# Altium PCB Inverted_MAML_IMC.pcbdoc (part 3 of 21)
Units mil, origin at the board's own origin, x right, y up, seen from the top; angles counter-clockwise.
Board outline 7677.1 x 6771.6 mil, 6 copper layers (Top Layer, Inner1, Inner2, Inner3, Inner4, Bottom Layer), stack 60.7 mil thick; 2732 components, 1531 nets, 7765 pads, 3701 vias.

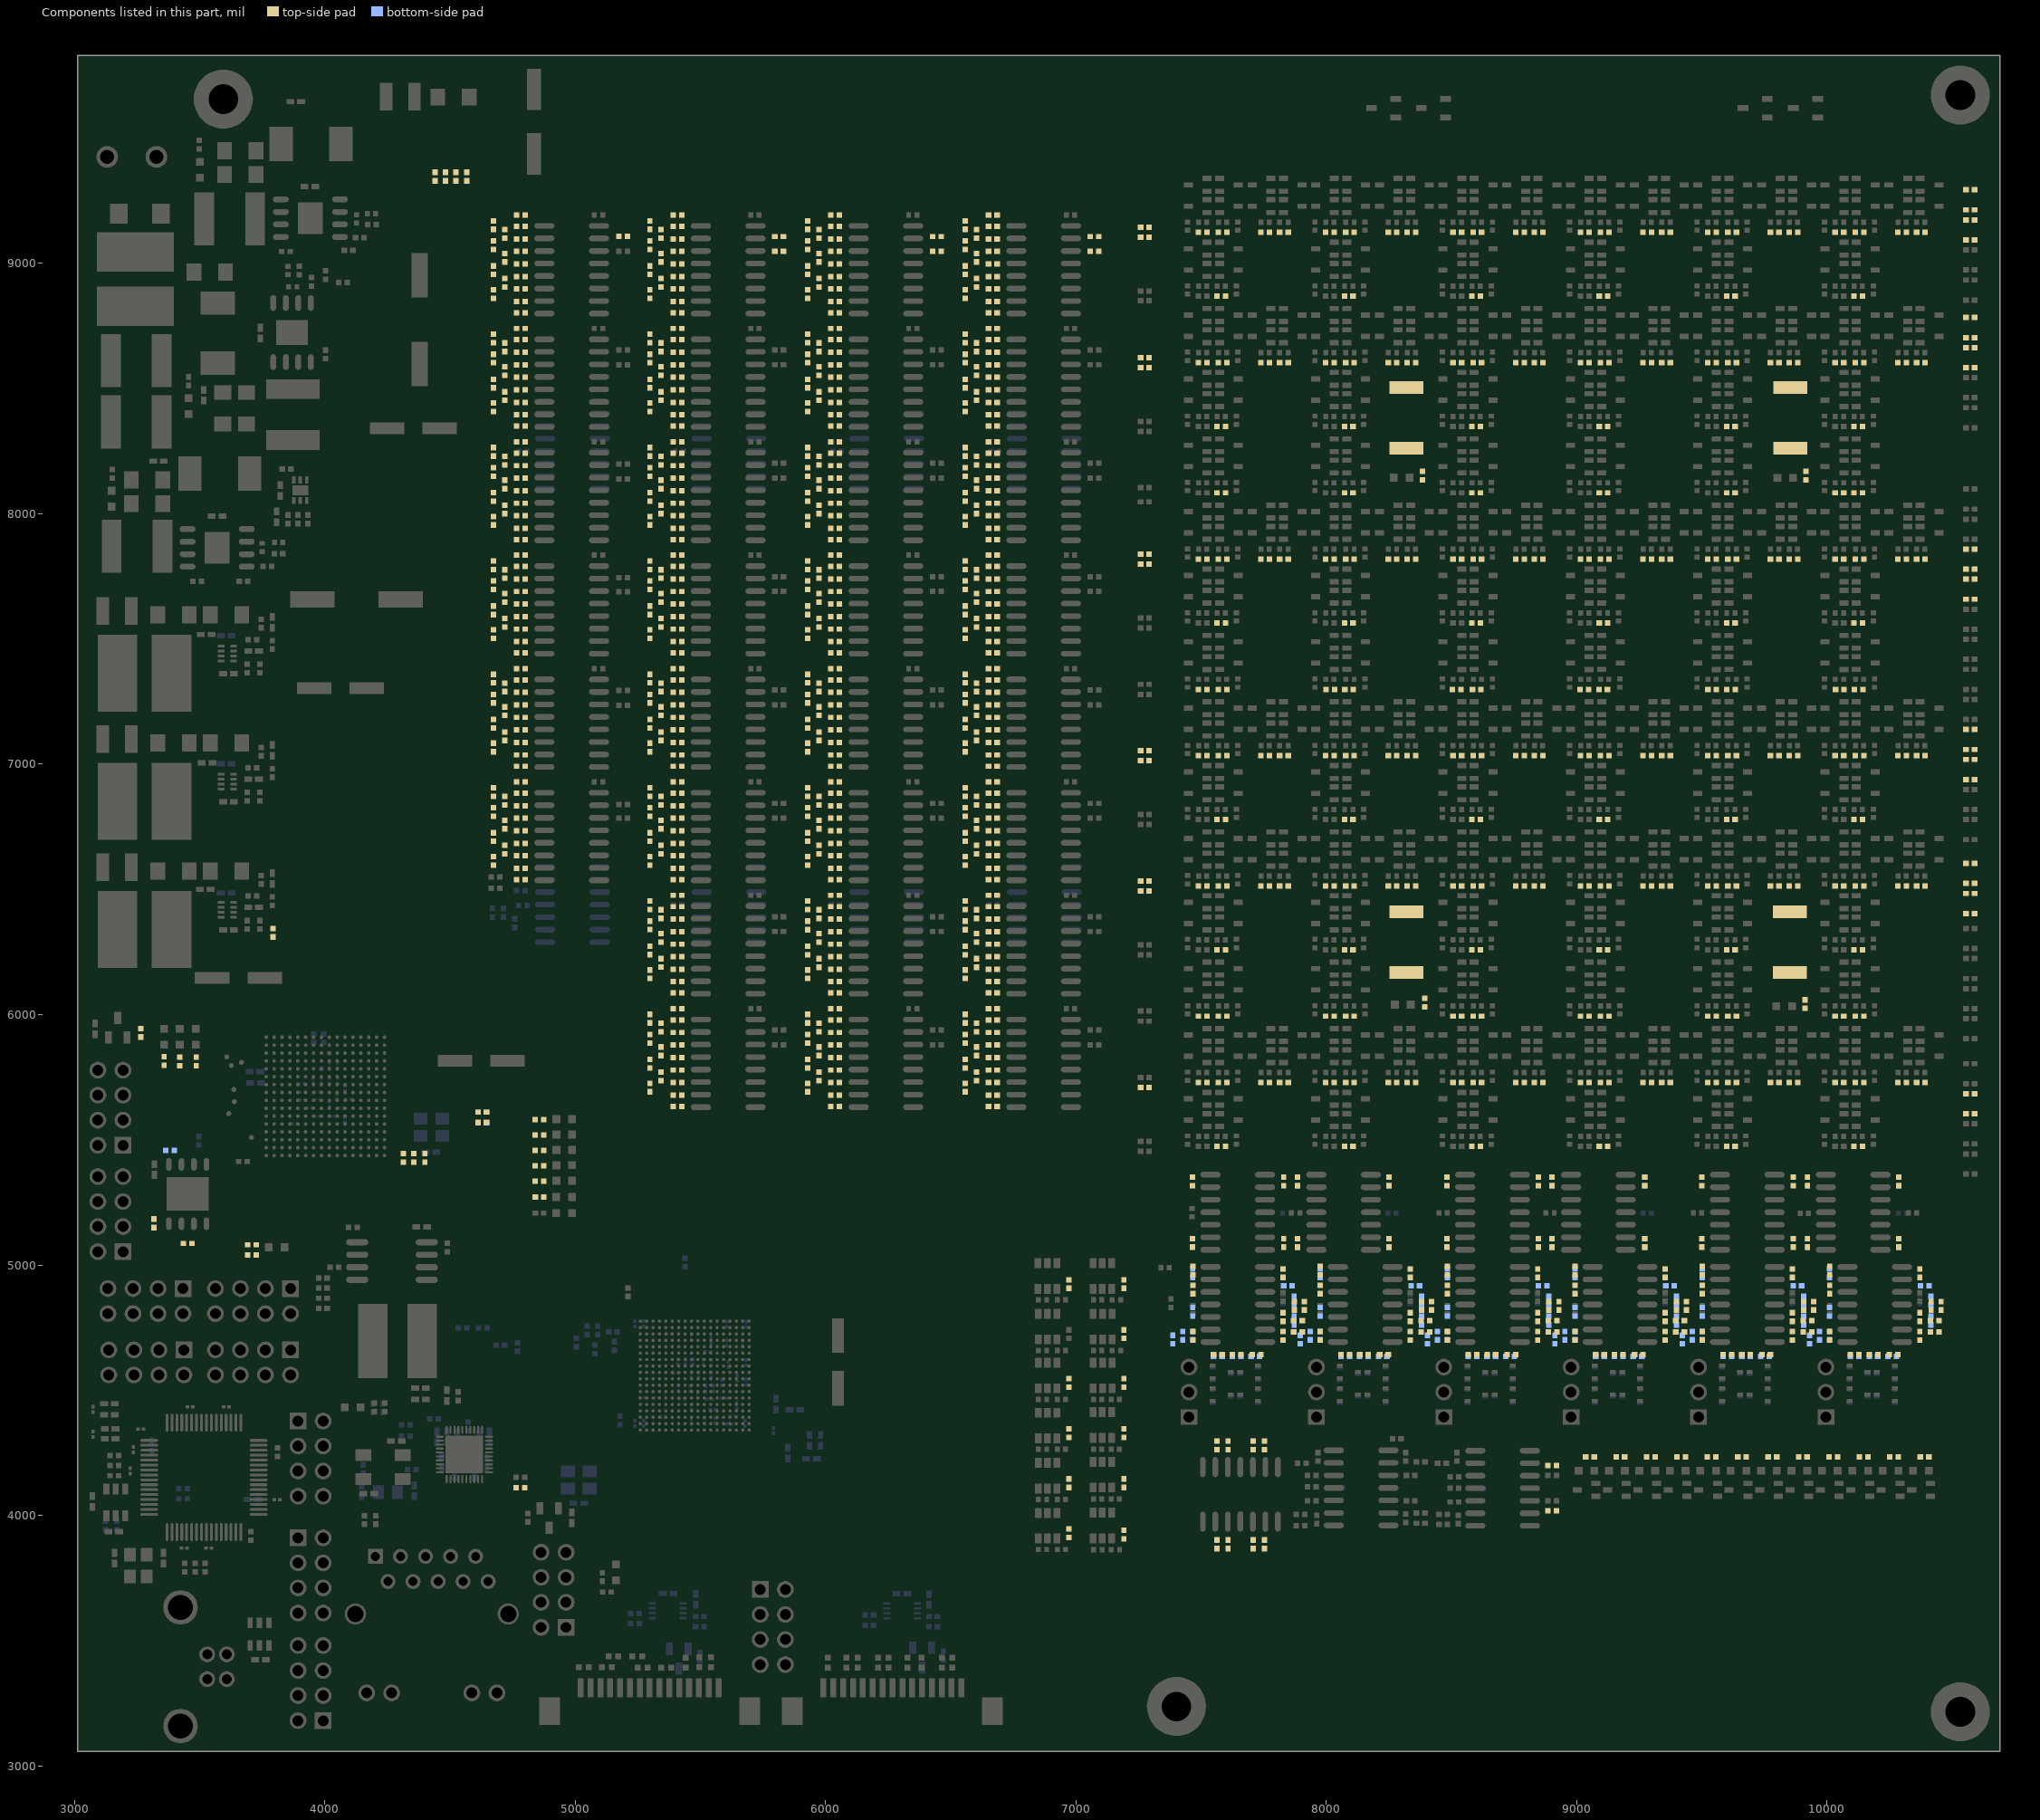
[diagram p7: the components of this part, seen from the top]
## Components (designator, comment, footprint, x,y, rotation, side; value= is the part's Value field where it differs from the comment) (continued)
R1$CBB9/CBB42 "1MΩ" R0402#2 10049.7,8083.7 r180 top
R1$CBB15 "1kΩ" R0402#1 7607.9,3884.5 r270 top
R1$CBB16/CBB1 "20kΩ" R0402#2 4783.8,8395.1 r180 top
R1$CBB16/CBB2 "20kΩ" R0402#2 4783.8,8847.8 r180 top
R1$CBB16/CBB3 "20kΩ" R0402#2 4783.8,7942.3 r180 top
R1$CBB16/CBB4 "20kΩ" R0402#2 4783.8,7489.5 r180 top
R1$CBB16/CBB5 "20kΩ" R0402#2 4783.8,7036.8 r180 top
R1$CBB16/CBB6 "20kΩ" R0402#2 4783.8,6584.1 r180 top
R1$CBB17/CBB1 "20kΩ" R0402#2 5408.8,8847.8 r180 top
R1$CBB17/CBB2 "20kΩ" R0402#2 5408.8,8395.1 r180 top
R1$CBB17/CBB3 "20kΩ" R0402#2 5408.8,7942.3 r180 top
R1$CBB17/CBB4 "20kΩ" R0402#2 5408.8,7489.6 r180 top
R1$CBB17/CBB5 "20kΩ" R0402#2 5408.8,7036.8 r180 top
R1$CBB17/CBB6 "20kΩ" R0402#2 5408.8,6584 r180 top
R1$CBB17/CBB7 "20kΩ" R0402#2 5408.8,6131.3 r180 top
R1$CBB17/CBB8 "20kΩ" R0402#2 5408.8,5678.5 r180 top
R1$CBB18/CBB1 "20kΩ" R0402#3 6038.7,8847.8 r180 top
R1$CBB18/CBB2 "20kΩ" R0402#3 6038.7,8395.1 r180 top
R1$CBB18/CBB3 "20kΩ" R0402#3 6038.7,7942.3 r180 top
R1$CBB18/CBB4 "20kΩ" R0402#3 6038.7,7489.6 r180 top
R1$CBB18/CBB5 "20kΩ" R0402#3 6038.7,7036.8 r180 top
R1$CBB18/CBB6 "20kΩ" R0402#3 6038.7,6584 r180 top
R1$CBB18/CBB7 "20kΩ" R0402#3 6038.7,6131.3 r180 top
R1$CBB18/CBB8 "20kΩ" R0402#3 6038.7,5678.5 r180 top
R1$CBB19/CBB1 "1MΩ" R0402#2 7756.2,9123.7 r180 top
R1$CBB19/CBB2 "1MΩ" R0402#2 7756.2,8603.7 r180 top
R1$CBB19/CBB3 "1MΩ" R0402#2 7756.2,7818.7 r180 top
R1$CBB19/CBB4 "1MΩ" R0402#2 7756.2,7033.7 r180 top
R1$CBB19/CBB5 "1MΩ" R0402#2 7756.2,6513.7 r180 top
R1$CBB19/CBB6 "1MΩ" R0402#2 7756.2,5728.7 r180 top
R1$CBB19/CBB7 "1MΩ" R0402#2 8264.9,9123.7 r180 top
R1$CBB19/CBB8 "1MΩ" R0402#2 8264.9,8603.7 r180 top
R1$CBB19/CBB9 "1MΩ" R0402#2 8264.9,7818.7 r180 top
R1$CBB19/CBB10 "1MΩ" R0402#2 8264.9,7033.7 r180 top
R1$CBB19/CBB11 "1MΩ" R0402#2 8264.9,6513.7 r180 top
R1$CBB19/CBB12 "1MΩ" R0402#2 8264.9,5728.7 r180 top
R1$CBB19/CBB13 "1MΩ" R0402#2 8773.6,9123.7 r180 top
R1$CBB19/CBB14 "1MΩ" R0402#2 8773.6,8603.7 r180 top
R1$CBB19/CBB15 "1MΩ" R0402#2 8773.6,7818.7 r180 top
R1$CBB19/CBB16 "1MΩ" R0402#2 8773.6,7033.7 r180 top
R1$CBB19/CBB17 "1MΩ" R0402#2 8773.6,6513.7 r180 top
R1$CBB19/CBB18 "1MΩ" R0402#2 8773.6,5728.7 r180 top
R1$CBB19/CBB19 "1MΩ" R0402#2 9282.3,9123.7 r180 top
R1$CBB19/CBB20 "1MΩ" R0402#2 9282.3,8603.7 r180 top
R1$CBB19/CBB21 "1MΩ" R0402#2 9282.3,7818.7 r180 top
R1$CBB19/CBB22 "1MΩ" R0402#2 9282.3,7033.7 r180 top
R1$CBB19/CBB23 "1MΩ" R0402#2 9282.3,6513.7 r180 top
R1$CBB19/CBB24 "1MΩ" R0402#2 9282.3,5728.7 r180 top
R1$CBB19/CBB25 "1MΩ" R0402#2 9791,9123.7 r180 top
R1$CBB19/CBB26 "1MΩ" R0402#2 9791,8603.7 r180 top
R1$CBB19/CBB27 "1MΩ" R0402#2 9791,7818.7 r180 top
R1$CBB19/CBB28 "1MΩ" R0402#2 9791,7033.7 r180 top
R1$CBB19/CBB29 "1MΩ" R0402#2 9791,6513.7 r180 top
R1$CBB19/CBB30 "1MΩ" R0402#2 9791,5728.7 r180 top
R1$CBB19/CBB31 "1MΩ" R0402#2 10299.7,9123.7 r180 top
R1$CBB19/CBB32 "1MΩ" R0402#2 10299.7,8603.7 r180 top
R1$CBB19/CBB33 "1MΩ" R0402#2 10299.7,7818.7 r180 top
R1$CBB19/CBB34 "1MΩ" R0402#2 10299.7,7033.7 r180 top
R1$CBB19/CBB35 "1MΩ" R0402#2 10299.7,6513.7 r180 top
R1$CBB19/CBB36 "1MΩ" R0402#2 10299.7,5728.7 r180 top
R1$CBB20/CBB1 "20kΩ" R0402#1 6668.6,8847.8 r180 top
R1$CBB20/CBB2 "20kΩ" R0402#1 6668.6,8395.1 r180 top
R1$CBB20/CBB3 "20kΩ" R0402#1 6668.6,7942.3 r180 top
R1$CBB20/CBB4 "20kΩ" R0402#1 6668.6,7489.6 r180 top
R1$CBB20/CBB5 "20kΩ" R0402#1 6668.6,7036.8 r180 top
R1$CBB20/CBB6 "20kΩ" R0402#1 6668.6,6584 r180 top
R1$CBB20/CBB7 "20kΩ" R0402#1 6668.6,6131.3 r180 top
R1$CBB20/CBB8 "20kΩ" R0402#1 6668.6,5678.5 r180 top
R1$CBB21 "100Ω" R0402#2 7192.1,4723.7 r90 top
R1$CBB22 "470Ω" R0402#1 4858.2,5271.4 r180 top
R1$CBB22/CBB2 "4.7kΩ" R0402#2 4781.8,4110.3 r0 top
R1$CBB23 "10kΩ" R0402#2 3265.9,5927.4 r90 top
R1$CBB49/CBB1 "1MΩ" R0402#2 7506.2,9123.7 r180 top
R1$CBB49/CBB2 "1MΩ" R0402#2 7506.2,8603.7 r180 top
R1$CBB49/CBB3 "1MΩ" R0402#2 7506.2,7818.7 r180 top
R1$CBB49/CBB4 "1MΩ" R0402#2 7506.2,7033.7 r180 top
R1$CBB49/CBB5 "1MΩ" R0402#2 7506.2,6513.7 r180 top
R1$CBB49/CBB6 "1MΩ" R0402#2 7506.2,5728.7 r180 top
R1$CBB49/CBB7 "1MΩ" R0402#2 8014.9,9123.7 r180 top
R1$CBB49/CBB8 "1MΩ" R0402#2 8014.9,8603.7 r180 top
R1$CBB49/CBB9 "1MΩ" R0402#2 8014.9,7818.7 r180 top
R1$CBB49/CBB10 "1MΩ" R0402#2 8014.9,7033.7 r180 top
R1$CBB49/CBB11 "1MΩ" R0402#2 8014.9,6513.7 r180 top
R1$CBB49/CBB12 "1MΩ" R0402#2 8014.9,5728.7 r180 top
R1$CBB49/CBB13 "1MΩ" R0402#2 8523.6,9123.7 r180 top
R1$CBB49/CBB14 "1MΩ" R0402#2 8523.6,8603.7 r180 top
R1$CBB49/CBB15 "1MΩ" R0402#2 8523.6,7818.7 r180 top
R1$CBB49/CBB16 "1MΩ" R0402#2 8523.6,7033.7 r180 top
R1$CBB49/CBB17 "1MΩ" R0402#2 8523.6,6513.7 r180 top
R1$CBB49/CBB18 "1MΩ" R0402#2 8523.6,5728.7 r180 top
R1$CBB49/CBB19 "1MΩ" R0402#2 9032.3,9123.7 r180 top
R1$CBB49/CBB20 "1MΩ" R0402#2 9032.3,8603.7 r180 top
R1$CBB49/CBB21 "1MΩ" R0402#2 9032.3,7818.7 r180 top
R1$CBB49/CBB22 "1MΩ" R0402#2 9032.3,7033.7 r180 top
R1$CBB49/CBB23 "1MΩ" R0402#2 9032.3,6513.7 r180 top
R1$CBB49/CBB24 "1MΩ" R0402#2 9032.3,5728.7 r180 top
R1$CBB49/CBB25 "1MΩ" R0402#2 9541,9123.7 r180 top
R1$CBB49/CBB26 "1MΩ" R0402#2 9541,8603.7 r180 top
R1$CBB49/CBB27 "1MΩ" R0402#2 9541,7818.7 r180 top
R1$CBB49/CBB28 "1MΩ" R0402#2 9541,7033.7 r180 top
R1$CBB49/CBB29 "1MΩ" R0402#2 9541,6513.7 r180 top
R1$CBB49/CBB30 "1MΩ" R0402#2 9541,5728.7 r180 top
R1$CBB49/CBB31 "1MΩ" R0402#2 10049.7,9123.7 r180 top
R1$CBB49/CBB32 "1MΩ" R0402#2 10049.7,8603.7 r180 top
R1$CBB49/CBB33 "1MΩ" R0402#2 10049.7,7818.7 r180 top
R1$CBB49/CBB34 "1MΩ" R0402#2 10049.7,7033.7 r180 top
R1$CBB49/CBB35 "1MΩ" R0402#2 10049.7,6513.7 r180 top
R1$CBB49/CBB36 "1MΩ" R0402#2 10049.7,5728.7 r180 top
R1$CBB49/CBB37 "1MΩ" R0402#2 7506.2,5993.7 r180 top
R1$CBB49/CBB38 "1MΩ" R0402#2 8014.9,5993.7 r180 top
R1$CBB49/CBB39 "1MΩ" R0402#2 8523.6,5993.7 r180 top
R1$CBB49/CBB40 "1MΩ" R0402#2 9032.3,5993.7 r180 top
R1$CBB49/CBB41 "1MΩ" R0402#2 9541,5993.7 r180 top
R1$CBB49/CBB42 "1MΩ" R0402#2 10049.7,5993.7 r180 top
R1$CBB49/CBB43 "330kΩ" R0402#1 7586.2,7298.7 r0 top
R1$CBB49/CBB44 "330kΩ" R0402#1 8091.2,7298.7 r0 top
R1$CBB49/CBB45 "330kΩ" R0402#1 8601.2,7298.7 r0 top
R1$CBB49/CBB46 "330kΩ" R0402#1 9106.2,7298.7 r0 top
R1$CBB49/CBB47 "330kΩ" R0402#1 9616.2,7298.7 r0 top
R1$CBB49/CBB48 "330kΩ" R0402#1 10126.2,7298.7 r0 top
R2 "120Ω" R0402#1 10572.1,9093.7 r180 top
R2$CBB1 "1.2kΩ" R0402#2 7467.1,4717.2 r270 top
R2$CBB2 "1.2kΩ" R0402#2 7975.8,4717.2 r270 top
R2$CBB3 "1.2kΩ" R0402#2 8484.5,4717.2 r270 top
R2$CBB4 "1.2kΩ" R0402#2 8993.2,4717.2 r270 top
R2$CBB5 "1.2kΩ" R0402#2 9501.9,4717.2 r270 top
R2$CBB6 "1.2kΩ" R0402#2 10010.6,4717.2 r270 top
R2$CBB7 "100Ω" R0402#2 6972.1,4328.7 r90 top
R2$CBB8 "1.2kΩ" R0402#2 7641.9,4635.4 r0 bottom
R2$CBB9/CBB1 "1MΩ" R0402#1 7581.2,8868.7 r0 top
R2$CBB9/CBB2 "1MΩ" R0402#1 7581.2,8348.7 r0 top
R2$CBB9/CBB3 "1MΩ" R0402#1 7581.2,7563.7 r0 top
R2$CBB9/CBB4 "1MΩ" R0402#1 7581.2,6778.7 r0 top
R2$CBB9/CBB5 "1MΩ" R0402#1 7581.2,6258.7 r0 top
R2$CBB9/CBB6 "1MΩ" R0402#1 7581.2,5473.7 r0 top
R2$CBB9/CBB7 "1MΩ" R0402#1 8089.9,8868.7 r0 top
R2$CBB9/CBB8 "1MΩ" R0402#1 8089.9,8348.7 r0 top
R2$CBB9/CBB9 "1MΩ" R0402#1 8089.9,7563.7 r0 top
R2$CBB9/CBB10 "1MΩ" R0402#1 8089.9,6778.7 r0 top
R2$CBB9/CBB11 "1MΩ" R0402#1 8089.9,6258.7 r0 top
R2$CBB9/CBB12 "1MΩ" R0402#1 8089.9,5473.7 r0 top
R2$CBB9/CBB13 "1MΩ" R0402#1 8598.6,8868.7 r0 top
R2$CBB9/CBB14 "1MΩ" R0402#1 8598.6,8348.7 r0 top
R2$CBB9/CBB15 "1MΩ" R0402#1 8598.6,7563.7 r0 top
R2$CBB9/CBB16 "1MΩ" R0402#1 8598.6,6778.7 r0 top
R2$CBB9/CBB17 "1MΩ" R0402#1 8598.6,6258.7 r0 top
R2$CBB9/CBB18 "1MΩ" R0402#1 8598.6,5473.7 r0 top
R2$CBB9/CBB19 "1MΩ" R0402#1 9107.3,8868.7 r0 top
R2$CBB9/CBB20 "1MΩ" R0402#1 9107.3,8348.7 r0 top
R2$CBB9/CBB21 "1MΩ" R0402#1 9107.3,7563.7 r0 top
R2$CBB9/CBB22 "1MΩ" R0402#1 9107.3,6778.7 r0 top
R2$CBB9/CBB23 "1MΩ" R0402#1 9107.3,6258.7 r0 top
R2$CBB9/CBB24 "1MΩ" R0402#1 9107.3,5473.7 r0 top
R2$CBB9/CBB25 "1MΩ" R0402#1 9616,8868.7 r0 top
R2$CBB9/CBB26 "1MΩ" R0402#1 9616,8348.7 r0 top
R2$CBB9/CBB27 "1MΩ" R0402#1 9616,7563.7 r0 top
R2$CBB9/CBB28 "1MΩ" R0402#1 9616,6778.7 r0 top
R2$CBB9/CBB29 "1MΩ" R0402#1 9616,6258.7 r0 top
R2$CBB9/CBB30 "1MΩ" R0402#1 9616,5473.7 r0 top
R2$CBB9/CBB31 "1MΩ" R0402#1 10124.7,8868.7 r0 top
R2$CBB9/CBB32 "1MΩ" R0402#1 10124.7,8348.7 r0 top
R2$CBB9/CBB33 "1MΩ" R0402#1 10124.7,7563.7 r0 top
R2$CBB9/CBB34 "1MΩ" R0402#1 10124.7,6778.7 r0 top
R2$CBB9/CBB35 "1MΩ" R0402#1 10124.7,6258.7 r0 top
R2$CBB9/CBB36 "1MΩ" R0402#1 10124.7,5473.7 r0 top
R2$CBB9/CBB37 "1MΩ" R0402#1 7581.2,8083.7 r0 top
R2$CBB9/CBB38 "1MΩ" R0402#1 8089.9,8083.7 r0 top
R2$CBB9/CBB39 "1MΩ" R0402#1 8598.6,8083.7 r0 top
R2$CBB9/CBB40 "1MΩ" R0402#1 9107.3,8083.7 r0 top
R2$CBB9/CBB41 "1MΩ" R0402#1 9616,8083.7 r0 top
R2$CBB9/CBB42 "1MΩ" R0402#1 10124.7,8083.7 r0 top
R2$CBB10 "1.2kΩ" R0402#2 8150.6,4635.4 r0 bottom
R2$CBB11 "1.2kΩ" R0402#2 8659.3,4635.4 r0 bottom
R2$CBB12 "1.2kΩ" R0402#2 9168,4635.4 r0 bottom
R2$CBB13 "1.2kΩ" R0402#2 9676.7,4635.4 r0 bottom
R2$CBB14 "1.2kΩ" R0402#2 10185.4,4635.4 r0 bottom
R2$CBB15 "3.9kΩ" R0402#1 7562.9,3884.5 r270 top
R2$CBB16/CBB1 "10kΩ" R0402#1 4673.8,8700.1 r90 top
R2$CBB16/CBB2 "10kΩ" R0402#2 4673.8,9152.8 r90 top
R2$CBB16/CBB3 "10kΩ" R0402#2 4673.8,8247.3 r90 top
R2$CBB16/CBB4 "10kΩ" R0402#2 4673.8,7794.5 r90 top
R2$CBB16/CBB5 "10kΩ" R0402#3 4673.8,7341.8 r90 top
R2$CBB16/CBB6 "10kΩ" R0402#1 4673.8,6889.1 r90 top
R2$CBB17/CBB1 "10kΩ" R0402#2 5298.8,9152.8 r90 top
R2$CBB17/CBB2 "10kΩ" R0402#1 5298.8,8700.1 r90 top
R2$CBB17/CBB3 "10kΩ" R0402#2 5298.8,8247.3 r90 top
R2$CBB17/CBB4 "10kΩ" R0402#1 5298.8,7794.6 r90 top
R2$CBB17/CBB5 "10kΩ" R0402#3 5298.8,7341.8 r90 top
R2$CBB17/CBB6 "10kΩ" R0402#2 5298.8,6889 r90 top
R2$CBB17/CBB7 "10kΩ" R0402#3 5298.8,6436.3 r90 top
R2$CBB17/CBB8 "10kΩ" R0402#2 5298.8,5983.5 r90 top
R2$CBB18/CBB1 "10kΩ" R0402#2 5928.7,9152.8 r90 top
R2$CBB18/CBB2 "10kΩ" R0402#1 5928.7,8700.1 r90 top
R2$CBB18/CBB3 "10kΩ" R0402#2 5928.7,8247.3 r90 top
R2$CBB18/CBB4 "10kΩ" R0402#1 5928.7,7794.6 r90 top
R2$CBB18/CBB5 "10kΩ" R0402#3 5928.7,7341.8 r90 top
R2$CBB18/CBB6 "10kΩ" R0402#2 5928.7,6889 r90 top
R2$CBB18/CBB7 "10kΩ" R0402#1 5928.7,6436.3 r90 top
R2$CBB18/CBB8 "10kΩ" R0402#2 5928.7,5983.5 r90 top
R2$CBB19/CBB1 "1MΩ" R0402#1 7831.2,9123.7 r0 top
R2$CBB19/CBB2 "1MΩ" R0402#1 7831.2,8603.7 r0 top
R2$CBB19/CBB3 "1MΩ" R0402#1 7831.2,7818.7 r0 top
R2$CBB19/CBB4 "1MΩ" R0402#1 7831.2,7033.7 r0 top
R2$CBB19/CBB5 "1MΩ" R0402#1 7831.2,6513.7 r0 top
R2$CBB19/CBB6 "1MΩ" R0402#1 7831.2,5728.7 r0 top
R2$CBB19/CBB7 "1MΩ" R0402#1 8339.9,9123.7 r0 top
R2$CBB19/CBB8 "1MΩ" R0402#1 8339.9,8603.7 r0 top
R2$CBB19/CBB9 "1MΩ" R0402#1 8339.9,7818.7 r0 top
R2$CBB19/CBB10 "1MΩ" R0402#1 8339.9,7033.7 r0 top
R2$CBB19/CBB11 "1MΩ" R0402#1 8339.9,6513.7 r0 top
R2$CBB19/CBB12 "1MΩ" R0402#1 8339.9,5728.7 r0 top
R2$CBB19/CBB13 "1MΩ" R0402#1 8848.6,9123.7 r0 top
R2$CBB19/CBB14 "1MΩ" R0402#1 8848.6,8603.7 r0 top
R2$CBB19/CBB15 "1MΩ" R0402#1 8848.6,7818.7 r0 top
R2$CBB19/CBB16 "1MΩ" R0402#1 8848.6,7033.7 r0 top
R2$CBB19/CBB17 "1MΩ" R0402#1 8848.6,6513.7 r0 top
R2$CBB19/CBB18 "1MΩ" R0402#1 8848.6,5728.7 r0 top
R2$CBB19/CBB19 "1MΩ" R0402#1 9357.3,9123.7 r0 top
R2$CBB19/CBB20 "1MΩ" R0402#1 9357.3,8603.7 r0 top
R2$CBB19/CBB21 "1MΩ" R0402#1 9357.3,7818.7 r0 top
R2$CBB19/CBB22 "1MΩ" R0402#1 9357.3,7033.7 r0 top
R2$CBB19/CBB23 "1MΩ" R0402#1 9357.3,6513.7 r0 top
R2$CBB19/CBB24 "1MΩ" R0402#1 9357.3,5728.7 r0 top
R2$CBB19/CBB25 "1MΩ" R0402#1 9866,9123.7 r0 top
R2$CBB19/CBB26 "1MΩ" R0402#1 9866,8603.7 r0 top
R2$CBB19/CBB27 "1MΩ" R0402#1 9866,7818.7 r0 top
R2$CBB19/CBB28 "1MΩ" R0402#1 9866,7033.7 r0 top
R2$CBB19/CBB29 "1MΩ" R0402#1 9866,6513.7 r0 top
R2$CBB19/CBB30 "1MΩ" R0402#1 9866,5728.7 r0 top
R2$CBB19/CBB31 "1MΩ" R0402#1 10374.7,9123.7 r0 top
R2$CBB19/CBB32 "1MΩ" R0402#1 10374.7,8603.7 r0 top
R2$CBB19/CBB33 "1MΩ" R0402#1 10374.7,7818.7 r0 top
R2$CBB19/CBB34 "1MΩ" R0402#1 10374.7,7033.7 r0 top
R2$CBB19/CBB35 "1MΩ" R0402#1 10374.7,6513.7 r0 top
R2$CBB19/CBB36 "1MΩ" R0402#1 10374.7,5728.7 r0 top
R2$CBB20/CBB1 "10kΩ" R0402#2 6558.6,9152.8 r90 top
R2$CBB20/CBB2 "10kΩ" R0402#1 6558.6,8700.1 r90 top
R2$CBB20/CBB3 "10kΩ" R0402#2 6558.6,8247.3 r90 top
R2$CBB20/CBB4 "10kΩ" R0402#1 6558.6,7794.6 r90 top
R2$CBB20/CBB5 "10kΩ" R0402#3 6558.6,7341.8 r90 top
R2$CBB20/CBB6 "10kΩ" R0402#2 6558.6,6889 r90 top
R2$CBB20/CBB7 "10kΩ" R0402#1 6558.6,6436.3 r90 top
R2$CBB20/CBB8 "10kΩ" R0402#2 6558.6,5983.5 r90 top
R2$CBB21 "100Ω" R0402#2 7192.1,4328.7 r90 top
R2$CBB23 "10kΩ" R0402#3 3793.9,6327 r90 top
R2$CBB49/CBB1 "1MΩ" R0402#1 7586.2,9123.7 r0 top
R2$CBB49/CBB2 "1MΩ" R0402#1 7586.2,8603.7 r0 top
R2$CBB49/CBB3 "1MΩ" R0402#1 7586.2,7818.7 r0 top
R2$CBB49/CBB4 "1MΩ" R0402#1 7586.2,7033.7 r0 top
R2$CBB49/CBB5 "1MΩ" R0402#1 7586.2,6513.7 r0 top
R2$CBB49/CBB6 "1MΩ" R0402#1 7586.2,5728.7 r0 top
R2$CBB49/CBB7 "1MΩ" R0402#1 8094.9,9123.7 r0 top
R2$CBB49/CBB8 "1MΩ" R0402#1 8094.9,8603.7 r0 top
R2$CBB49/CBB9 "1MΩ" R0402#1 8094.9,7818.7 r0 top
R2$CBB49/CBB10 "1MΩ" R0402#1 8094.9,7033.7 r0 top
R2$CBB49/CBB11 "1MΩ" R0402#1 8094.9,6513.7 r0 top
R2$CBB49/CBB12 "1MΩ" R0402#1 8094.9,5728.7 r0 top
R2$CBB49/CBB13 "1MΩ" R0402#1 8603.6,9123.7 r0 top
R2$CBB49/CBB14 "1MΩ" R0402#1 8603.6,8603.7 r0 top
R2$CBB49/CBB15 "1MΩ" R0402#1 8603.6,7818.7 r0 top
R2$CBB49/CBB16 "1MΩ" R0402#1 8603.6,7033.7 r0 top
R2$CBB49/CBB17 "1MΩ" R0402#1 8603.6,6513.7 r0 top
R2$CBB49/CBB18 "1MΩ" R0402#1 8603.6,5728.7 r0 top
R2$CBB49/CBB19 "1MΩ" R0402#1 9112.3,9123.7 r0 top
R2$CBB49/CBB20 "1MΩ" R0402#1 9112.3,8603.7 r0 top
R2$CBB49/CBB21 "1MΩ" R0402#1 9112.3,7818.7 r0 top
R2$CBB49/CBB22 "1MΩ" R0402#1 9112.3,7033.7 r0 top
R2$CBB49/CBB23 "1MΩ" R0402#1 9112.3,6513.7 r0 top
R2$CBB49/CBB24 "1MΩ" R0402#1 9112.3,5728.7 r0 top
R2$CBB49/CBB25 "1MΩ" R0402#1 9621,9123.7 r0 top
R2$CBB49/CBB26 "1MΩ" R0402#1 9621,8603.7 r0 top
R2$CBB49/CBB27 "1MΩ" R0402#1 9621,7818.7 r0 top
R2$CBB49/CBB28 "1MΩ" R0402#1 9621,7033.7 r0 top
R2$CBB49/CBB29 "1MΩ" R0402#1 9621,6513.7 r0 top
R2$CBB49/CBB30 "1MΩ" R0402#1 9621,5728.7 r0 top
R2$CBB49/CBB31 "1MΩ" R0402#1 10129.7,9123.7 r0 top
R2$CBB49/CBB32 "1MΩ" R0402#1 10129.7,8603.7 r0 top
R2$CBB49/CBB33 "1MΩ" R0402#1 10129.7,7818.7 r0 top
R2$CBB49/CBB34 "1MΩ" R0402#1 10129.7,7033.7 r0 top
R2$CBB49/CBB35 "1MΩ" R0402#1 10129.7,6513.7 r0 top
R2$CBB49/CBB36 "1MΩ" R0402#1 10129.7,5728.7 r0 top
R2$CBB49/CBB37 "1MΩ" R0402#1 7586.2,5993.7 r0 top
R2$CBB49/CBB38 "1MΩ" R0402#1 8094.9,5993.7 r0 top
R2$CBB49/CBB39 "1MΩ" R0402#1 8603.6,5993.7 r0 top
R2$CBB49/CBB40 "1MΩ" R0402#1 9112.3,5993.7 r0 top
R2$CBB49/CBB41 "1MΩ" R0402#1 9621,5993.7 r0 top
R2$CBB49/CBB42 "1MΩ" R0402#1 10129.7,5993.7 r0 top
R3 "68Ω" R0402#3 7275.6,9103.9 r0 top
R3$CBB1 "910Ω" R0402#2 7827.1,4717.2 r270 top
R3$CBB2 "910Ω" R0402#2 8335.8,4717.2 r270 top
R3$CBB3 "910Ω" R0402#2 8844.5,4717.2 r270 top
R3$CBB4 "910Ω" R0402#2 9353.2,4717.2 r270 top
R3$CBB5 "910Ω" R0402#2 9861.9,4717.2 r270 top
R3$CBB6 "910Ω" R0402#2 10370.6,4717.2 r270 top
R3$CBB7 "100Ω" R0402#2 6972.1,4528.7 r90 top
R3$CBB8 "910Ω" R0402#1 7466.9,4717.6 r270 bottom
R3$CBB9 "100Ω" R0402#2 7885.3,5333.4 r270 top
R3$CBB10 "910Ω" R0402#1 7975.6,4717.6 r270 bottom
R3$CBB11 "910Ω" R0402#1 8484.3,4717.6 r270 bottom
R3$CBB12 "910Ω" R0402#1 8993,4717.6 r270 bottom
R3$CBB13 "910Ω" R0402#1 9501.7,4717.6 r270 bottom
R3$CBB14 "910Ω" R0402#1 10010.4,4717.6 r270 bottom
R3$CBB15 "3.9kΩ" R0402#1 7707.9,3884.5 r270 top
R3$CBB16/CBB1 "20kΩ" R0402#2 4783.8,8445.1 r180 top
R3$CBB16/CBB2 "20kΩ" R0402#2 4783.8,8897.8 r180 top
R3$CBB16/CBB3 "20kΩ" R0402#2 4783.8,7992.3 r180 top
R3$CBB16/CBB4 "20kΩ" R0402#2 4783.8,7539.5 r180 top
R3$CBB16/CBB5 "20kΩ" R0402#2 4783.8,7086.8 r180 top
R3$CBB16/CBB6 "20kΩ" R0402#2 4783.8,6634.1 r180 top
R3$CBB17/CBB1 "20kΩ" R0402#2 5408.8,8897.8 r180 top
R3$CBB17/CBB2 "20kΩ" R0402#2 5408.8,8445.1 r180 top
R3$CBB17/CBB3 "20kΩ" R0402#2 5408.8,7992.3 r180 top
R3$CBB17/CBB4 "20kΩ" R0402#2 5408.8,7539.6 r180 top
R3$CBB17/CBB5 "20kΩ" R0402#2 5408.8,7086.8 r180 top
R3$CBB17/CBB6 "20kΩ" R0402#2 5408.8,6634 r180 top
R3$CBB17/CBB7 "20kΩ" R0402#2 5408.8,6181.3 r180 top
R3$CBB17/CBB8 "20kΩ" R0402#2 5408.8,5728.5 r180 top
R3$CBB18/CBB1 "20kΩ" R0402#3 6038.7,8897.8 r180 top
R3$CBB18/CBB2 "20kΩ" R0402#3 6038.7,8445.1 r180 top
R3$CBB18/CBB3 "20kΩ" R0402#3 6038.7,7992.3 r180 top
R3$CBB18/CBB4 "20kΩ" R0402#3 6038.7,7539.6 r180 top
R3$CBB18/CBB5 "20kΩ" R0402#3 6038.7,7086.8 r180 top
R3$CBB18/CBB6 "20kΩ" R0402#3 6038.7,6634 r180 top
R3$CBB18/CBB7 "20kΩ" R0402#3 6038.7,6181.3 r180 top
R3$CBB18/CBB8 "20kΩ" R0402#3 6038.7,5728.5 r180 top
R3$CBB19 "100Ω" R0402#1 7885.3,5088.4 r90 bottom
R3$CBB20/CBB1 "20kΩ" R0402#1 6668.6,8897.8 r180 top
R3$CBB20/CBB2 "20kΩ" R0402#1 6668.6,8445.1 r180 top
R3$CBB20/CBB3 "20kΩ" R0402#1 6668.6,7992.3 r180 top
R3$CBB20/CBB4 "20kΩ" R0402#1 6668.6,7539.6 r180 top
R3$CBB20/CBB5 "20kΩ" R0402#1 6668.6,7086.8 r180 top
R3$CBB20/CBB6 "20kΩ" R0402#1 6668.6,6634 r180 top
R3$CBB20/CBB7 "20kΩ" R0402#1 6668.6,6181.3 r180 top
R3$CBB20/CBB8 "20kΩ" R0402#1 6668.6,5728.5 r180 top
R3$CBB21 "100Ω" R0402#2 7192.1,4528.7 r90 top
R3$CBB23 "10kΩ" R0402#2 4356.1,5427.5 r270 top
R3$CBB49 "100Ω" R0402#2 7465.3,5333.4 r270 top
R3$CBB49/CBB43 "330kΩ" R0402#2 7506.2,7298.7 r180 top
R3$CBB49/CBB44 "330kΩ" R0402#2 8016.2,7298.7 r180 top
R3$CBB49/CBB45 "330kΩ" R0402#2 8521.2,7298.7 r180 top
R3$CBB49/CBB46 "330kΩ" R0402#2 9031.2,7298.7 r180 top
R3$CBB49/CBB47 "330kΩ" R0402#2 9541.2,7298.7 r180 top
R3$CBB49/CBB48 "330kΩ" R0402#2 10051.2,7298.7 r180 top
R4 "120Ω" R0402#1 10572.1,9173.7 r180 top
R4$CBB1 "1kΩ" R0402#2 7467.1,4902.2 r270 top
R4$CBB2 "1kΩ" R0402#2 7975.8,4902.2 r270 top
R4$CBB3 "1kΩ" R0402#2 8484.5,4902.2 r270 top
R4$CBB4 "1kΩ" R0402#2 8993.2,4902.2 r270 top
R4$CBB5 "1kΩ" R0402#2 9501.9,4902.2 r270 top
R4$CBB6 "1kΩ" R0402#2 10010.6,4902.2 r270 top
R4$CBB7 "100Ω" R0402#2 6972.1,3928.7 r90 top
R4$CBB8 "1kΩ" R0402#1 7871.9,4857.6 r270 bottom
R4$CBB9 "100Ω" R0402#1 7885.3,5088.4 r90 top
R4$CBB10 "1kΩ" R0402#1 8380.6,4857.6 r270 bottom
R4$CBB11 "1kΩ" R0402#1 8889.3,4857.6 r270 bottom
R4$CBB12 "1kΩ" R0402#1 9398,4857.6 r270 bottom
R4$CBB13 "1kΩ" R0402#1 9906.7,4857.6 r270 bottom
R4$CBB14 "1kΩ" R0402#1 10415.4,4857.6 r270 bottom
R4$CBB15 "3.9kΩ" R0402#2 7752.9,4279.5 r90 top
R4$CBB16/CBB1 "20kΩ" R0402#2 4783.8,8495.1 r180 top
R4$CBB16/CBB2 "20kΩ" R0402#2 4783.8,8947.8 r180 top
R4$CBB16/CBB3 "20kΩ" R0402#2 4783.8,8042.3 r180 top
R4$CBB16/CBB4 "20kΩ" R0402#2 4783.8,7589.5 r180 top
R4$CBB16/CBB5 "20kΩ" R0402#2 4783.8,7136.8 r180 top
R4$CBB16/CBB6 "20kΩ" R0402#2 4783.8,6684.1 r180 top
R4$CBB17/CBB1 "20kΩ" R0402#2 5408.8,8947.8 r180 top
R4$CBB17/CBB2 "20kΩ" R0402#2 5408.8,8495.1 r180 top
R4$CBB17/CBB3 "20kΩ" R0402#2 5408.8,8042.3 r180 top
R4$CBB17/CBB4 "20kΩ" R0402#2 5408.8,7589.6 r180 top
R4$CBB17/CBB5 "20kΩ" R0402#2 5408.8,7136.8 r180 top
R4$CBB17/CBB6 "20kΩ" R0402#2 5408.8,6684 r180 top
R4$CBB17/CBB7 "20kΩ" R0402#2 5408.8,6231.3 r180 top
R4$CBB17/CBB8 "20kΩ" R0402#2 5408.8,5778.5 r180 top
R4$CBB18/CBB1 "20kΩ" R0402#3 6038.7,8947.8 r180 top
R4$CBB18/CBB2 "20kΩ" R0402#3 6038.7,8495.1 r180 top
R4$CBB18/CBB3 "20kΩ" R0402#3 6038.7,8042.3 r180 top
R4$CBB18/CBB4 "20kΩ" R0402#3 6038.7,7589.6 r180 top
R4$CBB18/CBB5 "20kΩ" R0402#3 6038.7,7136.8 r180 top
R4$CBB18/CBB6 "20kΩ" R0402#3 6038.7,6684 r180 top
R4$CBB18/CBB7 "20kΩ" R0402#3 6038.7,6231.3 r180 top
R4$CBB18/CBB8 "20kΩ" R0402#3 6038.7,5778.5 r180 top
R4$CBB19 "100Ω" R0402#2 7885.3,5333.4 r270 bottom
R4$CBB20/CBB1 "20kΩ" R0402#1 6668.6,8947.8 r180 top
R4$CBB20/CBB2 "20kΩ" R0402#1 6668.6,8495.1 r180 top
R4$CBB20/CBB3 "20kΩ" R0402#1 6668.6,8042.3 r180 top
R4$CBB20/CBB4 "20kΩ" R0402#1 6668.6,7589.6 r180 top
R4$CBB20/CBB5 "20kΩ" R0402#1 6668.6,7136.8 r180 top
R4$CBB20/CBB6 "20kΩ" R0402#1 6668.6,6684 r180 top
R4$CBB20/CBB7 "20kΩ" R0402#1 6668.6,6231.3 r180 top
R4$CBB20/CBB8 "20kΩ" R0402#1 6668.6,5778.5 r180 top
R4$CBB21 "100Ω" R0402#2 7192.1,3923.7 r90 top
R4$CBB23 "10kΩ" R0402#2 4400.3,5427.5 r270 top
R4$CBB49 "100Ω" R0402#1 7465.3,5088.4 r90 top
R5 "120Ω" R0402#1 10572.1,9213.7 r180 top
R5$CBB1 "1kΩ" R0402#2 7467.1,4977.2 r270 top
R5$CBB2 "1kΩ" R0402#2 7975.8,4977.2 r270 top
R5$CBB3 "1kΩ" R0402#2 8484.5,4977.2 r270 top
R5$CBB4 "1kΩ" R0402#2 8993.2,4977.2 r270 top
R5$CBB5 "1kΩ" R0402#2 9501.9,4977.2 r270 top
R5$CBB6 "1kΩ" R0402#2 10010.6,4977.2 r270 top
R5$CBB7 "100Ω" R0402#2 6972.1,4128.7 r90 top
R5$CBB8 "1kΩ" R0402#2 7846.9,4917.6 r0 bottom
R5$CBB9 "100Ω" R0402#1 8250.3,5088.4 r90 top
R5$CBB10 "1kΩ" R0402#2 8355.6,4917.6 r0 bottom
R5$CBB11 "1kΩ" R0402#2 8864.3,4917.6 r0 bottom
R5$CBB12 "1kΩ" R0402#2 9373,4917.6 r0 bottom
R5$CBB13 "1kΩ" R0402#2 9881.7,4917.6 r0 bottom
R5$CBB14 "1kΩ" R0402#2 10390.4,4917.6 r0 bottom
R5$CBB15 "1kΩ" R0402#1 7752.9,3884.5 r270 top
R5$CBB16/CBB1 "20kΩ" R0402#2 4783.8,8545.1 r180 top
R5$CBB16/CBB2 "20kΩ" R0402#2 4783.8,8997.8 r180 top
R5$CBB16/CBB3 "20kΩ" R0402#2 4783.8,8092.3 r180 top
R5$CBB16/CBB4 "20kΩ" R0402#2 4783.8,7639.5 r180 top
R5$CBB16/CBB5 "20kΩ" R0402#2 4783.8,7186.8 r180 top
R5$CBB16/CBB6 "20kΩ" R0402#2 4783.8,6734.1 r180 top
R5$CBB17/CBB1 "20kΩ" R0402#2 5408.8,8997.8 r180 top
R5$CBB17/CBB2 "20kΩ" R0402#2 5408.8,8545.1 r180 top
R5$CBB17/CBB3 "20kΩ" R0402#2 5408.8,8092.3 r180 top
R5$CBB17/CBB4 "20kΩ" R0402#2 5408.8,7639.6 r180 top
R5$CBB17/CBB5 "20kΩ" R0402#2 5408.8,7186.8 r180 top
R5$CBB17/CBB6 "20kΩ" R0402#2 5408.8,6734 r180 top
R5$CBB17/CBB7 "20kΩ" R0402#2 5408.8,6281.3 r180 top
R5$CBB17/CBB8 "20kΩ" R0402#2 5408.8,5828.5 r180 top
R5$CBB18/CBB1 "20kΩ" R0402#3 6038.7,8997.8 r180 top
R5$CBB18/CBB2 "20kΩ" R0402#3 6038.7,8545.1 r180 top
R5$CBB18/CBB3 "20kΩ" R0402#3 6038.7,8092.3 r180 top
R5$CBB18/CBB4 "20kΩ" R0402#3 6038.7,7639.6 r180 top
R5$CBB18/CBB5 "20kΩ" R0402#3 6038.7,7186.8 r180 top
R5$CBB18/CBB6 "20kΩ" R0402#3 6038.7,6734 r180 top
R5$CBB18/CBB7 "20kΩ" R0402#3 6038.7,6281.3 r180 top
R5$CBB18/CBB8 "20kΩ" R0402#3 6038.7,5828.5 r180 top
R5$CBB19 "100Ω" R0402#2 8250.3,5333.4 r270 bottom
R5$CBB20/CBB1 "20kΩ" R0402#1 6668.6,8997.8 r180 top
R5$CBB20/CBB2 "20kΩ" R0402#1 6668.6,8545.1 r180 top
R5$CBB20/CBB3 "20kΩ" R0402#1 6668.6,8092.3 r180 top
R5$CBB20/CBB4 "20kΩ" R0402#1 6668.6,7639.6 r180 top
R5$CBB20/CBB5 "20kΩ" R0402#1 6668.6,7186.8 r180 top
R5$CBB20/CBB6 "20kΩ" R0402#1 6668.6,6734 r180 top
R5$CBB20/CBB7 "20kΩ" R0402#1 6668.6,6281.3 r180 top
R5$CBB20/CBB8 "20kΩ" R0402#1 6668.6,5828.5 r180 top
R5$CBB21 "100Ω" R0402#2 7192.1,4128.7 r90 top
R5$CBB23 "10kΩ" R0402#1 3318.1,5166.5 r90 top
R5$CBB49 "100Ω" R0402#1 7830.3,5088.4 r90 top
R6 "68Ω" R0402#3 7275.6,9144.1 r0 top
R6$CBB1 "1kΩ" R0402#2 7887.1,4732.2 r0 top
R6$CBB2 "1kΩ" R0402#2 8395.8,4732.2 r0 top
R6$CBB3 "1kΩ" R0402#2 8904.5,4732.2 r0 top
R6$CBB4 "1kΩ" R0402#2 9413.2,4732.2 r0 top
R6$CBB5 "1kΩ" R0402#2 9921.9,4732.2 r0 top
R6$CBB6 "1kΩ" R0402#2 10430.6,4732.2 r0 top
R6$CBB7 "100Ω" R0402#2 6972.1,4923.7 r90 top
R6$CBB8 "1kΩ" R0402#1 7426.9,4717.6 r270 bottom
R6$CBB9 "100Ω" R0402#2 8250.3,5333.4 r270 top
R6$CBB10 "1kΩ" R0402#1 7935.6,4717.6 r270 bottom
R6$CBB11 "1kΩ" R0402#1 8444.3,4717.6 r270 bottom
R6$CBB12 "1kΩ" R0402#1 8953,4717.6 r270 bottom
R6$CBB13 "1kΩ" R0402#1 9461.7,4717.6 r270 bottom
R6$CBB14 "1kΩ" R0402#1 9970.4,4717.6 r270 bottom
R6$CBB15 "3.9kΩ" R0402#2 7562.9,4279.5 r90 top
R6$CBB16/CBB1 "20kΩ" R0402#2 4783.8,8595.1 r180 top
R6$CBB16/CBB2 "20kΩ" R0402#2 4783.8,9047.8 r180 top
R6$CBB16/CBB3 "20kΩ" R0402#2 4783.8,8142.3 r180 top
R6$CBB16/CBB4 "20kΩ" R0402#2 4783.8,7689.5 r180 top
R6$CBB16/CBB5 "20kΩ" R0402#2 4783.8,7236.8 r180 top
R6$CBB16/CBB6 "20kΩ" R0402#2 4783.8,6784.1 r180 top
R6$CBB17/CBB1 "20kΩ" R0402#2 5408.8,9047.8 r180 top
R6$CBB17/CBB2 "20kΩ" R0402#2 5408.8,8595.1 r180 top
R6$CBB17/CBB3 "20kΩ" R0402#2 5408.8,8142.3 r180 top
R6$CBB17/CBB4 "20kΩ" R0402#2 5408.8,7689.6 r180 top
R6$CBB17/CBB5 "20kΩ" R0402#2 5408.8,7236.8 r180 top
R6$CBB17/CBB6 "20kΩ" R0402#2 5408.8,6784 r180 top
R6$CBB17/CBB7 "20kΩ" R0402#2 5408.8,6331.3 r180 top
R6$CBB17/CBB8 "20kΩ" R0402#2 5408.8,5878.5 r180 top
R6$CBB18/CBB1 "20kΩ" R0402#3 6038.7,9047.8 r180 top
R6$CBB18/CBB2 "20kΩ" R0402#3 6038.7,8595.1 r180 top
R6$CBB18/CBB3 "20kΩ" R0402#3 6038.7,8142.3 r180 top
R6$CBB18/CBB4 "20kΩ" R0402#3 6038.7,7689.6 r180 top
R6$CBB18/CBB5 "20kΩ" R0402#3 6038.7,7236.8 r180 top
R6$CBB18/CBB6 "20kΩ" R0402#3 6038.7,6784 r180 top
R6$CBB18/CBB7 "20kΩ" R0402#3 6038.7,6331.3 r180 top
R6$CBB18/CBB8 "20kΩ" R0402#3 6038.7,5878.5 r180 top
R6$CBB19 "100Ω" R0402#1 8250.3,5088.4 r90 bottom
R6$CBB20/CBB1 "20kΩ" R0402#1 6668.6,9047.8 r180 top
R6$CBB20/CBB2 "20kΩ" R0402#1 6668.6,8595.1 r180 top
R6$CBB20/CBB3 "20kΩ" R0402#1 6668.6,8142.3 r180 top
R6$CBB20/CBB4 "20kΩ" R0402#1 6668.6,7689.6 r180 top
R6$CBB20/CBB5 "20kΩ" R0402#1 6668.6,7236.8 r180 top
R6$CBB20/CBB6 "20kΩ" R0402#1 6668.6,6784 r180 top
R6$CBB20/CBB7 "20kΩ" R0402#1 6668.6,6331.3 r180 top
R6$CBB20/CBB8 "20kΩ" R0402#1 6668.6,5878.5 r180 top
R6$CBB21 "100Ω" R0402#2 7192.1,4923.7 r90 top
R6$CBB23 "10kΩ" R0402#2 4629.2,5610.2 r0 top
R6$CBB49 "100Ω" R0402#2 7830.3,5333.4 r270 top
R7 "120Ω" R0402#1 10572.1,9293.7 r180 top
R7$CBB1 "1kΩ" R0402#2 7887.1,4777.2 r0 top
R7$CBB2 "1kΩ" R0402#2 8395.8,4777.2 r0 top
R7$CBB3 "1kΩ" R0402#2 8904.5,4777.2 r0 top
R7$CBB4 "1kΩ" R0402#2 9413.2,4777.2 r0 top
R7$CBB5 "1kΩ" R0402#2 9921.9,4777.2 r0 top
R7$CBB6 "1kΩ" R0402#2 10430.6,4777.2 r0 top
R7$CBB8 "1kΩ" R0402#2 7387.1,4702.2 r270 bottom
R7$CBB9 "100Ω" R0402#2 8902.1,5333.4 r270 top
R7$CBB10 "1kΩ" R0402#2 7895.8,4702.2 r270 bottom
R7$CBB11 "1kΩ" R0402#2 8404.5,4702.2 r270 bottom
R7$CBB12 "1kΩ" R0402#2 8913.2,4702.2 r270 bottom
R7$CBB13 "1kΩ" R0402#2 9421.9,4702.2 r270 bottom
R7$CBB14 "1kΩ" R0402#2 9930.6,4702.2 r270 bottom
R7$CBB15 "3.9kΩ" R0402#2 8902.1,4018.7 r0 top
R7$CBB16/CBB1 "20kΩ" R0402#2 4783.8,8645.1 r180 top
R7$CBB16/CBB2 "20kΩ" R0402#2 4783.8,9097.8 r180 top
R7$CBB16/CBB3 "20kΩ" R0402#2 4783.8,8192.3 r180 top
R7$CBB16/CBB4 "20kΩ" R0402#2 4783.8,7739.5 r180 top
R7$CBB16/CBB5 "20kΩ" R0402#2 4783.8,7286.8 r180 top
R7$CBB16/CBB6 "20kΩ" R0402#2 4783.8,6834.1 r180 top
R7$CBB17/CBB1 "20kΩ" R0402#2 5408.8,9097.8 r180 top
R7$CBB17/CBB2 "20kΩ" R0402#2 5408.8,8645.1 r180 top
R7$CBB17/CBB3 "20kΩ" R0402#2 5408.8,8192.3 r180 top
R7$CBB17/CBB4 "20kΩ" R0402#2 5408.8,7739.6 r180 top
R7$CBB17/CBB5 "20kΩ" R0402#2 5408.8,7286.8 r180 top
R7$CBB17/CBB6 "20kΩ" R0402#2 5408.8,6834 r180 top
R7$CBB17/CBB7 "20kΩ" R0402#2 5408.8,6381.3 r180 top
R7$CBB17/CBB8 "20kΩ" R0402#2 5408.8,5928.5 r180 top
R7$CBB18/CBB1 "20kΩ" R0402#3 6038.7,9097.8 r180 top
R7$CBB18/CBB2 "20kΩ" R0402#3 6038.7,8645.1 r180 top
R7$CBB18/CBB3 "20kΩ" R0402#3 6038.7,8192.3 r180 top
R7$CBB18/CBB4 "20kΩ" R0402#3 6038.7,7739.6 r180 top
R7$CBB18/CBB5 "20kΩ" R0402#3 6038.7,7286.8 r180 top
R7$CBB18/CBB6 "20kΩ" R0402#3 6038.7,6834 r180 top
R7$CBB18/CBB7 "20kΩ" R0402#3 6038.7,6381.3 r180 top
R7$CBB18/CBB8 "20kΩ" R0402#3 6038.7,5928.5 r180 top
R7$CBB19 "100Ω" R0402#1 8902.1,5088.4 r90 bottom
R7$CBB20/CBB1 "20kΩ" R0402#1 6668.6,9097.8 r180 top
R7$CBB20/CBB2 "20kΩ" R0402#1 6668.6,8645.1 r180 top
R7$CBB20/CBB3 "20kΩ" R0402#1 6668.6,8192.3 r180 top
R7$CBB20/CBB4 "20kΩ" R0402#1 6668.6,7739.6 r180 top
R7$CBB20/CBB5 "20kΩ" R0402#1 6668.6,7286.8 r180 top
R7$CBB20/CBB6 "20kΩ" R0402#1 6668.6,6834 r180 top
R7$CBB20/CBB7 "20kΩ" R0402#1 6668.6,6381.3 r180 top
R7$CBB20/CBB8 "20kΩ" R0402#1 6668.6,5928.5 r180 top
R7$CBB23 "10kΩ" R0402#2 4629.2,5610.2 r0 bottom
R7$CBB49 "100Ω" R0402#2 8482.7,5333.4 r270 top
R8 "120Ω" R0402#1 10572.1,8583.7 r180 top
R8$CBB1 "910Ω" R0402#1 7827.1,4792.2 r90 top
R8$CBB2 "910Ω" R0402#1 8335.8,4792.2 r90 top
R8$CBB3 "910Ω" R0402#1 8844.5,4792.2 r90 top
R8$CBB4 "910Ω" R0402#1 9353.2,4792.2 r90 top
R8$CBB5 "910Ω" R0402#1 9861.9,4792.2 r90 top
R8$CBB6 "910Ω" R0402#1 10370.6,4792.2 r90 top
R8$CBB8 "910Ω" R0402#2 7466.9,4812.6 r90 bottom
R8$CBB9 "100Ω" R0402#1 8902.1,5088.4 r90 top
R8$CBB10 "910Ω" R0402#2 7975.6,4812.6 r90 bottom
R8$CBB11 "910Ω" R0402#2 8484.3,4812.6 r90 bottom
R8$CBB12 "910Ω" R0402#2 8993,4812.6 r90 bottom
R8$CBB13 "910Ω" R0402#2 9501.7,4812.6 r90 bottom
R8$CBB14 "910Ω" R0402#2 10010.4,4812.6 r90 bottom
R8$CBB15 "3.9kΩ" R0402#2 8902.1,4198.7 r0 top
R8$CBB16/CBB1 "20kΩ" R0402#2 4783.8,8695.1 r180 top
R8$CBB16/CBB2 "20kΩ" R0402#2 4783.8,9147.8 r180 top
R8$CBB16/CBB3 "20kΩ" R0402#2 4783.8,8242.3 r180 top
R8$CBB16/CBB4 "20kΩ" R0402#2 4783.8,7789.5 r180 top
R8$CBB16/CBB5 "20kΩ" R0402#2 4783.8,7336.8 r180 top
R8$CBB16/CBB6 "20kΩ" R0402#2 4783.8,6884.1 r180 top
R8$CBB17/CBB1 "20kΩ" R0402#2 5408.8,9147.8 r180 top
R8$CBB17/CBB2 "20kΩ" R0402#2 5408.8,8695.1 r180 top
R8$CBB17/CBB3 "20kΩ" R0402#2 5408.8,8242.3 r180 top
R8$CBB17/CBB4 "20kΩ" R0402#2 5408.8,7789.6 r180 top
R8$CBB17/CBB5 "20kΩ" R0402#2 5408.8,7336.8 r180 top
R8$CBB17/CBB6 "20kΩ" R0402#2 5408.8,6884 r180 top
R8$CBB17/CBB7 "20kΩ" R0402#2 5408.8,6431.3 r180 top
R8$CBB17/CBB8 "20kΩ" R0402#2 5408.8,5978.5 r180 top
R8$CBB18/CBB1 "20kΩ" R0402#3 6038.7,9147.8 r180 top
R8$CBB18/CBB2 "20kΩ" R0402#3 6038.7,8695.1 r180 top
R8$CBB18/CBB3 "20kΩ" R0402#3 6038.7,8242.3 r180 top
R8$CBB18/CBB4 "20kΩ" R0402#3 6038.7,7789.6 r180 top
R8$CBB18/CBB5 "20kΩ" R0402#3 6038.7,7336.8 r180 top
R8$CBB18/CBB6 "20kΩ" R0402#3 6038.7,6884 r180 top
R8$CBB18/CBB7 "20kΩ" R0402#3 6038.7,6431.3 r180 top
R8$CBB18/CBB8 "20kΩ" R0402#3 6038.7,5978.5 r180 top
R8$CBB19 "100Ω" R0402#2 8902.1,5333.4 r270 bottom
R8$CBB20/CBB1 "20kΩ" R0402#1 6668.6,9147.8 r180 top
R8$CBB20/CBB2 "20kΩ" R0402#1 6668.6,8695.1 r180 top
R8$CBB20/CBB3 "20kΩ" R0402#1 6668.6,8242.3 r180 top
R8$CBB20/CBB4 "20kΩ" R0402#1 6668.6,7789.6 r180 top
R8$CBB20/CBB5 "20kΩ" R0402#1 6668.6,7336.8 r180 top
R8$CBB20/CBB6 "20kΩ" R0402#1 6668.6,6884 r180 top
R8$CBB20/CBB7 "20kΩ" R0402#1 6668.6,6431.3 r180 top
R8$CBB20/CBB8 "20kΩ" R0402#1 6668.6,5978.5 r180 top
R8$CBB23 "10kΩ" R0402#1 4629.2,5570 r180 top
R8$CBB49 "100Ω" R0402#1 8482.7,5088.4 r90 top
R9 "68Ω" R0402#3 7275.6,8583.9 r0 top
R9$CBB1 "1kΩ" R0402#2 7722.1,4642.2 r0 top
R9$CBB2 "1kΩ" R0402#2 8230.8,4642.2 r0 top
R9$CBB3 "1kΩ" R0402#2 8739.5,4642.2 r0 top
R9$CBB4 "1kΩ" R0402#2 9248.2,4642.2 r0 top
R9$CBB5 "1kΩ" R0402#2 9756.9,4642.2 r0 top
R9$CBB6 "1kΩ" R0402#2 10265.6,4642.2 r0 top
R9$CBB8 "1kΩ" R0402#1 7566.9,4635.4 r180 bottom
R9$CBB9 "100Ω" R0402#1 9272.1,5088.4 r90 top
R9$CBB10 "1kΩ" R0402#1 8075.6,4635.4 r180 bottom
R9$CBB11 "1kΩ" R0402#1 8584.3,4635.4 r180 bottom
R9$CBB12 "1kΩ" R0402#1 9093,4635.4 r180 bottom
R9$CBB13 "1kΩ" R0402#1 9601.7,4635.4 r180 bottom
R9$CBB14 "1kΩ" R0402#1 10110.4,4635.4 r180 bottom
R9$CBB15 "1kΩ" R0402#2 7707.9,4279.5 r90 top
R9$CBB16/CBB1 "20kΩ" R0402#2 4783.8,8740.1 r180 top
R9$CBB16/CBB2 "20kΩ" R0402#2 4783.8,9192.8 r180 top
R9$CBB16/CBB3 "20kΩ" R0402#2 4783.8,8287.3 r180 top
R9$CBB16/CBB4 "20kΩ" R0402#2 4783.8,7834.5 r180 top
R9$CBB16/CBB5 "20kΩ" R0402#2 4783.8,7381.8 r180 top
R9$CBB16/CBB6 "20kΩ" R0402#2 4783.8,6929.1 r180 top
R9$CBB17/CBB1 "20kΩ" R0402#2 5408.8,9192.8 r180 top
R9$CBB17/CBB2 "20kΩ" R0402#2 5408.8,8740.1 r180 top
R9$CBB17/CBB3 "20kΩ" R0402#2 5408.8,8287.3 r180 top
R9$CBB17/CBB4 "20kΩ" R0402#2 5408.8,7834.6 r180 top
R9$CBB17/CBB5 "20kΩ" R0402#2 5408.8,7381.8 r180 top
R9$CBB17/CBB6 "20kΩ" R0402#2 5408.8,6929 r180 top
R9$CBB17/CBB7 "20kΩ" R0402#2 5408.8,6476.3 r180 top
R9$CBB17/CBB8 "20kΩ" R0402#2 5408.8,6023.5 r180 top
R9$CBB18/CBB1 "20kΩ" R0402#3 6038.7,9192.8 r180 top
R9$CBB18/CBB2 "20kΩ" R0402#3 6038.7,8740.1 r180 top
R9$CBB18/CBB3 "20kΩ" R0402#3 6038.7,8287.3 r180 top
R9$CBB18/CBB4 "20kΩ" R0402#3 6038.7,7834.6 r180 top
R9$CBB18/CBB5 "20kΩ" R0402#3 6038.7,7381.8 r180 top
R9$CBB18/CBB6 "20kΩ" R0402#3 6038.7,6929 r180 top
R9$CBB18/CBB7 "20kΩ" R0402#3 6038.7,6476.3 r180 top
R9$CBB18/CBB8 "20kΩ" R0402#3 6038.7,6023.5 r180 top
R9$CBB19 "100Ω" R0402#2 9272.1,5333.4 r270 bottom
R9$CBB20/CBB1 "20kΩ" R0402#1 6668.6,9192.8 r180 top
R9$CBB20/CBB2 "20kΩ" R0402#1 6668.6,8740.1 r180 top
R9$CBB20/CBB3 "20kΩ" R0402#1 6668.6,8287.3 r180 top
R9$CBB20/CBB4 "20kΩ" R0402#1 6668.6,7834.6 r180 top
R9$CBB20/CBB5 "20kΩ" R0402#1 6668.6,7381.8 r180 top
R9$CBB20/CBB6 "20kΩ" R0402#1 6668.6,6929 r180 top
R9$CBB20/CBB7 "20kΩ" R0402#1 6668.6,6476.3 r180 top
R9$CBB20/CBB8 "20kΩ" R0402#1 6668.6,6023.5 r180 top
R9$CBB23 "10kΩ" R0402#1 4629.2,5568 r180 bottom
R9$CBB49 "100Ω" R0402#1 8847.7,5088.4 r90 top
R10 "120Ω" R0402#1 10572.1,8663.7 r180 top
R10$CBB1 "100Ω" R0402#1 7567.1,4642.2 r180 top
R10$CBB2 "100Ω" R0402#1 8075.8,4642.2 r180 top
R10$CBB3 "100Ω" R0402#1 8584.5,4642.2 r180 top
R10$CBB4 "100Ω" R0402#1 9093.2,4642.2 r180 top
R10$CBB5 "100Ω" R0402#1 9601.9,4642.2 r180 top
R10$CBB6 "100Ω" R0402#1 10110.6,4642.2 r180 top
R10$CBB8 "100Ω" R0402#2 7716.9,4635.4 r0 bottom
R10$CBB9 "100Ω" R0402#2 9272.1,5333.4 r270 top
R10$CBB10 "100Ω" R0402#2 8225.6,4635.4 r0 bottom
R10$CBB11 "100Ω" R0402#2 8734.3,4635.4 r0 bottom
R10$CBB12 "100Ω" R0402#2 9243,4635.4 r0 bottom
R10$CBB13 "100Ω" R0402#2 9751.7,4635.4 r0 bottom
R10$CBB14 "100Ω" R0402#2 10260.4,4635.4 r0 bottom
R10$CBB15 "470Ω" R0402#3 9903.6,4233.3 r180 top
R10$CBB16/CBB1 "10kΩ" R0402#1 4718.8,8665.1 r90 top
R10$CBB16/CBB2 "10kΩ" R0402#2 4718.8,9117.8 r90 top
R10$CBB16/CBB3 "10kΩ" R0402#2 4718.8,8212.3 r90 top
R10$CBB16/CBB4 "10kΩ" R0402#2 4718.8,7759.5 r90 top
R10$CBB16/CBB5 "10kΩ" R0402#3 4718.8,7306.8 r90 top
R10$CBB16/CBB6 "10kΩ" R0402#1 4718.8,6854.1 r90 top
R10$CBB17/CBB1 "10kΩ" R0402#2 5343.8,9117.8 r90 top
R10$CBB17/CBB2 "10kΩ" R0402#1 5343.8,8665.1 r90 top
R10$CBB17/CBB3 "10kΩ" R0402#2 5343.8,8212.3 r90 top
R10$CBB17/CBB4 "10kΩ" R0402#1 5343.8,7759.6 r90 top
R10$CBB17/CBB5 "10kΩ" R0402#3 5343.8,7306.8 r90 top
R10$CBB17/CBB6 "10kΩ" R0402#2 5343.8,6854 r90 top
R10$CBB17/CBB7 "10kΩ" R0402#3 5343.8,6401.3 r90 top
R10$CBB17/CBB8 "10kΩ" R0402#2 5343.8,5948.5 r90 top
R10$CBB18/CBB1 "10kΩ" R0402#2 5973.7,9117.8 r90 top
R10$CBB18/CBB2 "10kΩ" R0402#1 5973.7,8665.1 r90 top
R10$CBB18/CBB3 "10kΩ" R0402#2 5973.7,8212.3 r90 top
R10$CBB18/CBB4 "10kΩ" R0402#1 5973.7,7759.6 r90 top
R10$CBB18/CBB5 "10kΩ" R0402#3 5973.7,7306.8 r90 top
R10$CBB18/CBB6 "10kΩ" R0402#2 5973.7,6854 r90 top
R10$CBB18/CBB7 "10kΩ" R0402#1 5973.7,6401.3 r90 top
R10$CBB18/CBB8 "10kΩ" R0402#2 5973.7,5948.5 r90 top
R10$CBB19 "100Ω" R0402#1 9272.1,5088.4 r90 bottom
R10$CBB20/CBB1 "10kΩ" R0402#2 6603.6,9117.8 r90 top
R10$CBB20/CBB2 "10kΩ" R0402#1 6603.6,8665.1 r90 top
R10$CBB20/CBB3 "10kΩ" R0402#2 6603.6,8212.3 r90 top
R10$CBB20/CBB4 "10kΩ" R0402#1 6603.6,7759.6 r90 top
R10$CBB20/CBB5 "10kΩ" R0402#3 6603.6,7306.8 r90 top
R10$CBB20/CBB6 "10kΩ" R0402#2 6603.6,6854 r90 top
R10$CBB20/CBB7 "10kΩ" R0402#1 6603.6,6401.3 r90 top
R10$CBB20/CBB8 "10kΩ" R0402#2 6603.6,5948.5 r90 top
R10$CBB23 "10kΩ" R0402#1 4314,5427.5 r90 top
R10$CBB49 "100Ω" R0402#2 8847.7,5333.4 r270 top
R11 "120Ω" R0402#1 10572.1,8703.7 r180 top
R11$CBB1 "3.3kΩ" R0402#1 7912.1,4837.2 r90 top
R11$CBB2 "3.3kΩ" R0402#1 8420.8,4837.2 r90 top
R11$CBB3 "3.3kΩ" R0402#1 8929.5,4837.2 r90 top
R11$CBB4 "3.3kΩ" R0402#1 9438.2,4837.2 r90 top
R11$CBB5 "3.3kΩ" R0402#1 9946.9,4837.2 r90 top
R11$CBB6 "3.3kΩ" R0402#1 10455.6,4837.2 r90 top
R11$CBB9 "100Ω" R0402#2 9922.1,5333.4 r270 top
R11$CBB15 "470Ω" R0402#1 10146.5,4233.3 r180 top
R11$CBB16/CBB1 "10kΩ" R0402#1 4673.8,8620.1 r90 top
R11$CBB16/CBB2 "10kΩ" R0402#2 4673.8,9072.8 r90 top
R11$CBB16/CBB3 "10kΩ" R0402#2 4673.8,8167.3 r90 top
R11$CBB16/CBB4 "10kΩ" R0402#2 4673.8,7714.5 r90 top
R11$CBB16/CBB5 "10kΩ" R0402#3 4673.8,7261.8 r90 top
R11$CBB16/CBB6 "10kΩ" R0402#1 4673.8,6809.1 r90 top
R11$CBB17/CBB1 "10kΩ" R0402#2 5298.8,9072.8 r90 top
R11$CBB17/CBB2 "10kΩ" R0402#1 5298.8,8620.1 r90 top
R11$CBB17/CBB3 "10kΩ" R0402#2 5298.8,8167.3 r90 top
R11$CBB17/CBB4 "10kΩ" R0402#1 5298.8,7714.6 r90 top
R11$CBB17/CBB5 "10kΩ" R0402#3 5298.8,7261.8 r90 top
R11$CBB17/CBB6 "10kΩ" R0402#2 5298.8,6809 r90 top
R11$CBB17/CBB7 "10kΩ" R0402#3 5298.8,6356.3 r90 top
R11$CBB17/CBB8 "10kΩ" R0402#2 5298.8,5903.5 r90 top
R11$CBB18/CBB1 "10kΩ" R0402#2 5928.7,9072.8 r90 top
R11$CBB18/CBB2 "10kΩ" R0402#1 5928.7,8620.1 r90 top
R11$CBB18/CBB3 "10kΩ" R0402#2 5928.7,8167.3 r90 top
R11$CBB18/CBB4 "10kΩ" R0402#1 5928.7,7714.6 r90 top
R11$CBB18/CBB5 "10kΩ" R0402#3 5928.7,7261.8 r90 top
R11$CBB18/CBB6 "10kΩ" R0402#2 5928.7,6809 r90 top
R11$CBB18/CBB7 "10kΩ" R0402#1 5928.7,6356.3 r90 top
R11$CBB18/CBB8 "10kΩ" R0402#2 5928.7,5903.5 r90 top
R11$CBB19 "100Ω" R0402#1 9922.1,5088.4 r90 bottom
R11$CBB20/CBB1 "10kΩ" R0402#2 6558.6,9072.8 r90 top
R11$CBB20/CBB2 "10kΩ" R0402#1 6558.6,8620.1 r90 top
R11$CBB20/CBB3 "10kΩ" R0402#2 6558.6,8167.3 r90 top
R11$CBB20/CBB4 "10kΩ" R0402#1 6558.6,7714.6 r90 top
R11$CBB20/CBB5 "10kΩ" R0402#3 6558.6,7261.8 r90 top
R11$CBB20/CBB6 "10kΩ" R0402#2 6558.6,6809 r90 top
R11$CBB20/CBB7 "10kΩ" R0402#1 6558.6,6356.3 r90 top
R11$CBB20/CBB8 "10kΩ" R0402#2 6558.6,5903.5 r90 top
R11$CBB23 "10kΩ" R0402#2 3709.8,5080.6 r180 top
R11$CBB49 "100Ω" R0402#2 9500.1,5333.4 r270 top
R12 "68Ω" R0402#3 7275.6,8624 r0 top
R12$CBB1 "3.3kΩ" R0402#1 7872.1,4837.2 r90 top
R12$CBB2 "3.3kΩ" R0402#1 8380.8,4837.2 r90 top
R12$CBB3 "3.3kΩ" R0402#1 8889.5,4837.2 r90 top
R12$CBB4 "3.3kΩ" R0402#1 9398.2,4837.2 r90 top
R12$CBB5 "3.3kΩ" R0402#1 9906.9,4837.2 r90 top
R12$CBB6 "3.3kΩ" R0402#1 10415.6,4837.2 r90 top
R12$CBB9 "100Ω" R0402#1 9922.1,5088.4 r90 top
R12$CBB15 "470Ω" R0402#2 10025.1,4233.3 r180 top
R12$CBB16/CBB1 "10kΩ" R0402#1 4718.8,8570.1 r90 top
R12$CBB16/CBB2 "10kΩ" R0402#2 4718.8,9022.8 r90 top
R12$CBB16/CBB3 "10kΩ" R0402#2 4718.8,8117.3 r90 top
R12$CBB16/CBB4 "10kΩ" R0402#2 4718.8,7664.5 r90 top
R12$CBB16/CBB5 "10kΩ" R0402#3 4718.8,7211.8 r90 top
R12$CBB16/CBB6 "10kΩ" R0402#1 4718.8,6759.1 r90 top
R12$CBB17/CBB1 "10kΩ" R0402#2 5343.8,9022.8 r90 top
R12$CBB17/CBB2 "10kΩ" R0402#1 5343.8,8570.1 r90 top
R12$CBB17/CBB3 "10kΩ" R0402#2 5343.8,8117.3 r90 top
R12$CBB17/CBB4 "10kΩ" R0402#1 5343.8,7664.6 r90 top
R12$CBB17/CBB5 "10kΩ" R0402#3 5343.8,7211.8 r90 top
R12$CBB17/CBB6 "10kΩ" R0402#2 5343.8,6759 r90 top
R12$CBB17/CBB7 "10kΩ" R0402#3 5343.8,6306.3 r90 top
R12$CBB17/CBB8 "10kΩ" R0402#2 5343.8,5853.5 r90 top
R12$CBB18/CBB1 "10kΩ" R0402#2 5973.7,9022.8 r90 top
R12$CBB18/CBB2 "10kΩ" R0402#1 5973.7,8570.1 r90 top
R12$CBB18/CBB3 "10kΩ" R0402#2 5973.7,8117.3 r90 top
R12$CBB18/CBB4 "10kΩ" R0402#1 5973.7,7664.6 r90 top
R12$CBB18/CBB5 "10kΩ" R0402#3 5973.7,7211.8 r90 top
R12$CBB18/CBB6 "10kΩ" R0402#2 5973.7,6759 r90 top
R12$CBB18/CBB7 "10kΩ" R0402#1 5973.7,6306.3 r90 top
R12$CBB18/CBB8 "10kΩ" R0402#2 5973.7,5853.5 r90 top
R12$CBB19 "100Ω" R0402#2 9922.1,5333.4 r270 bottom
R12$CBB20/CBB1 "10kΩ" R0402#2 6603.6,9022.8 r90 top
R12$CBB20/CBB2 "10kΩ" R0402#1 6603.6,8570.1 r90 top
R12$CBB20/CBB3 "10kΩ" R0402#2 6603.6,8117.3 r90 top
R12$CBB20/CBB4 "10kΩ" R0402#1 6603.6,7664.6 r90 top
R12$CBB20/CBB5 "10kΩ" R0402#3 6603.6,7211.8 r90 top
R12$CBB20/CBB6 "10kΩ" R0402#2 6603.6,6759 r90 top
R12$CBB20/CBB7 "10kΩ" R0402#1 6603.6,6306.3 r90 top
R12$CBB20/CBB8 "10kΩ" R0402#2 6603.6,5853.5 r90 top
R12$CBB23 "470Ω" R0402#1 3487.3,5812.6 r270 top
R12$CBB49 "100Ω" R0402#1 9500.1,5088.4 r90 top
R13 "120Ω" R0402#1 10572.1,8783.7 r180 top
R13$CBB1 "3.3kΩ" R0402#2 7642.1,4642.2 r0 top
R13$CBB2 "3.3kΩ" R0402#2 8150.8,4642.2 r0 top
R13$CBB3 "3.3kΩ" R0402#2 8659.5,4642.2 r0 top
R13$CBB4 "3.3kΩ" R0402#2 9168.2,4642.2 r0 top
R13$CBB5 "3.3kΩ" R0402#2 9676.9,4642.2 r0 top
R13$CBB6 "3.3kΩ" R0402#2 10185.6,4642.2 r0 top
R13$CBB8 "1kΩ" R0402#2 7466.9,4967.6 r90 bottom
R13$CBB9 "100Ω" R0402#1 10287.1,5088.4 r90 top
R13$CBB10 "1kΩ" R0402#2 7975.6,4967.6 r90 bottom
R13$CBB11 "1kΩ" R0402#2 8484.3,4967.6 r90 bottom
R13$CBB12 "1kΩ" R0402#2 8993,4967.6 r90 bottom
R13$CBB13 "1kΩ" R0402#2 9501.7,4967.6 r90 bottom
R13$CBB14 "1kΩ" R0402#2 10010.4,4967.6 r90 bottom
R13$CBB15 "1kΩ" R0402#2 7607.9,4279.5 r90 top
R13$CBB16/CBB1 "10kΩ" R0402#1 4673.8,8520.1 r90 top
R13$CBB16/CBB2 "10kΩ" R0402#2 4673.8,8972.8 r90 top
R13$CBB16/CBB3 "10kΩ" R0402#2 4673.8,8067.3 r90 top
R13$CBB16/CBB4 "10kΩ" R0402#2 4673.8,7614.5 r90 top
R13$CBB16/CBB5 "10kΩ" R0402#3 4673.8,7161.8 r90 top
R13$CBB16/CBB6 "10kΩ" R0402#1 4673.8,6709.1 r90 top
R13$CBB17/CBB1 "10kΩ" R0402#2 5298.8,8972.8 r90 top
R13$CBB17/CBB2 "10kΩ" R0402#1 5298.8,8520.1 r90 top
R13$CBB17/CBB3 "10kΩ" R0402#2 5298.8,8067.3 r90 top
R13$CBB17/CBB4 "10kΩ" R0402#1 5298.8,7614.6 r90 top
R13$CBB17/CBB5 "10kΩ" R0402#3 5298.8,7161.8 r90 top
R13$CBB17/CBB6 "10kΩ" R0402#2 5298.8,6709 r90 top
R13$CBB17/CBB7 "10kΩ" R0402#3 5298.8,6256.3 r90 top
R13$CBB17/CBB8 "10kΩ" R0402#2 5298.8,5803.5 r90 top
R13$CBB18/CBB1 "10kΩ" R0402#2 5928.7,8972.8 r90 top
R13$CBB18/CBB2 "10kΩ" R0402#1 5928.7,8520.1 r90 top
R13$CBB18/CBB3 "10kΩ" R0402#2 5928.7,8067.3 r90 top
R13$CBB18/CBB4 "10kΩ" R0402#1 5928.7,7614.6 r90 top
R13$CBB18/CBB5 "10kΩ" R0402#3 5928.7,7161.8 r90 top
R13$CBB18/CBB6 "10kΩ" R0402#2 5928.7,6709 r90 top
R13$CBB18/CBB7 "10kΩ" R0402#1 5928.7,6256.3 r90 top
R13$CBB18/CBB8 "10kΩ" R0402#2 5928.7,5803.5 r90 top
R13$CBB19 "100Ω" R0402#2 10287.1,5333.4 r270 bottom
R13$CBB20/CBB1 "10kΩ" R0402#2 6558.6,8972.8 r90 top
R13$CBB20/CBB2 "10kΩ" R0402#1 6558.6,8520.1 r90 top
R13$CBB20/CBB3 "10kΩ" R0402#2 6558.6,8067.3 r90 top
R13$CBB20/CBB4 "10kΩ" R0402#1 6558.6,7614.6 r90 top
R13$CBB20/CBB5 "10kΩ" R0402#3 6558.6,7161.8 r90 top
R13$CBB20/CBB6 "10kΩ" R0402#2 6558.6,6709 r90 top
R13$CBB20/CBB7 "10kΩ" R0402#1 6558.6,6256.3 r90 top
R13$CBB20/CBB8 "10kΩ" R0402#2 6558.6,5803.5 r90 top
R13$CBB23 "470Ω" R0402#1 3358.8,5814.6 r270 top
R13$CBB49 "100Ω" R0402#1 9865.1,5088.4 r90 top
R14 "120Ω" R0402#1 10572.1,7658.7 r180 top
R14$CBB1 "270Ω" R0402#1 7827.1,4967.2 r90 top
R14$CBB2 "270Ω" R0402#1 8335.8,4967.2 r90 top
R14$CBB3 "270Ω" R0402#1 8844.5,4967.2 r90 top
R14$CBB4 "270Ω" R0402#1 9353.2,4967.2 r90 top
R14$CBB5 "270Ω" R0402#1 9861.9,4967.2 r90 top
R14$CBB6 "270Ω" R0402#1 10370.6,4967.2 r90 top
R14$CBB9 "100Ω" R0402#2 10287.1,5333.4 r270 top
R14$CBB15 "470Ω" R0402#1 10389.4,4233.3 r180 top
R14$CBB16/CBB1 "10kΩ" R0402#1 4718.8,8470.1 r90 top
R14$CBB16/CBB2 "10kΩ" R0402#2 4718.8,8922.8 r90 top
R14$CBB16/CBB3 "10kΩ" R0402#2 4718.8,8017.3 r90 top
R14$CBB16/CBB4 "10kΩ" R0402#2 4718.8,7564.5 r90 top
R14$CBB16/CBB5 "10kΩ" R0402#3 4718.8,7111.8 r90 top
R14$CBB16/CBB6 "10kΩ" R0402#1 4718.8,6659.1 r90 top
R14$CBB17/CBB1 "10kΩ" R0402#2 5343.8,8922.8 r90 top
R14$CBB17/CBB2 "10kΩ" R0402#1 5343.8,8470.1 r90 top
R14$CBB17/CBB3 "10kΩ" R0402#2 5343.8,8017.3 r90 top
R14$CBB17/CBB4 "10kΩ" R0402#1 5343.8,7564.6 r90 top
R14$CBB17/CBB5 "10kΩ" R0402#3 5343.8,7111.8 r90 top
R14$CBB17/CBB6 "10kΩ" R0402#2 5343.8,6659 r90 top
R14$CBB17/CBB7 "10kΩ" R0402#3 5343.8,6206.3 r90 top
R14$CBB17/CBB8 "10kΩ" R0402#2 5343.8,5753.5 r90 top
R14$CBB18/CBB1 "10kΩ" R0402#2 5973.7,8922.8 r90 top
R14$CBB18/CBB2 "10kΩ" R0402#1 5973.7,8470.1 r90 top
R14$CBB18/CBB3 "10kΩ" R0402#2 5973.7,8017.3 r90 top
R14$CBB18/CBB4 "10kΩ" R0402#1 5973.7,7564.6 r90 top
R14$CBB18/CBB5 "10kΩ" R0402#3 5973.7,7111.8 r90 top
R14$CBB18/CBB6 "10kΩ" R0402#2 5973.7,6659 r90 top
R14$CBB18/CBB7 "10kΩ" R0402#1 5973.7,6206.3 r90 top
R14$CBB18/CBB8 "10kΩ" R0402#2 5973.7,5753.5 r90 top
R14$CBB19 "100Ω" R0402#1 10287.1,5088.4 r90 bottom
R14$CBB20/CBB1 "10kΩ" R0402#2 6603.6,8922.8 r90 top
R14$CBB20/CBB2 "10kΩ" R0402#1 6603.6,8470.1 r90 top
R14$CBB20/CBB3 "10kΩ" R0402#2 6603.6,8017.3 r90 top
R14$CBB20/CBB4 "10kΩ" R0402#1 6603.6,7564.6 r90 top
R14$CBB20/CBB5 "10kΩ" R0402#3 6603.6,7111.8 r90 top
R14$CBB20/CBB6 "10kΩ" R0402#2 6603.6,6659 r90 top
R14$CBB20/CBB7 "10kΩ" R0402#1 6603.6,6206.3 r90 top
R14$CBB20/CBB8 "10kΩ" R0402#2 6603.6,5753.5 r90 top
R14$CBB23 "470Ω" R0402#1 3421.1,5812.6 r270 top
R14$CBB49 "100Ω" R0402#2 9865.1,5333.4 r270 top
R15 "68Ω" R0402#3 7275.6,7798.8 r0 top
R15$CBB8 "1kΩ" R0402#2 7871.9,4777.6 r90 bottom
R15$CBB10 "1kΩ" R0402#2 8380.6,4777.6 r90 bottom
R15$CBB11 "1kΩ" R0402#2 8889.3,4777.6 r90 bottom
R15$CBB12 "1kΩ" R0402#2 9398,4777.6 r90 bottom
R15$CBB13 "1kΩ" R0402#2 9906.7,4777.6 r90 bottom
R15$CBB14 "1kΩ" R0402#2 10415.4,4777.6 r90 bottom
R15$CBB15 "470Ω" R0402#2 10268,4233.3 r180 top
R15$CBB16/CBB1 "10kΩ" R0402#1 4673.8,8425.1 r90 top
R15$CBB16/CBB2 "10kΩ" R0402#2 4673.8,8877.8 r90 top
R15$CBB16/CBB3 "10kΩ" R0402#2 4673.8,7972.3 r90 top
R15$CBB16/CBB4 "10kΩ" R0402#2 4673.8,7519.5 r90 top
R15$CBB16/CBB5 "10kΩ" R0402#3 4673.8,7066.8 r90 top
R15$CBB16/CBB6 "10kΩ" R0402#1 4673.8,6614.1 r90 top
R15$CBB17/CBB1 "10kΩ" R0402#2 5298.8,8877.8 r90 top
R15$CBB17/CBB2 "10kΩ" R0402#1 5298.8,8425.1 r90 top
R15$CBB17/CBB3 "10kΩ" R0402#2 5298.8,7972.3 r90 top
R15$CBB17/CBB4 "10kΩ" R0402#1 5298.8,7519.6 r90 top
R15$CBB17/CBB5 "10kΩ" R0402#3 5298.8,7066.8 r90 top
R15$CBB17/CBB6 "10kΩ" R0402#2 5298.8,6614 r90 top
R15$CBB17/CBB7 "10kΩ" R0402#3 5298.8,6161.3 r90 top
R15$CBB17/CBB8 "10kΩ" R0402#2 5298.8,5708.5 r90 top
R15$CBB18/CBB1 "10kΩ" R0402#2 5928.7,8877.8 r90 top
R15$CBB18/CBB2 "10kΩ" R0402#1 5928.7,8425.1 r90 top
R15$CBB18/CBB3 "10kΩ" R0402#2 5928.7,7972.3 r90 top
R15$CBB18/CBB4 "10kΩ" R0402#1 5928.7,7519.6 r90 top
R15$CBB18/CBB5 "10kΩ" R0402#3 5928.7,7066.8 r90 top
R15$CBB18/CBB6 "10kΩ" R0402#2 5928.7,6614 r90 top
R15$CBB18/CBB7 "10kΩ" R0402#1 5928.7,6161.3 r90 top
R15$CBB18/CBB8 "10kΩ" R0402#2 5928.7,5708.5 r90 top
R15$CBB20/CBB1 "10kΩ" R0402#2 6558.6,8877.8 r90 top
R15$CBB20/CBB2 "10kΩ" R0402#1 6558.6,8425.1 r90 top
R15$CBB20/CBB3 "10kΩ" R0402#2 6558.6,7972.3 r90 top
R15$CBB20/CBB4 "10kΩ" R0402#1 6558.6,7519.6 r90 top
R15$CBB20/CBB5 "10kΩ" R0402#3 6558.6,7066.8 r90 top
R15$CBB20/CBB6 "10kΩ" R0402#2 6558.6,6614 r90 top
R15$CBB20/CBB7 "10kΩ" R0402#1 6558.6,6161.3 r90 top
R15$CBB20/CBB8 "10kΩ" R0402#2 6558.6,5708.5 r90 top
R15$CBB23 "470Ω" R0402#2 4857.4,5396.2 r180 top
R16 "120Ω" R0402#1 10572.1,7738.7 r180 top
R16$CBB15 "470Ω" R0402#1 9174.8,4233.3 r180 top
R16$CBB16/CBB1 "20kΩ" R0402#2 4783.8,8350.1 r180 top
R16$CBB16/CBB2 "20kΩ" R0402#2 4783.8,8802.8 r180 top
R16$CBB16/CBB3 "20kΩ" R0402#2 4783.8,7897.3 r180 top
R16$CBB16/CBB4 "20kΩ" R0402#2 4783.8,7444.5 r180 top
R16$CBB16/CBB5 "20kΩ" R0402#2 4783.8,6991.8 r180 top
R16$CBB16/CBB6 "20kΩ" R0402#2 4783.8,6539.1 r180 top
R16$CBB17 "4.7kΩ" R0402#2 5815,9107.2 r180 top
R16$CBB17/CBB1 "20kΩ" R0402#2 5408.8,8802.8 r180 top
R16$CBB17/CBB2 "20kΩ" R0402#2 5408.8,8350.1 r180 top
R16$CBB17/CBB3 "20kΩ" R0402#2 5408.8,7897.3 r180 top
R16$CBB17/CBB4 "20kΩ" R0402#2 5408.8,7444.6 r180 top
R16$CBB17/CBB5 "20kΩ" R0402#2 5408.8,6991.8 r180 top
R16$CBB17/CBB6 "20kΩ" R0402#2 5408.8,6539 r180 top
R16$CBB17/CBB7 "20kΩ" R0402#2 5408.8,6086.3 r180 top
R16$CBB17/CBB8 "20kΩ" R0402#2 5408.8,5633.5 r180 top
R16$CBB18 "4.7kΩ" R0402#2 6444.9,9107.2 r180 top
R16$CBB18/CBB1 "20kΩ" R0402#3 6038.7,8802.8 r180 top
R16$CBB18/CBB2 "20kΩ" R0402#3 6038.7,8350.1 r180 top
R16$CBB18/CBB3 "20kΩ" R0402#3 6038.7,7897.3 r180 top
R16$CBB18/CBB4 "20kΩ" R0402#3 6038.7,7444.6 r180 top
R16$CBB18/CBB5 "20kΩ" R0402#3 6038.7,6991.8 r180 top
R16$CBB18/CBB6 "20kΩ" R0402#3 6038.7,6539 r180 top
R16$CBB18/CBB7 "20kΩ" R0402#3 6038.7,6086.3 r180 top
R16$CBB18/CBB8 "20kΩ" R0402#3 6038.7,5633.5 r180 top
R16$CBB20 "4.7kΩ" R0402#3 7074.8,9107.2 r180 top
R16$CBB20/CBB1 "20kΩ" R0402#1 6668.6,8802.8 r180 top
R16$CBB20/CBB2 "20kΩ" R0402#1 6668.6,8350.1 r180 top
R16$CBB20/CBB3 "20kΩ" R0402#1 6668.6,7897.3 r180 top
R16$CBB20/CBB4 "20kΩ" R0402#1 6668.6,7444.6 r180 top
R16$CBB20/CBB5 "20kΩ" R0402#1 6668.6,6991.8 r180 top
R16$CBB20/CBB6 "20kΩ" R0402#1 6668.6,6539 r180 top
R16$CBB20/CBB7 "20kΩ" R0402#1 6668.6,6086.3 r180 top
R16$CBB20/CBB8 "20kΩ" R0402#1 6668.6,5633.5 r180 top
R16$CBB23 "470Ω" R0402#2 4857.4,5334.6 r180 top
R17 "120Ω" R0402#1 10572.1,7778.7 r180 top
R17$CBB15 "470Ω" R0402#2 9417.8,4233.3 r180 top
R17$CBB23 "470Ω" R0402#2 4857.4,5457.7 r180 top
R18 "68Ω" R0402#3 7275.6,7838.9 r0 top
R18$CBB15 "470Ω" R0402#3 9296.3,4233.3 r180 top
R18$CBB23 "470Ω" R0402#2 4857.4,5518.7 r180 top
R19 "120Ω" R0402#1 10572.1,7858.7 r180 top
R19$CBB15 "470Ω" R0402#2 9660.7,4233.3 r180 top
R19$CBB23 "470Ω" R0402#2 3709.8,5040.5 r180 top
R20 "120Ω" R0402#1 10572.1,6938.7 r180 top
R20$CBB15 "470Ω" R0402#1 9782.1,4233.3 r180 top
R20$CBB23 "470Ω" R0402#2 4857.4,5580.3 r180 top
R21 "68Ω" R0402#3 7275.6,7013.7 r0 top
R21$CBB15 "470Ω" R0402#1 9539.2,4233.3 r180 top
R21$CBB23 "22Ω" R0402#1 3382.3,5457.6 r180 bottom
R22 "120Ω" R0402#1 10572.1,7018.7 r180 top
R22$CBB15 "470Ω" R0402#2 9053.4,4233.3 r180 top
R22$CBB23 "22Ω" R0402#3 3452.6,5086.1 r180 top
R23 "120Ω" R0402#1 10572.1,7058.7 r180 top
R23$CBB23 "10kΩ" R0402#2 4440.5,9346.9 r270 top
R24 "68Ω" R0402#3 7275.6,7053.9 r0 top
R24$CBB23 "10kΩ" R0402#2 4482.6,9346.9 r270 top
R25 "120Ω" R0402#1 10572.1,7138.7 r180 top
R25$CBB23 "10kΩ" R0402#2 4567,9346.9 r270 top
R26 "120Ω" R0402#1 10572.1,6403.7 r180 top
R26$CBB23 "10kΩ" R0402#2 4524.8,9346.9 r270 top
R27 "68Ω" R0402#3 7275.6,6493.7 r0 top
R27$CBB23 "33Ω" R2512#1 9853.7,8383.1 r270 top
R28 "120Ω" R0402#1 10572.1,6483.7 r180 top
R28$CBB23 "33Ω" R2512#1 8319.7,8383.1 r270 top
R29 "120Ω" R0402#1 10572.1,6523.7 r180 top
R29$CBB23 "33Ω" R2512#2 9851.7,6288.9 r270 top
R30 "68Ω" R0402#3 7275.6,6533.8 r0 top
R30$CBB23 "33Ω" R2512#2 8319.7,6288.9 r270 top
R31 "120Ω" R0402#1 10572.1,6603.7 r180 top
R31$CBB23 "470Ω" R0402#1 8394,6047.9 r270 top
R32 "120Ω" R0402#1 10572.1,5603.7 r180 top
R32$CBB16 "1.5kΩ" R0402#1 5192.1,9108.7 r180 top
R32$CBB17 "51kΩ" R0402#1 5815,9048.1 r0 top
R32$CBB18 "51kΩ" R0402#1 6444.9,9048.1 r0 top
R32$CBB20 "51kΩ" R0402#3 7074.8,9048.1 r0 top
R32$CBB23 "470Ω" R0402#2 9911.9,6041.9 r270 top
R33 "68Ω" R0402#3 7275.6,5708.6 r0 top
R33$CBB23 "470Ω" R0402#2 8383.9,8152.2 r270 top
R34 "120Ω" R0402#1 10572.1,5683.7 r180 top
R34$CBB23 "470Ω" R0402#2 9915.9,8152.2 r270 top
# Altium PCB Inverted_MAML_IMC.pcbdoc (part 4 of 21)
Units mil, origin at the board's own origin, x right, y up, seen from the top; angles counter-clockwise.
Board outline 7677.1 x 6771.6 mil, 6 copper layers (Top Layer, Inner1, Inner2, Inner3, Inner4, Bottom Layer), stack 60.7 mil thick; 2732 components, 1531 nets, 7765 pads, 3701 vias.

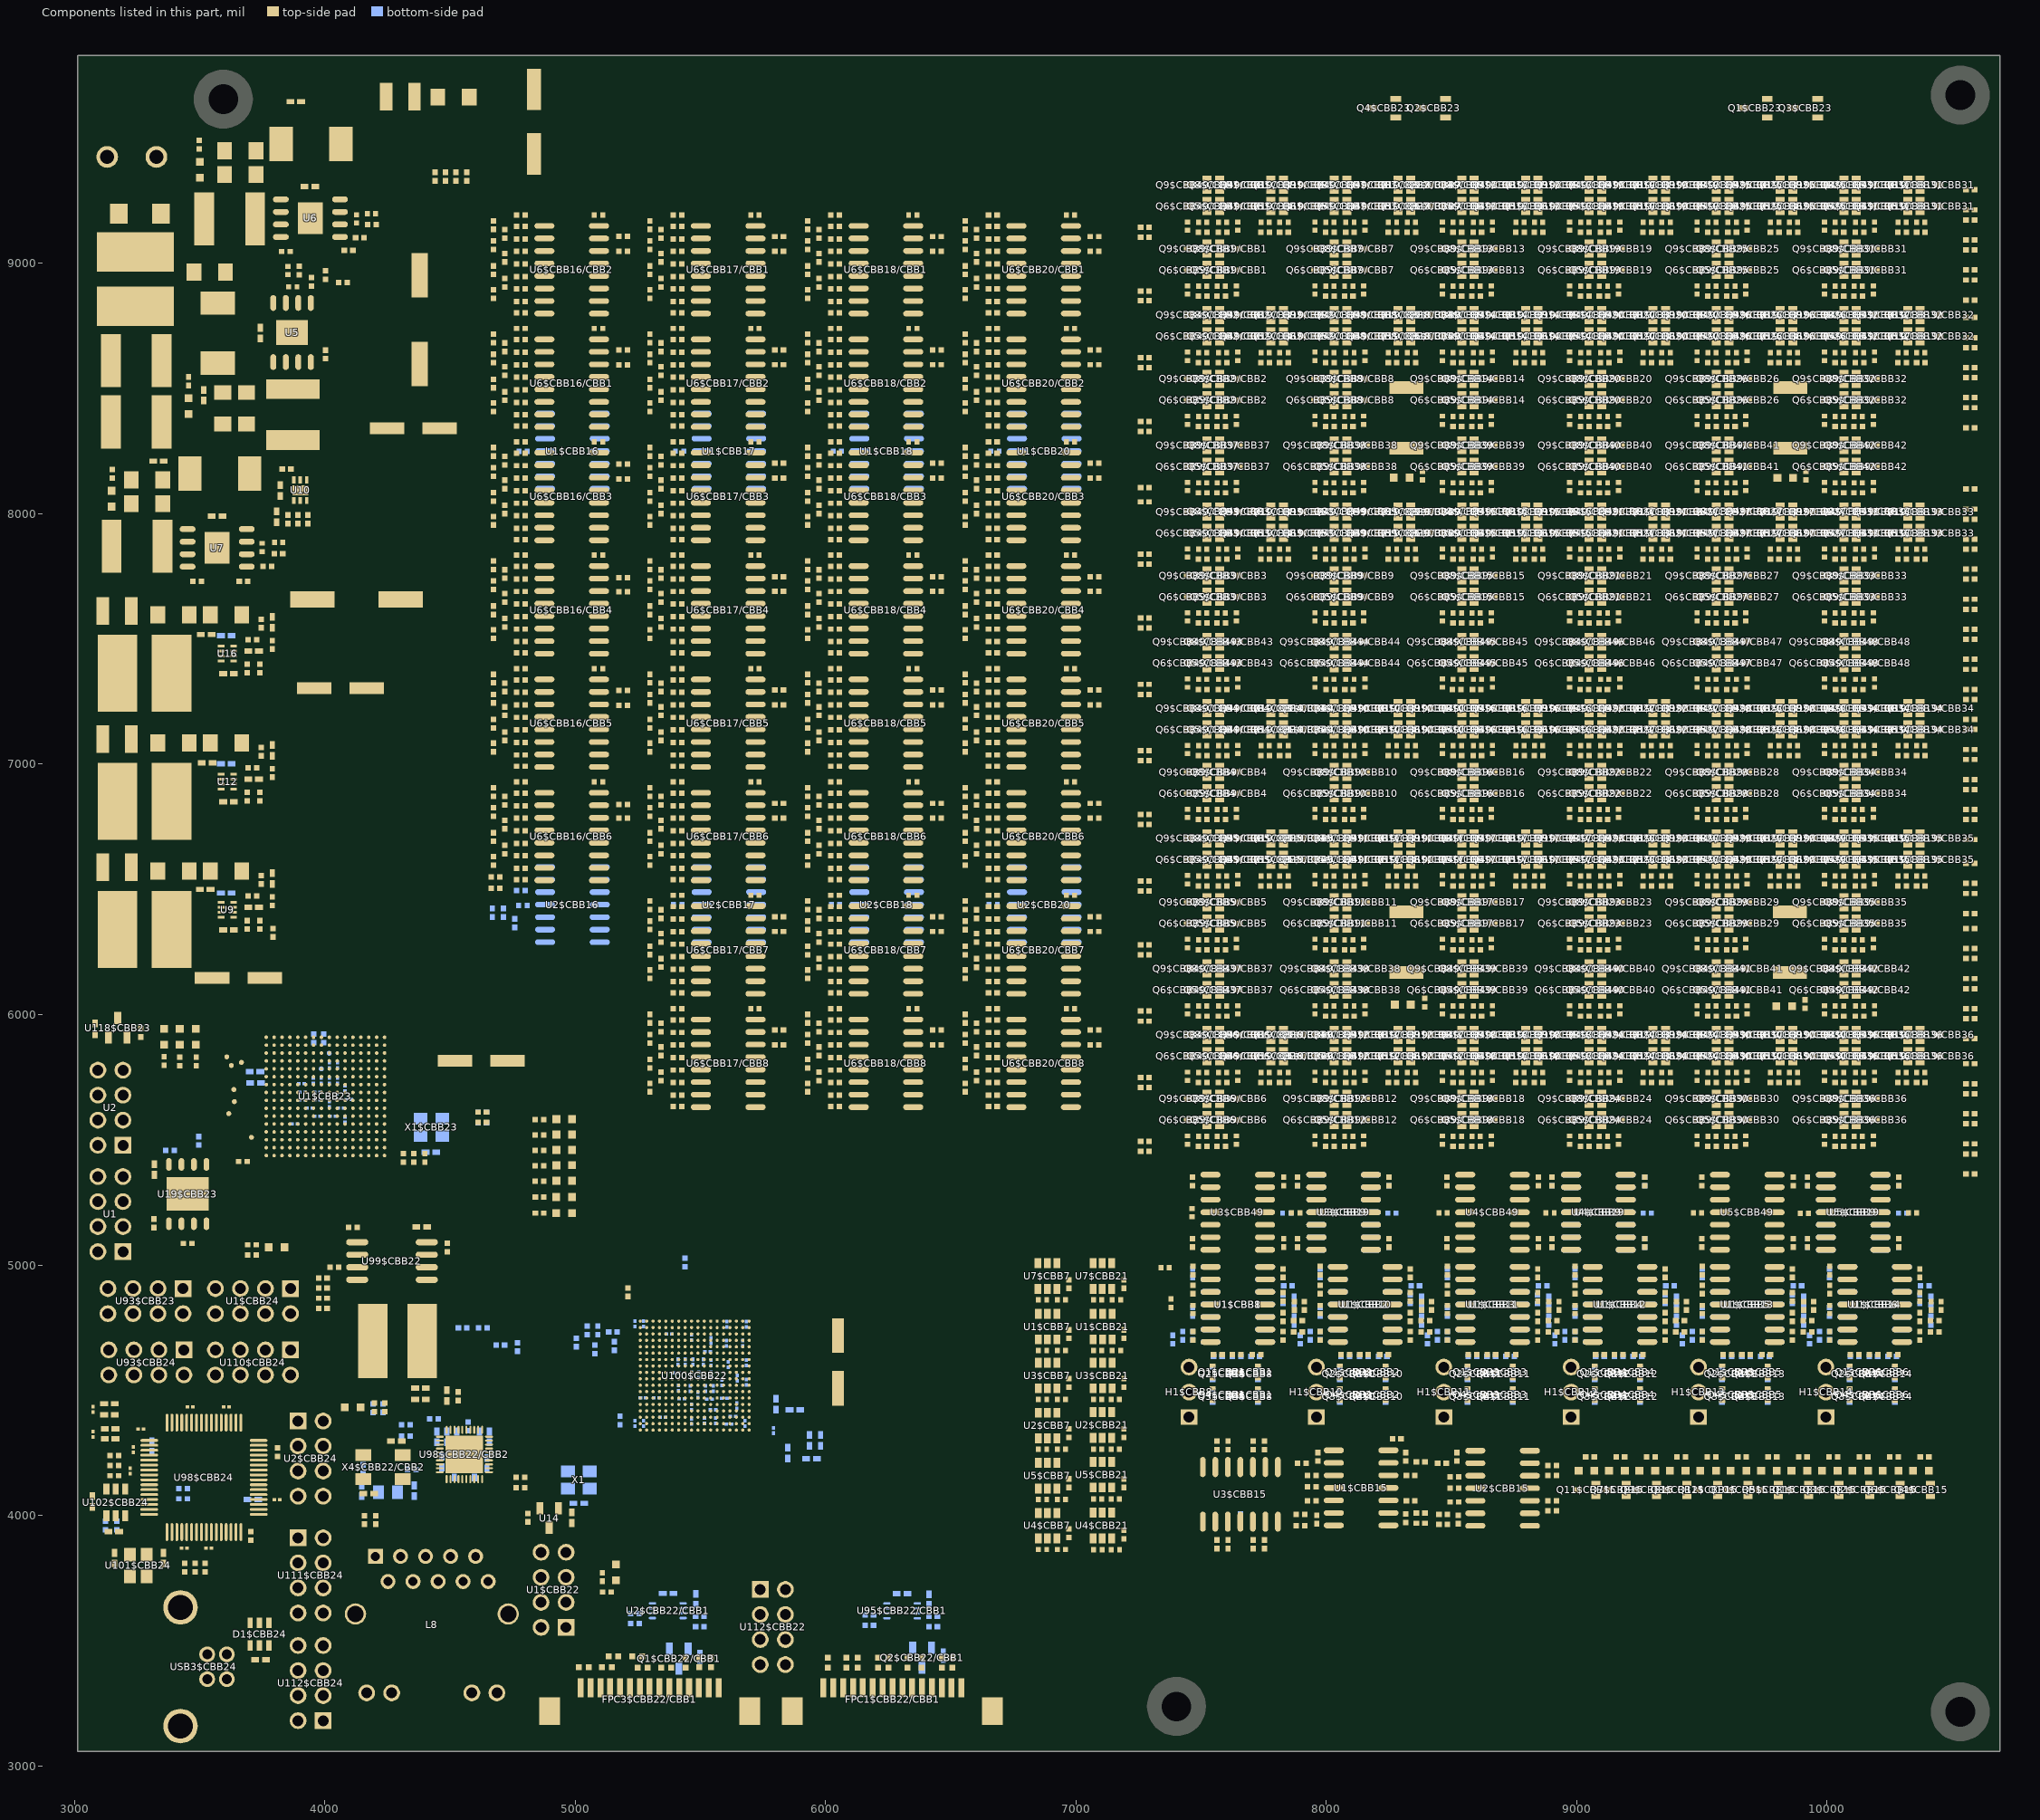
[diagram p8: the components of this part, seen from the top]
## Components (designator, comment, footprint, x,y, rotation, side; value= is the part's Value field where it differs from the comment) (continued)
R35 "120Ω" R0402#1 10572.1,5723.7 r180 top
R36 "68Ω" R0402#3 7275.6,5748.7 r0 top
R37 "120Ω" R0402#1 10572.1,5803.7 r180 top
R38 "120Ω" R0402#1 10572.1,5903.7 r180 top
R39 "68Ω" R0402#3 7275.6,5973.6 r0 top
R40 "120Ω" R0402#1 10572.1,5983.7 r180 top
R41 "120Ω" R0402#1 10572.1,6023.7 r180 top
R42 "68Ω" R0402#3 7275.6,6013.8 r0 top
R43 "120Ω" R0402#1 10572.1,6103.7 r180 top
R44 "120Ω" R0402#1 10572.1,7178.7 r180 top
R45 "0Ω" R0402#1 4203.5,3981.8 r270 top
R46 "6.49kΩ" R0402#2 4347.9,4183.2 r180 bottom
R47 "0Ω" R0402#3 4550.9,4748.8 r0 bottom
R48 "0Ω" R0402#3 4153.3,4184.6 r90 bottom
R48$CBB16 "1.8kΩ" R0402#2 5192.1,9048.7 r0 top
R48$CBB17 "4.7kΩ" R0402#2 5815,8654.4 r180 top
R48$CBB18 "4.7kΩ" R0402#2 6444.9,8654.4 r180 top
R48$CBB20 "4.7kΩ" R0402#3 7074.8,8654.4 r180 top
R49 "470Ω" R0402#2 4159.4,3981.8 r90 top
R50 "4.7kΩ" R0402#2 4192.6,4428.2 r270 bottom
R51 "470Ω" R0402#2 3498.6,9473.7 r90 top
R51$CBB23 "12kΩ" R0402#2 3673.5,5413.4 r180 top
R52 "15kΩ" R0402#2 4188.8,9155.7 r180 top
R53 "560kΩ" R0402#1 3741.1,6358.3 r270 top
R54 "470Ω" R0402#3 3151.4,8159.9 r90 top
R55 "8.2kΩ" R0402#1 4140.5,9102.4 r180 top
R56 "40.2kΩ" R0402#2 3746.1,6538.3 r90 top
R57 "24kΩ" R0402#2 3711.1,6473.3 r0 top
R58 "0Ω" R1210 3171.1,6588.3 r0 top
R58$CBB23 "0Ω" R1210 4301.9,9666.1 r0 top
R59 "19.1kΩ" R0402#2 3791.1,6453.3 r90 top
R60 "36kΩ" R0402#2 3892.9,7978.2 r270 top
R61 "470Ω" R0402#2 3456.6,8529.3 r90 top
R62 "68Ω" R0402#3 7275.6,7278.7 r0 top
R63 "120Ω" R0402#1 10572.1,7258.7 r180 top
R64 "20kΩ" R0402#1 4759.7,6365.2 r90 bottom
R64$CBB16 "20kΩ" R0402#1 4714.6,6406.7 r90 bottom
R64$CBB17 "51kΩ" R0402#1 5815,8595.4 r0 top
R64$CBB18 "51kΩ" R0402#1 6444.9,8595.4 r0 top
R64$CBB20 "51kΩ" R0402#3 7074.8,8595.4 r0 top
R65 "0Ω" R0402#2 3992.7,4947.6 r0 top
R66 "10kΩ" R0402#2 4490.1,5069.3 r90 top
R67 "10kΩ" R0402#2 4038.4,4991 r180 top
R68 "10kΩ" R0402#2 4113.2,5150.4 r180 top
R69 "10kΩ" R0402#2 5079,4662.5 r270 bottom
R70 "10kΩ" R0402#1 5151.3,4732.8 r0 bottom
R71 "10kΩ" R0402#2 4532.8,4475.7 r90 top
R72 "10kΩ" R0402#2 5091,4738.8 r270 bottom
R73 "10kΩ" R0402#2 5157.3,4676.5 r90 bottom
R74 "120Ω" R0402#1 10572.1,7298.7 r180 top
R74$CBB22/CBB1 "4.7kΩ" R0402#2 5498.6,3435.7 r270 bottom
R75 "10kΩ" R0402#2 3992.7,4907.4 r0 top
R76 "10kΩ" R0402#2 3992.7,4867.3 r0 top
R77 "22Ω" R0402#1 4631.2,4748.8 r180 bottom
R78 "12kΩ" R0402#2 5211.5,4891.4 r270 top
R79 "68Ω" R0402#3 7275.6,7318.9 r0 top
R80 "120Ω" R0402#1 10572.1,7378.7 r180 top
R80$CBB16 "27kΩ" R0402#2 4669.6,6406.7 r270 bottom
R80$CBB17 "4.7kΩ" R0402#2 5815,8201.7 r180 top
R80$CBB18 "4.7kΩ" R0402#2 6444.9,8201.7 r180 top
R80$CBB20 "4.7kΩ" R0402#3 7074.8,8201.7 r180 top
R81 "120Ω" R0402#1 10572.1,8853.7 r180 top
R82 "68Ω" R0402#3 7275.6,8850.9 r0 top
R83 "120Ω" R0402#1 10572.1,8933.7 r180 top
R84 "120Ω" R0402#1 10572.1,8973.7 r180 top
R84$CBB22/CBB1 "4.7kΩ" R0402#2 6470.4,3439.7 r270 bottom
R85 "68Ω" R0402#3 7275.6,8889.1 r0 top
R85$CBB15 "1kΩ" R0402#1 7942.1,4113.7 r180 top
R86 "120Ω" R0402#1 10572.1,9053.7 r180 top
R86$CBB15 "1kΩ" R0402#1 7902.1,4208.7 r180 top
R87 "120Ω" R0402#1 10572.1,8343.7 r180 top
R87$CBB15 "3.3kΩ" R0402#1 7967.1,4233.7 r270 top
R88 "68Ω" R0402#3 7275.6,8328.9 r0 top
R88$CBB15 "3.3kΩ" R0402#2 7942.1,4158.7 r0 top
R89 "120Ω" R0402#1 10572.1,8423.7 r180 top
R89$CBB15 "1kΩ" R0402#2 7897.1,3958.7 r0 top
R90 "120Ω" R0402#1 10572.1,8463.7 r180 top
R90$CBB15 "1kΩ" R0402#1 7897.1,4003.7 r180 top
R91 "68Ω" R0402#3 7275.6,8369 r0 top
R91$CBB15 "3.3kΩ" R0402#2 7962.1,3983.7 r90 top
R92 "120Ω" R0402#1 10572.1,8543.7 r180 top
R92$CBB15 "3.3kΩ" R0402#2 7942.1,4058.7 r0 top
R93 "120Ω" R0402#1 10572.1,7418.7 r180 top
R93$CBB15 "1kΩ" R0402#1 8377.1,3968.7 r180 top
R94 "68Ω" R0402#3 7275.6,7543.8 r0 top
R94$CBB15 "1kΩ" R0402#2 8377.1,4008.7 r0 top
R95 "120Ω" R0402#1 10572.1,7498.7 r180 top
R95$CBB15 "3.3kΩ" R0402#2 8317.1,3988.7 r90 top
R95$CBB22 "470Ω" R0402#1 4858.2,5207.2 r180 top
R96 "22Ω" R0402#2 3691.1,6358.3 r90 top
R96$CBB15 "3.3kΩ" R0402#1 8337.1,4058.7 r180 top
R96$CBB16 "20kΩ" R0402#1 4682.1,6549.2 r180 top
R96$CBB17 "51kΩ" R0402#1 5815,8142.6 r0 top
R96$CBB18 "51kΩ" R0402#1 6444.9,8142.6 r0 top
R96$CBB20 "51kΩ" R0402#3 7074.8,8142.6 r0 top
R97 "120Ω" R0402#1 10572.1,7538.7 r180 top
R97$CBB15 "1kΩ" R0402#2 8281.5,4305.1 r0 top
R97$CBB16 "27kΩ" R0402#2 4682.1,6504.2 r0 top
R97$CBB22/CBB1 "4.7kΩ" R0402#1 5498.5,3556 r0 bottom
R98 "68Ω" R0402#3 7275.6,7583.9 r0 top
R98$CBB15 "1kΩ" R0402#2 8377.1,4213.7 r0 top
R98$CBB16 "1.5kΩ" R0402#1 5192.1,8654.2 r180 top
R99 "120Ω" R0402#1 10572.1,7618.7 r180 top
R99$CBB15 "3.3kΩ" R0402#1 8317.1,4233.7 r270 top
R99$CBB16 "1.8kΩ" R0402#2 5192.1,8594.2 r0 top
R100 "120Ω" R0402#1 10572.1,6698.7 r180 top
R100$CBB15 "3.3kΩ" R0402#1 8337.1,4158.7 r180 top
R100$CBB16 "1.5kΩ" R0402#1 5192.1,8199.2 r180 top
R101 "68Ω" R0402#3 7275.6,6758.7 r0 top
R101$CBB15 "1kΩ" R0402#1 8512.1,4108.7 r180 top
R101$CBB16 "1.8kΩ" R0402#2 5192.1,8139.2 r0 top
R102 "120Ω" R0402#1 10572.1,6778.7 r180 top
R102$CBB15 "1kΩ" R0402#1 8462.1,4208.7 r180 top
R102$CBB16 "1.5kΩ" R0402#1 5192.1,7744.2 r180 top
R103 "120Ω" R0402#1 10572.1,6818.7 r180 top
R103$CBB15 "3.3kΩ" R0402#1 8522.1,4233.7 r270 top
R103$CBB16 "1.8kΩ" R0402#2 5192.1,7689.2 r0 top
R104 "68Ω" R0402#3 7275.6,6798.9 r0 top
R104$CBB15 "3.3kΩ" R0402#2 8512.1,4153.7 r0 top
R104$CBB16 "1.5kΩ" R0402#1 5192.1,7294.2 r180 top
R105 "120Ω" R0402#1 10572.1,6898.7 r180 top
R105$CBB15 "1kΩ" R0402#1 8467.1,3963.7 r180 top
R105$CBB16 "1.8kΩ" R0402#2 5192.1,7234.2 r0 top
R106 "120Ω" R0402#1 10572.1,6143.7 r180 top
R106$CBB15 "1kΩ" R0402#1 8467.1,4003.7 r180 top
R106$CBB16 "1.5kΩ" R0402#1 5192.1,6839.2 r180 top
R107 "68Ω" R0402#3 7275.6,6238.7 r0 top
R107$CBB15 "3.3kΩ" R0402#2 8527.1,3983.7 r90 top
R107$CBB16 "1.8kΩ" R0402#2 5192.1,6784.2 r0 top
R108 "120Ω" R0402#1 10572.1,6223.7 r180 top
R108$CBB15 "3.3kΩ" R0402#2 8512.1,4053.7 r0 top
R109 "120Ω" R0402#1 10572.1,6263.7 r180 top
R109$CBB15 "1kΩ" R0402#2 8902.1,4058.7 r0 top
R110 "68Ω" R0402#3 7275.6,6278.8 r0 top
R111 "120Ω" R0402#1 10572.1,6343.7 r180 top
R112 "120Ω" R0402#1 10572.1,5363.7 r180 top
R112$CBB17 "4.7kΩ" R0402#2 5815,7748.9 r180 top
R112$CBB18 "4.7kΩ" R0402#2 6444.9,7748.9 r180 top
R112$CBB20 "4.7kΩ" R0402#3 7074.8,7748.9 r180 top
R113 "68Ω" R0402#3 7275.6,5453.6 r0 top
R113$CBB15 "1kΩ" R0402#2 8902.1,4158.7 r0 top
R114 "120Ω" R0402#1 10572.1,5443.7 r180 top
R115 "120Ω" R0402#1 10572.1,5483.7 r180 top
R116 "68Ω" R0402#3 7275.6,5493.7 r0 top
R117 "120Ω" R0402#1 10572.1,5563.7 r180 top
R118 "120Ω" R0402#1 10572.1,7898.7 r180 top
R119 "68Ω" R0402#3 7275.6,8047.8 r0 top
R120 "120Ω" R0402#1 10572.1,7978.7 r180 top
R121 "120Ω" R0402#1 10572.1,8018.7 r180 top
R122 "68Ω" R0402#3 7275.6,8104 r0 top
R123 "120Ω" R0402#1 10572.1,8098.7 r180 top
R124 "10kΩ" R0402#2 3847.9,8178.2 r180 top
R125 "43kΩ" R0402#2 4095.5,9052.4 r0 top
R126 "82kΩ" R0402#2 3932.9,7978.2 r270 top
R127 "12kΩ" R0402#1 3852.9,7978.2 r90 top
R128 "560kΩ" R0402#2 3741.1,6870.2 r270 top
R128$CBB17 "51kΩ" R0402#1 5815,7689.9 r0 top
R128$CBB18 "51kΩ" R0402#1 6444.9,7689.9 r0 top
R128$CBB20 "51kΩ" R0402#3 7074.8,7689.9 r0 top
R128$CBB22/CBB1 "4.7kΩ" R0402#1 5498.5,3596.2 r0 bottom
R129 "40.2kΩ" R0402#1 3746.1,7050.2 r90 top
R129$CBB17 "4.7kΩ" R0402#2 5815,7296.2 r180 top
R129$CBB18 "4.7kΩ" R0402#2 6444.9,7296.2 r180 top
R129$CBB20 "4.7kΩ" R0402#3 7074.8,7296.2 r180 top
R129$CBB22/CBB1 "4.7kΩ" R0402#1 6430.3,3596.3 r0 bottom
R130 "4.7kΩ" R0402#1 3770.7,7790.6 r180 top
R130$CBB17 "51kΩ" R0402#1 5815,7237.1 r0 top
R130$CBB18 "51kΩ" R0402#1 6444.9,7237.1 r0 top
R130$CBB20 "51kΩ" R0402#3 7074.8,7237.1 r0 top
R130$CBB22/CBB1 "4.7kΩ" R0402#1 6430.3,3556.1 r0 bottom
R131 "36kΩ" R0402#2 3711.1,6985.2 r0 top
R131$CBB17 "4.7kΩ" R0402#2 5815,6843.4 r180 top
R131$CBB18 "4.7kΩ" R0402#2 6444.9,6843.4 r180 top
R131$CBB20 "4.7kΩ" R0402#3 7074.8,6843.4 r180 top
R131$CBB22/CBB1 "4.7kΩ" R0402#2 5239.5,3608.2 r180 bottom
R132 "0Ω" R1210 3171.1,7100.2 r0 top
R132$CBB17 "51kΩ" R0402#1 5815,6784.4 r0 top
R132$CBB18 "51kΩ" R0402#1 6444.9,6784.4 r0 top
R132$CBB20 "51kΩ" R0402#3 7074.8,6784.4 r0 top
R132$CBB22/CBB1 "4.7kΩ" R0402#2 5239.5,3568 r180 bottom
R133 "32.4kΩ" R0402#1 3791.1,6965.2 r90 top
R133$CBB17 "4.7kΩ" R0402#2 5815,6390.7 r180 top
R133$CBB18 "4.7kΩ" R0402#2 6444.9,6390.7 r180 top
R133$CBB20 "4.7kΩ" R0402#3 7074.8,6390.7 r180 top
R133$CBB22/CBB1 "4.7kΩ" R0402#2 6175.3,3602.3 r180 bottom
R134 "1.5kΩ" R0402#2 3675.7,7730.6 r0 top
R134$CBB17 "51kΩ" R0402#1 5815,6331.6 r0 top
R134$CBB18 "51kΩ" R0402#1 6444.9,6331.6 r0 top
R134$CBB20 "51kΩ" R0402#3 7074.8,6331.6 r0 top
R134$CBB22/CBB1 "4.7kΩ" R0402#2 6175.3,3560.2 r180 bottom
R135 "22Ω" R0402#1 3691.1,6870.2 r90 top
R135$CBB17 "4.7kΩ" R0402#2 5815,5937.9 r180 top
R135$CBB18 "4.7kΩ" R0402#2 6444.9,5937.9 r180 top
R135$CBB20 "4.7kΩ" R0402#3 7074.8,5937.9 r180 top
R136 "15kΩ" R0402#1 3815.7,7840.6 r180 top
R136$CBB17 "51kΩ" R0402#1 5815,5878.9 r0 top
R136$CBB18 "51kΩ" R0402#1 6444.9,5878.8 r0 top
R136$CBB20 "51kΩ" R0402#3 7074.8,5878.8 r0 top
R137 "4.7kΩ" R0402#3 4002.8,8953.3 r270 top
R138 "15kΩ" R0402#1 3897.9,8971.3 r270 top
R139 "10kΩ" R0402#2 4810.9,3990.9 r270 top
R140 "560kΩ" R0402#2 3741.1,7382 r270 top
R141 "68kΩ" R0402#1 4002.9,8636.3 r270 top
R142 "1.5kΩ" R0402#1 3947.9,8926.3 r270 top
R143 "40.2kΩ" R0402#1 3746.1,7562 r90 top
R144 "68kΩ" R0402#2 4073,8923.2 r0 top
R145 "75kΩ" R0402#2 3711.1,7497 r0 top
R146 "0Ω" R1210 3171.1,7612 r0 top
R147 "82kΩ" R0402#1 3791.1,7477 r90 top
R148 "0Ω" R0402#3 7380,4847.2 r90 top
R149 "22Ω" R0402#1 3691.1,7382 r90 top
R150 "68kΩ" R0402#1 3845.5,9047.4 r180 top
R151 "68kΩ" R0402#1 3490.7,7730.6 r180 top
R158$CBB22 "0Ω" R0402#2 3992.7,4827.1 r0 top
R158$CBB23 "0Ω" R0402#2 3956.6,5905.4 r270 bottom
R159$CBB23 "0Ω" R0402#2 3996.7,5905.4 r270 bottom
R164$CBB22/CBB2 "0Ω" R0402#1 4232.7,4428.6 r90 bottom
R165$CBB22/CBB2 "4.7kΩ" R0402#1 4324,4361.3 r180 bottom
R166$CBB22/CBB2 "470Ω" R0402#1 4324,4317.1 r180 bottom
R167$CBB22/CBB2 "4.7kΩ" R0402#2 4240.5,4431.6 r270 top
R168$CBB22/CBB2 "470Ω" R0402#2 4198.3,4431.6 r270 top
R169$CBB22/CBB2 "4.7kΩ" R0402#1 5048.9,4738.8 r90 bottom
R173$CBB22/CBB2 "4.7kΩ" R0402#3 5004.7,4690.6 r90 bottom
R174$CBB22/CBB2 "0Ω" R0402#1 4573,4355.3 r90 bottom
R176$CBB22/CBB2 "4.7kΩ" R0402#2 5179.4,4379.4 r270 bottom
R179$CBB22/CBB2 "4.7kΩ" R0402#1 4436.5,4385.4 r0 bottom
R179$CBB24 "4.7kΩ" R0402#2 3434.5,4106.2 r0 bottom
R180$CBB22/CBB2 "4.7kΩ" R0402#1 4781.8,4152.5 r180 top
R181$CBB24 "10kΩ" R0402#1 3434.5,4066.1 r180 bottom
R182$CBB23 "22Ω" R0402#2 3496.8,5495.7 r90 bottom
R183$CBB22 "12kΩ" R0402#1 5438.4,5009.8 r270 bottom
R211$CBB24 "10kΩ" R0402#1 3159.4,4198.7 r180 top
R212$CBB24 "1.8kΩ" R0402#2 3159.4,4158.5 r0 top
R213$CBB24 "10kΩ" R0402#1 3169.2,3959.2 r270 bottom
R214$CBB24 "10kΩ" R0402#1 3124.2,3959.2 r270 bottom
R215$CBB24 "10Ω" R0402#1 3482.7,3791.1 r90 top
R217$CBB24 "10Ω" R0402#1 3522.9,3791.1 r90 top
R218$CBB24 "1kΩ" R0402#2 3705.6,3917.6 r270 top
R219$CBB24 "12kΩ" R0402#1 3440.6,3791.1 r90 top
R220$CBB24 "10kΩ" R0402#2 3159.4,4238.8 r0 top
R222$CBB24 "10kΩ" R0402#2 3812,4252.9 r270 top
R251$CBB22 "10kΩ" R0402#1 4769.8,4672.5 r270 bottom
R252$CBB22 "10kΩ" R0402#3 4701.5,4680.6 r180 bottom
R253$CBB22 "10kΩ" R0402#3 5109,3754.1 r270 top
R260$CBB22 "470Ω" R0402#3 5127.1,3693.9 r180 top
TP1 "" Test-Point-0.5mm 3637.3,5700.6 r0 top
TP2 "" Test-Point-0.5mm 3627.3,5796.9 r0 top
TP2$CBB23 "" Test-Point-0.5mm 3986.7,5783.3 r180 bottom
TP3 "" Test-Point-0.5mm 3639.3,5652.4 r0 top
TP3$CBB23 "" Test-Point-0.5mm 4018,5845.6 r180 bottom
TP4 "" Test-Point-0.5mm 3617.2,5604.2 r0 top
TP5 "" Test-Point-0.5mm 3609.2,5831.1 r0 top
TP6 "" Test-Point-0.5mm 3667.4,5809 r0 top
TP7 "" Test-Point-0.5mm 3707.6,5509.8 r0 top
U1 "PZ2.54-2*4" HDR-TH_8P-P2.54-V-M-R2-C4-S2.54 3144.4,5203.2 r90 top
U1$CBB1 "MCP6024T-I/SL-MS" SOIC-14_L8.7-W3.9-P1.27-LS6.0-BL-1#1 7647.1,4842.2 r270 top
U1$CBB2 "MCP6024T-I/SL-MS" SOIC-14_L8.7-W3.9-P1.27-LS6.0-BL-1#1 8155.8,4842.2 r270 top
U1$CBB3 "MCP6024T-I/SL-MS" SOIC-14_L8.7-W3.9-P1.27-LS6.0-BL-1#1 8664.5,4842.2 r270 top
U1$CBB4 "MCP6024T-I/SL-MS" SOIC-14_L8.7-W3.9-P1.27-LS6.0-BL-1#2 9173.2,4842.2 r270 top
U1$CBB5 "MCP6024T-I/SL-MS" SOIC-14_L8.7-W3.9-P1.27-LS6.0-BL-1#2 9681.9,4842.2 r270 top
U1$CBB6 "MCP6024T-I/SL-MS" SOIC-14_L8.7-W3.9-P1.27-LS6.0-BL-1#2 10190.6,4842.2 r270 top
U1$CBB7 "XC2361A" TSOT-23-6_L2.9-W1.6-P0.95-LS2.6-BL 6887.1,4753.7 r0 top
U1$CBB8 "MCP6024T-I/SL-MS" SOIC-14_L8.7-W3.9-P1.27-LS6.0-BL-1#3 7646.9,4842.6 r270 bottom
U1$CBB10 "MCP6024T-I/SL-MS" SOIC-14_L8.7-W3.9-P1.27-LS6.0-BL-1#3 8155.6,4842.6 r270 bottom
U1$CBB11 "MCP6024T-I/SL-MS" SOIC-14_L8.7-W3.9-P1.27-LS6.0-BL-1#3 8664.3,4842.6 r270 bottom
U1$CBB12 "MCP6024T-I/SL-MS" SOIC-14_L8.7-W3.9-P1.27-LS6.0-BL-1#3 9173,4842.6 r270 bottom
U1$CBB13 "MCP6024T-I/SL-MS" SOIC-14_L8.7-W3.9-P1.27-LS6.0-BL-1#3 9681.7,4842.6 r270 bottom
U1$CBB14 "MCP6024T-I/SL-MS" SOIC-14_L8.7-W3.9-P1.27-LS6.0-BL-1#3 10190.4,4842.6 r270 bottom
U1$CBB15 "MCP6024T-I/SL-MS" SOIC-14_L8.7-W3.9-P1.27-LS6.0-BL-1#2 8139.3,4109.7 r270 top
U1$CBB16 "MCP6024T-I/SL-MS" SOIC-14_L8.7-W3.9-P1.27-LS6.0-BL-1#2 4989.4,8250.1 r270 bottom
U1$CBB17 "MCP6024T-I/SL-MS" SOIC-14_L8.7-W3.9-P1.27-LS6.0-BL-1#1 5614.4,8250.1 r270 bottom
U1$CBB18 "MCP6024T-I/SL-MS" SOIC-14_L8.7-W3.9-P1.27-LS6.0-BL-1#1 6244.3,8250.1 r270 bottom
U1$CBB20 "MCP6024T-I/SL-MS" SOIC-14_L8.7-W3.9-P1.27-LS6.0-BL-1#1 6874.2,8250.1 r270 bottom
U1$CBB21 "XC2361A" TSOT-23-6_L2.9-W1.6-P0.95-LS2.6-BL 7107.1,4753.7 r0 top
U1$CBB22 "PZ2.54-2*4" HDR-TH_8P-P2.54-V-M-R2-C4-S2.54 4914.3,3702.7 r90 top
U1$CBB23 "T20F256C3" FBGA-256_L13.0-W13.0-R16-C16-P0.80-TL 4002.9,5673.2 r0 top locked
U1$CBB24 "PZ2.54-2*4" HDR-TH_8P-P2.54-V-M-R2-C4-S2.54 3713.6,4855.7 r180 top
U2 "PZ2.54-2*4" HDR-TH_8P-P2.54-V-M-R2-C4-S2.54 3144.4,5628.2 r90 top
U2$CBB7 "XC2361A" TSOT-23-6_L2.9-W1.6-P0.95-LS2.6-BL 6887.1,4358.7 r0 top
U2$CBB15 "MCP6024T-I/SL-MS" SOIC-14_L8.7-W3.9-P1.27-LS6.0-BL-1#2 8704.3,4108.3 r270 top
U2$CBB16 "MCP6024T-I/SL-MS" SOIC-14_L8.7-W3.9-P1.27-LS6.0-BL-1#2 4989.4,6439.1 r270 bottom
U2$CBB17 "MCP6024T-I/SL-MS" SOIC-14_L8.7-W3.9-P1.27-LS6.0-BL-1#1 5614.4,6439.1 r270 bottom
U2$CBB18 "MCP6024T-I/SL-MS" SOIC-14_L8.7-W3.9-P1.27-LS6.0-BL-1#1 6244.3,6439.1 r270 bottom
U2$CBB20 "MCP6024T-I/SL-MS" SOIC-14_L8.7-W3.9-P1.27-LS6.0-BL-1#1 6874.2,6439.1 r270 bottom
U2$CBB21 "XC2361A" TSOT-23-6_L2.9-W1.6-P0.95-LS2.6-BL 7105.9,4361 r0 top
U2$CBB22/CBB1 "PCA9306DC1" VSSOP-8_L2.4-W2.1-P0.50-LS3.2-BR#1 5370.4,3619.5 r0 bottom
U2$CBB24 "PZ2.54-2*4" HDR-TH_8P-P2.54-V-M-R2-C4-S2.54 3943.8,4226.8 r270 top
U3 "KF301-5.0-2P" CONN-TH_P5.00_KF301-5.0-2P 3229.7,9425.2 r180 top
U3$CBB7 "XC2361A" TSOT-23-6_L2.9-W1.6-P0.95-LS2.6-BL 6887.1,4558.7 r0 top
U3$CBB9 "MCP6024T-I/SL-MS" SOIC-14_L8.7-W3.9-P1.27-LS6.0-BL-1#1 8069.6,5210.6 r270 top
U3$CBB15 "MCP6024T-I/SL-MS" SOIC-14_L8.7-W3.9-P1.27-LS6.0-BL-1#2 7657,4083.8 r0 top
U3$CBB19 "MCP6024T-I/SL-MS" SOIC-14_L8.7-W3.9-P1.27-LS6.0-BL-1#1 8069.6,5210.6 r90 bottom
U3$CBB21 "XC2361A" TSOT-23-6_L2.9-W1.6-P0.95-LS2.6-BL 7107.1,4558.7 r0 top
U3$CBB49 "MCP6024T-I/SL-MS" SOIC-14_L8.7-W3.9-P1.27-LS6.0-BL-1#1 7646.6,5210.6 r270 top
U4$CBB7 "XC2361A" TSOT-23-6_L2.9-W1.6-P0.95-LS2.6-BL 6887.1,3958.7 r0 top
U4$CBB9 "MCP6024T-I/SL-MS" SOIC-14_L8.7-W3.9-P1.27-LS6.0-BL-1#1 9087,5210.6 r270 top
U4$CBB19 "MCP6024T-I/SL-MS" SOIC-14_L8.7-W3.9-P1.27-LS6.0-BL-1#1 9087.1,5210.6 r90 bottom
U4$CBB21 "XC2361A" TSOT-23-6_L2.9-W1.6-P0.95-LS2.6-BL 7105.9,3959.5 r0 top
U4$CBB49 "MCP6024T-I/SL-MS" SOIC-14_L8.7-W3.9-P1.27-LS6.0-BL-1#1 8664,5210.6 r270 top
U5 "AP64350SP-13" SO-8_L4.9-W3.9-P1.27-LS6.0-BL-EP#1 3869.7,8723.9 r0 top
U5$CBB7 "XC2361A" TSOT-23-6_L2.9-W1.6-P0.95-LS2.6-BL 6887.1,4158.7 r0 top
U5$CBB9 "MCP6024T-I/SL-MS" SOIC-14_L8.7-W3.9-P1.27-LS6.0-BL-1#1 10104.4,5210.6 r270 top
U5$CBB19 "MCP6024T-I/SL-MS" SOIC-14_L8.7-W3.9-P1.27-LS6.0-BL-1#1 10104.4,5210.6 r90 bottom
U5$CBB21 "XC2361A" TSOT-23-6_L2.9-W1.6-P0.95-LS2.6-BL 7105.9,4162.7 r0 top
U5$CBB49 "MCP6024T-I/SL-MS" SOIC-14_L8.7-W3.9-P1.27-LS6.0-BL-1#1 9681.4,5210.6 r270 top
U6 "AP64350SP-13" SO-8_L4.9-W3.9-P1.27-LS6.0-BL-EP#2 3943.1,9180.6 r270 top
U6$CBB16/CBB1 "74HC595" SOP-16_L9.9-W3.9-P1.27-LS6.0-BL#1 4986.7,8521.8 r270 top
U6$CBB16/CBB2 "74HC595" SOP-16_L9.9-W3.9-P1.27-LS6.0-BL#1 4986.7,8974.6 r270 top
U6$CBB16/CBB3 "74HC595" SOP-16_L9.9-W3.9-P1.27-LS6.0-BL#1 4986.7,8069.1 r270 top
U6$CBB16/CBB4 "74HC595" SOP-16_L9.9-W3.9-P1.27-LS6.0-BL#1 4986.7,7616.3 r270 top
U6$CBB16/CBB5 "74HC595" SOP-16_L9.9-W3.9-P1.27-LS6.0-BL#1 4986.7,7163.6 r270 top
U6$CBB16/CBB6 "74HC595" SOP-16_L9.9-W3.9-P1.27-LS6.0-BL#1 4986.7,6710.8 r270 top
U6$CBB17/CBB1 "74HC595" SOP-16_L9.9-W3.9-P1.27-LS6.0-BL#1 5611.7,8974.6 r270 top
U6$CBB17/CBB2 "74HC595" SOP-16_L9.9-W3.9-P1.27-LS6.0-BL#1 5611.7,8521.8 r270 top
U6$CBB17/CBB3 "74HC595" SOP-16_L9.9-W3.9-P1.27-LS6.0-BL#1 5611.7,8069.1 r270 top
U6$CBB17/CBB4 "74HC595" SOP-16_L9.9-W3.9-P1.27-LS6.0-BL#1 5611.7,7616.3 r270 top
U6$CBB17/CBB5 "74HC595" SOP-16_L9.9-W3.9-P1.27-LS6.0-BL#1 5611.7,7163.6 r270 top
U6$CBB17/CBB6 "74HC595" SOP-16_L9.9-W3.9-P1.27-LS6.0-BL#1 5611.7,6710.8 r270 top
U6$CBB17/CBB7 "74HC595" SOP-16_L9.9-W3.9-P1.27-LS6.0-BL#1 5611.7,6258.1 r270 top
U6$CBB17/CBB8 "74HC595" SOP-16_L9.9-W3.9-P1.27-LS6.0-BL#1 5611.7,5805.3 r270 top
U6$CBB18/CBB1 "74HC595" SOP-16_L9.9-W3.9-P1.27-LS6.0-BL#2 6241.6,8974.6 r270 top
U6$CBB18/CBB2 "74HC595" SOP-16_L9.9-W3.9-P1.27-LS6.0-BL#2 6241.6,8521.8 r270 top
U6$CBB18/CBB3 "74HC595" SOP-16_L9.9-W3.9-P1.27-LS6.0-BL#2 6241.6,8069.1 r270 top
U6$CBB18/CBB4 "74HC595" SOP-16_L9.9-W3.9-P1.27-LS6.0-BL#2 6241.6,7616.3 r270 top
U6$CBB18/CBB5 "74HC595" SOP-16_L9.9-W3.9-P1.27-LS6.0-BL#2 6241.6,7163.6 r270 top
U6$CBB18/CBB6 "74HC595" SOP-16_L9.9-W3.9-P1.27-LS6.0-BL#2 6241.6,6710.8 r270 top
U6$CBB18/CBB7 "74HC595" SOP-16_L9.9-W3.9-P1.27-LS6.0-BL#2 6241.6,6258.1 r270 top
U6$CBB18/CBB8 "74HC595" SOP-16_L9.9-W3.9-P1.27-LS6.0-BL#2 6241.6,5805.3 r270 top
U6$CBB20/CBB1 "74HC595" SOP-16_L9.9-W3.9-P1.27-LS6.0-BL#2 6871.5,8974.6 r270 top
U6$CBB20/CBB2 "74HC595" SOP-16_L9.9-W3.9-P1.27-LS6.0-BL#2 6871.5,8521.8 r270 top
U6$CBB20/CBB3 "74HC595" SOP-16_L9.9-W3.9-P1.27-LS6.0-BL#2 6871.5,8069.1 r270 top
U6$CBB20/CBB4 "74HC595" SOP-16_L9.9-W3.9-P1.27-LS6.0-BL#2 6871.5,7616.3 r270 top
U6$CBB20/CBB5 "74HC595" SOP-16_L9.9-W3.9-P1.27-LS6.0-BL#2 6871.5,7163.6 r270 top
U6$CBB20/CBB6 "74HC595" SOP-16_L9.9-W3.9-P1.27-LS6.0-BL#2 6871.5,6710.8 r270 top
U6$CBB20/CBB7 "74HC595" SOP-16_L9.9-W3.9-P1.27-LS6.0-BL#2 6871.5,6258.1 r270 top
U6$CBB20/CBB8 "74HC595" SOP-16_L9.9-W3.9-P1.27-LS6.0-BL#2 6871.5,5805.3 r270 top
U7 "AP64350SP-13" SO-8_L4.9-W3.9-P1.27-LS6.0-BL-EP#2 3570.7,7863.7 r270 top
U7$CBB7 "XC2361A" TSOT-23-6_L2.9-W1.6-P0.95-LS2.6-BL 6886.6,4955.7 r0 top
U7$CBB21 "XC2361A" TSOT-23-6_L2.9-W1.6-P0.95-LS2.6-BL 7105.9,4955.7 r0 top
U9 "MP2393GTL-Z" SOT-583-8_L2.1-W1.2-P0.50-LS1.6-BL#1 3611.1,6418.3 r270 top
U10 "MPQ6400DG-01-LF-Z" QFN-6_L2.0-W2.0-P0.65-BL-EP 3902.7,8094.1 r0 top
U12 "MP2393GTL-Z" SOT-583-8_L2.1-W1.2-P0.50-LS1.6-BL#2 3611.1,6930.2 r270 top
U14 "APX803S-31SA-7" SOT-23-3_L2.9-W1.3-P1.90-LS2.4-BR#1 4896.7,3989.2 r90 top
U16 "MP2393GTL-Z" SOT-583-8_L2.1-W1.2-P0.50-LS1.6-BL#2 3611.1,7442 r270 top
U19$CBB23 "W25Q64JVZPIQ" WSON-8_L6.0-W5.0-P1.27-BL-EP 3452.9,5283.2 r0 top
U93$CBB23 "PZ2.54-2*4" HDR-TH_8P-P2.54-V-M-R2-C4-S2.54 3284.5,4855.7 r180 top
U93$CBB24 "PZ2.54-2*4" HDR-TH_8P-P2.54-V-M-R2-C4-S2.54 3287.9,4610.9 r180 top
U95$CBB22/CBB1 "PCA9306DC1" VSSOP-8_L2.4-W2.1-P0.50-LS3.2-BR#2 6306.1,3618.8 r0 bottom
U98$CBB22/CBB2 "RTL8211F-CG" WQFN-40_L5.0-W5.0-P0.4-BL-EP 4557.9,4243.2 r0 top locked
U98$CBB24 "FT2232HL-REEL" LQFP-64_L10.0-W10.0-P0.50-LS12.0-TL 3517.9,4151.8 r90 top
U99$CBB22 "W25Q128JVSIQ" SOIC-8_L5.3-W5.3-P1.27-LS8.0-BL 4269,5015.8 r270 top
U100$CBB22 "T120F324C3" BGA324C65P18X18_1200X1200X97N 5477.9,4558.2 r180 top locked
U101$CBB24 "12MHz" CRYSTAL-SMD_4P-L3.2-W2.5-BL 3255.5,3799.9 r90 top
U102$CBB24 "93LC56BT-I/OT" SOT-23-6_L2.9-W1.6-P0.95-LS2.8-BR 3165.7,4052.4 r90 top
U103$CBB24 "BLM15PX330SN1D" L0402#3 3140.8,4401.5 r0 top
U104$CBB24 "BLM15PX330SN1D" L0402#1 3142.8,4305.1 r0 top
U110$CBB24 "PZ2.54-2*4" HDR-TH_8P-P2.54-V-M-R2-C4-S2.54 3713.6,4610.9 r180 top
U111$CBB24 "PZ2.54-2*4" HDR-TH_8P-P2.54-V-M-R2-C4-S2.54 3943.8,3760.2 r270 top
U112$CBB22 "PZ2.54-2*4" HDR-TH_8P-P2.54-V-M-R2-C4-S2.54 5789.8,3554.1 r270 top locked
U112$CBB24 "PZ2.54-2*4" HDR-TH_8P-P2.54-V-M-R2-C4-S2.54 3943.8,3330.2 r90 top
U118$CBB23 "APX803S-31SA-7" SOT-23-3_L2.9-W1.3-P1.90-LS2.4-BR#2 3173.5,5947.5 r270 top
USB3$CBB24 "USB-B10-BRW" USB-B-TH_USB-B10-BRW 3516.8,3395.5 r270 top
X1 "50MHz" OSC-SMD_4P-L3.2-W2.5-BL#1 5015.2,4142 r180 bottom
X1$CBB23 "50MHz" OSC-SMD_4P-L3.2-W2.5-BL#2 4426.3,5550.3 r180 bottom
X4$CBB22/CBB2 "25MHz" CRYSTAL-SMD_4P-L5.0-W3.2-BL 4233.7,4192.6 r0 top

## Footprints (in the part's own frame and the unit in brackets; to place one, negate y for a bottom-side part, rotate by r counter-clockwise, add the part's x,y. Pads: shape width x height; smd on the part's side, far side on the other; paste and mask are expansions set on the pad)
BGA324C65P18X18_1200X1200X97N [mil]
  round 12.6 smd paste+0 mask+0: A1(-217.5,217.5) A2(-191.9,217.5) A3(-166.3,217.5) A4(-140.7,217.5) A5(-115.1,217.5) A6(-89.5,217.5) A7(-63.9,217.5) A8(-38.4,217.5) A9(-12.8,217.5) A10(12.8,217.5) A11(38.4,217.5) A12(64,217.5) A13(89.6,217.5) A14(115.2,217.5) A15(140.8,217.5) A16(166.4,217.5) A17(192,217.5) A18(217.5,217.5) B1(-217.5,191.9) B2(-191.9,191.9) B3(-166.3,191.9) B4(-140.7,191.9) B5(-115.1,191.9) B6(-89.5,191.9) B7(-63.9,191.9) B8(-38.4,191.9) B9(-12.8,191.9) B10(12.8,191.9) B11(38.4,191.9) B12(64,191.9) B13(89.6,191.9) B14(115.2,191.9) B15(140.8,191.9) B16(166.4,191.9) B17(192,191.9) B18(217.5,191.9) C1(-217.5,166.3) C2(-191.9,166.3) C3(-166.3,166.3) C4(-140.7,166.3) C5(-115.1,166.3) C6(-89.5,166.3) C7(-63.9,166.3) C8(-38.4,166.3) C9(-12.8,166.3) C10(12.8,166.3) C11(38.4,166.3) C12(64,166.3) C13(89.6,166.3) C14(115.2,166.3) C15(140.8,166.3) C16(166.4,166.3) C17(192,166.3) C18(217.5,166.3) D1(-217.5,140.8) D2(-191.9,140.8) D3(-166.3,140.8) D4(-140.7,140.8) D5(-115.1,140.8) D6(-89.5,140.8) D7(-63.9,140.8) D8(-38.4,140.8) D9(-12.8,140.8) D10(12.8,140.8) D11(38.4,140.8) D12(64,140.8) D13(89.6,140.8) D14(115.2,140.8) D15(140.8,140.8) D16(166.4,140.8) D17(192,140.8) D18(217.5,140.8) E1(-217.5,115.2) E2(-191.9,115.2) E3(-166.3,115.2) E4(-140.7,115.2) E5(-115.1,115.2) E6(-89.5,115.2) E7(-63.9,115.2) E8(-38.4,115.2) E9(-12.8,115.2) E10(12.8,115.2) E11(38.4,115.2) E12(64,115.2) E13(89.6,115.2) E14(115.2,115.2) E15(140.8,115.2) E16(166.4,115.2) E17(192,115.2) E18(217.5,115.2) F1(-217.5,89.6) F2(-191.9,89.6) F3(-166.3,89.6) F4(-140.7,89.6) F5(-115.1,89.6) F6(-89.5,89.6) F7(-63.9,89.6) F8(-38.4,89.6) F9(-12.8,89.6) F10(12.8,89.6) F11(38.4,89.6) F12(64,89.6) F13(89.6,89.6) F14(115.2,89.6) F15(140.8,89.6) F16(166.4,89.6) F17(192,89.6) F18(217.5,89.6) G1(-217.5,64) G2(-191.9,64) G3(-166.3,64) G4(-140.7,64) G5(-115.1,64) G6(-89.5,64) G7(-63.9,64) G8(-38.4,64) G9(-12.8,64) G10(12.8,64) G11(38.4,64) G12(64,64) G13(89.6,64) G14(115.2,64) G15(140.8,64) G16(166.4,64) G17(192,64) G18(217.5,64) H1(-217.5,38.4) H2(-191.9,38.4) H3(-166.3,38.4) H4(-140.7,38.4) H5(-115.1,38.4) H6(-89.5,38.4) H7(-63.9,38.4) H8(-38.4,38.4) H9(-12.8,38.4) H10(12.8,38.4) H11(38.4,38.4) H12(64,38.4) H13(89.6,38.4) H14(115.2,38.4) H15(140.8,38.4) H16(166.4,38.4) H17(192,38.4) H18(217.5,38.4) J1(-217.5,12.8) J2(-191.9,12.8) J3(-166.3,12.8) J4(-140.7,12.8) J5(-115.1,12.8) J6(-89.5,12.8) J7(-63.9,12.8) J8(-38.4,12.8) J9(-12.8,12.8) J10(12.8,12.8) J11(38.4,12.8) J12(64,12.8) J13(89.6,12.8) J14(115.2,12.8) J15(140.8,12.8) J16(166.4,12.8) J17(192,12.8) J18(217.5,12.8) K1(-217.5,-12.8) K2(-191.9,-12.8) K3(-166.3,-12.8) K4(-140.7,-12.8) K5(-115.1,-12.8) K6(-89.5,-12.8) K7(-63.9,-12.8) K8(-38.4,-12.8) K9(-12.8,-12.8) K10(12.8,-12.8) K11(38.4,-12.8) K12(64,-12.8) K13(89.6,-12.8) K14(115.2,-12.8) K15(140.8,-12.8) K16(166.4,-12.8) K17(192,-12.8) K18(217.5,-12.8) L1(-217.5,-38.4) L2(-191.9,-38.4) L3(-166.3,-38.4) L4(-140.7,-38.4) L5(-115.1,-38.4) L6(-89.5,-38.4) L7(-63.9,-38.4) L8(-38.4,-38.4) L9(-12.8,-38.4) L10(12.8,-38.4) L11(38.4,-38.4) L12(64,-38.4) L13(89.6,-38.4) L14(115.2,-38.4) L15(140.8,-38.4) L16(166.4,-38.4) L17(192,-38.4) L18(217.5,-38.4) M1(-217.5,-64) M2(-191.9,-64) M3(-166.3,-64) M4(-140.7,-64) M5(-115.1,-64) M6(-89.5,-64) M7(-63.9,-64) M8(-38.4,-64) M9(-12.8,-64) M10(12.8,-64) M11(38.4,-64) M12(64,-64) M13(89.6,-64) M14(115.2,-64) M15(140.8,-64) M16(166.4,-64) M17(192,-64) M18(217.5,-64) N1(-217.5,-89.6) N2(-191.9,-89.6) N3(-166.3,-89.6) N4(-140.7,-89.6) N5(-115.1,-89.6) N6(-89.5,-89.6) N7(-64,-89.6) N8(-38.4,-89.6) N9(-12.8,-89.6) N10(12.8,-89.6) N11(38.4,-89.6) N12(64,-89.6) N13(89.6,-89.6) N14(115.2,-89.6) N15(140.8,-89.6) N16(166.4,-89.6) N17(192,-89.6) N18(217.5,-89.6) P1(-217.5,-115.1) P2(-191.9,-115.1) P3(-166.3,-115.1) P4(-140.7,-115.1) P5(-115.1,-115.1) P6(-89.5,-115.1) P7(-64,-115.1) P8(-38.4,-115.1) P9(-12.8,-115.1) P10(12.8,-115.1) P11(38.4,-115.1) P12(64,-115.1) P13(89.6,-115.1) P14(115.2,-115.1) P15(140.8,-115.1) P16(166.4,-115.1) P17(192,-115.1) P18(217.5,-115.1) R1(-217.5,-140.7) R2(-191.9,-140.7) R3(-166.3,-140.7) R4(-140.7,-140.7) R5(-115.1,-140.7) R6(-89.5,-140.7) R7(-64,-140.7) R8(-38.4,-140.7) R9(-12.8,-140.7) R10(12.8,-140.7) R11(38.4,-140.7) R12(64,-140.7) R13(89.6,-140.7) R14(115.2,-140.7) R15(140.8,-140.7) R16(166.4,-140.7) R17(192,-140.7) R18(217.5,-140.7) T1(-217.5,-166.3) T2(-191.9,-166.3) T3(-166.3,-166.3) T4(-140.7,-166.3) T5(-115.1,-166.3) T6(-89.5,-166.3) T7(-64,-166.3) T8(-38.4,-166.3) T9(-12.8,-166.3) T10(12.8,-166.3) T11(38.4,-166.3) T12(64,-166.3) T13(89.6,-166.3) T14(115.2,-166.3) T15(140.8,-166.3) T16(166.4,-166.3) T17(192,-166.3) T18(217.5,-166.3) U1(-217.5,-191.9) U2(-191.9,-191.9) U3(-166.3,-191.9) U4(-140.7,-191.9) U5(-115.1,-191.9) U6(-89.5,-191.9) U7(-64,-191.9) U8(-38.4,-191.9) U9(-12.8,-191.9) U10(12.8,-191.9) U11(38.4,-191.9) U12(64,-191.9) U13(89.6,-191.9) U14(115.2,-191.9) U15(140.8,-191.9) U16(166.4,-191.9) U17(192,-191.9) U18(217.5,-191.9) V1(-217.5,-217.5) V2(-191.9,-217.5) V3(-166.3,-217.5) V4(-140.7,-217.5) V5(-115.1,-217.5) V6(-89.5,-217.5) V7(-64,-217.5) V8(-38.4,-217.5) V9(-12.8,-217.5) V10(12.8,-217.5) V11(38.4,-217.5) V12(64,-217.5) V13(89.6,-217.5) V14(115.2,-217.5) V15(140.8,-217.5) V16(166.4,-217.5) V17(192,-217.5) V18(217.5,-217.5)
  silkscreen extent -260,-236 236,236
C0201 [mil]
  rect 14.5x12.8 smd paste-3937 mask+2: 1(-10.8,0) 2(10.8,0)
  silkscreen extent -27,-15 27,15
C0402#1 [mil]
  rect 31.1x21.3 smd paste-3937 mask+2: 1(-21.5,0) 2(21.4,0)
  silkscreen extent -46,-20 46,20
C0402#2 [mil]
  rect 19.7x21.3 smd: 1(-16.6,0) 2(16.5,0)
  silkscreen extent -34,-20 34,20
C0402#3 [mil]
  rect 19.7x21.3 smd: 1(-16.5,0) 2(16.6,0)
  silkscreen extent -34,-20 34,20
C0402#4 [mil]
  rect 31.1x21.3 smd paste-3937 mask+2: 1(-21.5,0) 2(21.5,0)
  silkscreen extent -46,-20 46,20
C0402#5 [mil]
  rect 31.1x21.3 smd paste-3937 mask+2: 1(-21.4,0) 2(21.5,0)
  silkscreen extent -46,-20 46,20
C0402#6 [mil]
  rect 19.7x21.3 smd: 1(-16.5,0) 2(16.5,0)
  silkscreen extent -34,-20 34,20
C1206 [mil]
  rect 58.5x68 smd paste-3937 mask+2: 1(-62.7,0) 2(62.7,0)
  silkscreen extent -101,-43 101,43
C2220#1 [mil]
  rect 79.1x212.6 smd paste-3937 mask+2: 1(-101.6,0) 2(101.6,0)
  silkscreen extent -150,-115 150,115
C2220#2 [mil]
  rect 79.1x212.6 smd paste-3937 mask+2: 1(-101.5,0) 2(101.6,0)
  silkscreen extent -150,-115 150,115
CAP-SMD_BD6.3-L6.6-W6.6-FD#1 [mil]
  rect 137.8x47.2 smd: 1(-105.2,0) 2(105.1,0)
  silkscreen extent -133,-133 133,133
CAP-SMD_BD6.3-L6.6-W6.6-FD#2 [mil]
  rect 137.8x47.2 smd: 1(-105.1,0) 2(105.1,0)
  silkscreen extent -133,-133 133,133
CAP-SMD_BD8.0-L8.3-W8.3-FD [mil]
  rect 165.4x55.1 smd: 1(-128.6,0) 2(128.6,0)
  silkscreen extent -165,-166 165,166
CAP-SMD_BD10.0-L10.3-W10.3-LS11.0-FD#1 [mil]
  rect 177.2x65 smd: 1(-177.2,0) 2(177.2,0)
  silkscreen extent -206,-206 206,206
CAP-SMD_BD10.0-L10.3-W10.3-LS11.0-FD#2 [mil]
  rect 177.2x65 smd: 1(-177.1,0) 2(177.2,0)
  silkscreen extent -206,-206 206,206
CONN-TH_P5.00_KF301-5.0-2P [mil]
  round 86.6 hole 55.1: 1(-98.4,0) 2(98.4,0)
  silkscreen extent -197,-146 225,158
CRYSTAL-SMD_4P-L3.2-W2.5-BL [mil]
  rect 55.1x47.2 smd: 1(-43.3,-33.4) 2(43.3,-33.4) 3(43.3,33.5) 4(-43.3,33.5)
  silkscreen extent -89,-75 80,66
CRYSTAL-SMD_4P-L5.0-W3.2-BL [mil]
  rect 63x47.2 smd: 1(-78.8,-47.2) 2(78.7,-47.2) 3(78.7,47.3) 4(-78.8,47.3)
  silkscreen extent -98,-72 98,63
D0402-BI#1 [mil]
  rect 23.6x23.6 smd paste-3937 mask+2: 1(-19.7,0) 2(19.7,0)
  silkscreen extent -46,-20 46,20
D0402-BI#2 [mil]
  rect 23.6x23.6 smd paste-3937 mask+2: 1(-19.7,0) 2(19.6,0)
  silkscreen extent -46,-20 46,20
D0402-BI#3 [mil]
  rect 23.6x23.6 smd paste-3937 mask+2: 1(-19.6,0) 2(19.7,0)
  silkscreen extent -46,-20 46,20
FBGA-256_L13.0-W13.0-R16-C16-P0.80-TL [mil]
  round 14.2 smd: A1(-236.2,236.2) A2(-204.7,236.2) A3(-173.3,236.2) A4(-141.8,236.2) A5(-110.3,236.2) A6(-78.8,236.2) A7(-47.3,236.2) A8(-15.8,236.2) A9(15.7,236.2) A10(47.2,236.2) A11(78.7,236.2) A12(110.2,236.2) A13(141.7,236.2) A14(173.2,236.2) A15(204.7,236.2) A16(236.2,236.2) B1(-236.2,204.7) B2(-204.7,204.7) B3(-173.3,204.7) B4(-141.8,204.7) B5(-110.3,204.7) B6(-78.8,204.7) B7(-47.3,204.7) B8(-15.8,204.7) B9(15.7,204.7) B10(47.2,204.7) B11(78.7,204.7) B12(110.2,204.7) B13(141.7,204.7) B14(173.2,204.7) B15(204.7,204.7) B16(236.2,204.7) C1(-236.2,173.2) C2(-204.7,173.2) C3(-173.3,173.2) C4(-141.8,173.2) C5(-110.3,173.2) C6(-78.8,173.2) C7(-47.3,173.2) C8(-15.8,173.2) C9(15.7,173.2) C10(47.2,173.2) C11(78.7,173.2) C12(110.2,173.2) C13(141.7,173.2) C14(173.2,173.2) C15(204.7,173.2) C16(236.2,173.2) D1(-236.2,141.7) D2(-204.7,141.7) D3(-173.3,141.7) D4(-141.8,141.7) D5(-110.3,141.7) D6(-78.8,141.7) D7(-47.3,141.7) D8(-15.8,141.7) D9(15.7,141.7) D10(47.2,141.7) D11(78.7,141.7) D12(110.2,141.7) D13(141.7,141.7) D14(173.2,141.7) D15(204.7,141.7) D16(236.2,141.7) E1(-236.2,110.2) E2(-204.7,110.2) E3(-173.3,110.2) E4(-141.8,110.2) E5(-110.3,110.2) E6(-78.8,110.2) E7(-47.3,110.2) E8(-15.8,110.2) E9(15.7,110.2) E10(47.2,110.2) E11(78.7,110.2) E12(110.2,110.2) E13(141.7,110.2) E14(173.2,110.2) E15(204.7,110.2) E16(236.2,110.2) F1(-236.2,78.7) F2(-204.7,78.7) F3(-173.3,78.7) F4(-141.8,78.7) F5(-110.3,78.7) F6(-78.8,78.7) F7(-47.3,78.7) F8(-15.8,78.7) F9(15.7,78.7) F10(47.2,78.7) F11(78.7,78.7) F12(110.2,78.7) F13(141.7,78.7) F14(173.2,78.7) F15(204.7,78.7) F16(236.2,78.7) G1(-236.2,47.2) G2(-204.7,47.2) G3(-173.3,47.2) G4(-141.8,47.2) G5(-110.3,47.2) G6(-78.8,47.2) G7(-47.3,47.2) G8(-15.8,47.2) G9(15.7,47.2) G10(47.2,47.2) G11(78.7,47.2) G12(110.2,47.2) G13(141.7,47.2) G14(173.2,47.2) G15(204.7,47.2) G16(236.2,47.2) H1(-236.2,15.7) H2(-204.7,15.7) H3(-173.3,15.7) H4(-141.8,15.7) H5(-110.3,15.7) H6(-78.8,15.7) H7(-47.3,15.7) H8(-15.8,15.7) H9(15.7,15.7) H10(47.2,15.7) H11(78.7,15.7) H12(110.2,15.7) H13(141.7,15.7) H14(173.2,15.7) H15(204.7,15.7) H16(236.2,15.7) J1(-236.2,-15.8) J2(-204.7,-15.8) J3(-173.3,-15.8) J4(-141.8,-15.8) J5(-110.3,-15.8) J6(-78.8,-15.8) J7(-47.3,-15.8) J8(-15.8,-15.8) J9(15.7,-15.8) J10(47.2,-15.8) J11(78.7,-15.8) J12(110.2,-15.8) J13(141.7,-15.8) J14(173.2,-15.8) J15(204.7,-15.8) J16(236.2,-15.8) K1(-236.2,-47.3) K2(-204.7,-47.3) K3(-173.3,-47.3) K4(-141.8,-47.3) K5(-110.3,-47.3) K6(-78.8,-47.3) K7(-47.3,-47.3) K8(-15.8,-47.3) K9(15.7,-47.3) K10(47.2,-47.3) K11(78.7,-47.3) K12(110.2,-47.3) K13(141.7,-47.3) K14(173.2,-47.3) K15(204.7,-47.3) K16(236.2,-47.3) L1(-236.2,-78.7) L2(-204.7,-78.7) L3(-173.3,-78.7) L4(-141.8,-78.7) L5(-110.3,-78.7) L6(-78.8,-78.7) L7(-47.3,-78.7) L8(-15.8,-78.7) L9(15.7,-78.7) L10(47.2,-78.7) L11(78.7,-78.7) L12(110.2,-78.7) L13(141.7,-78.7) L14(173.2,-78.7) L15(204.7,-78.7) L16(236.2,-78.7) M1(-236.2,-110.2) M2(-204.7,-110.2) M3(-173.3,-110.2) M4(-141.8,-110.2) M5(-110.3,-110.2) M6(-78.8,-110.2) M7(-47.3,-110.2) M8(-15.8,-110.2) M9(15.7,-110.2) M10(47.2,-110.2) M11(78.7,-110.2) M12(110.2,-110.2) M13(141.7,-110.2) M14(173.2,-110.2) M15(204.7,-110.2) M16(236.2,-110.2) N1(-236.2,-141.7) N2(-204.7,-141.7) N3(-173.3,-141.7) N4(-141.8,-141.7) N5(-110.3,-141.7) N6(-78.8,-141.7) N7(-47.3,-141.7) N8(-15.8,-141.7) N9(15.7,-141.7) N10(47.2,-141.7) N11(78.7,-141.7) N12(110.2,-141.7) N13(141.7,-141.7) N14(173.2,-141.7) N15(204.7,-141.7) N16(236.2,-141.7) P1(-236.2,-173.2) P2(-204.7,-173.2) P3(-173.3,-173.2) P4(-141.8,-173.2) P5(-110.3,-173.2) P6(-78.8,-173.2) P7(-47.3,-173.2) P8(-15.8,-173.2) P9(15.7,-173.2) P10(47.2,-173.2) P11(78.7,-173.2) P12(110.2,-173.2) P13(141.7,-173.2) P14(173.2,-173.2) P15(204.7,-173.2) P16(236.2,-173.2) R1(-236.2,-204.7) R2(-204.7,-204.7) R3(-173.3,-204.7) R4(-141.8,-204.7) R5(-110.3,-204.7) R6(-78.8,-204.7) R7(-47.3,-204.7) R8(-15.8,-204.7) R9(15.7,-204.7) R10(47.2,-204.7) R11(78.7,-204.7) R12(110.2,-204.7) R13(141.7,-204.7) R14(173.2,-204.7) R15(204.7,-204.7) R16(236.2,-204.7) T1(-236.2,-236.2) T2(-204.7,-236.2) T3(-173.3,-236.2) T4(-141.8,-236.2) T5(-110.3,-236.2) T6(-78.8,-236.2) T7(-47.3,-236.2) T8(-15.8,-236.2) T9(15.7,-236.2) T10(47.2,-236.2) T11(78.7,-236.2) T12(110.2,-236.2) T13(141.7,-236.2) T14(173.2,-236.2) T15(204.7,-236.2) T16(236.2,-236.2)
  silkscreen extent -275,-255 255,275
FPC-SMD_522711579#1 [mil]
  rect 23.6x74.8 smd paste+0 mask+2: 1(-275.5,46.3) 2(-236.2,46.3) 3(-196.8,46.3) 4(-157.4,46.3) 5(-118.1,46.3) 6(-78.7,46.3) 7(-39.3,46.3) 8(0,46.3) 9(39.4,46.3) 10(78.8,46.3) 11(118.2,46.3) 12(157.5,46.3) 13(196.9,46.3) 14(236.3,46.3) 15(275.6,46.3)
  rect 82.7x110.2 smd paste+0 mask+2: 16(399.7,-46.2) 17(-399.6,-46.2)
  silkscreen extent -435,-265 435,48
FPC-SMD_522711579#2 [mil]
  rect 23.6x74.8 smd paste+0 mask+2: 1(-275.6,46.3) 2(-236.2,46.3) 3(-196.8,46.3) 4(-157.4,46.3) 5(-118.1,46.3) 6(-78.7,46.3) 7(-39.3,46.3) 8(0,46.3) 9(39.4,46.3) 10(78.8,46.3) 11(118.1,46.3) 12(157.5,46.3) 13(196.9,46.3) 14(236.3,46.3) 15(275.6,46.3)
  rect 82.7x110.2 smd paste+0 mask+2: 16(399.7,-46.2) 17(-399.6,-46.2)
  silkscreen extent -435,-265 435,48
HDR-TH_03P-P2.54-V-M [mil]
  rect 62x66.9 hole 43.3: 1(-100,0)
  round 66.9 hole 43.3: 2(0,0) 3(100,0)
  silkscreen extent -158,-50 158,50
HDR-TH_8P-P2.54-V-M-R2-C4-S2.54 [mil]
  rect 66.9x66.9 hole 43.3: 1(-150,-50)
  round 66.9 hole 43.3: 2(-150,50) 3(-50,-50) 4(-50,50) 5(50,-50) 6(50,50) 7(150,-50) 8(150,50)
  silkscreen extent -200,-100 200,100
IND-SMD_L6.6-W6.6#1 [mil]
  rect 92.5x137.8 smd: 1(-119.5,0) 2(119.4,0)
  silkscreen extent -130,-130 130,130
IND-SMD_L6.6-W6.6#2 [mil]
  rect 92.5x137.8 smd: 1(-119.5,0) 2(119.5,0)
  silkscreen extent -130,-130 130,130
IND-SMD_L7.8-W7.0_GCD75#1 [mil]
  rect 157.5x307.1 smd: 1(-108.3,0) 2(108.2,0)
  silkscreen extent -156,-165 152,165
IND-SMD_L7.8-W7.0_GCD75#2 [mil]
  rect 157.5x307.1 smd: 1(-108.3,0) 2(108.3,0)
  silkscreen extent -156,-165 152,165
IND-SMD_L7.8-W7.0_SUMIDA_CD73 [mil]
  rect 118.1x295.3 smd paste+0 mask+2: 1(-98.4,0) 2(98.5,0)
  silkscreen extent -30,-138 30,138
L0402#1 [mil]
  rect 31.1x21.3 smd paste-3937 mask+2: 1(-21.5,0) 2(21.5,0)
  silkscreen extent -46,-20 46,20
L0402#2 [mil]
  rect 31.1x21.3 smd paste-3937 mask+2: 1(-21.4,0) 2(21.5,0)
  silkscreen extent -46,-20 46,20
L0402#3 [mil]
  rect 31.1x21.3 smd paste-3937 mask+2: 1(-21.5,0) 2(21.4,0)
  silkscreen extent -46,-20 46,20
L0805 [mil]
  rect 44.6x54.2 smd paste-3937 mask+2: 1(-38.1,0) 2(38,0)
  silkscreen extent -77,-40 73,40
LED0603-RD#1 [mil]
  rect 31.5x31.5 smd: 1(-31.5,0) 2(31.5,0)
  silkscreen extent -59,-29 55,30
LED0603-RD#2 [mil]
  rect 31.5x31.5 smd: 1(-31.5,-0.1) 2(31.5,0)
  silkscreen extent -59,-29 55,30
LED0603-RD#3 [mil]
  rect 31.5x31.5 smd: 1(-31.5,0) 2(31.4,0)
  silkscreen extent -59,-29 55,30
LED0603-RD#4 [mil]
  rect 31.5x31.5 smd: 1(-31.4,-0.1) 2(31.5,0)
  silkscreen extent -59,-29 55,30
LED0603-RD#5 [mil]
  rect 31.5x31.5 smd: 1(-31.5,-0.1) 2(31.4,0)
  silkscreen extent -59,-29 55,30
LED0603-RD#6 [mil]
  rect 31.5x31.5 smd: 1(-31.5,0) 2(31.5,0.1)
  silkscreen extent -59,-29 55,30
LED0603-RD#7 [mil]
  rect 31.5x31.5 smd: 1(-31.4,0) 2(31.5,0)
  silkscreen extent -59,-29 55,30
LQFP-64_L10.0-W10.0-P0.50-LS12.0-TL [mil]
  oval 70.9x11 smd paste+0 mask+2: 1(-218.5,147.7) 2(-218.5,128) 3(-218.5,108.3) 4(-218.5,88.6) 5(-218.5,68.9) 6(-218.5,49.2) 7(-218.5,29.6) 8(-218.5,9.9) 9(-218.5,-9.8) 10(-218.5,-29.5) 11(-218.5,-49.2) 12(-218.5,-68.9) 13(-218.5,-88.6) 14(-218.5,-108.2) 15(-218.5,-127.9) 16(-218.5,-147.6) 33(218.5,-147.6) 34(218.5,-127.9) 35(218.5,-108.2) 36(218.5,-88.6) 37(218.5,-68.9) 38(218.5,-49.2) 39(218.5,-29.5) 40(218.5,-9.8) 41(218.5,9.9) 42(218.5,29.6) 43(218.5,49.2) 44(218.5,68.9) 45(218.5,88.6) 46(218.5,108.3) 47(218.5,128) 48(218.5,147.7)
  oval 11x70.9 smd paste+0 mask+2: 17(-147.7,-218.5) 18(-128,-218.5) 19(-108.3,-218.5) 20(-88.6,-218.5) 21(-68.9,-218.5) 22(-49.2,-218.5) 23(-29.6,-218.5) 24(-9.9,-218.5) 25(9.8,-218.5) 26(29.5,-218.5) 27(49.2,-218.5) 28(68.9,-218.5) 29(88.6,-218.5) 30(108.2,-218.5) 31(127.9,-218.5) 32(147.6,-218.5) 49(147.6,218.5) 50(127.9,218.5) 51(108.2,218.5) 52(88.6,218.5) 53(68.9,218.5) 54(49.2,218.5) 55(29.5,218.5) 56(9.8,218.5) 57(-9.9,218.5) 58(-29.6,218.5) 59(-49.2,218.5) 60(-68.9,218.5) 61(-88.6,218.5) 62(-108.3,218.5) 63(-128,218.5) 64(-147.7,218.5)
  silkscreen extent -238,-167 167,179
OSC-SMD_4P-L3.2-W2.5-BL#1 [mil]
  rect 55.1x47.2 smd: 1(-43.3,-34.5) 2(43.3,-34.5) 3(43.3,34.4) 4(-43.3,34.4)
  silkscreen extent -90,-75 82,68
OSC-SMD_4P-L3.2-W2.5-BL#2 [mil]
  rect 55.1x47.2 smd: 1(-43.3,-34.5) 2(43.4,-34.5) 3(43.4,34.4) 4(-43.3,34.4)
  silkscreen extent -90,-75 82,68
QFN-6_L2.0-W2.0-P0.65-BL-EP [mil]
  rect 13.8x27.6 smd paste+0 mask+2: 1(-25.6,-41.3) 2(0,-41.3) 3(25.6,-41.3) 4(25.6,41.4) 5(0,41.4) 6(-25.6,41.4)
  rect 63x39.4 smd: 7(0,0)
  silkscreen extent -47,-71 47,43
R0402#1 [mil]
  rect 22.3x21.3 smd paste-3937 mask+2: 1(-17.1,0) 2(17,0)
  silkscreen extent -37,-20 37,20
R0402#2 [mil]
  rect 22.3x21.3 smd paste-3937 mask+2: 1(-17,0) 2(17.1,0)
  silkscreen extent -37,-20 37,20
R0402#3 [mil]
  rect 22.3x21.3 smd paste-3937 mask+2: 1(-17,0) 2(17,0)
  silkscreen extent -37,-20 37,20
R1210 [mil]
  rect 50.5x110.6 smd paste-3937 mask+2: 1(-56.7,0) 2(56.8,0)
  silkscreen extent -91,-64 91,64
R2512#1 [mil]
  rect 50.5x136.1 smd paste-3937 mask+2: 1(-120.7,0) 2(120.7,0)
  silkscreen extent -155,-77 155,77
R2512#2 [mil]
  rect 50.5x136.1 smd paste-3937 mask+2: 1(-120.7,0) 2(120.8,0)
  silkscreen extent -155,-77 155,77
RJ45-TH_HR911130C [mil]
  round 66.9 hole 43.3: 11(260,272.6) 12(160,272.6) 13(-160,272.6) 14(-260,272.6)
  rect 60x60 hole 35.8: P1(225,-272.6)
  round 60 hole 35.8: P2(175,-172.4) P3(125,-272.4) P4(75,-172.4) P5(25,-272.4) P6(-25,-172.4) P7(-75,-272.4) P8(-125,-172.4) P9(-175,-272.4) P10(-225,-172.4)
  round 85 hole 65: SHIELD0(-305.1,-42.5) SHIELD1(305.1,-42.5)
  Board Outline Layer lines w0.1: 288.4,77.6 288,70.6 286.9,63.6 284.9,56.8 282.3,50.3 278.9,44.1 274.9,38.3 270.3,33 265.1,28.2 259.4,24 253.3,20.5 246.9,17.7 240.1,15.6 233.2,14.2 226.2,13.6 219.1,13.8 212.2,14.8 205.3,16.5 198.7,19 192.4,22.2 186.5,26 181.1,30.5 176.2,35.6 171.9,41.1 168.2,47.1 165.2,53.5 162.9,60.2 161.3,67.1 160.5,74.1 160.5,81.1 161.3,88.1 162.9,95 165.2,101.7 168.2,108 171.9,114 176.2,119.6 181.1,124.7 186.5,129.1 192.4,133 198.7,136.2 205.3,138.7 212.2,140.4 219.1,141.3 226.2,141.5 233.2,141 240.1,139.6 246.9,137.5 253.3,134.7 259.4,131.1 265.1,127 270.3,122.2 274.9,116.9 278.9,111.1 282.3,104.9 284.9,98.4 286.9,91.6 288,84.6 288.4,77.6 ; -160.4,77.6 -160.8,70.6 -161.9,63.6 -163.9,56.8 -166.5,50.3 -169.9,44.1 -173.9,38.3 -178.5,33 -183.7,28.2 -189.4,24 -195.5,20.5 -201.9,17.7 -208.7,15.6 -215.6,14.2 -222.6,13.6 -229.7,13.8 -236.6,14.8 -243.5,16.5 -250.1,19 -256.4,22.2 -262.3,26 -267.7,30.5 -272.6,35.6 -276.9,41.1 -280.6,47.1 -283.6,53.5 -285.9,60.2 -287.5,67.1 -288.3,74.1 -288.3,81.1 -287.5,88.1 -285.9,95 -283.6,101.7 -280.6,108 -276.9,114 -272.6,119.6 -267.7,124.7 -262.3,129.1 -256.4,133 -250.1,136.2 -243.5,138.7 -236.6,140.4 -229.7,141.3 -222.6,141.5 -215.6,141 -208.7,139.6 -201.9,137.5 -195.5,134.7 -189.4,131.1 -183.7,127 -178.5,122.2 -173.9,116.9 -169.9,111.1 -166.5,104.9 -163.9,98.4 -161.9,91.6 -160.8,84.6 -160.4,77.6
  Board Outline Layer region: -160.4,77.6 -160.8,70.6 -161.9,63.6 -163.9,56.8 -166.5,50.3 -169.9,44.1 -173.9,38.3 -178.5,33 -183.7,28.2 -189.4,24 -195.5,20.5 -201.9,17.7 -208.7,15.6 -215.6,14.2 -222.6,13.6 -229.7,13.8 -236.6,14.8 -243.5,16.5 -250.1,19 -256.4,22.2 -262.3,26 -267.7,30.5 -272.6,35.6 -276.9,41.1 -280.6,47.1 -283.6,53.5 -285.9,60.2 -287.5,67.1 -288.3,74.1 -288.3,81.1 -287.5,88.1 -285.9,95 -283.6,101.7 -280.6,108 -276.9,114 -272.6,119.6 -267.7,124.7 -262.3,129.1 -256.4,133 -250.1,136.2 -243.5,138.7 -236.6,140.4 -229.7,141.3 -222.6,141.5 -215.6,141 -208.7,139.6 -201.9,137.5 -195.5,134.7 -189.4,131.1 -183.7,127 -178.5,122.2 -173.9,116.9 -169.9,111.1 -166.5,104.9 -163.9,98.4 -161.9,91.6 -160.8,84.6
  Board Outline Layer region: -160.4,77.6 -160.8,70.6 -161.9,63.6 -163.9,56.8 -166.5,50.3 -169.9,44.1 -173.9,38.3 -178.5,33 -183.7,28.2 -189.4,24 -195.5,20.5 -201.9,17.7 -208.7,15.6 -215.6,14.2 -222.6,13.6 -229.7,13.8 -236.6,14.8 -243.5,16.5 -250.1,19 -256.4,22.2 -262.3,26 -267.7,30.5 -272.6,35.6 -276.9,41.1 -280.6,47.1 -283.6,53.5 -285.9,60.2 -287.5,67.1 -288.3,74.1 -288.3,81.1 -287.5,88.1 -285.9,95 -283.6,101.7 -280.6,108 -276.9,114 -272.6,119.6 -267.7,124.7 -262.3,129.1 -256.4,133 -250.1,136.2 -243.5,138.7 -236.6,140.4 -229.7,141.3 -222.6,141.5 -215.6,141 -208.7,139.6 -201.9,137.5 -195.5,134.7 -189.4,131.1 -183.7,127 -178.5,122.2 -173.9,116.9 -169.9,111.1 -166.5,104.9 -163.9,98.4 -161.9,91.6 -160.8,84.6
  Board Outline Layer region: 288.4,77.6 288,70.6 286.9,63.6 284.9,56.8 282.3,50.3 278.9,44.1 274.9,38.3 270.3,33 265.1,28.2 259.4,24 253.3,20.5 246.9,17.7 240.1,15.6 233.2,14.2 226.2,13.6 219.1,13.8 212.2,14.8 205.3,16.5 198.7,19 192.4,22.2 186.5,26 181.1,30.5 176.2,35.6 171.9,41.1 168.2,47.1 165.2,53.5 162.9,60.2 161.3,67.1 160.5,74.1 160.5,81.1 161.3,88.1 162.9,95 165.2,101.7 168.2,108 171.9,114 176.2,119.6 181.1,124.7 186.5,129.1 192.4,133 198.7,136.2 205.3,138.7 212.2,140.4 219.1,141.3 226.2,141.5 233.2,141 240.1,139.6 246.9,137.5 253.3,134.7 259.4,131.1 265.1,127 270.3,122.2 274.9,116.9 278.9,111.1 282.3,104.9 284.9,98.4 286.9,91.6 288,84.6
  Board Outline Layer region: 288.4,77.6 288,70.6 286.9,63.6 284.9,56.8 282.3,50.3 278.9,44.1 274.9,38.3 270.3,33 265.1,28.2 259.4,24 253.3,20.5 246.9,17.7 240.1,15.6 233.2,14.2 226.2,13.6 219.1,13.8 212.2,14.8 205.3,16.5 198.7,19 192.4,22.2 186.5,26 181.1,30.5 176.2,35.6 171.9,41.1 168.2,47.1 165.2,53.5 162.9,60.2 161.3,67.1 160.5,74.1 160.5,81.1 161.3,88.1 162.9,95 165.2,101.7 168.2,108 171.9,114 176.2,119.6 181.1,124.7 186.5,129.1 192.4,133 198.7,136.2 205.3,138.7 212.2,140.4 219.1,141.3 226.2,141.5 233.2,141 240.1,139.6 246.9,137.5 253.3,134.7 259.4,131.1 265.1,127 270.3,122.2 274.9,116.9 278.9,111.1 282.3,104.9 284.9,98.4 286.9,91.6 288,84.6
  Multi-Layer board cut-out: -160.4,77.6 -160.8,70.6 -161.9,63.6 -163.9,56.8 -166.5,50.3 -169.9,44.1 -173.9,38.3 -178.5,33 -183.7,28.2 -189.4,24 -195.5,20.5 -201.9,17.7 -208.7,15.6 -215.6,14.2 -222.6,13.6 -229.7,13.8 -236.6,14.8 -243.5,16.5 -250.1,19 -256.4,22.2 -262.3,26 -267.7,30.5 -272.6,35.6 -276.9,41.1 -280.6,47.1 -283.6,53.5 -285.9,60.2 -287.5,67.1 -288.3,74.1 -288.3,81.1 -287.5,88.1 -285.9,95 -283.6,101.7 -280.6,108 -276.9,114 -272.6,119.6 -267.7,124.7 -262.3,129.1 -256.4,133 -250.1,136.2 -243.5,138.7 -236.6,140.4 -229.7,141.3 -222.6,141.5 -215.6,141 -208.7,139.6 -201.9,137.5 -195.5,134.7 -189.4,131.1 -183.7,127 -178.5,122.2 -173.9,116.9 -169.9,111.1 -166.5,104.9 -163.9,98.4 -161.9,91.6 -160.8,84.6
  Multi-Layer board cut-out: 288.4,77.6 288,70.6 286.9,63.6 284.9,56.8 282.3,50.3 278.9,44.1 274.9,38.3 270.3,33 265.1,28.2 259.4,24 253.3,20.5 246.9,17.7 240.1,15.6 233.2,14.2 226.2,13.6 219.1,13.8 212.2,14.8 205.3,16.5 198.7,19 192.4,22.2 186.5,26 181.1,30.5 176.2,35.6 171.9,41.1 168.2,47.1 165.2,53.5 162.9,60.2 161.3,67.1 160.5,74.1 160.5,81.1 161.3,88.1 162.9,95 165.2,101.7 168.2,108 171.9,114 176.2,119.6 181.1,124.7 186.5,129.1 192.4,133 198.7,136.2 205.3,138.7 212.2,140.4 219.1,141.3 226.2,141.5 233.2,141 240.1,139.6 246.9,137.5 253.3,134.7 259.4,131.1 265.1,127 270.3,122.2 274.9,116.9 278.9,111.1 282.3,104.9 284.9,98.4 286.9,91.6 288,84.6
  silkscreen extent -315,-347 315,503
SC-70-3_L2.1-W1.3-P1.30-LS2.1-BR#1 [mil]
  rect 23.6x15.7 smd: 1(35.9,-25.6) 2(35.9,25.6) 3(-35.8,0)
  silkscreen extent -28,-42 28,42
SC-70-3_L2.1-W1.3-P1.30-LS2.1-BR#2 [mil]
  rect 23.6x15.7 smd: 1(35.8,-25.6) 2(35.8,25.6) 3(-35.8,0)
  silkscreen extent -28,-42 28,42
SC-70-3_L2.1-W1.3-P1.30-LS2.1-BR#3 [mil]
  rect 23.6x15.7 smd: 1(35.8,-25.6) 2(35.8,25.6) 3(-35.9,0)
  silkscreen extent -28,-42 28,42
SMA_L4.5-W2.6-LS5.0-RD [mil]
  rect 70.9x78.7 smd paste+0 mask+2: 1(-83.8,0) 2(83.9,0)
  silkscreen extent -92,-55 89,55
SO-8_L4.9-W3.9-P1.27-LS6.0-BL-EP#1 [mil]
  oval 23.6x63 smd: 1(-75,-118.2) 2(-25,-118.2) 3(25,-118.2) 4(75,-118.2) 5(75,118.1) 6(25,118.1) 7(-25,118.1) 8(-75,118.1)
  rect 126x98.4 smd: 9(0,0)
  silkscreen extent -98,-79 98,79
SO-8_L4.9-W3.9-P1.27-LS6.0-BL-EP#2 [mil]
  oval 23.6x63 smd: 1(-75,-118.1) 2(-25,-118.1) 3(25,-118.1) 4(75,-118.1) 5(75,118.1) 6(25,118.1) 7(-25,118.1) 8(-75,118.1)
  rect 126x98.4 smd: 9(0,0)
  silkscreen extent -98,-79 99,79
SOIC-8_L5.3-W5.3-P1.27-LS8.0-BL [mil]
  oval 24.8x88.6 smd: 1(-75,-139) 2(-25,-139) 3(25,-139) 4(75,-139) 5(75,138.9) 6(25,138.9) 7(-25,138.9) 8(-75,138.9)
  silkscreen extent -111,-145 104,86
SOIC-14_L8.7-W3.9-P1.27-LS6.0-BL-1#1 [mil]
  oval 22.6x80.2 smd: 1(-150,-109) 2(-100,-109) 3(-50,-109) 4(0,-109) 5(50,-109) 6(100,-109) 7(150,-109) 8(150,109) 9(100,109) 10(50,109) 11(0,109) 12(-50,109) 13(-100,109) 14(-150,109)
  silkscreen extent -185,-115 173,60
SOIC-14_L8.7-W3.9-P1.27-LS6.0-BL-1#2 [mil]
  oval 22.6x80.2 smd: 1(-150,-109) 2(-100,-109) 3(-50,-109) 4(0,-109) 5(50,-109) 6(100,-109) 7(150,-109) 8(150,109.1) 9(100,109.1) 10(50,109.1) 11(0,109.1) 12(-50,109.1) 13(-100,109.1) 14(-150,109.1)
  silkscreen extent -185,-115 173,60
SOIC-14_L8.7-W3.9-P1.27-LS6.0-BL-1#3 [mil]
  oval 22.6x80.2 smd: 1(-150,-109.1) 2(-100,-109.1) 3(-50,-109.1) 4(0,-109.1) 5(50,-109.1) 6(100,-109.1) 7(150,-109.1) 8(150,109) 9(100,109) 10(50,109) 11(0,109) 12(-50,109) 13(-100,109) 14(-150,109)
  silkscreen extent -185,-115 173,60
SOP-16_L9.9-W3.9-P1.27-LS6.0-BL#1 [mil]
  oval 22.6x80.2 smd: 1(-175,-109.1) 2(-125,-109.1) 3(-75,-109.1) 4(-25,-109.1) 5(25,-109.1) 6(75,-109.1) 7(125,-109.1) 8(175,-109.1) 9(175,109) 10(125,109) 11(75,109) 12(25,109) 13(-25,109) 14(-75,109) 15(-125,109) 16(-175,109)
  silkscreen extent -210,-115 198,60
SOP-16_L9.9-W3.9-P1.27-LS6.0-BL#2 [mil]
  oval 22.6x80.2 smd: 1(-175,-109) 2(-125,-109) 3(-75,-109) 4(-25,-109) 5(25,-109) 6(75,-109) 7(125,-109) 8(175,-109) 9(175,109) 10(125,109) 11(75,109) 12(25,109) 13(-25,109) 14(-75,109) 15(-125,109) 16(-175,109)
  silkscreen extent -210,-115 198,60
SOT-23-3_L2.9-W1.3-P1.90-LS2.4-BR#1 [mil]
  rect 49.2x27.6 smd: 1(39.3,-37.4) 2(39.3,37.4) 3(-39.4,0)
  silkscreen extent -29,-60 29,60
SOT-23-3_L2.9-W1.3-P1.90-LS2.4-BR#2 [mil]
  rect 49.2x27.6 smd: 1(39.4,-37.4) 2(39.4,37.4) 3(-39.4,0)
  silkscreen extent -29,-60 29,60
SOT-23-3_L2.9-W1.3-P1.90-LS2.4-BR-1#1 [mil]
  rect 49.2x27.6 smd: 1(39.4,-37.4) 2(39.4,37.4) 3(-39.3,0)
  silkscreen extent -29,-60 29,60
SOT-23-3_L2.9-W1.3-P1.90-LS2.4-BR-1#2 [mil]
  rect 49.2x27.6 smd: 1(39.3,-37.4) 2(39.3,37.4) 3(-39.4,0)
  silkscreen extent -29,-60 29,60
SOT-23-3_L2.9-W1.6-P1.90-LS2.8-BR#1 [mil]
  rect 42.1x23.6 smd paste+0 mask+2: 1(48.7,-37.4) 2(48.7,37.4) 3(-48.6,0)
  silkscreen extent -34,-60 34,60
SOT-23-3_L2.9-W1.6-P1.90-LS2.8-BR#2 [mil]
  rect 42.1x23.6 smd paste+0 mask+2: 1(48.6,-37.4) 2(48.6,37.4) 3(-48.6,0)
  silkscreen extent -34,-60 34,60
SOT-23-6_L2.9-W1.6-P0.95-LS2.8-BL [mil]
  rect 20.9x42.2 smd: 1(-37.4,-45.3) 2(0,-45.3) 3(37.4,-45.3) 4(37.4,45.2) 5(0,45.2) 6(-37.4,45.2)
  silkscreen extent -72,-57 61,35
SOT-23-6_L2.9-W1.6-P0.95-LS2.8-BR [mil]
  rect 43.3x23.6 smd paste+0 mask+2: 1(53.1,-37.4) 2(53.1,0) 3(53.1,37.4) 4(-53.2,37.4) 5(-53.2,0) 6(-53.2,-37.4)
  silkscreen extent -35,-70 60,61
SOT-323-3_L2.1-W1.3-P1.30-LS2.3-BR#1 [mil]
  rect 36.2x20.7 smd: 1(37.4,-25.6) 2(37.4,25.6) 3(-37.4,0)
  silkscreen extent -25,-50 39,42
SOT-323-3_L2.1-W1.3-P1.30-LS2.3-BR#2 [mil]
  rect 36.2x20.7 smd: 1(37.4,-25.6) 2(37.4,25.5) 3(-37.4,0)
  silkscreen extent -25,-50 39,42
SOT-583-8_L2.1-W1.2-P0.50-LS1.6-BL#1 [mil]
  rect 11x26.8 smd: 1(-29.6,-25.2) 2(-9.9,-25.2) 3(9.8,-25.2) 4(29.5,-25.2) 5(29.5,25.2) 6(9.8,25.2) 7(-9.9,25.2) 8(-29.6,25.2)
  silkscreen extent -50,-36 45,20
SOT-583-8_L2.1-W1.2-P0.50-LS1.6-BL#2 [mil]
  rect 11x26.8 smd: 1(-29.5,-25.2) 2(-9.8,-25.2) 3(9.9,-25.2) 4(29.6,-25.2) 5(29.6,25.2) 6(9.9,25.2) 7(-9.8,25.2) 8(-29.5,25.2)
  silkscreen extent -50,-36 45,20
Test-Point-0.5mm [mil]
  round 19.7 smd: 1(0,0)
TSOT-23-6_L2.9-W1.6-P0.95-LS2.6-BL [mil]
  rect 27.2x39.4 smd: 1(-37.4,-51.2) 2(0,-51.2) 3(37.4,-51.2) 4(37.4,51.2) 5(0,51.2) 6(-37.4,51.2)
  silkscreen extent -64,-54 59,34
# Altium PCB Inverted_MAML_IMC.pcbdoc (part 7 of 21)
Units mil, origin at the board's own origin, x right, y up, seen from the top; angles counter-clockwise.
Board outline 7677.1 x 6771.6 mil, 6 copper layers (Top Layer, Inner1, Inner2, Inner3, Inner4, Bottom Layer), stack 60.7 mil thick; 2732 components, 1531 nets, 7765 pads, 3701 vias.

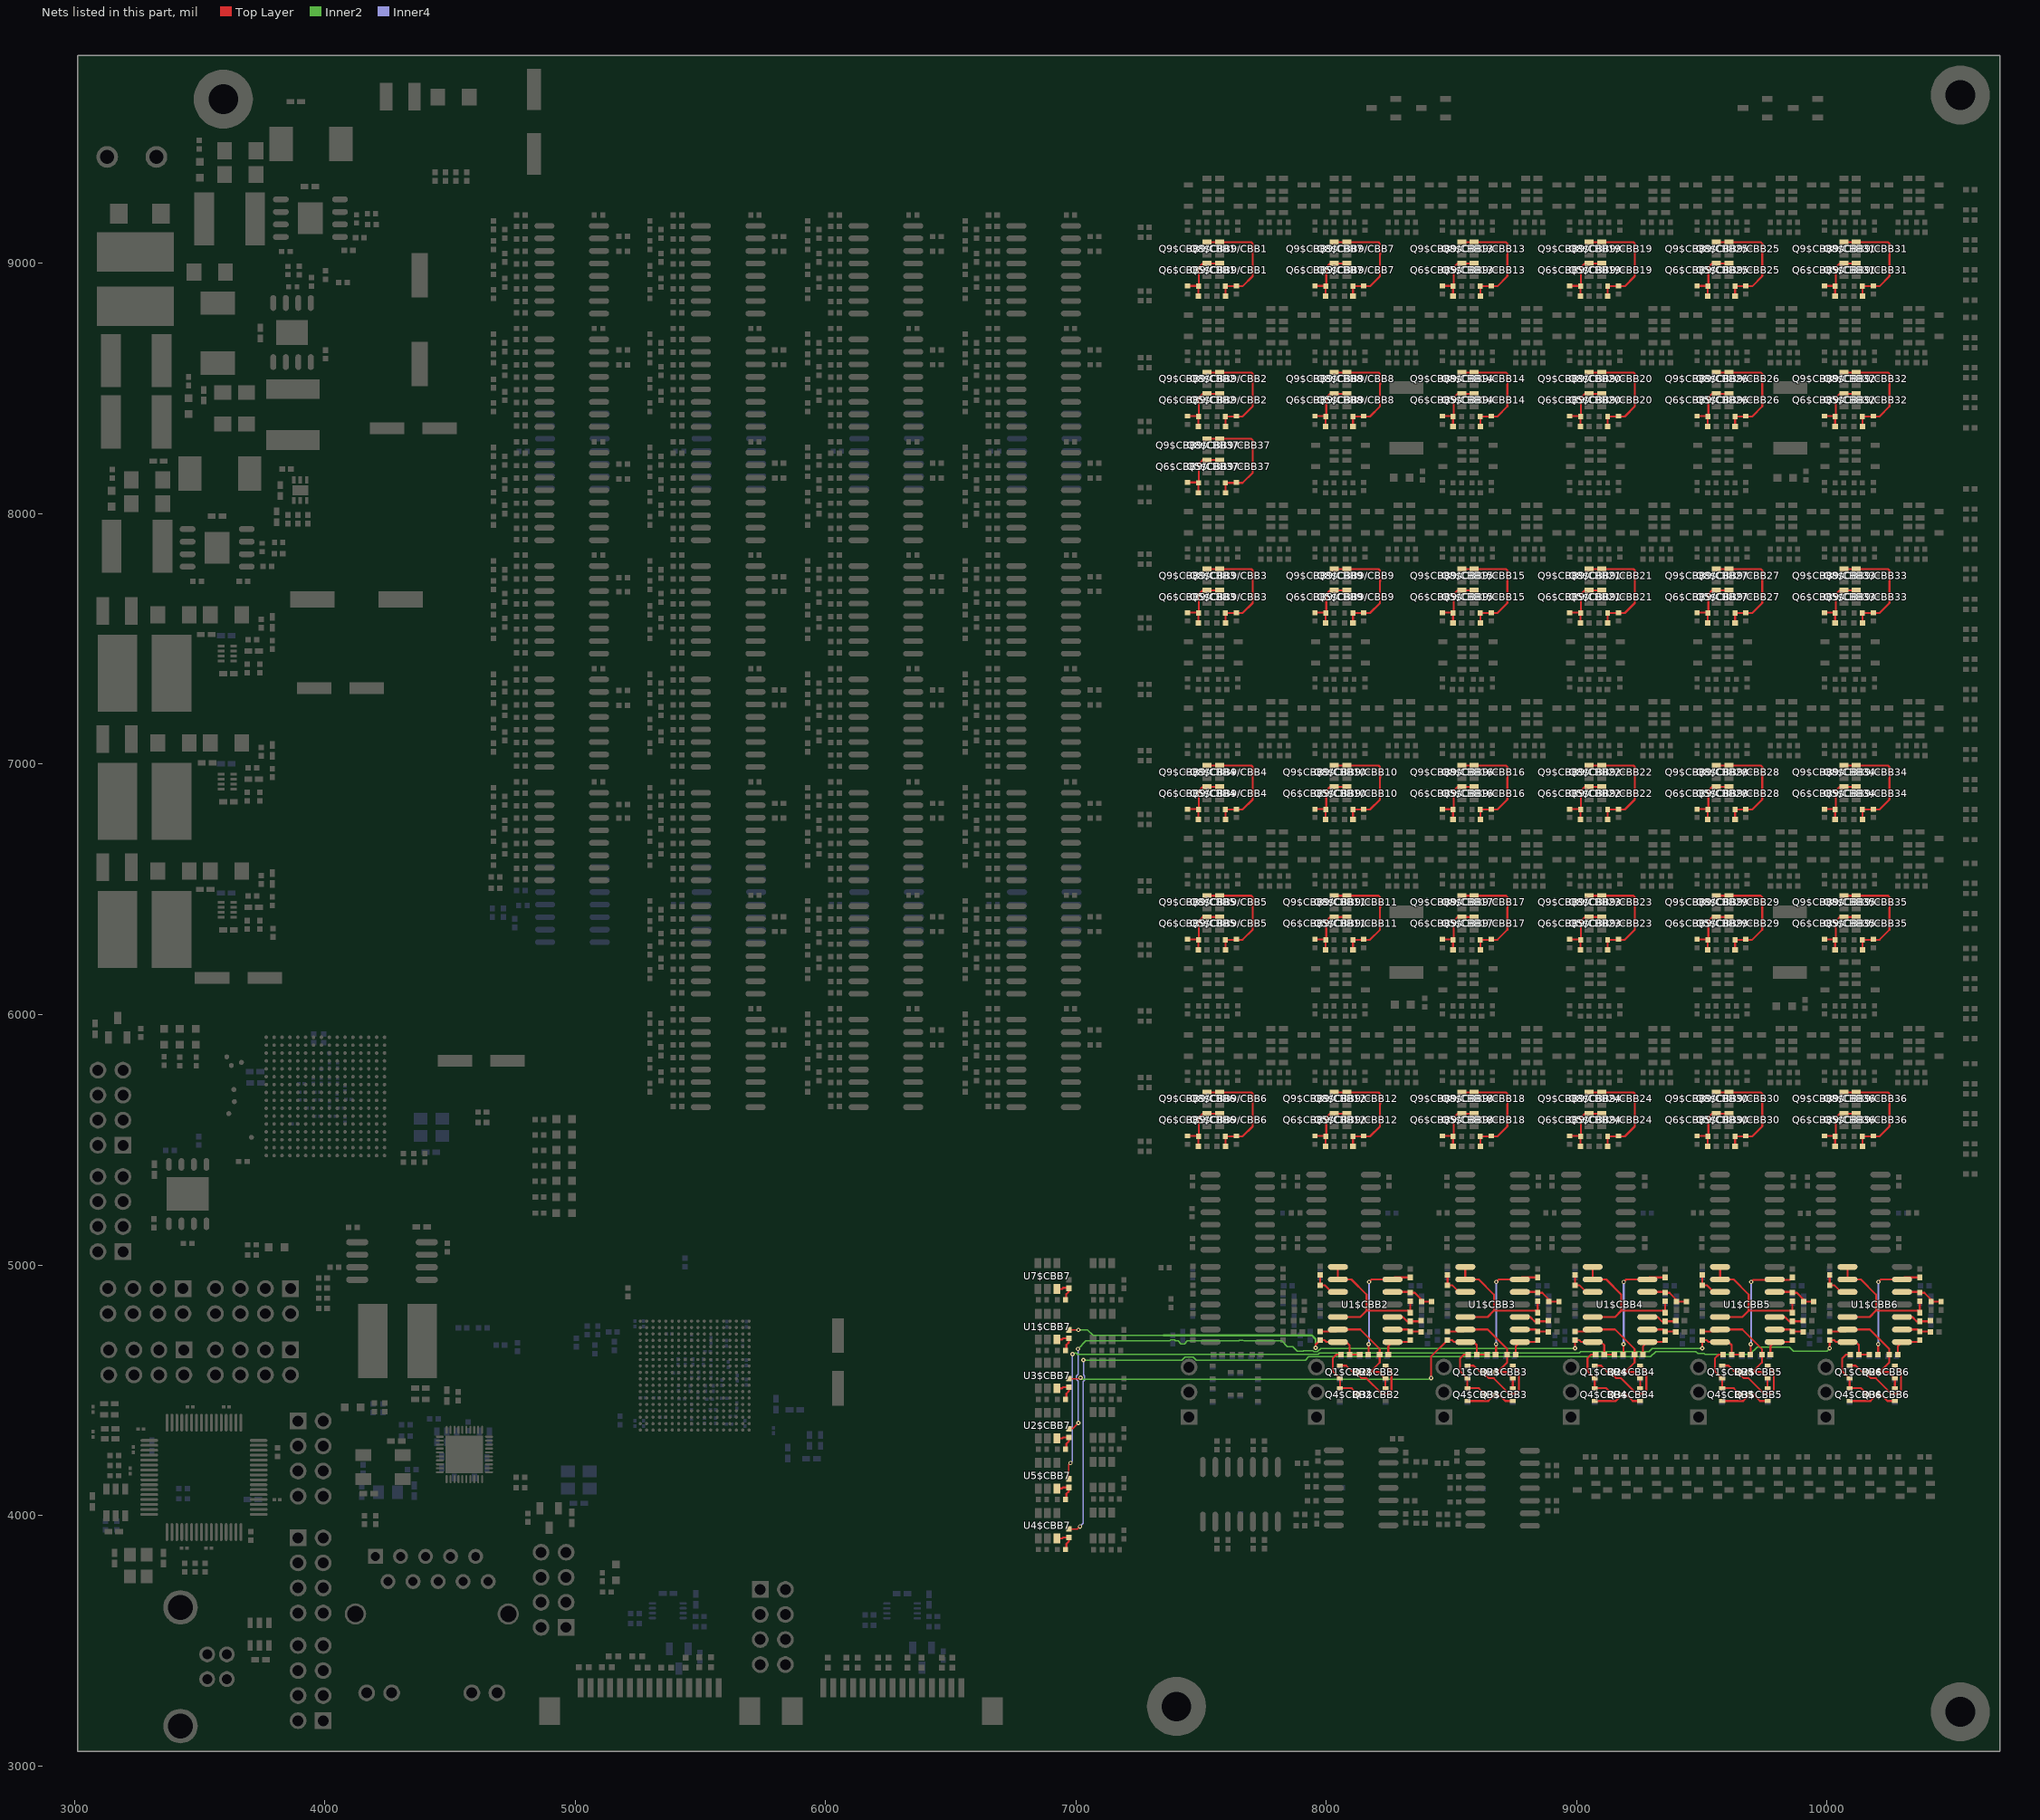
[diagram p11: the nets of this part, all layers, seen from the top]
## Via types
v1: diameter 17.7, hole 7.9, Top Layer to Bottom Layer, 3369 vias
v2: diameter 13.8, hole 7.9, Top Layer to Bottom Layer, 287 vias
v3: diameter 23.6, hole 11.8, Top Layer to Bottom Layer, 45 vias

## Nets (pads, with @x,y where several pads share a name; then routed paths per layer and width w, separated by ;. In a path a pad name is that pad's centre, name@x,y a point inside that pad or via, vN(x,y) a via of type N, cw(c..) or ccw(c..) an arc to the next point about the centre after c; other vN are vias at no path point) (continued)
$1I18\$1N2: Q1$CBB2.2 Q4$CBB2.1 Q4$CBB2.3 R10$CBB2.2 | length 253.1
  Top Layer w7.9: R10$CBB2.2@8058.8,4642.2 8040.8,4642.2 8025.8,4627.2 8025.8,4576 Q1$CBB2.2@8055.2,4546.6 Q4$CBB2.1@8055.2,4507.8 8101.3,4507.8 Q4$CBB2.3@8126.9,4482.2
$1I18\$1N3: Q2$CBB2.1 Q2$CBB2.3 Q3$CBB2.2 R2$CBB2.1 R9$CBB2.1 U1$CBB2.6 | length 502.4
  Top Layer w7.9: R2$CBB2.1@7975.8,4734.2 8038.8,4734.2 U1$CBB2.6@8046.8,4742.2 8135.8,4742.2 8213.8,4664.2 R9$CBB2.1@8213.8,4642.2 8213.8,4610.1 Q2$CBB2.3@8175.8,4572.2 ; Q2$CBB2.3@8164.8,4572.2 Q2$CBB2.3@8175.8,4572.2 ; Q3$CBB2.2@8236.4,4507.8 Q2$CBB2.1@8236.4,4546.6 8210.8,4572.2 Q2$CBB2.3@8175.8,4572.2
$1I18\$1N4: Q1$CBB2.1 Q1$CBB2.3 Q2$CBB2.2 | length 372.3
  Top Layer w7.9: Q1$CBB2.1@8055.2,4597.8 8080.2,4597.8 8105.8,4572.2 Q1$CBB2.3@8126.9,4572.2 8126.9,4561.4 8140.8,4547.5 8160.5,4547.5 8222.3,4485.7 8246.7,4485.7 8260.8,4499.8 8260.8,4573.3 Q2$CBB2.2@8236.4,4597.8
$1I18\$1N9: R1$CBB2.1 R8$CBB2.2 U1$CBB2.1 U1$CBB2.2 U1$CBB2.5 | length 602.5
  Top Layer w7.9: U1$CBB2.5@8046.8,4792.2 8135.8,4792.2 8160.8,4817.2 ; U1$CBB2.1@8046.8,4992.2 U1$CBB2.2@8046.8,4942.2 8100.8,4942.2 8160.8,4882.2 8160.8,4817.2 ; R1$CBB2.1@8335.8,4855.1 R8$CBB2.2@8335.8,4809.2 8327.9,4817.2 8160.8,4817.2
$1I18\$1N13: R4$CBB2.1 R5$CBB2.2 U1$CBB2.3 | length 123.1
  Top Layer w7.9: R5$CBB2.2@7975.8,4960.1 R4$CBB2.1@7975.8,4919.2 7993.8,4919.2 8020.8,4892.2 U1$CBB2.3@8046.8,4892.2
$1I18\$1N14: R3$CBB2.2 R9$CBB2.2 U1$CBB2.8 | length 131.2
  Top Layer w7.9: R9$CBB2.2@8247.9,4642.2 8247.9,4675.2 U1$CBB2.8@8264.8,4692.2 8327.9,4692.2 R3$CBB2.2@8335.8,4700.1
$1I18\$1N15: R3$CBB2.1 R6$CBB2.1 U1$CBB2.9 | length 118.1
  Top Layer w7.9: U1$CBB2.9@8264.8,4742.2 8327.9,4742.2 R3$CBB2.1@8335.8,4734.2 8376.7,4734.2 R6$CBB2.1@8378.8,4732.2
$1I18\$1N16: R7$CBB2.1 R8$CBB2.1 U1$CBB2.10 | length 122
  Top Layer w7.9: U1$CBB2.10@8264.8,4792.2 8305.8,4792.2 8322.9,4775.1 R8$CBB2.1@8335.8,4775.1 8376.7,4775.1 R7$CBB2.1@8378.8,4777.2
$1I18\$1N20: R1$CBB2.2 R11$CBB2.2 R12$CBB2.2 U1$CBB2.12 | length 176.5
  Top Layer w7.9: U1$CBB2.12@8264.8,4892.2 8332.9,4892.2 R1$CBB2.2@8335.8,4889.2 8353.8,4889.2 8380.8,4862.2 R12$CBB2.2@8380.8,4854.2 R11$CBB2.2@8420.8,4854.2
$1I18\$1N22: R13$CBB2.2 R14$CBB2.1 U1$CBB2.13 | length 463.6
  Top Layer w7.9: R13$CBB2.2@8167.9,4642.2 8169.3,4643.6 v1(8169.3,4683.6) ; v1(8170.8,4932.2) 8180.8,4942.2 U1$CBB2.13@8264.8,4942.2 8272.8,4950.1 R14$CBB2.1@8335.8,4950.1
  Inner4 w7.9: v1(8169.3,4683.6) 8170.8,4685.1 v1(8170.8,4932.2)
$1I18\SIG_OUT_FULL: R1$CBB7.2 R2$CBB2.2 R10$CBB2.1 R13$CBB2.1 U1$CBB2.7 | length 1278.1
  Top Layer w5.9: R1$CBB7.2@6972.1,4740.8 v1(7010.6,4740.8)
  Top Layer w7.9: v1(7957.8,4669.2) 7957.8,4682.1 R2$CBB2.2@7975.8,4700.1 ; R2$CBB2.2@7975.9,4700 7993,4700 8000.8,4692.2 8080.8,4692.2 8092.9,4680.1 R10$CBB2.1@8092.9,4642.2 R13$CBB2.1@8133.8,4642.2
  Inner2 w5.9: v1(7010.6,4740.8) 7046.7,4740.8 7068.8,4718.7 7349.7,4718.7
  Inner2 w7.9: 7349.7,4718.7 7837.4,4718.7 7943,4718.7 7957.8,4703.9 v1(7957.8,4669.2)
$1I19\$1N1: Q3$CBB3.1 Q3$CBB3.3 Q4$CBB3.2 | length 202.4
  Top Layer w7.9: Q4$CBB3.2@8563.9,4456.6 8647.9,4456.6 Q3$CBB3.3@8673.5,4482.2 8689.5,4482.2 8715.1,4456.6 Q3$CBB3.1@8745.1,4456.6
$1I19\$1N2: Q1$CBB3.2 Q4$CBB3.1 Q4$CBB3.3 R10$CBB3.2 | length 253.1
  Top Layer w7.9: R10$CBB3.2@8567.5,4642.2 8549.5,4642.2 8534.5,4627.2 8534.5,4576 Q1$CBB3.2@8563.9,4546.6 Q4$CBB3.1@8563.9,4507.8 8610,4507.8 Q4$CBB3.3@8635.6,4482.2
$1I19\$1N3: Q2$CBB3.1 Q2$CBB3.3 Q3$CBB3.2 R2$CBB3.1 R9$CBB3.1 U1$CBB3.6 | length 502.4
  Top Layer w7.9: R2$CBB3.1@8484.5,4734.2 8547.5,4734.2 U1$CBB3.6@8555.5,4742.2 8644.5,4742.2 8722.5,4664.2 R9$CBB3.1@8722.5,4642.2 8722.5,4610.1 Q2$CBB3.3@8684.5,4572.2 ; Q2$CBB3.3@8673.5,4572.2 Q2$CBB3.3@8684.5,4572.2 ; Q3$CBB3.2@8745.1,4507.8 Q2$CBB3.1@8745.1,4546.6 8719.5,4572.2 Q2$CBB3.3@8684.5,4572.2
$1I19\$1N4: Q1$CBB3.1 Q1$CBB3.3 Q2$CBB3.2 | length 372.3
  Top Layer w7.9: Q1$CBB3.1@8563.9,4597.8 8588.9,4597.8 8614.5,4572.2 Q1$CBB3.3@8635.6,4572.2 8635.6,4561.4 8649.5,4547.5 8669.2,4547.5 8731,4485.7 8755.4,4485.7 8769.5,4499.8 8769.5,4573.3 Q2$CBB3.2@8745.1,4597.8
$1I19\$1N9: R1$CBB3.1 R8$CBB3.2 U1$CBB3.1 U1$CBB3.2 U1$CBB3.5 | length 602.5
  Top Layer w7.9: U1$CBB3.5@8555.5,4792.2 8644.5,4792.2 8669.5,4817.2 ; U1$CBB3.1@8555.5,4992.2 U1$CBB3.2@8555.5,4942.2 8609.5,4942.2 8669.5,4882.2 8669.5,4817.2 ; R1$CBB3.1@8844.5,4855.1 R8$CBB3.2@8844.5,4809.2 8836.6,4817.2 8669.5,4817.2
$1I19\$1N13: R4$CBB3.1 R5$CBB3.2 U1$CBB3.3 | length 123.1
  Top Layer w7.9: R5$CBB3.2@8484.5,4960.1 R4$CBB3.1@8484.5,4919.2 8502.5,4919.2 8529.5,4892.2 U1$CBB3.3@8555.5,4892.2
$1I19\$1N14: R3$CBB3.2 R9$CBB3.2 U1$CBB3.8 | length 131.2
  Top Layer w7.9: R9$CBB3.2@8756.6,4642.2 8756.6,4675.2 U1$CBB3.8@8773.5,4692.2 8836.6,4692.2 R3$CBB3.2@8844.5,4700.1
$1I19\$1N15: R3$CBB3.1 R6$CBB3.1 U1$CBB3.9 | length 118.1
  Top Layer w7.9: U1$CBB3.9@8773.5,4742.2 8836.6,4742.2 R3$CBB3.1@8844.5,4734.2 8885.4,4734.2 R6$CBB3.1@8887.5,4732.2
$1I19\$1N16: R7$CBB3.1 R8$CBB3.1 U1$CBB3.10 | length 122
  Top Layer w7.9: U1$CBB3.10@8773.5,4792.2 8814.5,4792.2 8831.6,4775.1 R8$CBB3.1@8844.5,4775.1 8885.4,4775.1 R7$CBB3.1@8887.5,4777.2
$1I19\$1N20: R1$CBB3.2 R11$CBB3.2 R12$CBB3.2 U1$CBB3.12 | length 176.5
  Top Layer w7.9: U1$CBB3.12@8773.5,4892.2 8841.6,4892.2 R1$CBB3.2@8844.5,4889.2 8862.5,4889.2 8889.5,4862.2 R12$CBB3.2@8889.5,4854.2 R11$CBB3.2@8929.5,4854.2
$1I19\$1N22: R13$CBB3.2 R14$CBB3.1 U1$CBB3.13 | length 463.6
  Top Layer w7.9: R13$CBB3.2@8676.6,4642.2 8678,4643.6 v1(8678,4683.6) ; v1(8679.5,4932.2) 8689.5,4942.2 U1$CBB3.13@8773.5,4942.2 8781.5,4950.1 R14$CBB3.1@8844.5,4950.1
  Inner4 w7.9: v1(8678,4683.6) 8679.5,4685.1 v1(8679.5,4932.2)
$1I19\SIG_OUT_FULL: R2$CBB3.2 R3$CBB7.2 R10$CBB3.1 R13$CBB3.1 U1$CBB3.7 | length 1835.3
  Top Layer w4.7: R3$CBB7.2@6972.1,4545.8 7014.3,4545.8 v1(7018.6,4550)
  Top Layer w7.9: v1(8418.3,4548.7) 8418.3,4633.9 R2$CBB3.2@8484.5,4700.1 8484.6,4700 8501.7,4700 8509.5,4692.2 8589.5,4692.2 8601.6,4680.1 R10$CBB3.1@8601.6,4642.2 R13$CBB3.1@8642.5,4642.2
  Inner2 w4.7: v1(7018.6,4550) 7024.6,4544 8413.6,4544 v1(8418.3,4548.7)
$1I20\$1N1: Q3$CBB4.1 Q3$CBB4.3 Q4$CBB4.2 | length 202.4
  Top Layer w7.9: Q4$CBB4.2@9072.6,4456.6 9156.6,4456.6 Q3$CBB4.3@9182.2,4482.2 9198.2,4482.2 9223.8,4456.6 Q3$CBB4.1@9253.8,4456.6
$1I20\$1N2: Q1$CBB4.2 Q4$CBB4.1 Q4$CBB4.3 R10$CBB4.2 | length 253.1
  Top Layer w7.9: R10$CBB4.2@9076.2,4642.2 9058.2,4642.2 9043.2,4627.2 9043.2,4576 Q1$CBB4.2@9072.6,4546.6 Q4$CBB4.1@9072.6,4507.8 9118.7,4507.8 Q4$CBB4.3@9144.3,4482.2
$1I20\$1N3: Q2$CBB4.1 Q2$CBB4.3 Q3$CBB4.2 R2$CBB4.1 R9$CBB4.1 U1$CBB4.6 | length 502.4
  Top Layer w7.9: R2$CBB4.1@8993.2,4734.2 9056.3,4734.2 U1$CBB4.6@9064.2,4742.2 9153.2,4742.2 9231.2,4664.2 R9$CBB4.1@9231.2,4642.2 9231.2,4610.1 Q2$CBB4.3@9193.2,4572.2 ; Q2$CBB4.3@9182.2,4572.2 Q2$CBB4.3@9193.2,4572.2 ; Q3$CBB4.2@9253.8,4507.8 Q2$CBB4.1@9253.8,4546.6 9228.2,4572.2 Q2$CBB4.3@9193.2,4572.2
$1I20\$1N4: Q1$CBB4.1 Q1$CBB4.3 Q2$CBB4.2 | length 372.3
  Top Layer w7.9: Q1$CBB4.1@9072.6,4597.8 9097.6,4597.8 9123.2,4572.2 Q1$CBB4.3@9144.3,4572.2 9144.3,4561.4 9158.2,4547.5 9177.9,4547.5 9239.7,4485.7 9264.1,4485.7 9278.2,4499.8 9278.2,4573.3 Q2$CBB4.2@9253.8,4597.8
$1I20\$1N9: R1$CBB4.1 R8$CBB4.2 U1$CBB4.1 U1$CBB4.2 U1$CBB4.5 | length 602.5
  Top Layer w7.9: U1$CBB4.5@9064.2,4792.2 9153.2,4792.2 9178.2,4817.2 ; U1$CBB4.1@9064.2,4992.2 U1$CBB4.2@9064.2,4942.2 9118.2,4942.2 9178.2,4882.2 9178.2,4817.2 ; R1$CBB4.1@9353.2,4855.1 R8$CBB4.2@9353.2,4809.2 9345.3,4817.2 9178.2,4817.2
$1I20\$1N13: R4$CBB4.1 R5$CBB4.2 U1$CBB4.3 | length 123.1
  Top Layer w7.9: R5$CBB4.2@8993.2,4960.1 R4$CBB4.1@8993.2,4919.2 9011.2,4919.2 9038.2,4892.2 U1$CBB4.3@9064.2,4892.2
$1I20\$1N14: R3$CBB4.2 R9$CBB4.2 U1$CBB4.8 | length 131.2
  Top Layer w7.9: R9$CBB4.2@9265.3,4642.2 9265.3,4675.2 U1$CBB4.8@9282.3,4692.2 9345.3,4692.2 R3$CBB4.2@9353.2,4700.1
$1I20\$1N15: R3$CBB4.1 R6$CBB4.1 U1$CBB4.9 | length 118.1
  Top Layer w7.9: U1$CBB4.9@9282.3,4742.2 9345.3,4742.2 R3$CBB4.1@9353.2,4734.2 9394.2,4734.2 R6$CBB4.1@9396.2,4732.2
$1I20\$1N16: R7$CBB4.1 R8$CBB4.1 U1$CBB4.10 | length 121.9
  Top Layer w7.9: U1$CBB4.10@9282.3,4792.2 9323.2,4792.2 9340.3,4775.1 R8$CBB4.1@9353.2,4775.1 9394.2,4775.1 R7$CBB4.1@9396.2,4777.2
$1I20\$1N20: R1$CBB4.2 R11$CBB4.2 R12$CBB4.2 U1$CBB4.12 | length 176.4
  Top Layer w7.9: U1$CBB4.12@9282.3,4892.2 9350.3,4892.2 R1$CBB4.2@9353.2,4889.2 9371.2,4889.2 9398.2,4862.2 R12$CBB4.2@9398.2,4854.2 R11$CBB4.2@9438.2,4854.2
$1I20\$1N22: R13$CBB4.2 R14$CBB4.1 U1$CBB4.13 | length 463.6
  Top Layer w7.9: R13$CBB4.2@9185.3,4642.2 9186.7,4643.6 v1(9186.7,4683.6) ; v1(9188.2,4932.2) 9198.2,4942.2 U1$CBB4.13@9282.3,4942.2 9290.2,4950.1 R14$CBB4.1@9353.2,4950.1
  Inner4 w7.9: v1(9186.7,4683.6) 9188.2,4685.1 v1(9188.2,4932.2)
$1I20\SIG_OUT_FULL: R2$CBB4.2 R2$CBB7.2 R10$CBB4.1 R13$CBB4.1 U1$CBB4.7 | length 2626.5
  Top Layer w4.7: R2$CBB7.2@6972.1,4345.8 6987,4345.8 v1(7010.6,4369.3)
  Top Layer w7.9: v1(8993.2,4667.2) R2$CBB4.2@8993.2,4700.1 8993.3,4700 9010.4,4700 9018.2,4692.2 9098.2,4692.2 9110.3,4680.1 R10$CBB4.1@9110.3,4642.2 R13$CBB4.1@9151.2,4642.2
  Inner2 w4.7: v1(7008.5,4664.5) 7040.7,4696.6 7375.4,4696.6 7380.4,4701.6 7393.8,4701.6 7398.9,4696.6 7408.3,4696.6 7420.2,4684.7 7433.6,4684.7 7445.6,4696.6 7650.7,4696.6 7653.8,4699.8 7667.3,4699.8 7670.4,4696.6 7823,4696.6 7845.2,4674.4 7865.7,4674.4 7883.8,4656.3 7907.9,4656.3 7909.7,4658.1 7945.8,4658.1 7951,4653 7964.5,4653 7978,4666.5 8992.6,4666.5 v1(8993.2,4667.2)
  Inner4 w4.7: v1(7008.5,4664.5) 7008.5,4562.9 7002.4,4556.8 7002.4,4543.3 7008.5,4537.1 7008.5,4371.3 v1(7010.6,4369.3)
$1I21\$1N1: Q3$CBB5.1 Q3$CBB5.3 Q4$CBB5.2 | length 202.4
  Top Layer w7.9: Q4$CBB5.2@9581.3,4456.6 9665.3,4456.6 Q3$CBB5.3@9690.9,4482.2 9706.9,4482.2 9732.5,4456.6 Q3$CBB5.1@9762.5,4456.6
$1I21\$1N2: Q1$CBB5.2 Q4$CBB5.1 Q4$CBB5.3 R10$CBB5.2 | length 253.1
  Top Layer w7.9: R10$CBB5.2@9584.9,4642.2 9566.9,4642.2 9551.9,4627.2 9551.9,4576 Q1$CBB5.2@9581.3,4546.6 Q4$CBB5.1@9581.3,4507.8 9627.4,4507.8 Q4$CBB5.3@9653,4482.2
$1I21\$1N3: Q2$CBB5.1 Q2$CBB5.3 Q3$CBB5.2 R2$CBB5.1 R9$CBB5.1 U1$CBB5.6 | length 502.4
  Top Layer w7.9: R2$CBB5.1@9501.9,4734.2 9565,4734.2 U1$CBB5.6@9572.9,4742.2 9661.9,4742.2 9739.9,4664.2 R9$CBB5.1@9739.9,4642.2 9739.9,4610.1 Q2$CBB5.3@9701.9,4572.2 ; Q2$CBB5.3@9690.9,4572.2 Q2$CBB5.3@9701.9,4572.2 ; Q3$CBB5.2@9762.5,4507.8 Q2$CBB5.1@9762.5,4546.6 9736.9,4572.2 Q2$CBB5.3@9701.9,4572.2
$1I21\$1N4: Q1$CBB5.1 Q1$CBB5.3 Q2$CBB5.2 | length 372.3
  Top Layer w7.9: Q1$CBB5.1@9581.3,4597.8 9606.3,4597.8 9631.9,4572.2 Q1$CBB5.3@9653,4572.2 9653,4561.4 9666.9,4547.5 9686.6,4547.5 9748.4,4485.7 9772.8,4485.7 9786.9,4499.8 9786.9,4573.3 Q2$CBB5.2@9762.5,4597.8
$1I21\$1N9: R1$CBB5.1 R8$CBB5.2 U1$CBB5.1 U1$CBB5.2 U1$CBB5.5 | length 602.5
  Top Layer w7.9: U1$CBB5.5@9572.9,4792.2 9661.9,4792.2 9686.9,4817.2 ; U1$CBB5.1@9572.9,4992.2 U1$CBB5.2@9572.9,4942.2 9626.9,4942.2 9686.9,4882.2 9686.9,4817.2 ; R1$CBB5.1@9861.9,4855.1 R8$CBB5.2@9861.9,4809.2 9854,4817.2 9686.9,4817.2
$1I21\$1N13: R4$CBB5.1 R5$CBB5.2 U1$CBB5.3 | length 123.1
  Top Layer w7.9: R5$CBB5.2@9501.9,4960.1 R4$CBB5.1@9501.9,4919.2 9519.9,4919.2 9546.9,4892.2 U1$CBB5.3@9572.9,4892.2
$1I21\$1N14: R3$CBB5.2 R9$CBB5.2 U1$CBB5.8 | length 131.2
  Top Layer w7.9: R9$CBB5.2@9774,4642.2 9774,4675.2 U1$CBB5.8@9791,4692.2 9854,4692.2 R3$CBB5.2@9861.9,4700.1
$1I21\$1N15: R3$CBB5.1 R6$CBB5.1 U1$CBB5.9 | length 118.1
  Top Layer w7.9: U1$CBB5.9@9791,4742.2 9854,4742.2 R3$CBB5.1@9861.9,4734.2 9902.9,4734.2 R6$CBB5.1@9904.9,4732.2
$1I21\$1N16: R7$CBB5.1 R8$CBB5.1 U1$CBB5.10 | length 121.9
  Top Layer w7.9: U1$CBB5.10@9791,4792.2 9831.9,4792.2 9849,4775.1 R8$CBB5.1@9861.9,4775.1 9902.9,4775.1 R7$CBB5.1@9904.9,4777.2
$1I21\$1N20: R1$CBB5.2 R11$CBB5.2 R12$CBB5.2 U1$CBB5.12 | length 176.4
  Top Layer w7.9: U1$CBB5.12@9791,4892.2 9859,4892.2 R1$CBB5.2@9861.9,4889.2 9879.9,4889.2 9906.9,4862.2 R12$CBB5.2@9906.9,4854.2 R11$CBB5.2@9946.9,4854.2
$1I21\$1N22: R13$CBB5.2 R14$CBB5.1 U1$CBB5.13 | length 463.6
  Top Layer w7.9: R13$CBB5.2@9694,4642.2 9695.4,4643.6 v1(9695.4,4683.6) ; v1(9696.9,4932.2) 9704.8,4940 9851.8,4940 R14$CBB5.1@9861.9,4950.1
  Inner4 w7.9: v1(9695.4,4683.6) 9696.9,4685.1 v1(9696.9,4932.2)
$1I21\SIG_OUT_FULL: R2$CBB5.2 R5$CBB7.2 R10$CBB5.1 R13$CBB5.1 U1$CBB5.7 | length 3271.8
  Top Layer w4.7: R5$CBB7.2@6972.1,4145.8 6972.1,4202.6 v1(6978.4,4208.9)
  Top Layer w7.9: v1(9501.9,4667.2) R2$CBB5.2@9501.9,4700.1 9502,4700 9519.1,4700 9526.9,4692.2 9606.9,4692.2 9619,4680.1 R10$CBB5.1@9619,4642.2 R13$CBB5.1@9659.9,4642.2
  Inner2 w4.7: v1(6986.5,4644.4) 6990.5,4648.4 7001.7,4648.4 7006.4,4643.7 7062.7,4643.7 7063.9,4642.5 7110.4,4642.5 7111.6,4643.7 7946.5,4643.7 7947,4643.2 7968.5,4643.2 7973.7,4648.4 9010.4,4648.4 9016.4,4654.4 9289.5,4654.4 9302.2,4667.2 v1(9501.9,4667.2)
  Inner4 w4.7: v1(6978.4,4208.9) 6986.5,4217 v1(6986.5,4644.4)
$1I22\$1N1: Q3$CBB6.1 Q3$CBB6.3 Q4$CBB6.2 | length 202.4
  Top Layer w7.9: Q4$CBB6.2@10090,4456.6 10174,4456.6 Q3$CBB6.3@10199.6,4482.2 10215.6,4482.2 10241.2,4456.6 Q3$CBB6.1@10271.2,4456.6
$1I22\$1N2: Q1$CBB6.2 Q4$CBB6.1 Q4$CBB6.3 R10$CBB6.2 | length 253.1
  Top Layer w7.9: R10$CBB6.2@10093.6,4642.2 10075.6,4642.2 10060.6,4627.2 10060.6,4576 Q1$CBB6.2@10090,4546.6 Q4$CBB6.1@10090,4507.8 10136.1,4507.8 Q4$CBB6.3@10161.7,4482.2
$1I22\$1N3: Q2$CBB6.1 Q2$CBB6.3 Q3$CBB6.2 R2$CBB6.1 R9$CBB6.1 U1$CBB6.6 | length 502.4
  Top Layer w7.9: R2$CBB6.1@10010.6,4734.2 10073.7,4734.2 U1$CBB6.6@10081.6,4742.2 10170.6,4742.2 10248.6,4664.2 R9$CBB6.1@10248.6,4642.2 10248.6,4610.1 Q2$CBB6.3@10210.6,4572.2 ; Q2$CBB6.3@10199.6,4572.2 Q2$CBB6.3@10210.6,4572.2 ; Q3$CBB6.2@10271.2,4507.8 Q2$CBB6.1@10271.2,4546.6 10245.6,4572.2 Q2$CBB6.3@10210.6,4572.2
$1I22\$1N4: Q1$CBB6.1 Q1$CBB6.3 Q2$CBB6.2 | length 372.3
  Top Layer w7.9: Q1$CBB6.1@10090,4597.8 10115,4597.8 10140.6,4572.2 Q1$CBB6.3@10161.7,4572.2 10161.7,4561.4 10175.6,4547.5 10195.3,4547.5 10257.1,4485.7 10281.5,4485.7 10295.6,4499.8 10295.6,4573.3 Q2$CBB6.2@10271.2,4597.8
$1I22\$1N9: R1$CBB6.1 R8$CBB6.2 U1$CBB6.1 U1$CBB6.2 U1$CBB6.5 | length 602.5
  Top Layer w7.9: U1$CBB6.5@10081.6,4792.2 10170.6,4792.2 10195.6,4817.2 ; U1$CBB6.1@10081.6,4992.2 U1$CBB6.2@10081.6,4942.2 10135.6,4942.2 10195.6,4882.2 10195.6,4817.2 ; R1$CBB6.1@10370.6,4855.1 R8$CBB6.2@10370.6,4809.2 10362.7,4817.2 10195.6,4817.2
$1I22\$1N13: R4$CBB6.1 R5$CBB6.2 U1$CBB6.3 | length 123.1
  Top Layer w7.9: R5$CBB6.2@10010.6,4960.1 R4$CBB6.1@10010.6,4919.2 10028.6,4919.2 10055.6,4892.2 U1$CBB6.3@10081.6,4892.2
$1I22\$1N14: R3$CBB6.2 R9$CBB6.2 U1$CBB6.8 | length 131.2
  Top Layer w7.9: R9$CBB6.2@10282.7,4642.2 10282.7,4675.2 U1$CBB6.8@10299.7,4692.2 10362.7,4692.2 R3$CBB6.2@10370.6,4700.1
$1I22\$1N15: R3$CBB6.1 R6$CBB6.1 U1$CBB6.9 | length 118.1
  Top Layer w7.9: U1$CBB6.9@10299.7,4742.2 10362.7,4742.2 R3$CBB6.1@10370.6,4734.2 10411.6,4734.2 R6$CBB6.1@10413.6,4732.2
$1I22\$1N16: R7$CBB6.1 R8$CBB6.1 U1$CBB6.10 | length 121.9
  Top Layer w7.9: U1$CBB6.10@10299.7,4792.2 10340.6,4792.2 10357.7,4775.1 R8$CBB6.1@10370.6,4775.1 10411.6,4775.1 R7$CBB6.1@10413.6,4777.2
$1I22\$1N20: R1$CBB6.2 R11$CBB6.2 R12$CBB6.2 U1$CBB6.12 | length 176.4
  Top Layer w7.9: U1$CBB6.12@10299.7,4892.2 10367.7,4892.2 R1$CBB6.2@10370.6,4889.2 10388.6,4889.2 10415.6,4862.2 R12$CBB6.2@10415.6,4854.2 R11$CBB6.2@10455.6,4854.2
$1I22\$1N22: R13$CBB6.2 R14$CBB6.1 U1$CBB6.13 | length 463.6
  Top Layer w7.9: R13$CBB6.2@10202.7,4642.2 10204.1,4643.6 v1(10204.1,4683.6) ; v1(10205.6,4932.2) 10215.6,4942.2 U1$CBB6.13@10299.7,4942.2 10307.6,4950.1 R14$CBB6.1@10370.6,4950.1
  Inner4 w7.9: v1(10204.1,4683.6) 10205.6,4685.1 v1(10205.6,4932.2)
$1I22\SIG_OUT_FULL: R2$CBB6.2 R4$CBB7.2 R10$CBB6.1 R13$CBB6.1 U1$CBB6.7 | length 3992.6
  Top Layer w4.7: R4$CBB7.2@6972.1,3945.8 7006.6,3945.8 v1(7016.6,3955.7)
  Top Layer w7.9: v1(10010.6,4667.2) R2$CBB6.2@10010.6,4700.1 10010.7,4700 10027.8,4700 10035.6,4692.2 10115.6,4692.2 10127.7,4680.1 R10$CBB6.1@10127.7,4642.2 R13$CBB6.1@10168.6,4642.2
  Inner2 w4.7: v1(7030.6,4620.3) 7422.5,4620.3 7435.2,4633 7469,4633 7481.7,4620.3 7916.1,4620.3 7929.3,4633.5 9294.6,4633.5 9315.6,4654.4 9476.2,4654.4 9484.8,4645.9 9509.2,4645.9 9512.6,4642.4 9691.1,4642.4 9721.2,4672.5 9849.7,4672.5 9865.7,4656.5 9999.9,4656.5 v1(10010.6,4667.2)
  Inner4 w4.7: v1(7016.6,3955.7) 7028.6,3967.8 7028.6,4534 7034.8,4540.2 7034.8,4556.8 7030.6,4560.9 v1(7030.6,4620.3)
$1I23\$1N22: C5$CBB7.2 R6$CBB7.1 U7$CBB7.3 | length 102.8
  Top Layer w7.9: U7$CBB7.3@6924,4904.5 6945,4904.5 6949.1,4908.6 6971.6,4908.6 6971.6,4892.9 6961.8,4883.2 6961.8,4864.4 C5$CBB7.2@6958.1,4860.7
$1I23\$1N27: C6$CBB7.2 R1$CBB7.1 U1$CBB7.3 | length 102.9
  Top Layer w7.9: U1$CBB7.3@6924.5,4702.5 6945.5,4702.5 6949.7,4706.7 R1$CBB7.1@6972.1,4706.7 6972.1,4691 6962.4,4681.2 6962.4,4662.4 C6$CBB7.2@6958.7,4658.7
$1I23\$1N36: C8$CBB7.2 R3$CBB7.1 U3$CBB7.3 | length 102.9
  Top Layer w7.9: U3$CBB7.3@6924.5,4507.5 6945.5,4507.5 6949.7,4511.7 R3$CBB7.1@6972.1,4511.7 6972.1,4496 6962.4,4486.2 6962.4,4467.4 C8$CBB7.2@6958.7,4463.7
$1I23\$1N38: C9$CBB7.2 R2$CBB7.1 U2$CBB7.3 | length 102.9
  Top Layer w7.9: U2$CBB7.3@6924.5,4307.5 6945.5,4307.5 6949.7,4311.7 R2$CBB7.1@6972.1,4311.7 6972.1,4296 6962.4,4286.2 6962.4,4267.4 C9$CBB7.2@6958.7,4263.7
$1I23\$1N48: C10$CBB7.2 R5$CBB7.1 U5$CBB7.3 | length 102.9
  Top Layer w7.9: U5$CBB7.3@6924.5,4107.5 6945.5,4107.5 6949.7,4111.7 R5$CBB7.1@6972.1,4111.7 6972.1,4096 6962.4,4086.2 6962.4,4067.4 C10$CBB7.2@6958.7,4063.7
$1I23\$1N50: C11$CBB7.2 R4$CBB7.1 U4$CBB7.3 | length 102.9
  Top Layer w7.9: U4$CBB7.3@6924.5,3907.5 6945.5,3907.5 6949.7,3911.7 R4$CBB7.1@6972.1,3911.7 6972.1,3896 6962.4,3886.2 6962.4,3867.4 C11$CBB7.2@6958.7,3863.7
$1I25\$1I2\$2N1: C1$CBB9/CBB1.2 C2$CBB9/CBB1.2 Q5$CBB9/CBB1.1 Q6$CBB9/CBB1.2 R1$CBB9/CBB1.2 | length 249
  Top Layer w7.9: C2$CBB9/CBB1.2@7446.2,8910.3 7488.1,8910.3 C1$CBB9/CBB1.2@7489.6,8908.7 ; R1$CBB9/CBB1.2@7489.1,8868.7 7489.1,8908.2 C1$CBB9/CBB1.2@7489.6,8908.7 ; Q5$CBB9/CBB1.1@7573.8,8999.3 Q6$CBB9/CBB1.2@7523.6,8999.3 7506.8,8999.3 7491.2,8983.7 7491.2,8910.3 C1$CBB9/CBB1.2@7489.6,8908.7
$1I25\$1I2\$2N14: C3$CBB9/CBB1.2 C4$CBB9/CBB1.2 Q8$CBB9/CBB1.1 Q9$CBB9/CBB1.2 R2$CBB9/CBB1.2 | length 481.8
  Top Layer w7.9: Q9$CBB9/CBB1.2@7523.6,9084.3 Q8$CBB9/CBB1.1@7573.8,9084.3 7700.6,9084.3 7706.2,9078.7 7706.2,9051.4 7706.5,9051.1 7706.5,9036.4 7706.2,9036.1 7706.2,8948.7 7666.2,8908.7 7642.7,8908.7 C4$CBB9/CBB1.2@7641.2,8910.3 7639.6,8908.7 C3$CBB9/CBB1.2@7597.7,8908.7 7598.2,8908.2 R2$CBB9/CBB1.2@7598.2,8868.7
$1I25\$1I3\$2N1: C1$CBB9/CBB2.2 C2$CBB9/CBB2.2 Q5$CBB9/CBB2.1 Q6$CBB9/CBB2.2 R1$CBB9/CBB2.2 | length 249
  Top Layer w7.9: C2$CBB9/CBB2.2@7446.2,8390.3 7488.1,8390.3 C1$CBB9/CBB2.2@7489.6,8388.7 ; R1$CBB9/CBB2.2@7489.1,8348.7 7489.1,8388.2 C1$CBB9/CBB2.2@7489.6,8388.7 ; Q5$CBB9/CBB2.1@7573.8,8479.3 Q6$CBB9/CBB2.2@7523.6,8479.3 7506.8,8479.3 7491.2,8463.7 7491.2,8390.3 C1$CBB9/CBB2.2@7489.6,8388.7
$1I25\$1I3\$2N14: C3$CBB9/CBB2.2 C4$CBB9/CBB2.2 Q8$CBB9/CBB2.1 Q9$CBB9/CBB2.2 R2$CBB9/CBB2.2 | length 481.8
  Top Layer w7.9: Q9$CBB9/CBB2.2@7523.6,8564.3 Q8$CBB9/CBB2.1@7573.8,8564.3 7700.6,8564.3 7706.2,8558.7 7706.2,8531.4 7706.5,8531.1 7706.5,8516.4 7706.2,8516.1 7706.2,8428.7 7666.2,8388.7 7642.7,8388.7 C4$CBB9/CBB2.2@7641.2,8390.3 7639.6,8388.7 C3$CBB9/CBB2.2@7597.7,8388.7 7598.2,8388.2 R2$CBB9/CBB2.2@7598.2,8348.7
$1I25\$1I4\$2N1: C1$CBB9/CBB3.2 C2$CBB9/CBB3.2 Q5$CBB9/CBB3.1 Q6$CBB9/CBB3.2 R1$CBB9/CBB3.2 | length 249
  Top Layer w7.9: C2$CBB9/CBB3.2@7446.2,7605.3 7488.1,7605.3 C1$CBB9/CBB3.2@7489.6,7603.7 ; R1$CBB9/CBB3.2@7489.1,7563.7 7489.1,7603.2 C1$CBB9/CBB3.2@7489.6,7603.7 ; Q5$CBB9/CBB3.1@7573.8,7694.3 Q6$CBB9/CBB3.2@7523.6,7694.3 7506.8,7694.3 7491.2,7678.7 7491.2,7605.3 C1$CBB9/CBB3.2@7489.6,7603.7
$1I25\$1I4\$2N14: C3$CBB9/CBB3.2 C4$CBB9/CBB3.2 Q8$CBB9/CBB3.1 Q9$CBB9/CBB3.2 R2$CBB9/CBB3.2 | length 481.8
  Top Layer w7.9: Q9$CBB9/CBB3.2@7523.6,7779.3 Q8$CBB9/CBB3.1@7573.8,7779.3 7700.6,7779.3 7706.2,7773.7 7706.2,7746.4 7706.5,7746.1 7706.5,7731.4 7706.2,7731.1 7706.2,7643.7 7666.2,7603.7 7642.7,7603.7 C4$CBB9/CBB3.2@7641.2,7605.3 7639.6,7603.7 C3$CBB9/CBB3.2@7597.7,7603.7 7598.2,7603.2 R2$CBB9/CBB3.2@7598.2,7563.7
$1I25\$1I5\$2N1: C1$CBB9/CBB4.2 C2$CBB9/CBB4.2 Q5$CBB9/CBB4.1 Q6$CBB9/CBB4.2 R1$CBB9/CBB4.2 | length 249
  Top Layer w7.9: C2$CBB9/CBB4.2@7446.2,6820.3 7488.1,6820.3 C1$CBB9/CBB4.2@7489.6,6818.7 ; R1$CBB9/CBB4.2@7489.1,6778.7 7489.1,6818.2 C1$CBB9/CBB4.2@7489.6,6818.7 ; Q5$CBB9/CBB4.1@7573.8,6909.3 Q6$CBB9/CBB4.2@7523.6,6909.3 7506.8,6909.3 7491.2,6893.7 7491.2,6820.3 C1$CBB9/CBB4.2@7489.6,6818.7
$1I25\$1I5\$2N14: C3$CBB9/CBB4.2 C4$CBB9/CBB4.2 Q8$CBB9/CBB4.1 Q9$CBB9/CBB4.2 R2$CBB9/CBB4.2 | length 481.8
  Top Layer w7.9: Q9$CBB9/CBB4.2@7523.6,6994.3 Q8$CBB9/CBB4.1@7573.8,6994.3 7700.6,6994.3 7706.2,6988.7 7706.2,6961.4 7706.5,6961.1 7706.5,6946.4 7706.2,6946.1 7706.2,6858.7 7666.2,6818.7 7642.7,6818.7 C4$CBB9/CBB4.2@7641.2,6820.3 7639.6,6818.7 C3$CBB9/CBB4.2@7597.7,6818.7 7598.2,6818.2 R2$CBB9/CBB4.2@7598.2,6778.7
$1I25\$1I6\$2N1: C1$CBB9/CBB5.2 C2$CBB9/CBB5.2 Q5$CBB9/CBB5.1 Q6$CBB9/CBB5.2 R1$CBB9/CBB5.2 | length 249
  Top Layer w7.9: C2$CBB9/CBB5.2@7446.2,6300.3 7488.1,6300.3 C1$CBB9/CBB5.2@7489.6,6298.7 ; R1$CBB9/CBB5.2@7489.1,6258.7 7489.1,6298.2 C1$CBB9/CBB5.2@7489.6,6298.7 ; Q5$CBB9/CBB5.1@7573.8,6389.3 Q6$CBB9/CBB5.2@7523.6,6389.3 7506.8,6389.3 7491.2,6373.7 7491.2,6300.3 C1$CBB9/CBB5.2@7489.6,6298.7
$1I25\$1I6\$2N14: C3$CBB9/CBB5.2 C4$CBB9/CBB5.2 Q8$CBB9/CBB5.1 Q9$CBB9/CBB5.2 R2$CBB9/CBB5.2 | length 481.8
  Top Layer w7.9: Q9$CBB9/CBB5.2@7523.6,6474.3 Q8$CBB9/CBB5.1@7573.8,6474.3 7700.6,6474.3 7706.2,6468.7 7706.2,6441.4 7706.5,6441.1 7706.5,6426.4 7706.2,6426.1 7706.2,6338.7 7666.2,6298.7 7642.7,6298.7 C4$CBB9/CBB5.2@7641.2,6300.3 7639.6,6298.7 C3$CBB9/CBB5.2@7597.7,6298.7 7598.2,6298.2 R2$CBB9/CBB5.2@7598.2,6258.7
$1I25\$1I7\$2N1: C1$CBB9/CBB6.2 C2$CBB9/CBB6.2 Q5$CBB9/CBB6.1 Q6$CBB9/CBB6.2 R1$CBB9/CBB6.2 | length 249
  Top Layer w7.9: C2$CBB9/CBB6.2@7446.2,5515.3 7488.1,5515.3 C1$CBB9/CBB6.2@7489.6,5513.7 ; R1$CBB9/CBB6.2@7489.1,5473.7 7489.1,5513.2 C1$CBB9/CBB6.2@7489.6,5513.7 ; Q5$CBB9/CBB6.1@7573.8,5604.3 Q6$CBB9/CBB6.2@7523.6,5604.3 7506.8,5604.3 7491.2,5588.7 7491.2,5515.3 C1$CBB9/CBB6.2@7489.6,5513.7
$1I25\$1I7\$2N14: C3$CBB9/CBB6.2 C4$CBB9/CBB6.2 Q8$CBB9/CBB6.1 Q9$CBB9/CBB6.2 R2$CBB9/CBB6.2 | length 481.8
  Top Layer w7.9: Q9$CBB9/CBB6.2@7523.6,5689.3 Q8$CBB9/CBB6.1@7573.8,5689.3 7700.6,5689.3 7706.2,5683.7 7706.2,5656.4 7706.5,5656.1 7706.5,5641.4 7706.2,5641.1 7706.2,5553.7 7666.2,5513.7 7642.7,5513.7 C4$CBB9/CBB6.2@7641.2,5515.3 7639.6,5513.7 C3$CBB9/CBB6.2@7597.7,5513.7 7598.2,5513.2 R2$CBB9/CBB6.2@7598.2,5473.7
$1I25\$1I8\$2N1: C1$CBB9/CBB7.2 C2$CBB9/CBB7.2 Q5$CBB9/CBB7.1 Q6$CBB9/CBB7.2 R1$CBB9/CBB7.2 | length 249
  Top Layer w7.9: C2$CBB9/CBB7.2@7954.9,8910.3 7996.8,8910.3 C1$CBB9/CBB7.2@7998.3,8908.7 ; R1$CBB9/CBB7.2@7997.8,8868.7 7997.8,8908.2 C1$CBB9/CBB7.2@7998.3,8908.7 ; Q5$CBB9/CBB7.1@8082.5,8999.3 Q6$CBB9/CBB7.2@8032.3,8999.3 8015.5,8999.3 7999.9,8983.7 7999.9,8910.3 C1$CBB9/CBB7.2@7998.3,8908.7
$1I25\$1I8\$2N14: C3$CBB9/CBB7.2 C4$CBB9/CBB7.2 Q8$CBB9/CBB7.1 Q9$CBB9/CBB7.2 R2$CBB9/CBB7.2 | length 481.8
  Top Layer w7.9: Q9$CBB9/CBB7.2@8032.3,9084.3 Q8$CBB9/CBB7.1@8082.5,9084.3 8209.3,9084.3 8214.9,9078.7 8214.9,9051.4 8215.2,9051.1 8215.2,9036.4 8214.9,9036.1 8214.9,8948.7 8174.9,8908.7 8151.4,8908.7 C4$CBB9/CBB7.2@8149.9,8910.3 8148.3,8908.7 C3$CBB9/CBB7.2@8106.4,8908.7 8106.9,8908.2 R2$CBB9/CBB7.2@8106.9,8868.7
$1I25\$1I9\$2N1: C1$CBB9/CBB8.2 C2$CBB9/CBB8.2 Q5$CBB9/CBB8.1 Q6$CBB9/CBB8.2 R1$CBB9/CBB8.2 | length 249
  Top Layer w7.9: C2$CBB9/CBB8.2@7954.9,8390.3 7996.8,8390.3 C1$CBB9/CBB8.2@7998.3,8388.7 ; R1$CBB9/CBB8.2@7997.8,8348.7 7997.8,8388.2 C1$CBB9/CBB8.2@7998.3,8388.7 ; Q5$CBB9/CBB8.1@8082.5,8479.3 Q6$CBB9/CBB8.2@8032.3,8479.3 8015.5,8479.3 7999.9,8463.7 7999.9,8390.3 C1$CBB9/CBB8.2@7998.3,8388.7
$1I25\$1I9\$2N14: C3$CBB9/CBB8.2 C4$CBB9/CBB8.2 Q8$CBB9/CBB8.1 Q9$CBB9/CBB8.2 R2$CBB9/CBB8.2 | length 481.8
  Top Layer w7.9: Q9$CBB9/CBB8.2@8032.3,8564.3 Q8$CBB9/CBB8.1@8082.5,8564.3 8209.3,8564.3 8214.9,8558.7 8214.9,8531.4 8215.2,8531.1 8215.2,8516.4 8214.9,8516.1 8214.9,8428.7 8174.9,8388.7 8151.4,8388.7 C4$CBB9/CBB8.2@8149.9,8390.3 8148.3,8388.7 C3$CBB9/CBB8.2@8106.4,8388.7 8106.9,8388.2 R2$CBB9/CBB8.2@8106.9,8348.7
$1I25\$1I10\$2N1: C1$CBB9/CBB9.2 C2$CBB9/CBB9.2 Q5$CBB9/CBB9.1 Q6$CBB9/CBB9.2 R1$CBB9/CBB9.2 | length 249
  Top Layer w7.9: C2$CBB9/CBB9.2@7954.9,7605.3 7996.8,7605.3 C1$CBB9/CBB9.2@7998.3,7603.7 ; R1$CBB9/CBB9.2@7997.8,7563.7 7997.8,7603.2 C1$CBB9/CBB9.2@7998.3,7603.7 ; Q5$CBB9/CBB9.1@8082.5,7694.3 Q6$CBB9/CBB9.2@8032.3,7694.3 8015.5,7694.3 7999.9,7678.7 7999.9,7605.3 C1$CBB9/CBB9.2@7998.3,7603.7
$1I25\$1I10\$2N14: C3$CBB9/CBB9.2 C4$CBB9/CBB9.2 Q8$CBB9/CBB9.1 Q9$CBB9/CBB9.2 R2$CBB9/CBB9.2 | length 481.8
  Top Layer w7.9: Q9$CBB9/CBB9.2@8032.3,7779.3 Q8$CBB9/CBB9.1@8082.5,7779.3 8209.3,7779.3 8214.9,7773.7 8214.9,7746.4 8215.2,7746.1 8215.2,7731.4 8214.9,7731.1 8214.9,7643.7 8174.9,7603.7 8151.4,7603.7 C4$CBB9/CBB9.2@8149.9,7605.3 8148.3,7603.7 C3$CBB9/CBB9.2@8106.4,7603.7 8106.9,7603.2 R2$CBB9/CBB9.2@8106.9,7563.7
$1I25\$1I11\$2N1: C1$CBB9/CBB10.2 C2$CBB9/CBB10.2 Q5$CBB9/CBB10.1 Q6$CBB9/CBB10.2 R1$CBB9/CBB10.2 | length 249
  Top Layer w7.9: C2$CBB9/CBB10.2@7954.9,6820.3 7996.8,6820.3 C1$CBB9/CBB10.2@7998.3,6818.7 ; R1$CBB9/CBB10.2@7997.8,6778.7 7997.8,6818.2 C1$CBB9/CBB10.2@7998.3,6818.7 ; Q5$CBB9/CBB10.1@8082.5,6909.3 Q6$CBB9/CBB10.2@8032.3,6909.3 8015.5,6909.3 7999.9,6893.7 7999.9,6820.3 C1$CBB9/CBB10.2@7998.3,6818.7
$1I25\$1I11\$2N14: C3$CBB9/CBB10.2 C4$CBB9/CBB10.2 Q8$CBB9/CBB10.1 Q9$CBB9/CBB10.2 R2$CBB9/CBB10.2 | length 481.8
  Top Layer w7.9: Q9$CBB9/CBB10.2@8032.3,6994.3 Q8$CBB9/CBB10.1@8082.5,6994.3 8209.3,6994.3 8214.9,6988.7 8214.9,6961.4 8215.2,6961.1 8215.2,6946.4 8214.9,6946.1 8214.9,6858.7 8174.9,6818.7 8151.4,6818.7 C4$CBB9/CBB10.2@8149.9,6820.3 8148.3,6818.7 C3$CBB9/CBB10.2@8106.4,6818.7 8106.9,6818.2 R2$CBB9/CBB10.2@8106.9,6778.7
$1I25\$1I12\$2N1: C1$CBB9/CBB11.2 C2$CBB9/CBB11.2 Q5$CBB9/CBB11.1 Q6$CBB9/CBB11.2 R1$CBB9/CBB11.2 | length 249
  Top Layer w7.9: C2$CBB9/CBB11.2@7954.9,6300.3 7996.8,6300.3 C1$CBB9/CBB11.2@7998.3,6298.7 ; R1$CBB9/CBB11.2@7997.8,6258.7 7997.8,6298.2 C1$CBB9/CBB11.2@7998.3,6298.7 ; Q5$CBB9/CBB11.1@8082.5,6389.3 Q6$CBB9/CBB11.2@8032.3,6389.3 8015.5,6389.3 7999.9,6373.7 7999.9,6300.3 C1$CBB9/CBB11.2@7998.3,6298.7
$1I25\$1I12\$2N14: C3$CBB9/CBB11.2 C4$CBB9/CBB11.2 Q8$CBB9/CBB11.1 Q9$CBB9/CBB11.2 R2$CBB9/CBB11.2 | length 481.8
  Top Layer w7.9: Q9$CBB9/CBB11.2@8032.3,6474.3 Q8$CBB9/CBB11.1@8082.5,6474.3 8209.3,6474.3 8214.9,6468.7 8214.9,6441.4 8215.2,6441.1 8215.2,6426.4 8214.9,6426.1 8214.9,6338.7 8174.9,6298.7 8151.4,6298.7 C4$CBB9/CBB11.2@8149.9,6300.3 8148.3,6298.7 C3$CBB9/CBB11.2@8106.4,6298.7 8106.9,6298.2 R2$CBB9/CBB11.2@8106.9,6258.7
$1I25\$1I13\$2N1: C1$CBB9/CBB12.2 C2$CBB9/CBB12.2 Q5$CBB9/CBB12.1 Q6$CBB9/CBB12.2 R1$CBB9/CBB12.2 | length 249
  Top Layer w7.9: C2$CBB9/CBB12.2@7954.9,5515.3 7996.8,5515.3 C1$CBB9/CBB12.2@7998.3,5513.7 ; R1$CBB9/CBB12.2@7997.8,5473.7 7997.8,5513.2 C1$CBB9/CBB12.2@7998.3,5513.7 ; Q5$CBB9/CBB12.1@8082.5,5604.3 Q6$CBB9/CBB12.2@8032.3,5604.3 8015.5,5604.3 7999.9,5588.7 7999.9,5515.3 C1$CBB9/CBB12.2@7998.3,5513.7
$1I25\$1I13\$2N14: C3$CBB9/CBB12.2 C4$CBB9/CBB12.2 Q8$CBB9/CBB12.1 Q9$CBB9/CBB12.2 R2$CBB9/CBB12.2 | length 481.8
  Top Layer w7.9: Q9$CBB9/CBB12.2@8032.3,5689.3 Q8$CBB9/CBB12.1@8082.5,5689.3 8209.3,5689.3 8214.9,5683.7 8214.9,5656.4 8215.2,5656.1 8215.2,5641.4 8214.9,5641.1 8214.9,5553.7 8174.9,5513.7 8151.4,5513.7 C4$CBB9/CBB12.2@8149.9,5515.3 8148.3,5513.7 C3$CBB9/CBB12.2@8106.4,5513.7 8106.9,5513.2 R2$CBB9/CBB12.2@8106.9,5473.7
$1I25\$1I14\$2N1: C1$CBB9/CBB13.2 C2$CBB9/CBB13.2 Q5$CBB9/CBB13.1 Q6$CBB9/CBB13.2 R1$CBB9/CBB13.2 | length 249
  Top Layer w7.9: C2$CBB9/CBB13.2@8463.6,8910.2 8505.5,8910.2 C1$CBB9/CBB13.2@8507,8908.7 ; R1$CBB9/CBB13.2@8506.5,8868.7 8506.5,8908.2 C1$CBB9/CBB13.2@8507,8908.7 ; Q5$CBB9/CBB13.1@8591.2,8999.3 Q6$CBB9/CBB13.2@8541,8999.3 8524.2,8999.3 8508.6,8983.7 8508.6,8910.2 C1$CBB9/CBB13.2@8507,8908.7
$1I25\$1I14\$2N14: C3$CBB9/CBB13.2 C4$CBB9/CBB13.2 Q8$CBB9/CBB13.1 Q9$CBB9/CBB13.2 R2$CBB9/CBB13.2 | length 481.7
  Top Layer w7.9: Q9$CBB9/CBB13.2@8541,9084.3 Q8$CBB9/CBB13.1@8591.2,9084.3 8718,9084.3 8723.6,9078.7 8723.6,9051.3 8723.9,9051.1 8723.9,9036.3 8723.6,9036 8723.6,8948.7 8683.6,8908.7 8660.1,8908.7 8658.6,8910.2 8657,8908.7 C3$CBB9/CBB13.2@8615.1,8908.7 8615.6,8908.2 R2$CBB9/CBB13.2@8615.6,8868.7
$1I25\$1I15\$2N1: C1$CBB9/CBB14.2 C2$CBB9/CBB14.2 Q5$CBB9/CBB14.1 Q6$CBB9/CBB14.2 R1$CBB9/CBB14.2 | length 249
  Top Layer w7.9: C2$CBB9/CBB14.2@8463.6,8390.2 8505.5,8390.2 C1$CBB9/CBB14.2@8507,8388.7 ; R1$CBB9/CBB14.2@8506.5,8348.7 8506.5,8388.2 C1$CBB9/CBB14.2@8507,8388.7 ; Q5$CBB9/CBB14.1@8591.2,8479.3 Q6$CBB9/CBB14.2@8541,8479.3 8524.2,8479.3 8508.6,8463.7 8508.6,8390.2 C1$CBB9/CBB14.2@8507,8388.7
$1I25\$1I15\$2N14: C3$CBB9/CBB14.2 C4$CBB9/CBB14.2 Q8$CBB9/CBB14.1 Q9$CBB9/CBB14.2 R2$CBB9/CBB14.2 | length 481.7
  Top Layer w7.9: Q9$CBB9/CBB14.2@8541,8564.3 Q8$CBB9/CBB14.1@8591.2,8564.3 8718,8564.3 8723.6,8558.7 8723.6,8531.3 8723.9,8531.1 8723.9,8516.3 8723.6,8516 8723.6,8428.7 8683.6,8388.7 8660.1,8388.7 8658.6,8390.2 8657,8388.7 C3$CBB9/CBB14.2@8615.1,8388.7 8615.6,8388.2 R2$CBB9/CBB14.2@8615.6,8348.7
$1I25\$1I16\$2N1: C1$CBB9/CBB15.2 C2$CBB9/CBB15.2 Q5$CBB9/CBB15.1 Q6$CBB9/CBB15.2 R1$CBB9/CBB15.2 | length 249
  Top Layer w7.9: C2$CBB9/CBB15.2@8463.6,7605.2 8505.5,7605.2 C1$CBB9/CBB15.2@8507,7603.7 ; R1$CBB9/CBB15.2@8506.5,7563.7 8506.5,7603.2 C1$CBB9/CBB15.2@8507,7603.7 ; Q5$CBB9/CBB15.1@8591.2,7694.3 Q6$CBB9/CBB15.2@8541,7694.3 8524.2,7694.3 8508.6,7678.7 8508.6,7605.2 C1$CBB9/CBB15.2@8507,7603.7
$1I25\$1I16\$2N14: C3$CBB9/CBB15.2 C4$CBB9/CBB15.2 Q8$CBB9/CBB15.1 Q9$CBB9/CBB15.2 R2$CBB9/CBB15.2 | length 481.7
  Top Layer w7.9: Q9$CBB9/CBB15.2@8541,7779.3 Q8$CBB9/CBB15.1@8591.2,7779.3 8718,7779.3 8723.6,7773.7 8723.6,7746.3 8723.9,7746.1 8723.9,7731.3 8723.6,7731 8723.6,7643.7 8683.6,7603.7 8660.1,7603.7 8658.6,7605.2 8657,7603.7 C3$CBB9/CBB15.2@8615.1,7603.7 8615.6,7603.2 R2$CBB9/CBB15.2@8615.6,7563.7
$1I25\$1I17\$2N1: C1$CBB9/CBB16.2 C2$CBB9/CBB16.2 Q5$CBB9/CBB16.1 Q6$CBB9/CBB16.2 R1$CBB9/CBB16.2 | length 249
  Top Layer w7.9: C2$CBB9/CBB16.2@8463.6,6820.2 8505.5,6820.2 C1$CBB9/CBB16.2@8507,6818.7 ; R1$CBB9/CBB16.2@8506.5,6778.7 8506.5,6818.2 C1$CBB9/CBB16.2@8507,6818.7 ; Q5$CBB9/CBB16.1@8591.2,6909.3 Q6$CBB9/CBB16.2@8541,6909.3 8524.2,6909.3 8508.6,6893.7 8508.6,6820.2 C1$CBB9/CBB16.2@8507,6818.7
$1I25\$1I17\$2N14: C3$CBB9/CBB16.2 C4$CBB9/CBB16.2 Q8$CBB9/CBB16.1 Q9$CBB9/CBB16.2 R2$CBB9/CBB16.2 | length 481.7
  Top Layer w7.9: Q9$CBB9/CBB16.2@8541,6994.3 Q8$CBB9/CBB16.1@8591.2,6994.3 8718,6994.3 8723.6,6988.7 8723.6,6961.3 8723.9,6961.1 8723.9,6946.3 8723.6,6946 8723.6,6858.7 8683.6,6818.7 8660.1,6818.7 8658.6,6820.2 8657,6818.7 C3$CBB9/CBB16.2@8615.1,6818.7 8615.6,6818.2 R2$CBB9/CBB16.2@8615.6,6778.7
$1I25\$1I18\$2N1: C1$CBB9/CBB17.2 C2$CBB9/CBB17.2 Q5$CBB9/CBB17.1 Q6$CBB9/CBB17.2 R1$CBB9/CBB17.2 | length 249
  Top Layer w7.9: C2$CBB9/CBB17.2@8463.6,6300.2 8505.5,6300.2 C1$CBB9/CBB17.2@8507,6298.7 ; R1$CBB9/CBB17.2@8506.5,6258.7 8506.5,6298.2 C1$CBB9/CBB17.2@8507,6298.7 ; Q5$CBB9/CBB17.1@8591.2,6389.3 Q6$CBB9/CBB17.2@8541,6389.3 8524.2,6389.3 8508.6,6373.7 8508.6,6300.2 C1$CBB9/CBB17.2@8507,6298.7
$1I25\$1I18\$2N14: C3$CBB9/CBB17.2 C4$CBB9/CBB17.2 Q8$CBB9/CBB17.1 Q9$CBB9/CBB17.2 R2$CBB9/CBB17.2 | length 481.7
  Top Layer w7.9: Q9$CBB9/CBB17.2@8541,6474.3 Q8$CBB9/CBB17.1@8591.2,6474.3 8718,6474.3 8723.6,6468.7 8723.6,6441.3 8723.9,6441.1 8723.9,6426.3 8723.6,6426 8723.6,6338.7 8683.6,6298.7 8660.1,6298.7 8658.6,6300.2 8657,6298.7 C3$CBB9/CBB17.2@8615.1,6298.7 8615.6,6298.2 R2$CBB9/CBB17.2@8615.6,6258.7
$1I25\$1I19\$2N1: C1$CBB9/CBB18.2 C2$CBB9/CBB18.2 Q5$CBB9/CBB18.1 Q6$CBB9/CBB18.2 R1$CBB9/CBB18.2 | length 249
  Top Layer w7.9: C2$CBB9/CBB18.2@8463.6,5515.2 8505.5,5515.2 C1$CBB9/CBB18.2@8507,5513.7 ; R1$CBB9/CBB18.2@8506.5,5473.7 8506.5,5513.2 C1$CBB9/CBB18.2@8507,5513.7 ; Q5$CBB9/CBB18.1@8591.2,5604.3 Q6$CBB9/CBB18.2@8541,5604.3 8524.2,5604.3 8508.6,5588.7 8508.6,5515.2 C1$CBB9/CBB18.2@8507,5513.7
$1I25\$1I19\$2N14: C3$CBB9/CBB18.2 C4$CBB9/CBB18.2 Q8$CBB9/CBB18.1 Q9$CBB9/CBB18.2 R2$CBB9/CBB18.2 | length 481.7
  Top Layer w7.9: Q9$CBB9/CBB18.2@8541,5689.3 Q8$CBB9/CBB18.1@8591.2,5689.3 8718,5689.3 8723.6,5683.7 8723.6,5656.3 8723.9,5656.1 8723.9,5641.3 8723.6,5641 8723.6,5553.7 8683.6,5513.7 8660.1,5513.7 8658.6,5515.2 8657,5513.7 C3$CBB9/CBB18.2@8615.1,5513.7 8615.6,5513.2 R2$CBB9/CBB18.2@8615.6,5473.7
$1I25\$1I20\$2N1: C1$CBB9/CBB19.2 C2$CBB9/CBB19.2 Q5$CBB9/CBB19.1 Q6$CBB9/CBB19.2 R1$CBB9/CBB19.2 | length 249
  Top Layer w7.9: C2$CBB9/CBB19.2@8972.3,8910.3 9014.2,8910.3 C1$CBB9/CBB19.2@9015.7,8908.7 ; R1$CBB9/CBB19.2@9015.2,8868.7 9015.2,8908.2 C1$CBB9/CBB19.2@9015.7,8908.7 ; Q5$CBB9/CBB19.1@9099.9,8999.3 Q6$CBB9/CBB19.2@9049.7,8999.3 9032.9,8999.3 9017.3,8983.7 9017.3,8910.3 C1$CBB9/CBB19.2@9015.7,8908.7
$1I25\$1I20\$2N14: C3$CBB9/CBB19.2 C4$CBB9/CBB19.2 Q8$CBB9/CBB19.1 Q9$CBB9/CBB19.2 R2$CBB9/CBB19.2 | length 481.8
  Top Layer w7.9: Q9$CBB9/CBB19.2@9049.7,9084.3 Q8$CBB9/CBB19.1@9099.9,9084.3 9226.7,9084.3 9232.3,9078.7 9232.3,9051.4 9232.6,9051.1 9232.6,9036.4 9232.3,9036.1 9232.3,8948.7 9192.3,8908.7 9168.8,8908.7 C4$CBB9/CBB19.2@9167.3,8910.3 9165.7,8908.7 C3$CBB9/CBB19.2@9123.8,8908.7 9124.3,8908.2 R2$CBB9/CBB19.2@9124.3,8868.7
$1I25\$1I21\$2N1: C1$CBB9/CBB20.2 C2$CBB9/CBB20.2 Q5$CBB9/CBB20.1 Q6$CBB9/CBB20.2 R1$CBB9/CBB20.2 | length 249
  Top Layer w7.9: C2$CBB9/CBB20.2@8972.3,8390.3 9014.2,8390.3 C1$CBB9/CBB20.2@9015.7,8388.7 ; R1$CBB9/CBB20.2@9015.2,8348.7 9015.2,8388.2 C1$CBB9/CBB20.2@9015.7,8388.7 ; Q5$CBB9/CBB20.1@9099.9,8479.3 Q6$CBB9/CBB20.2@9049.7,8479.3 9032.9,8479.3 9017.3,8463.7 9017.3,8390.3 C1$CBB9/CBB20.2@9015.7,8388.7
$1I25\$1I21\$2N14: C3$CBB9/CBB20.2 C4$CBB9/CBB20.2 Q8$CBB9/CBB20.1 Q9$CBB9/CBB20.2 R2$CBB9/CBB20.2 | length 481.8
  Top Layer w7.9: Q9$CBB9/CBB20.2@9049.7,8564.3 Q8$CBB9/CBB20.1@9099.9,8564.3 9226.7,8564.3 9232.3,8558.7 9232.3,8531.4 9232.6,8531.1 9232.6,8516.4 9232.3,8516.1 9232.3,8428.7 9192.3,8388.7 9168.8,8388.7 C4$CBB9/CBB20.2@9167.3,8390.3 9165.7,8388.7 C3$CBB9/CBB20.2@9123.8,8388.7 9124.3,8388.2 R2$CBB9/CBB20.2@9124.3,8348.7
$1I25\$1I22\$2N1: C1$CBB9/CBB21.2 C2$CBB9/CBB21.2 Q5$CBB9/CBB21.1 Q6$CBB9/CBB21.2 R1$CBB9/CBB21.2 | length 249
  Top Layer w7.9: C2$CBB9/CBB21.2@8972.3,7605.3 9014.2,7605.3 C1$CBB9/CBB21.2@9015.7,7603.7 ; R1$CBB9/CBB21.2@9015.2,7563.7 9015.2,7603.2 C1$CBB9/CBB21.2@9015.7,7603.7 ; Q5$CBB9/CBB21.1@9099.9,7694.3 Q6$CBB9/CBB21.2@9049.7,7694.3 9032.9,7694.3 9017.3,7678.7 9017.3,7605.3 C1$CBB9/CBB21.2@9015.7,7603.7
$1I25\$1I22\$2N14: C3$CBB9/CBB21.2 C4$CBB9/CBB21.2 Q8$CBB9/CBB21.1 Q9$CBB9/CBB21.2 R2$CBB9/CBB21.2 | length 481.8
  Top Layer w7.9: Q9$CBB9/CBB21.2@9049.7,7779.3 Q8$CBB9/CBB21.1@9099.9,7779.3 9226.7,7779.3 9232.3,7773.7 9232.3,7746.4 9232.6,7746.1 9232.6,7731.4 9232.3,7731.1 9232.3,7643.7 9192.3,7603.7 9168.8,7603.7 C4$CBB9/CBB21.2@9167.3,7605.3 9165.7,7603.7 C3$CBB9/CBB21.2@9123.8,7603.7 9124.3,7603.2 R2$CBB9/CBB21.2@9124.3,7563.7
$1I25\$1I23\$2N1: C1$CBB9/CBB22.2 C2$CBB9/CBB22.2 Q5$CBB9/CBB22.1 Q6$CBB9/CBB22.2 R1$CBB9/CBB22.2 | length 249
  Top Layer w7.9: C2$CBB9/CBB22.2@8972.3,6820.3 9014.2,6820.3 C1$CBB9/CBB22.2@9015.7,6818.7 ; R1$CBB9/CBB22.2@9015.2,6778.7 9015.2,6818.2 C1$CBB9/CBB22.2@9015.7,6818.7 ; Q5$CBB9/CBB22.1@9099.9,6909.3 Q6$CBB9/CBB22.2@9049.7,6909.3 9032.9,6909.3 9017.3,6893.7 9017.3,6820.3 C1$CBB9/CBB22.2@9015.7,6818.7
$1I25\$1I23\$2N14: C3$CBB9/CBB22.2 C4$CBB9/CBB22.2 Q8$CBB9/CBB22.1 Q9$CBB9/CBB22.2 R2$CBB9/CBB22.2 | length 481.8
  Top Layer w7.9: Q9$CBB9/CBB22.2@9049.7,6994.3 Q8$CBB9/CBB22.1@9099.9,6994.3 9226.7,6994.3 9232.3,6988.7 9232.3,6961.4 9232.6,6961.1 9232.6,6946.4 9232.3,6946.1 9232.3,6858.7 9192.3,6818.7 9168.8,6818.7 C4$CBB9/CBB22.2@9167.3,6820.3 9165.7,6818.7 C3$CBB9/CBB22.2@9123.8,6818.7 9124.3,6818.2 R2$CBB9/CBB22.2@9124.3,6778.7
$1I25\$1I24\$2N1: C1$CBB9/CBB23.2 C2$CBB9/CBB23.2 Q5$CBB9/CBB23.1 Q6$CBB9/CBB23.2 R1$CBB9/CBB23.2 | length 249
  Top Layer w7.9: C2$CBB9/CBB23.2@8972.3,6300.3 9014.2,6300.3 C1$CBB9/CBB23.2@9015.7,6298.7 ; R1$CBB9/CBB23.2@9015.2,6258.7 9015.2,6298.2 C1$CBB9/CBB23.2@9015.7,6298.7 ; Q5$CBB9/CBB23.1@9099.9,6389.3 Q6$CBB9/CBB23.2@9049.7,6389.3 9032.9,6389.3 9017.3,6373.7 9017.3,6300.3 C1$CBB9/CBB23.2@9015.7,6298.7
$1I25\$1I24\$2N14: C3$CBB9/CBB23.2 C4$CBB9/CBB23.2 Q8$CBB9/CBB23.1 Q9$CBB9/CBB23.2 R2$CBB9/CBB23.2 | length 481.8
  Top Layer w7.9: Q9$CBB9/CBB23.2@9049.7,6474.3 Q8$CBB9/CBB23.1@9099.9,6474.3 9226.7,6474.3 9232.3,6468.7 9232.3,6441.4 9232.6,6441.1 9232.6,6426.4 9232.3,6426.1 9232.3,6338.7 9192.3,6298.7 9168.8,6298.7 C4$CBB9/CBB23.2@9167.3,6300.3 9165.7,6298.7 C3$CBB9/CBB23.2@9123.8,6298.7 9124.3,6298.2 R2$CBB9/CBB23.2@9124.3,6258.7
$1I25\$1I25\$2N1: C1$CBB9/CBB24.2 C2$CBB9/CBB24.2 Q5$CBB9/CBB24.1 Q6$CBB9/CBB24.2 R1$CBB9/CBB24.2 | length 249
  Top Layer w7.9: C2$CBB9/CBB24.2@8972.3,5515.3 9014.2,5515.3 C1$CBB9/CBB24.2@9015.7,5513.7 ; R1$CBB9/CBB24.2@9015.2,5473.7 9015.2,5513.2 C1$CBB9/CBB24.2@9015.7,5513.7 ; Q5$CBB9/CBB24.1@9099.9,5604.3 Q6$CBB9/CBB24.2@9049.7,5604.3 9032.9,5604.3 9017.3,5588.7 9017.3,5515.3 C1$CBB9/CBB24.2@9015.7,5513.7
$1I25\$1I25\$2N14: C3$CBB9/CBB24.2 C4$CBB9/CBB24.2 Q8$CBB9/CBB24.1 Q9$CBB9/CBB24.2 R2$CBB9/CBB24.2 | length 481.8
  Top Layer w7.9: Q9$CBB9/CBB24.2@9049.7,5689.3 Q8$CBB9/CBB24.1@9099.9,5689.3 9226.7,5689.3 9232.3,5683.7 9232.3,5656.4 9232.6,5656.1 9232.6,5641.4 9232.3,5641.1 9232.3,5553.7 9192.3,5513.7 9168.8,5513.7 C4$CBB9/CBB24.2@9167.3,5515.3 9165.7,5513.7 C3$CBB9/CBB24.2@9123.8,5513.7 9124.3,5513.2 R2$CBB9/CBB24.2@9124.3,5473.7
$1I25\$1I26\$2N1: C1$CBB9/CBB25.2 C2$CBB9/CBB25.2 Q5$CBB9/CBB25.1 Q6$CBB9/CBB25.2 R1$CBB9/CBB25.2 | length 249
  Top Layer w7.9: C2$CBB9/CBB25.2@9481,8910.3 9522.9,8910.3 C1$CBB9/CBB25.2@9524.4,8908.7 ; R1$CBB9/CBB25.2@9523.9,8868.7 9523.9,8908.2 C1$CBB9/CBB25.2@9524.4,8908.7 ; Q5$CBB9/CBB25.1@9608.6,8999.3 Q6$CBB9/CBB25.2@9558.4,8999.3 9541.6,8999.3 9526,8983.7 9526,8910.3 C1$CBB9/CBB25.2@9524.4,8908.7
$1I25\$1I26\$2N14: C3$CBB9/CBB25.2 C4$CBB9/CBB25.2 Q8$CBB9/CBB25.1 Q9$CBB9/CBB25.2 R2$CBB9/CBB25.2 | length 481.8
  Top Layer w7.9: Q9$CBB9/CBB25.2@9558.4,9084.3 Q8$CBB9/CBB25.1@9608.6,9084.3 9735.4,9084.3 9741,9078.7 9741,9051.4 9741.3,9051.1 9741.3,9036.4 9741,9036.1 9741,8948.7 9701,8908.7 9677.5,8908.7 C4$CBB9/CBB25.2@9676,8910.3 9674.4,8908.7 C3$CBB9/CBB25.2@9632.5,8908.7 9633,8908.2 R2$CBB9/CBB25.2@9633,8868.7
$1I25\$1I27\$2N1: C1$CBB9/CBB26.2 C2$CBB9/CBB26.2 Q5$CBB9/CBB26.1 Q6$CBB9/CBB26.2 R1$CBB9/CBB26.2 | length 249
  Top Layer w7.9: C2$CBB9/CBB26.2@9481,8390.3 9522.9,8390.3 C1$CBB9/CBB26.2@9524.4,8388.7 ; R1$CBB9/CBB26.2@9523.9,8348.7 9523.9,8388.2 C1$CBB9/CBB26.2@9524.4,8388.7 ; Q5$CBB9/CBB26.1@9608.6,8479.3 Q6$CBB9/CBB26.2@9558.4,8479.3 9541.6,8479.3 9526,8463.7 9526,8390.3 C1$CBB9/CBB26.2@9524.4,8388.7
$1I25\$1I27\$2N14: C3$CBB9/CBB26.2 C4$CBB9/CBB26.2 Q8$CBB9/CBB26.1 Q9$CBB9/CBB26.2 R2$CBB9/CBB26.2 | length 481.8
  Top Layer w7.9: Q9$CBB9/CBB26.2@9558.4,8564.3 Q8$CBB9/CBB26.1@9608.6,8564.3 9735.4,8564.3 9741,8558.7 9741,8531.4 9741.3,8531.1 9741.3,8516.4 9741,8516.1 9741,8428.7 9701,8388.7 9677.5,8388.7 C4$CBB9/CBB26.2@9676,8390.3 9674.4,8388.7 C3$CBB9/CBB26.2@9632.5,8388.7 9633,8388.2 R2$CBB9/CBB26.2@9633,8348.7
$1I25\$1I28\$2N1: C1$CBB9/CBB27.2 C2$CBB9/CBB27.2 Q5$CBB9/CBB27.1 Q6$CBB9/CBB27.2 R1$CBB9/CBB27.2 | length 249
  Top Layer w7.9: C2$CBB9/CBB27.2@9481,7605.3 9522.9,7605.3 C1$CBB9/CBB27.2@9524.4,7603.7 ; R1$CBB9/CBB27.2@9523.9,7563.7 9523.9,7603.2 C1$CBB9/CBB27.2@9524.4,7603.7 ; Q5$CBB9/CBB27.1@9608.6,7694.3 Q6$CBB9/CBB27.2@9558.4,7694.3 9541.6,7694.3 9526,7678.7 9526,7605.3 C1$CBB9/CBB27.2@9524.4,7603.7
$1I25\$1I28\$2N14: C3$CBB9/CBB27.2 C4$CBB9/CBB27.2 Q8$CBB9/CBB27.1 Q9$CBB9/CBB27.2 R2$CBB9/CBB27.2 | length 481.8
  Top Layer w7.9: Q9$CBB9/CBB27.2@9558.4,7779.3 Q8$CBB9/CBB27.1@9608.6,7779.3 9735.4,7779.3 9741,7773.7 9741,7746.4 9741.3,7746.1 9741.3,7731.4 9741,7731.1 9741,7643.7 9701,7603.7 9677.5,7603.7 C4$CBB9/CBB27.2@9676,7605.3 9674.4,7603.7 C3$CBB9/CBB27.2@9632.5,7603.7 9633,7603.2 R2$CBB9/CBB27.2@9633,7563.7
$1I25\$1I29\$2N1: C1$CBB9/CBB28.2 C2$CBB9/CBB28.2 Q5$CBB9/CBB28.1 Q6$CBB9/CBB28.2 R1$CBB9/CBB28.2 | length 249
  Top Layer w7.9: C2$CBB9/CBB28.2@9481,6820.3 9522.9,6820.3 C1$CBB9/CBB28.2@9524.4,6818.7 ; R1$CBB9/CBB28.2@9523.9,6778.7 9523.9,6818.2 C1$CBB9/CBB28.2@9524.4,6818.7 ; Q5$CBB9/CBB28.1@9608.6,6909.3 Q6$CBB9/CBB28.2@9558.4,6909.3 9541.6,6909.3 9526,6893.7 9526,6820.3 C1$CBB9/CBB28.2@9524.4,6818.7
$1I25\$1I29\$2N14: C3$CBB9/CBB28.2 C4$CBB9/CBB28.2 Q8$CBB9/CBB28.1 Q9$CBB9/CBB28.2 R2$CBB9/CBB28.2 | length 481.8
  Top Layer w7.9: Q9$CBB9/CBB28.2@9558.4,6994.3 Q8$CBB9/CBB28.1@9608.6,6994.3 9735.4,6994.3 9741,6988.7 9741,6961.4 9741.3,6961.1 9741.3,6946.4 9741,6946.1 9741,6858.7 9701,6818.7 9677.5,6818.7 C4$CBB9/CBB28.2@9676,6820.3 9674.4,6818.7 C3$CBB9/CBB28.2@9632.5,6818.7 9633,6818.2 R2$CBB9/CBB28.2@9633,6778.7
$1I25\$1I30\$2N1: C1$CBB9/CBB29.2 C2$CBB9/CBB29.2 Q5$CBB9/CBB29.1 Q6$CBB9/CBB29.2 R1$CBB9/CBB29.2 | length 249
  Top Layer w7.9: C2$CBB9/CBB29.2@9481,6300.3 9522.9,6300.3 C1$CBB9/CBB29.2@9524.4,6298.7 ; R1$CBB9/CBB29.2@9523.9,6258.7 9523.9,6298.2 C1$CBB9/CBB29.2@9524.4,6298.7 ; Q5$CBB9/CBB29.1@9608.6,6389.3 Q6$CBB9/CBB29.2@9558.4,6389.3 9541.6,6389.3 9526,6373.7 9526,6300.3 C1$CBB9/CBB29.2@9524.4,6298.7
$1I25\$1I30\$2N14: C3$CBB9/CBB29.2 C4$CBB9/CBB29.2 Q8$CBB9/CBB29.1 Q9$CBB9/CBB29.2 R2$CBB9/CBB29.2 | length 481.8
  Top Layer w7.9: Q9$CBB9/CBB29.2@9558.4,6474.3 Q8$CBB9/CBB29.1@9608.6,6474.3 9735.4,6474.3 9741,6468.7 9741,6441.4 9741.3,6441.1 9741.3,6426.4 9741,6426.1 9741,6338.7 9701,6298.7 9677.5,6298.7 C4$CBB9/CBB29.2@9676,6300.3 9674.4,6298.7 C3$CBB9/CBB29.2@9632.5,6298.7 9633,6298.2 R2$CBB9/CBB29.2@9633,6258.7
$1I25\$1I31\$2N1: C1$CBB9/CBB30.2 C2$CBB9/CBB30.2 Q5$CBB9/CBB30.1 Q6$CBB9/CBB30.2 R1$CBB9/CBB30.2 | length 249
  Top Layer w7.9: C2$CBB9/CBB30.2@9481,5515.3 9522.9,5515.3 C1$CBB9/CBB30.2@9524.4,5513.7 ; R1$CBB9/CBB30.2@9523.9,5473.7 9523.9,5513.2 C1$CBB9/CBB30.2@9524.4,5513.7 ; Q5$CBB9/CBB30.1@9608.6,5604.3 Q6$CBB9/CBB30.2@9558.4,5604.3 9541.6,5604.3 9526,5588.7 9526,5515.3 C1$CBB9/CBB30.2@9524.4,5513.7
$1I25\$1I31\$2N14: C3$CBB9/CBB30.2 C4$CBB9/CBB30.2 Q8$CBB9/CBB30.1 Q9$CBB9/CBB30.2 R2$CBB9/CBB30.2 | length 481.8
  Top Layer w7.9: Q9$CBB9/CBB30.2@9558.4,5689.3 Q8$CBB9/CBB30.1@9608.6,5689.3 9735.4,5689.3 9741,5683.7 9741,5656.4 9741.3,5656.1 9741.3,5641.4 9741,5641.1 9741,5553.7 9701,5513.7 9677.5,5513.7 C4$CBB9/CBB30.2@9676,5515.3 9674.4,5513.7 C3$CBB9/CBB30.2@9632.5,5513.7 9633,5513.2 R2$CBB9/CBB30.2@9633,5473.7
$1I25\$1I32\$2N1: C1$CBB9/CBB31.2 C2$CBB9/CBB31.2 Q5$CBB9/CBB31.1 Q6$CBB9/CBB31.2 R1$CBB9/CBB31.2 | length 249
  Top Layer w7.9: C2$CBB9/CBB31.2@9989.7,8910.3 10031.6,8910.3 C1$CBB9/CBB31.2@10033.1,8908.7 ; R1$CBB9/CBB31.2@10032.6,8868.7 10032.6,8908.2 C1$CBB9/CBB31.2@10033.1,8908.7 ; Q5$CBB9/CBB31.1@10117.3,8999.3 Q6$CBB9/CBB31.2@10067.1,8999.3 10050.3,8999.3 10034.7,8983.7 10034.7,8910.3 C1$CBB9/CBB31.2@10033.1,8908.7
$1I25\$1I32\$2N14: C3$CBB9/CBB31.2 C4$CBB9/CBB31.2 Q8$CBB9/CBB31.1 Q9$CBB9/CBB31.2 R2$CBB9/CBB31.2 | length 481.8
  Top Layer w7.9: Q9$CBB9/CBB31.2@10067.1,9084.3 Q8$CBB9/CBB31.1@10117.3,9084.3 10244.1,9084.3 10249.7,9078.7 10249.7,9051.4 10250,9051.1 10250,9036.4 10249.7,9036.1 10249.7,8948.7 10209.7,8908.7 10186.2,8908.7 C4$CBB9/CBB31.2@10184.7,8910.3 10183.1,8908.7 C3$CBB9/CBB31.2@10141.2,8908.7 10141.7,8908.2 R2$CBB9/CBB31.2@10141.7,8868.7
$1I25\$1I33\$2N1: C1$CBB9/CBB32.2 C2$CBB9/CBB32.2 Q5$CBB9/CBB32.1 Q6$CBB9/CBB32.2 R1$CBB9/CBB32.2 | length 249
  Top Layer w7.9: C2$CBB9/CBB32.2@9989.7,8390.3 10031.6,8390.3 C1$CBB9/CBB32.2@10033.1,8388.7 ; R1$CBB9/CBB32.2@10032.6,8348.7 10032.6,8388.2 C1$CBB9/CBB32.2@10033.1,8388.7 ; Q5$CBB9/CBB32.1@10117.3,8479.3 Q6$CBB9/CBB32.2@10067.1,8479.3 10050.3,8479.3 10034.7,8463.7 10034.7,8390.3 C1$CBB9/CBB32.2@10033.1,8388.7
$1I25\$1I33\$2N14: C3$CBB9/CBB32.2 C4$CBB9/CBB32.2 Q8$CBB9/CBB32.1 Q9$CBB9/CBB32.2 R2$CBB9/CBB32.2 | length 481.8
  Top Layer w7.9: Q9$CBB9/CBB32.2@10067.1,8564.3 Q8$CBB9/CBB32.1@10117.3,8564.3 10244.1,8564.3 10249.7,8558.7 10249.7,8531.4 10250,8531.1 10250,8516.4 10249.7,8516.1 10249.7,8428.7 10209.7,8388.7 10186.2,8388.7 C4$CBB9/CBB32.2@10184.7,8390.3 10183.1,8388.7 C3$CBB9/CBB32.2@10141.2,8388.7 10141.7,8388.2 R2$CBB9/CBB32.2@10141.7,8348.7
$1I25\$1I34\$2N1: C1$CBB9/CBB33.2 C2$CBB9/CBB33.2 Q5$CBB9/CBB33.1 Q6$CBB9/CBB33.2 R1$CBB9/CBB33.2 | length 249
  Top Layer w7.9: C2$CBB9/CBB33.2@9989.7,7605.3 10031.6,7605.3 C1$CBB9/CBB33.2@10033.1,7603.7 ; R1$CBB9/CBB33.2@10032.6,7563.7 10032.6,7603.2 C1$CBB9/CBB33.2@10033.1,7603.7 ; Q5$CBB9/CBB33.1@10117.3,7694.3 Q6$CBB9/CBB33.2@10067.1,7694.3 10050.3,7694.3 10034.7,7678.7 10034.7,7605.3 C1$CBB9/CBB33.2@10033.1,7603.7
$1I25\$1I34\$2N14: C3$CBB9/CBB33.2 C4$CBB9/CBB33.2 Q8$CBB9/CBB33.1 Q9$CBB9/CBB33.2 R2$CBB9/CBB33.2 | length 481.8
  Top Layer w7.9: Q9$CBB9/CBB33.2@10067.1,7779.3 Q8$CBB9/CBB33.1@10117.3,7779.3 10244.1,7779.3 10249.7,7773.7 10249.7,7746.4 10250,7746.1 10250,7731.4 10249.7,7731.1 10249.7,7643.7 10209.7,7603.7 10186.2,7603.7 C4$CBB9/CBB33.2@10184.7,7605.3 10183.1,7603.7 C3$CBB9/CBB33.2@10141.2,7603.7 10141.7,7603.2 R2$CBB9/CBB33.2@10141.7,7563.7
$1I25\$1I35\$2N1: C1$CBB9/CBB34.2 C2$CBB9/CBB34.2 Q5$CBB9/CBB34.1 Q6$CBB9/CBB34.2 R1$CBB9/CBB34.2 | length 249
  Top Layer w7.9: C2$CBB9/CBB34.2@9989.7,6820.3 10031.6,6820.3 C1$CBB9/CBB34.2@10033.1,6818.7 ; R1$CBB9/CBB34.2@10032.6,6778.7 10032.6,6818.2 C1$CBB9/CBB34.2@10033.1,6818.7 ; Q5$CBB9/CBB34.1@10117.3,6909.3 Q6$CBB9/CBB34.2@10067.1,6909.3 10050.3,6909.3 10034.7,6893.7 10034.7,6820.3 C1$CBB9/CBB34.2@10033.1,6818.7
$1I25\$1I35\$2N14: C3$CBB9/CBB34.2 C4$CBB9/CBB34.2 Q8$CBB9/CBB34.1 Q9$CBB9/CBB34.2 R2$CBB9/CBB34.2 | length 481.8
  Top Layer w7.9: Q9$CBB9/CBB34.2@10067.1,6994.3 Q8$CBB9/CBB34.1@10117.3,6994.3 10244.1,6994.3 10249.7,6988.7 10249.7,6961.4 10250,6961.1 10250,6946.4 10249.7,6946.1 10249.7,6858.7 10209.7,6818.7 10186.2,6818.7 C4$CBB9/CBB34.2@10184.7,6820.3 10183.1,6818.7 C3$CBB9/CBB34.2@10141.2,6818.7 10141.7,6818.2 R2$CBB9/CBB34.2@10141.7,6778.7
$1I25\$1I36\$2N1: C1$CBB9/CBB35.2 C2$CBB9/CBB35.2 Q5$CBB9/CBB35.1 Q6$CBB9/CBB35.2 R1$CBB9/CBB35.2 | length 249
  Top Layer w7.9: C2$CBB9/CBB35.2@9989.7,6300.3 10031.6,6300.3 C1$CBB9/CBB35.2@10033.1,6298.7 ; R1$CBB9/CBB35.2@10032.6,6258.7 10032.6,6298.2 C1$CBB9/CBB35.2@10033.1,6298.7 ; Q5$CBB9/CBB35.1@10117.3,6389.3 Q6$CBB9/CBB35.2@10067.1,6389.3 10050.3,6389.3 10034.7,6373.7 10034.7,6300.3 C1$CBB9/CBB35.2@10033.1,6298.7
$1I25\$1I36\$2N14: C3$CBB9/CBB35.2 C4$CBB9/CBB35.2 Q8$CBB9/CBB35.1 Q9$CBB9/CBB35.2 R2$CBB9/CBB35.2 | length 481.8
  Top Layer w7.9: Q9$CBB9/CBB35.2@10067.1,6474.3 Q8$CBB9/CBB35.1@10117.3,6474.3 10244.1,6474.3 10249.7,6468.7 10249.7,6441.4 10250,6441.1 10250,6426.4 10249.7,6426.1 10249.7,6338.7 10209.7,6298.7 10186.2,6298.7 C4$CBB9/CBB35.2@10184.7,6300.3 10183.1,6298.7 C3$CBB9/CBB35.2@10141.2,6298.7 10141.7,6298.2 R2$CBB9/CBB35.2@10141.7,6258.7
$1I25\$1I37\$2N1: C1$CBB9/CBB36.2 C2$CBB9/CBB36.2 Q5$CBB9/CBB36.1 Q6$CBB9/CBB36.2 R1$CBB9/CBB36.2 | length 249
  Top Layer w7.9: C2$CBB9/CBB36.2@9989.7,5515.3 10031.6,5515.3 C1$CBB9/CBB36.2@10033.1,5513.7 ; R1$CBB9/CBB36.2@10032.6,5473.7 10032.6,5513.2 C1$CBB9/CBB36.2@10033.1,5513.7 ; Q5$CBB9/CBB36.1@10117.3,5604.3 Q6$CBB9/CBB36.2@10067.1,5604.3 10050.3,5604.3 10034.7,5588.7 10034.7,5515.3 C1$CBB9/CBB36.2@10033.1,5513.7
$1I25\$1I37\$2N14: C3$CBB9/CBB36.2 C4$CBB9/CBB36.2 Q8$CBB9/CBB36.1 Q9$CBB9/CBB36.2 R2$CBB9/CBB36.2 | length 481.8
  Top Layer w7.9: Q9$CBB9/CBB36.2@10067.1,5689.3 Q8$CBB9/CBB36.1@10117.3,5689.3 10244.1,5689.3 10249.7,5683.7 10249.7,5656.4 10250,5656.1 10250,5641.4 10249.7,5641.1 10249.7,5553.7 10209.7,5513.7 10186.2,5513.7 C4$CBB9/CBB36.2@10184.7,5515.3 10183.1,5513.7 C3$CBB9/CBB36.2@10141.2,5513.7 10141.7,5513.2 R2$CBB9/CBB36.2@10141.7,5473.7
$1I25\$1I38\$2N1: C1$CBB9/CBB37.2 C2$CBB9/CBB37.2 Q5$CBB9/CBB37.1 Q6$CBB9/CBB37.2 R1$CBB9/CBB37.2 | length 249
  Top Layer w7.9: C2$CBB9/CBB37.2@7446.2,8125.3 7488.1,8125.3 C1$CBB9/CBB37.2@7489.6,8123.7 ; R1$CBB9/CBB37.2@7489.1,8083.7 7489.1,8123.2 C1$CBB9/CBB37.2@7489.6,8123.7 ; Q5$CBB9/CBB37.1@7573.8,8214.3 Q6$CBB9/CBB37.2@7523.6,8214.3 7506.8,8214.3 7491.2,8198.7 7491.2,8125.3 C1$CBB9/CBB37.2@7489.6,8123.7
$1I25\$1I38\$2N14: C3$CBB9/CBB37.2 C4$CBB9/CBB37.2 Q8$CBB9/CBB37.1 Q9$CBB9/CBB37.2 R2$CBB9/CBB37.2 | length 481.8
  Top Layer w7.9: Q9$CBB9/CBB37.2@7523.6,8299.3 Q8$CBB9/CBB37.1@7573.8,8299.3 7700.6,8299.3 7706.2,8293.7 7706.2,8266.4 7706.5,8266.1 7706.5,8251.4 7706.2,8251.1 7706.2,8163.7 7666.2,8123.7 7642.7,8123.7 C4$CBB9/CBB37.2@7641.2,8125.3 7639.6,8123.7 C3$CBB9/CBB37.2@7597.7,8123.7 7598.2,8123.2 R2$CBB9/CBB37.2@7598.2,8083.7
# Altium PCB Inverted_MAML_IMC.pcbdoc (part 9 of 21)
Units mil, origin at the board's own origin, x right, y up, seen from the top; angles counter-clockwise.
Board outline 7677.1 x 6771.6 mil, 6 copper layers (Top Layer, Inner1, Inner2, Inner3, Inner4, Bottom Layer), stack 60.7 mil thick; 2732 components, 1531 nets, 7765 pads, 3701 vias.

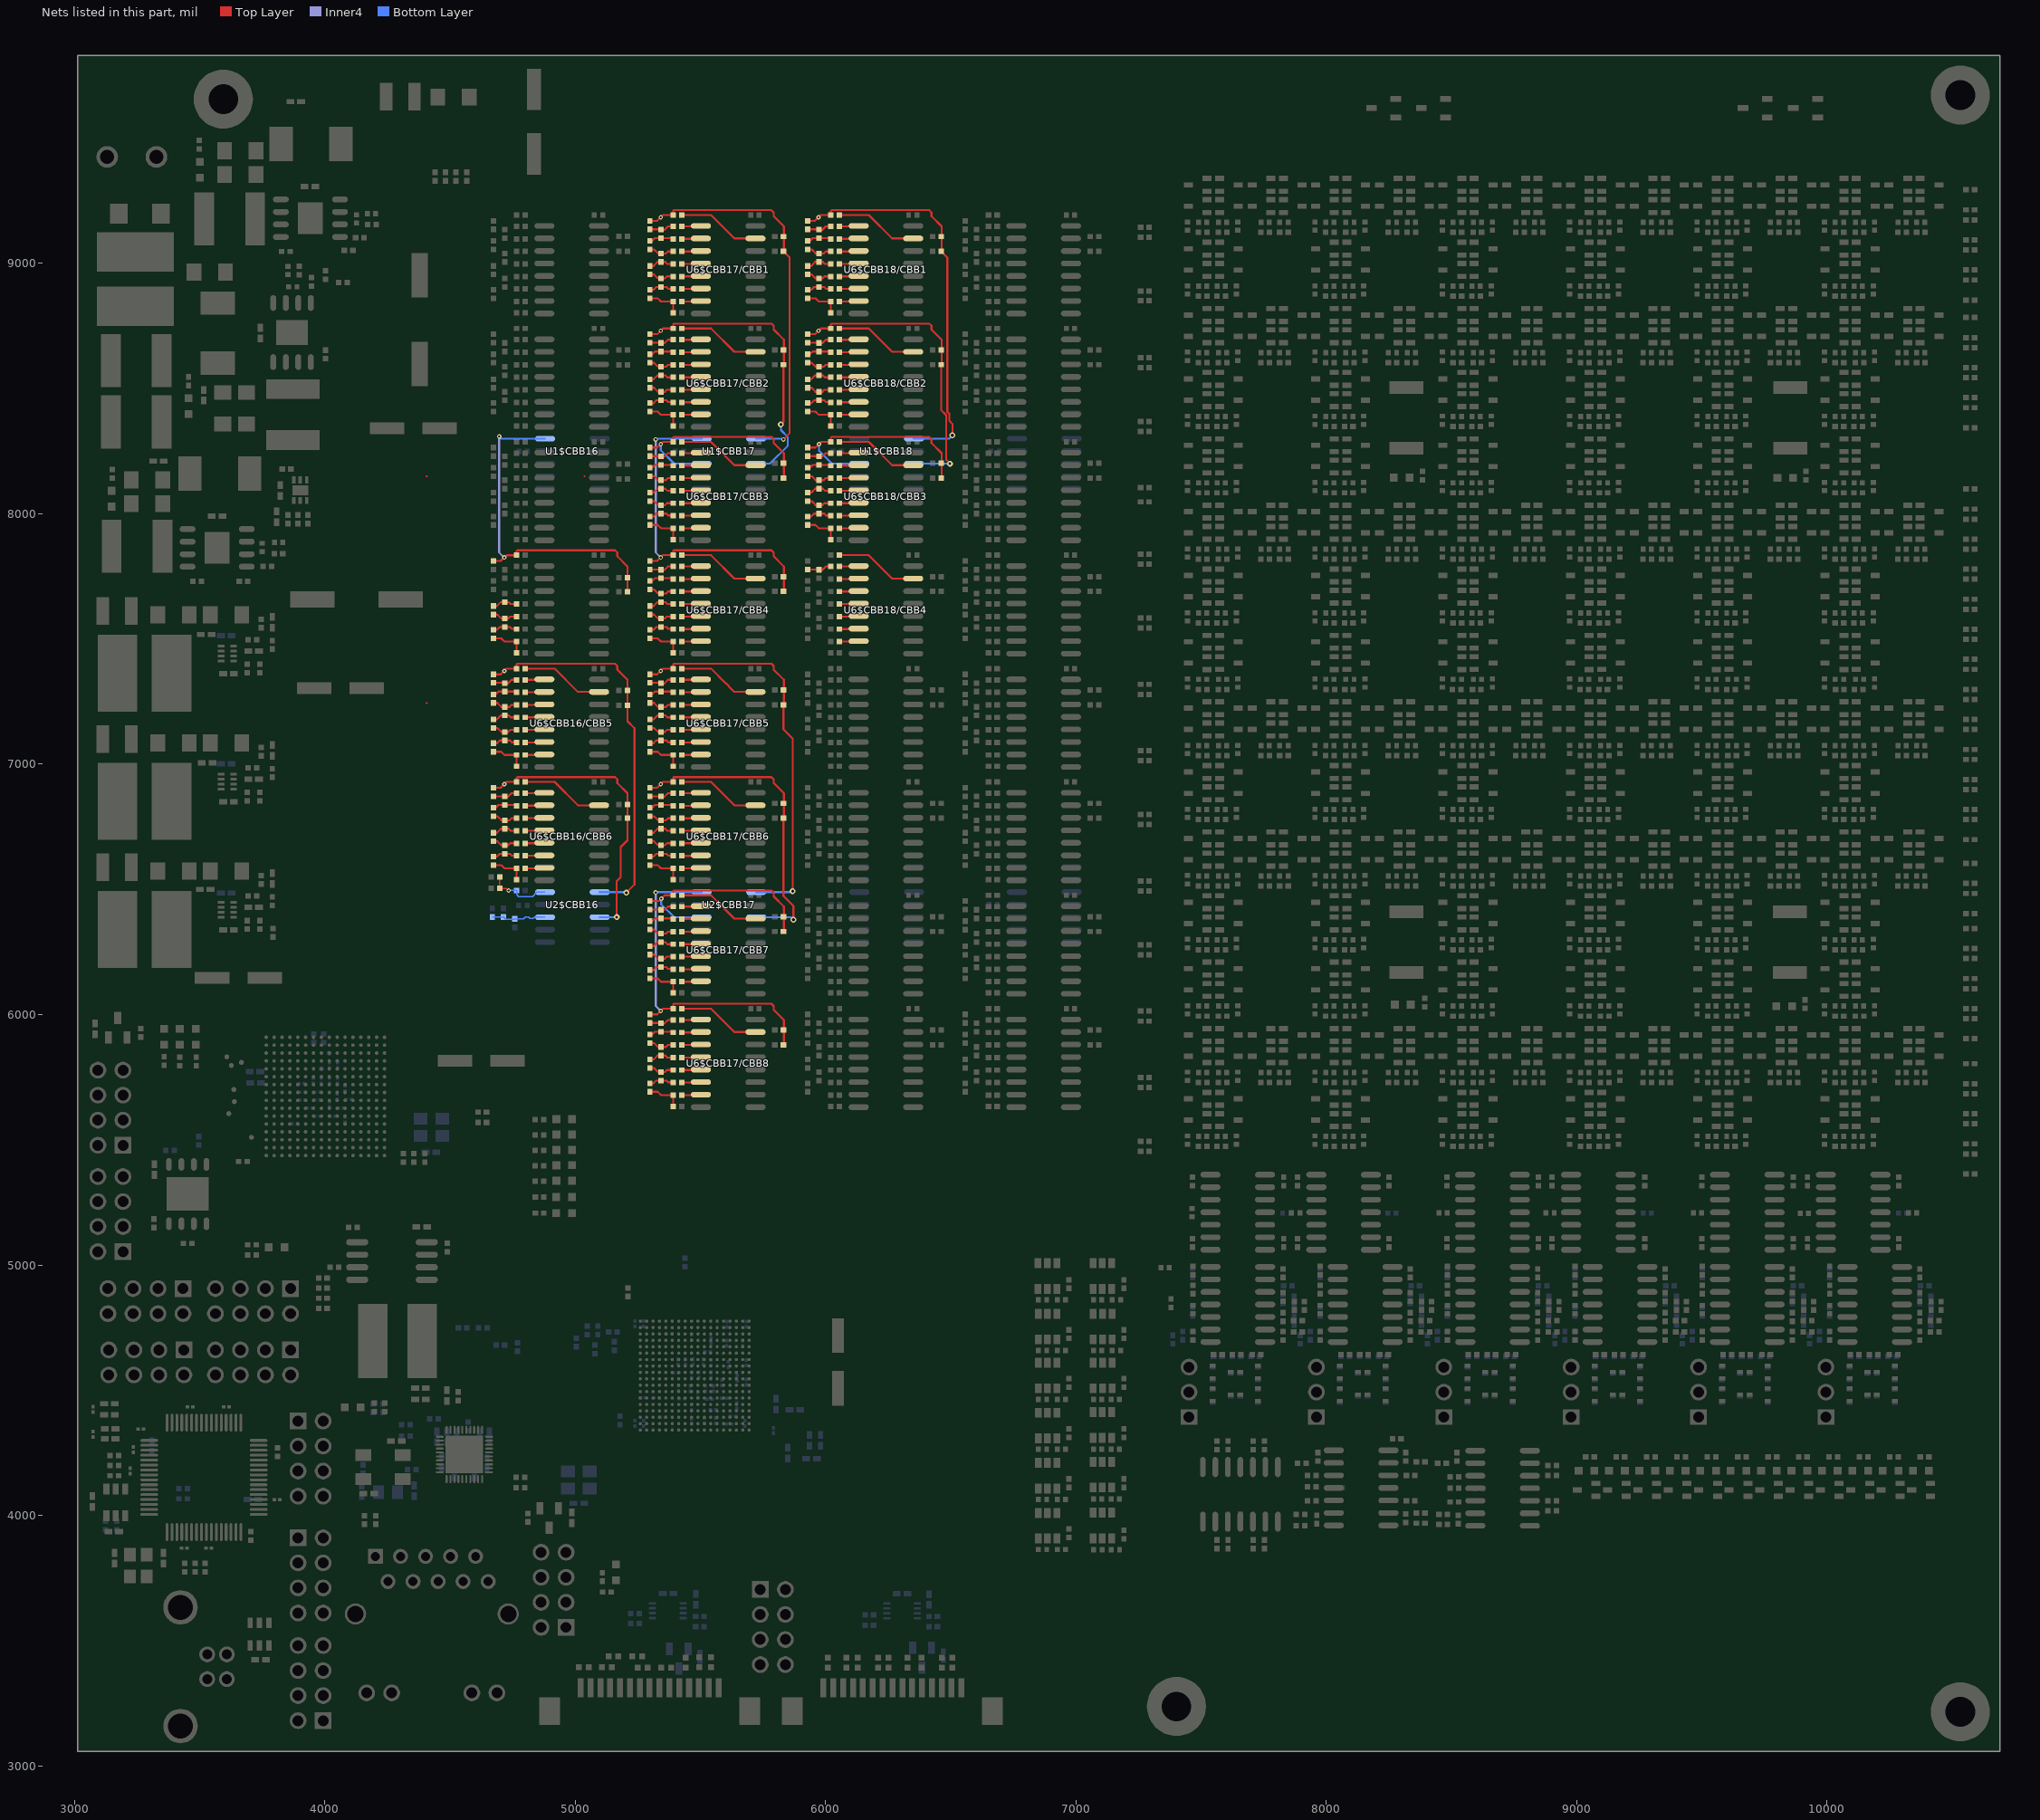
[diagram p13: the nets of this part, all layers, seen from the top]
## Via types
v1: diameter 17.7, hole 7.9, Top Layer to Bottom Layer, 3369 vias
v2: diameter 13.8, hole 7.9, Top Layer to Bottom Layer, 287 vias
v3: diameter 23.6, hole 11.8, Top Layer to Bottom Layer, 45 vias

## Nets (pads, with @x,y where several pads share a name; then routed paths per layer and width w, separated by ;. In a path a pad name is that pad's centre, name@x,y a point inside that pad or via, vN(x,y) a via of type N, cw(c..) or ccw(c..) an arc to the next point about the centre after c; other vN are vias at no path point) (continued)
$1I33\$1I23\$1N14: R4$CBB16/CBB4.2 R13$CBB16/CBB4.1 R14$CBB16/CBB4.2 | length 102.8
  Top Layer w7.9: R13$CBB16/CBB4.1@4673.8,7597.5 4690.1,7597.5 4706,7581.6 R14$CBB16/CBB4.2@4718.8,7581.6 4733.3,7581.6 4741.2,7589.5 R4$CBB16/CBB4.2@4766.7,7589.5
$1I33\$1I23\$1N15: R5$CBB16/CBB4.2 R12$CBB16/CBB4.1 R13$CBB16/CBB4.2 | length 102.8
  Top Layer w7.9: R13$CBB16/CBB4.2@4673.8,7631.6 4688.3,7631.6 4704.2,7647.5 R12$CBB16/CBB4.1@4718.8,7647.5 4735.1,7647.5 4743,7639.5 R5$CBB16/CBB4.2@4766.7,7639.5
$1I33\$1I23\$1N16: R1$CBB16/CBB4.2 R15$CBB16/CBB4.1 R16$CBB16/CBB4.2 | length 143.3
  Top Layer w7.9: R15$CBB16/CBB4.1@4673.8,7502.5 4705.1,7502.5 4718,7489.5 R1$CBB16/CBB4.2@4766.7,7489.5 R16$CBB16/CBB4.2@4766.7,7444.5
$1I33\$1I23\$1N17: R3$CBB16/CBB4.2 R14$CBB16/CBB4.1 R15$CBB16/CBB4.2 | length 100.8
  Top Layer w7.9: R15$CBB16/CBB4.2@4673.8,7536.6 4688.3,7536.6 4699.2,7547.5 R14$CBB16/CBB4.1@4718.8,7547.5 4740.1,7547.5 4747.1,7540.5 4765.8,7540.5 R3$CBB16/CBB4.2@4766.7,7539.5
$1I33\$1I23\DAC_LAD_OUT: R2$CBB16/CBB4.2 R9$CBB16/CBB4.2 R102$CBB16.1 R103$CBB16.2 U1$CBB16.12 | length 1375.4
  Top Layer w7.9: R2$CBB16/CBB4.2@4673.8,7811.6 4703.3,7811.6 v1(4717.1,7825.5) 4726.2,7834.5 R9$CBB16/CBB4.2@4766.7,7834.5 4766.7,7851.1 4769.8,7854.1 5159.5,7854.1 5168.5,7845.1 5168.5,7830.1 5209.2,7789.4 R103$CBB16.2@5209.2,7690.5
  Inner4 w7.9: v1(4697.1,8308.7) 4697.1,7845.5 v1(4717.1,7825.5)
  Bottom Layer w7.9: v1(4697.1,8308.7) 4705.7,8300.1 U1$CBB16.12@4880.3,8300.1
$1I33\$1I33\$1N1: R9$CBB16/CBB5.1 U6$CBB16/CBB5.15 | length 333.5
  Top Layer w7.9: R9$CBB16/CBB5.1@4800.8,7381.8 4918,7381.8 5011.3,7288.6 U6$CBB16/CBB5.15@5095.7,7288.6
$1I33\$1I33\$1N2: R8$CBB16/CBB5.1 U6$CBB16/CBB5.1 | length 77.6
  Top Layer w7.9: R8$CBB16/CBB5.1@4800.8,7336.8 4875.9,7336.8 U6$CBB16/CBB5.1@4877.6,7338.6
$1I33\$1I33\$1N3: R7$CBB16/CBB5.1 U6$CBB16/CBB5.2 | length 77.6
  Top Layer w7.9: R7$CBB16/CBB5.1@4800.8,7286.8 4875.9,7286.8 U6$CBB16/CBB5.2@4877.6,7288.6
$1I33\$1I33\$1N4: R6$CBB16/CBB5.1 U6$CBB16/CBB5.3 | length 77.6
  Top Layer w7.9: R6$CBB16/CBB5.1@4800.8,7236.8 4875.9,7236.8 U6$CBB16/CBB5.3@4877.6,7238.6
$1I33\$1I33\$1N5: R5$CBB16/CBB5.1 U6$CBB16/CBB5.4 | length 77.6
  Top Layer w7.9: R5$CBB16/CBB5.1@4800.8,7186.8 4875.9,7186.8 U6$CBB16/CBB5.4@4877.6,7188.6
$1I33\$1I33\$1N6: R4$CBB16/CBB5.1 U6$CBB16/CBB5.5 | length 77.6
  Top Layer w7.9: R4$CBB16/CBB5.1@4800.8,7136.8 4875.9,7136.8 U6$CBB16/CBB5.5@4877.6,7138.6
$1I33\$1I33\$1N7: R3$CBB16/CBB5.1 U6$CBB16/CBB5.6 | length 77.6
  Top Layer w7.9: R3$CBB16/CBB5.1@4800.8,7086.8 4875.9,7086.8 U6$CBB16/CBB5.6@4877.6,7088.6
$1I33\$1I33\$1N8: R1$CBB16/CBB5.1 U6$CBB16/CBB5.7 | length 77.6
  Top Layer w7.9: R1$CBB16/CBB5.1@4800.8,7036.8 4875.9,7036.8 U6$CBB16/CBB5.7@4877.6,7038.6
$1I33\$1I33\$1N11: R2$CBB16/CBB5.1 R8$CBB16/CBB5.2 R10$CBB16/CBB5.2 | length 99.6
  Top Layer w7.9: R2$CBB16/CBB5.1@4673.8,7324.8 4717.9,7324.8 R10$CBB16/CBB5.2@4718.8,7323.8 4719.9,7322.7 4732.1,7322.7 4746.2,7336.8 R8$CBB16/CBB5.2@4766.7,7336.8
$1I33\$1I33\$1N12: R6$CBB16/CBB5.2 R11$CBB16/CBB5.1 R12$CBB16/CBB5.2 | length 102.9
  Top Layer w7.9: R11$CBB16/CBB5.1@4673.8,7244.8 4690.1,7244.8 4706,7228.8 R12$CBB16/CBB5.2@4718.8,7228.8 4738.3,7228.8 4746.2,7236.8 R6$CBB16/CBB5.2@4766.7,7236.8
$1I33\$1I33\$1N13: R7$CBB16/CBB5.2 R10$CBB16/CBB5.1 R11$CBB16/CBB5.2 | length 98.8
  Top Layer w7.9: R11$CBB16/CBB5.2@4673.8,7278.8 4683.3,7278.8 4694.2,7289.8 R10$CBB16/CBB5.1@4718.8,7289.8 4763.8,7289.8 R7$CBB16/CBB5.2@4766.7,7286.8
$1I33\$1I33\$1N14: R4$CBB16/CBB5.2 R13$CBB16/CBB5.1 R14$CBB16/CBB5.2 | length 102.9
  Top Layer w7.9: R13$CBB16/CBB5.1@4673.8,7144.8 4690.1,7144.8 4706,7128.8 R14$CBB16/CBB5.2@4718.8,7128.8 4733.3,7128.8 4741.2,7136.8 R4$CBB16/CBB5.2@4766.7,7136.8
$1I33\$1I33\$1N15: R5$CBB16/CBB5.2 R12$CBB16/CBB5.1 R13$CBB16/CBB5.2 | length 102.9
  Top Layer w7.9: R13$CBB16/CBB5.2@4673.8,7178.8 4688.3,7178.8 4704.2,7194.8 R12$CBB16/CBB5.1@4718.8,7194.8 4735.1,7194.8 4743,7186.8 R5$CBB16/CBB5.2@4766.7,7186.8
$1I33\$1I33\$1N16: R1$CBB16/CBB5.2 R15$CBB16/CBB5.1 R16$CBB16/CBB5.2 | length 143.3
  Top Layer w7.9: R15$CBB16/CBB5.1@4673.8,7049.8 4705.1,7049.8 4718,7036.8 R1$CBB16/CBB5.2@4766.7,7036.8 R16$CBB16/CBB5.2@4766.7,6991.8
$1I33\$1I33\$1N17: R3$CBB16/CBB5.2 R14$CBB16/CBB5.1 R15$CBB16/CBB5.2 | length 100.8
  Top Layer w7.9: R15$CBB16/CBB5.2@4673.8,7083.8 4688.3,7083.8 4699.2,7094.8 R14$CBB16/CBB5.1@4718.8,7094.8 4740.1,7094.8 4747.1,7087.7 4765.8,7087.7 R3$CBB16/CBB5.2@4766.7,7086.8
$1I33\$1I33\DAC_LAD_OUT: R2$CBB16/CBB5.2 R9$CBB16/CBB5.2 R104$CBB16.1 R105$CBB16.2 U2$CBB16.3 | length 1577
  Top Layer w7.9: R2$CBB16/CBB5.2@4673.8,7358.8 4703.3,7358.8 v1(4717.1,7372.7) 4726.2,7381.8 R9$CBB16/CBB5.2@4766.7,7381.8 4766.7,7398.4 4769.8,7401.4 5159.5,7401.4 5168.5,7392.4 5168.5,7377.4 5209.2,7336.7 R104$CBB16.1@5209.2,7294.2 R105$CBB16.2@5209.2,7237.7 ; v3(5204.6,6486.7) 5237.1,6519.3 5237.1,7143.7 5209.2,7171.7 R105$CBB16.2@5209.2,7234.2
  Bottom Layer w7.9: U2$CBB16.3@5098.4,6489.1 5202.2,6489.1 v3(5204.6,6486.7)
$1I33\$1I34\$1N1: R9$CBB16/CBB6.1 U6$CBB16/CBB6.15 | length 333.5
  Top Layer w7.9: R9$CBB16/CBB6.1@4800.8,6929.1 4918,6929.1 5011.3,6835.8 U6$CBB16/CBB6.15@5095.7,6835.8
$1I33\$1I34\$1N2: R8$CBB16/CBB6.1 U6$CBB16/CBB6.1 | length 77.5
  Top Layer w7.9: R8$CBB16/CBB6.1@4800.8,6884.1 4875.9,6884.1 U6$CBB16/CBB6.1@4877.6,6885.8
$1I33\$1I34\$1N3: R7$CBB16/CBB6.1 U6$CBB16/CBB6.2 | length 77.5
  Top Layer w7.9: R7$CBB16/CBB6.1@4800.8,6834.1 4875.9,6834.1 U6$CBB16/CBB6.2@4877.6,6835.8
$1I33\$1I34\$1N4: R6$CBB16/CBB6.1 U6$CBB16/CBB6.3 | length 77.5
  Top Layer w7.9: R6$CBB16/CBB6.1@4800.8,6784.1 4875.9,6784.1 U6$CBB16/CBB6.3@4877.6,6785.8
$1I33\$1I34\$1N5: R5$CBB16/CBB6.1 U6$CBB16/CBB6.4 | length 77.5
  Top Layer w7.9: R5$CBB16/CBB6.1@4800.8,6734.1 4875.9,6734.1 U6$CBB16/CBB6.4@4877.6,6735.8
$1I33\$1I34\$1N6: R4$CBB16/CBB6.1 U6$CBB16/CBB6.5 | length 77.5
  Top Layer w7.9: R4$CBB16/CBB6.1@4800.8,6684.1 4875.9,6684.1 U6$CBB16/CBB6.5@4877.6,6685.8
$1I33\$1I34\$1N7: R3$CBB16/CBB6.1 U6$CBB16/CBB6.6 | length 77.5
  Top Layer w7.9: R3$CBB16/CBB6.1@4800.8,6634.1 4875.9,6634.1 U6$CBB16/CBB6.6@4877.6,6635.8
$1I33\$1I34\$1N8: R1$CBB16/CBB6.1 U6$CBB16/CBB6.7 | length 77.5
  Top Layer w7.9: R1$CBB16/CBB6.1@4800.8,6584.1 4875.9,6584.1 U6$CBB16/CBB6.7@4877.6,6585.8
$1I33\$1I34\$1N11: R2$CBB16/CBB6.1 R8$CBB16/CBB6.2 R10$CBB16/CBB6.2 | length 99.6
  Top Layer w7.9: R2$CBB16/CBB6.1@4673.8,6872 4717.9,6872 R10$CBB16/CBB6.2@4718.8,6871.1 4719.9,6870 4732.1,6870 4746.2,6884.1 R8$CBB16/CBB6.2@4766.7,6884.1
$1I33\$1I34\$1N12: R6$CBB16/CBB6.2 R11$CBB16/CBB6.1 R12$CBB16/CBB6.2 | length 102.8
  Top Layer w7.9: R11$CBB16/CBB6.1@4673.8,6792 4690.1,6792 4706,6776.1 R12$CBB16/CBB6.2@4718.8,6776.1 4738.3,6776.1 4746.2,6784.1 R6$CBB16/CBB6.2@4766.7,6784.1
$1I33\$1I34\$1N13: R7$CBB16/CBB6.2 R10$CBB16/CBB6.1 R11$CBB16/CBB6.2 | length 98.6
  Top Layer w7.9: R11$CBB16/CBB6.2@4673.8,6826.1 4683.3,6826.1 4694.2,6837 R10$CBB16/CBB6.1@4718.8,6837 4763.8,6837 R7$CBB16/CBB6.2@4766.7,6834.1
$1I33\$1I34\$1N14: R4$CBB16/CBB6.2 R13$CBB16/CBB6.1 R14$CBB16/CBB6.2 | length 102.8
  Top Layer w7.9: R13$CBB16/CBB6.1@4673.8,6692 4690.1,6692 4706,6676.1 R14$CBB16/CBB6.2@4718.8,6676.1 4733.3,6676.1 4741.2,6684.1 R4$CBB16/CBB6.2@4766.7,6684.1
$1I33\$1I34\$1N15: R5$CBB16/CBB6.2 R12$CBB16/CBB6.1 R13$CBB16/CBB6.2 | length 102.8
  Top Layer w7.9: R13$CBB16/CBB6.2@4673.8,6726.1 4688.3,6726.1 4704.2,6742 R12$CBB16/CBB6.1@4718.8,6742 4735.1,6742 4743,6734.1 R5$CBB16/CBB6.2@4766.7,6734.1
$1I33\$1I34\$1N16: R1$CBB16/CBB6.2 R15$CBB16/CBB6.1 R16$CBB16/CBB6.2 | length 143.2
  Top Layer w7.9: R15$CBB16/CBB6.1@4673.8,6597 4705.1,6597 4718,6584.1 R1$CBB16/CBB6.2@4766.7,6584.1 R16$CBB16/CBB6.2@4766.7,6539.1
$1I33\$1I34\$1N17: R3$CBB16/CBB6.2 R14$CBB16/CBB6.1 R15$CBB16/CBB6.2 | length 100.7
  Top Layer w7.9: R15$CBB16/CBB6.2@4673.8,6631.1 4688.3,6631.1 4699.2,6642 R14$CBB16/CBB6.1@4718.8,6642 4740.1,6642 4747.1,6635 4765.8,6635 R3$CBB16/CBB6.2@4766.7,6634.1
$1I33\$1I34\DAC_LAD_OUT: R2$CBB16/CBB6.2 R9$CBB16/CBB6.2 R106$CBB16.1 R107$CBB16.2 U2$CBB16.5 | length 1177.9
  Top Layer w7.9: R2$CBB16/CBB6.2@4673.8,6906.1 4703.3,6906.1 v1(4717.1,6920) 4726.2,6929.1 R9$CBB16/CBB6.2@4766.7,6929.1 4766.7,6945.6 4769.8,6948.6 5159.5,6948.6 5168.5,6939.7 5168.5,6924.7 5209.2,6883.9 R107$CBB16.2@5209.2,6785 ; v3(5166.2,6389.1) 5166.2,6532.8 5182.1,6548.7 5182.1,6668.7 5209.2,6695.8 R107$CBB16.2@5209.2,6784.2
  Bottom Layer w7.9: U2$CBB16.5@5098.4,6389.1 v3(5166.2,6389.1)
$1I33\TRIM_B1: R64$CBB16.1 R64.2 R80$CBB16.2 U2$CBB16.10 | length 222.7
  Bottom Layer w4.7: R80$CBB16.2@4669.6,6389.6 R64$CBB16.1@4714.6,6389.6 4723,6381.2 4758.7,6381.2 R64.2@4759.7,6382.2 4794.8,6382.2 4801.9,6389.3 4813.8,6389.3 4819.7,6383.3 4833.1,6383.3 4839.1,6389.3 4880.2,6389.3 U2$CBB16.10@4880.3,6389.1
$1I33\TRIM_REF: R1.2 R96$CBB16.1 R97$CBB16.2 U2$CBB16.12 | length 256.5
  Top Layer w4.7: R96$CBB16.1@4699.2,6549.2 R97$CBB16.2@4699.2,6504.2 4726.1,6504.2 v1(4734.7,6495.5)
  Bottom Layer w4.7: v1(4734.7,6495.5) 4734.9,6495.7 R1.2@4766.8,6495.7 4766.8,6479.6 4774.8,6471.6 4830,6471.6 4847.5,6489.1 U2$CBB16.12@4880.3,6489.1
$1I34\$1I15\$1N1: R9$CBB17/CBB1.1 U6$CBB17/CBB1.15 | length 333.5
  Top Layer w7.9: R9$CBB17/CBB1.1@5425.8,9192.8 5543,9192.8 5636.3,9099.6 U6$CBB17/CBB1.15@5720.7,9099.6
$1I34\$1I15\$1N2: R8$CBB17/CBB1.1 U6$CBB17/CBB1.1 | length 77.6
  Top Layer w7.9: R8$CBB17/CBB1.1@5425.8,9147.8 5500.9,9147.8 U6$CBB17/CBB1.1@5502.6,9149.6
$1I34\$1I15\$1N3: R7$CBB17/CBB1.1 U6$CBB17/CBB1.2 | length 77.6
  Top Layer w7.9: R7$CBB17/CBB1.1@5425.8,9097.8 5500.9,9097.8 U6$CBB17/CBB1.2@5502.6,9099.6
$1I34\$1I15\$1N4: R6$CBB17/CBB1.1 U6$CBB17/CBB1.3 | length 77.6
  Top Layer w7.9: R6$CBB17/CBB1.1@5425.8,9047.8 5500.9,9047.8 U6$CBB17/CBB1.3@5502.6,9049.6
$1I34\$1I15\$1N5: R5$CBB17/CBB1.1 U6$CBB17/CBB1.4 | length 77.6
  Top Layer w7.9: R5$CBB17/CBB1.1@5425.8,8997.8 5500.9,8997.8 U6$CBB17/CBB1.4@5502.6,8999.6
$1I34\$1I15\$1N6: R4$CBB17/CBB1.1 U6$CBB17/CBB1.5 | length 77.6
  Top Layer w7.9: R4$CBB17/CBB1.1@5425.8,8947.8 5500.9,8947.8 U6$CBB17/CBB1.5@5502.6,8949.6
$1I34\$1I15\$1N7: R3$CBB17/CBB1.1 U6$CBB17/CBB1.6 | length 77.6
  Top Layer w7.9: R3$CBB17/CBB1.1@5425.8,8897.8 5500.9,8897.8 U6$CBB17/CBB1.6@5502.6,8899.6
$1I34\$1I15\$1N8: R1$CBB17/CBB1.1 U6$CBB17/CBB1.7 | length 77.6
  Top Layer w7.9: R1$CBB17/CBB1.1@5425.8,8847.8 5500.9,8847.8 U6$CBB17/CBB1.7@5502.6,8849.6
$1I34\$1I15\$1N11: R2$CBB17/CBB1.1 R8$CBB17/CBB1.2 R10$CBB17/CBB1.2 | length 99.6
  Top Layer w7.9: R2$CBB17/CBB1.1@5298.8,9135.8 5342.9,9135.8 R10$CBB17/CBB1.2@5343.8,9134.9 5344.9,9133.7 5357.1,9133.7 5371.2,9147.8 R8$CBB17/CBB1.2@5391.7,9147.8
$1I34\$1I15\$1N12: R6$CBB17/CBB1.2 R11$CBB17/CBB1.1 R12$CBB17/CBB1.2 | length 102.8
  Top Layer w7.9: R11$CBB17/CBB1.1@5298.8,9055.8 5315.1,9055.8 5331,9039.9 R12$CBB17/CBB1.2@5343.8,9039.9 5363.3,9039.9 5371.2,9047.8 R6$CBB17/CBB1.2@5391.7,9047.8
$1I34\$1I15\$1N13: R7$CBB17/CBB1.2 R10$CBB17/CBB1.1 R11$CBB17/CBB1.2 | length 98.7
  Top Layer w7.9: R11$CBB17/CBB1.2@5298.8,9089.9 5308.3,9089.9 5319.2,9100.8 R10$CBB17/CBB1.1@5343.8,9100.8 5388.8,9100.8 R7$CBB17/CBB1.2@5391.7,9097.8
$1I34\$1I15\$1N14: R4$CBB17/CBB1.2 R13$CBB17/CBB1.1 R14$CBB17/CBB1.2 | length 102.8
  Top Layer w7.9: R13$CBB17/CBB1.1@5298.8,8955.8 5315.1,8955.8 5331,8939.9 R14$CBB17/CBB1.2@5343.8,8939.9 5358.3,8939.9 5366.2,8947.8 R4$CBB17/CBB1.2@5391.7,8947.8
$1I34\$1I15\$1N15: R5$CBB17/CBB1.2 R12$CBB17/CBB1.1 R13$CBB17/CBB1.2 | length 102.8
  Top Layer w7.9: R13$CBB17/CBB1.2@5298.8,8989.9 5313.3,8989.9 5329.2,9005.8 R12$CBB17/CBB1.1@5343.8,9005.8 5360.1,9005.8 5368,8997.8 R5$CBB17/CBB1.2@5391.7,8997.8
$1I34\$1I15\$1N16: R1$CBB17/CBB1.2 R15$CBB17/CBB1.1 R16$CBB17/CBB1.2 | length 143.3
  Top Layer w7.9: R15$CBB17/CBB1.1@5298.8,8860.8 5330.1,8860.8 5343,8847.8 R1$CBB17/CBB1.2@5391.7,8847.8 R16$CBB17/CBB1.2@5391.7,8802.8
$1I34\$1I15\$1N17: R3$CBB17/CBB1.2 R14$CBB17/CBB1.1 R15$CBB17/CBB1.2 | length 100.8
  Top Layer w7.9: R15$CBB17/CBB1.2@5298.8,8894.9 5313.3,8894.9 5324.2,8905.8 R14$CBB17/CBB1.1@5343.8,8905.8 5365.1,8905.8 5372.1,8898.7 5390.8,8898.7 R3$CBB17/CBB1.2@5391.7,8897.8
$1I34\$1I15\DAC_LAD_OUT: R2$CBB17/CBB1.2 R9$CBB17/CBB1.2 R16$CBB17.1 R32$CBB17.2 U1$CBB17.3 | length 1579.3
  Top Layer w7.9: R2$CBB17/CBB1.2@5298.8,9169.9 5328.3,9169.9 v1(5342.1,9183.7) 5351.2,9192.8 R9$CBB17/CBB1.2@5391.7,9192.8 5391.7,9209.4 5394.8,9212.4 5784.5,9212.4 5793.5,9203.4 5793.5,9188.4 5834.2,9147.7 R32$CBB17.2@5834.2,9048.7 ; R32$CBB17.2@5832,9048.1 5857.1,9023 5857.1,8321.9 v1(5832.1,8296.9)
  Bottom Layer w7.9: U1$CBB17.3@5723.4,8300.1 5828.9,8300.1 v1(5832.1,8296.9)
$1I34\$1I19\$1N1: R9$CBB17/CBB2.1 U6$CBB17/CBB2.15 | length 333.5
  Top Layer w7.9: R9$CBB17/CBB2.1@5425.8,8740.1 5543,8740.1 5636.3,8646.8 U6$CBB17/CBB2.15@5720.7,8646.8
$1I34\$1I19\$1N2: R8$CBB17/CBB2.1 U6$CBB17/CBB2.1 | length 77.5
  Top Layer w7.9: R8$CBB17/CBB2.1@5425.8,8695.1 5500.9,8695.1 U6$CBB17/CBB2.1@5502.6,8696.8
$1I34\$1I19\$1N3: R7$CBB17/CBB2.1 U6$CBB17/CBB2.2 | length 77.5
  Top Layer w7.9: R7$CBB17/CBB2.1@5425.8,8645.1 5500.9,8645.1 U6$CBB17/CBB2.2@5502.6,8646.8
$1I34\$1I19\$1N4: R6$CBB17/CBB2.1 U6$CBB17/CBB2.3 | length 77.5
  Top Layer w7.9: R6$CBB17/CBB2.1@5425.8,8595.1 5500.9,8595.1 U6$CBB17/CBB2.3@5502.6,8596.8
$1I34\$1I19\$1N5: R5$CBB17/CBB2.1 U6$CBB17/CBB2.4 | length 77.5
  Top Layer w7.9: R5$CBB17/CBB2.1@5425.8,8545.1 5500.9,8545.1 U6$CBB17/CBB2.4@5502.6,8546.8
$1I34\$1I19\$1N6: R4$CBB17/CBB2.1 U6$CBB17/CBB2.5 | length 77.5
  Top Layer w7.9: R4$CBB17/CBB2.1@5425.8,8495.1 5500.9,8495.1 U6$CBB17/CBB2.5@5502.6,8496.8
$1I34\$1I19\$1N7: R3$CBB17/CBB2.1 U6$CBB17/CBB2.6 | length 77.5
  Top Layer w7.9: R3$CBB17/CBB2.1@5425.8,8445.1 5500.9,8445.1 U6$CBB17/CBB2.6@5502.6,8446.8
$1I34\$1I19\$1N8: R1$CBB17/CBB2.1 U6$CBB17/CBB2.7 | length 77.5
  Top Layer w7.9: R1$CBB17/CBB2.1@5425.8,8395.1 5500.9,8395.1 U6$CBB17/CBB2.7@5502.6,8396.8
$1I34\$1I19\$1N11: R2$CBB17/CBB2.1 R8$CBB17/CBB2.2 R10$CBB17/CBB2.2 | length 99.6
  Top Layer w7.9: R2$CBB17/CBB2.1@5298.8,8683 5342.9,8683 R10$CBB17/CBB2.2@5343.8,8682.1 5344.9,8681 5357.1,8681 5371.2,8695.1 R8$CBB17/CBB2.2@5391.7,8695.1
$1I34\$1I19\$1N12: R6$CBB17/CBB2.2 R11$CBB17/CBB2.1 R12$CBB17/CBB2.2 | length 102.8
  Top Layer w7.9: R11$CBB17/CBB2.1@5298.8,8603 5315.1,8603 5331,8587.1 R12$CBB17/CBB2.2@5343.8,8587.1 5363.3,8587.1 5371.2,8595.1 R6$CBB17/CBB2.2@5391.7,8595.1
$1I34\$1I19\$1N13: R7$CBB17/CBB2.2 R10$CBB17/CBB2.1 R11$CBB17/CBB2.2 | length 98.6
  Top Layer w7.9: R11$CBB17/CBB2.2@5298.8,8637.1 5308.3,8637.1 5319.2,8648 R10$CBB17/CBB2.1@5343.8,8648 5388.8,8648 R7$CBB17/CBB2.2@5391.7,8645.1
$1I34\$1I19\$1N14: R4$CBB17/CBB2.2 R13$CBB17/CBB2.1 R14$CBB17/CBB2.2 | length 102.8
  Top Layer w7.9: R13$CBB17/CBB2.1@5298.8,8503 5315.1,8503 5331,8487.1 R14$CBB17/CBB2.2@5343.8,8487.1 5358.3,8487.1 5366.2,8495.1 R4$CBB17/CBB2.2@5391.7,8495.1
$1I34\$1I19\$1N15: R5$CBB17/CBB2.2 R12$CBB17/CBB2.1 R13$CBB17/CBB2.2 | length 102.8
  Top Layer w7.9: R13$CBB17/CBB2.2@5298.8,8537.1 5313.3,8537.1 5329.2,8553 R12$CBB17/CBB2.1@5343.8,8553 5360.1,8553 5368,8545.1 R5$CBB17/CBB2.2@5391.7,8545.1
$1I34\$1I19\$1N16: R1$CBB17/CBB2.2 R15$CBB17/CBB2.1 R16$CBB17/CBB2.2 | length 143.2
  Top Layer w7.9: R15$CBB17/CBB2.1@5298.8,8408 5330.1,8408 5343,8395.1 R1$CBB17/CBB2.2@5391.7,8395.1 R16$CBB17/CBB2.2@5391.7,8350.1
$1I34\$1I19\$1N17: R3$CBB17/CBB2.2 R14$CBB17/CBB2.1 R15$CBB17/CBB2.2 | length 100.7
  Top Layer w7.9: R15$CBB17/CBB2.2@5298.8,8442.1 5313.3,8442.1 5324.2,8453 R14$CBB17/CBB2.1@5343.8,8453 5365.1,8453 5372.1,8446 5390.8,8446 R3$CBB17/CBB2.2@5391.7,8445.1
$1I34\$1I19\DAC_LAD_OUT: R2$CBB17/CBB2.2 R9$CBB17/CBB2.2 R48$CBB17.1 R64$CBB17.2 U1$CBB17.5 | length 1192.8
  Top Layer w7.9: R2$CBB17/CBB2.2@5298.8,8717.1 5328.3,8717.1 v1(5342.1,8731) 5351.2,8740.1 R9$CBB17/CBB2.2@5391.7,8740.1 5391.7,8756.6 5394.8,8759.6 5784.5,8759.6 5793.5,8750.7 5793.5,8735.7 5834.2,8695 R64$CBB17.2@5834.2,8596 ; v3(5822.1,8357) 5832,8366.9 R64$CBB17.2@5832,8595.4
  Bottom Layer w7.9: U1$CBB17.5@5723.4,8200.1 5778.5,8200.1 5849.9,8271.5 5849.9,8306.1 5822.1,8333.9 v3(5822.1,8357)
$1I34\$1I21\$1N1: R9$CBB17/CBB3.1 U6$CBB17/CBB3.15 | length 333.5
  Top Layer w7.9: R9$CBB17/CBB3.1@5425.8,8287.3 5543,8287.3 5636.3,8194.1 U6$CBB17/CBB3.15@5720.7,8194.1
$1I34\$1I21\$1N2: R8$CBB17/CBB3.1 U6$CBB17/CBB3.1 | length 77.6
  Top Layer w7.9: R8$CBB17/CBB3.1@5425.8,8242.3 5500.9,8242.3 U6$CBB17/CBB3.1@5502.6,8244.1
$1I34\$1I21\$1N3: R7$CBB17/CBB3.1 U6$CBB17/CBB3.2 | length 77.6
  Top Layer w7.9: R7$CBB17/CBB3.1@5425.8,8192.3 5500.9,8192.3 U6$CBB17/CBB3.2@5502.6,8194.1
$1I34\$1I21\$1N4: R6$CBB17/CBB3.1 U6$CBB17/CBB3.3 | length 77.6
  Top Layer w7.9: R6$CBB17/CBB3.1@5425.8,8142.3 5500.9,8142.3 U6$CBB17/CBB3.3@5502.6,8144.1
$1I34\$1I21\$1N5: R5$CBB17/CBB3.1 U6$CBB17/CBB3.4 | length 77.6
  Top Layer w7.9: R5$CBB17/CBB3.1@5425.8,8092.3 5500.9,8092.3 U6$CBB17/CBB3.4@5502.6,8094.1
$1I34\$1I21\$1N6: R4$CBB17/CBB3.1 U6$CBB17/CBB3.5 | length 77.6
  Top Layer w7.9: R4$CBB17/CBB3.1@5425.8,8042.3 5500.9,8042.3 U6$CBB17/CBB3.5@5502.6,8044.1
$1I34\$1I21\$1N7: R3$CBB17/CBB3.1 U6$CBB17/CBB3.6 | length 77.6
  Top Layer w7.9: R3$CBB17/CBB3.1@5425.8,7992.3 5500.9,7992.3 U6$CBB17/CBB3.6@5502.6,7994.1
$1I34\$1I21\$1N8: R1$CBB17/CBB3.1 U6$CBB17/CBB3.7 | length 77.6
  Top Layer w7.9: R1$CBB17/CBB3.1@5425.8,7942.3 5500.9,7942.3 U6$CBB17/CBB3.7@5502.6,7944.1
$1I34\$1I21\$1N11: R2$CBB17/CBB3.1 R8$CBB17/CBB3.2 R10$CBB17/CBB3.2 | length 99.6
  Top Layer w7.9: R2$CBB17/CBB3.1@5298.8,8230.3 5342.9,8230.3 R10$CBB17/CBB3.2@5343.8,8229.4 5344.9,8228.2 5357.1,8228.2 5371.2,8242.3 R8$CBB17/CBB3.2@5391.7,8242.3
$1I34\$1I21\$1N12: R6$CBB17/CBB3.2 R11$CBB17/CBB3.1 R12$CBB17/CBB3.2 | length 102.8
  Top Layer w7.9: R11$CBB17/CBB3.1@5298.8,8150.3 5315.1,8150.3 5331,8134.4 R12$CBB17/CBB3.2@5343.8,8134.4 5363.3,8134.4 5371.2,8142.3 R6$CBB17/CBB3.2@5391.7,8142.3
$1I34\$1I21\$1N13: R7$CBB17/CBB3.2 R10$CBB17/CBB3.1 R11$CBB17/CBB3.2 | length 98.7
  Top Layer w7.9: R11$CBB17/CBB3.2@5298.8,8184.4 5308.3,8184.4 5319.2,8195.3 R10$CBB17/CBB3.1@5343.8,8195.3 5388.8,8195.3 R7$CBB17/CBB3.2@5391.7,8192.3
$1I34\$1I21\$1N14: R4$CBB17/CBB3.2 R13$CBB17/CBB3.1 R14$CBB17/CBB3.2 | length 102.8
  Top Layer w7.9: R13$CBB17/CBB3.1@5298.8,8050.3 5315.1,8050.3 5331,8034.4 R14$CBB17/CBB3.2@5343.8,8034.4 5358.3,8034.4 5366.2,8042.3 R4$CBB17/CBB3.2@5391.7,8042.3
$1I34\$1I21\$1N15: R5$CBB17/CBB3.2 R12$CBB17/CBB3.1 R13$CBB17/CBB3.2 | length 102.8
  Top Layer w7.9: R13$CBB17/CBB3.2@5298.8,8084.4 5313.3,8084.4 5329.2,8100.3 R12$CBB17/CBB3.1@5343.8,8100.3 5360.1,8100.3 5368,8092.3 R5$CBB17/CBB3.2@5391.7,8092.3
$1I34\$1I21\$1N16: R1$CBB17/CBB3.2 R15$CBB17/CBB3.1 R16$CBB17/CBB3.2 | length 143.3
  Top Layer w7.9: R15$CBB17/CBB3.1@5298.8,7955.3 5330.1,7955.3 5343,7942.3 R1$CBB17/CBB3.2@5391.7,7942.3 R16$CBB17/CBB3.2@5391.7,7897.3
$1I34\$1I21\$1N17: R3$CBB17/CBB3.2 R14$CBB17/CBB3.1 R15$CBB17/CBB3.2 | length 100.8
  Top Layer w7.9: R15$CBB17/CBB3.2@5298.8,7989.4 5313.3,7989.4 5324.2,8000.3 R14$CBB17/CBB3.1@5343.8,8000.3 5365.1,8000.3 5372.1,7993.2 5390.8,7993.2 R3$CBB17/CBB3.2@5391.7,7992.3
$1I34\$1I21\DAC_LAD_OUT: R2$CBB17/CBB3.2 R9$CBB17/CBB3.2 R80$CBB17.1 R96$CBB17.2 U1$CBB17.10 | length 907.3
  Top Layer w7.9: R2$CBB17/CBB3.2@5298.8,8264.4 5328.3,8264.4 v1(5342.1,8278.2) 5351.2,8287.3 R9$CBB17/CBB3.2@5391.7,8287.3 5391.7,8303.9 5394.8,8306.9 5784.5,8306.9 5793.5,8297.9 5793.5,8282.9 5834.2,8242.2 R96$CBB17.2@5834.2,8143.2
  Bottom Layer w7.9: v1(5342.1,8278.2) 5342.1,8253.7 5395.8,8200.1 U1$CBB17.10@5505.4,8200.1
$1I34\$1I23\$1N1: R9$CBB17/CBB4.1 U6$CBB17/CBB4.15 | length 333.5
  Top Layer w7.9: R9$CBB17/CBB4.1@5425.8,7834.6 5543,7834.6 5636.3,7741.3 U6$CBB17/CBB4.15@5720.7,7741.3
$1I34\$1I23\$1N2: R8$CBB17/CBB4.1 U6$CBB17/CBB4.1 | length 77.5
  Top Layer w7.9: R8$CBB17/CBB4.1@5425.8,7789.6 5500.9,7789.6 U6$CBB17/CBB4.1@5502.6,7791.3
$1I34\$1I23\$1N3: R7$CBB17/CBB4.1 U6$CBB17/CBB4.2 | length 77.5
  Top Layer w7.9: R7$CBB17/CBB4.1@5425.8,7739.6 5500.9,7739.6 U6$CBB17/CBB4.2@5502.6,7741.3
$1I34\$1I23\$1N4: R6$CBB17/CBB4.1 U6$CBB17/CBB4.3 | length 77.5
  Top Layer w7.9: R6$CBB17/CBB4.1@5425.8,7689.6 5500.9,7689.6 U6$CBB17/CBB4.3@5502.6,7691.3
$1I34\$1I23\$1N5: R5$CBB17/CBB4.1 U6$CBB17/CBB4.4 | length 77.5
  Top Layer w7.9: R5$CBB17/CBB4.1@5425.8,7639.6 5500.9,7639.6 U6$CBB17/CBB4.4@5502.6,7641.3
$1I34\$1I23\$1N6: R4$CBB17/CBB4.1 U6$CBB17/CBB4.5 | length 77.5
  Top Layer w7.9: R4$CBB17/CBB4.1@5425.8,7589.6 5500.9,7589.6 U6$CBB17/CBB4.5@5502.6,7591.3
$1I34\$1I23\$1N7: R3$CBB17/CBB4.1 U6$CBB17/CBB4.6 | length 77.5
  Top Layer w7.9: R3$CBB17/CBB4.1@5425.8,7539.6 5500.9,7539.6 U6$CBB17/CBB4.6@5502.6,7541.3
$1I34\$1I23\$1N8: R1$CBB17/CBB4.1 U6$CBB17/CBB4.7 | length 77.5
  Top Layer w7.9: R1$CBB17/CBB4.1@5425.8,7489.6 5500.9,7489.6 U6$CBB17/CBB4.7@5502.6,7491.3
$1I34\$1I23\$1N11: R2$CBB17/CBB4.1 R8$CBB17/CBB4.2 R10$CBB17/CBB4.2 | length 99.6
  Top Layer w7.9: R2$CBB17/CBB4.1@5298.8,7777.5 5342.9,7777.5 R10$CBB17/CBB4.2@5343.8,7776.6 5344.9,7775.5 5357.1,7775.5 5371.2,7789.6 R8$CBB17/CBB4.2@5391.7,7789.6
$1I34\$1I23\$1N12: R6$CBB17/CBB4.2 R11$CBB17/CBB4.1 R12$CBB17/CBB4.2 | length 102.8
  Top Layer w7.9: R11$CBB17/CBB4.1@5298.8,7697.5 5315.1,7697.5 5331,7681.6 R12$CBB17/CBB4.2@5343.8,7681.6 5363.3,7681.6 5371.2,7689.6 R6$CBB17/CBB4.2@5391.7,7689.6
$1I34\$1I23\$1N13: R7$CBB17/CBB4.2 R10$CBB17/CBB4.1 R11$CBB17/CBB4.2 | length 98.6
  Top Layer w7.9: R11$CBB17/CBB4.2@5298.8,7731.6 5308.3,7731.6 5319.2,7742.5 R10$CBB17/CBB4.1@5343.8,7742.5 5388.8,7742.5 R7$CBB17/CBB4.2@5391.7,7739.6
$1I34\$1I23\$1N14: R4$CBB17/CBB4.2 R13$CBB17/CBB4.1 R14$CBB17/CBB4.2 | length 102.8
  Top Layer w7.9: R13$CBB17/CBB4.1@5298.8,7597.5 5315.1,7597.5 5331,7581.6 R14$CBB17/CBB4.2@5343.8,7581.6 5358.3,7581.6 5366.2,7589.6 R4$CBB17/CBB4.2@5391.7,7589.6
$1I34\$1I23\$1N15: R5$CBB17/CBB4.2 R12$CBB17/CBB4.1 R13$CBB17/CBB4.2 | length 102.8
  Top Layer w7.9: R13$CBB17/CBB4.2@5298.8,7631.6 5313.3,7631.6 5329.2,7647.5 R12$CBB17/CBB4.1@5343.8,7647.5 5360.1,7647.5 5368,7639.6 R5$CBB17/CBB4.2@5391.7,7639.6
$1I34\$1I23\$1N16: R1$CBB17/CBB4.2 R15$CBB17/CBB4.1 R16$CBB17/CBB4.2 | length 143.2
  Top Layer w7.9: R15$CBB17/CBB4.1@5298.8,7502.5 5330.1,7502.5 5343,7489.6 R1$CBB17/CBB4.2@5391.7,7489.6 R16$CBB17/CBB4.2@5391.7,7444.6
$1I34\$1I23\$1N17: R3$CBB17/CBB4.2 R14$CBB17/CBB4.1 R15$CBB17/CBB4.2 | length 100.7
  Top Layer w7.9: R15$CBB17/CBB4.2@5298.8,7536.6 5313.3,7536.6 5324.2,7547.5 R14$CBB17/CBB4.1@5343.8,7547.5 5365.1,7547.5 5372.1,7540.5 5390.8,7540.5 R3$CBB17/CBB4.2@5391.7,7539.6
$1I34\$1I23\DAC_LAD_OUT: R2$CBB17/CBB4.2 R9$CBB17/CBB4.2 R112$CBB17.1 R128$CBB17.2 U1$CBB17.12 | length 1361.3
  Top Layer w7.9: R2$CBB17/CBB4.2@5298.8,7811.6 5328.3,7811.6 v1(5342.1,7825.5) 5351.2,7834.6 R9$CBB17/CBB4.2@5391.7,7834.6 5391.7,7851.1 5394.8,7854.1 5784.5,7854.1 5793.5,7845.1 5793.5,7830.1 5834.2,7789.4 R128$CBB17.2@5834.2,7690.5
  Inner4 w7.9: v1(5322.1,8296.9) 5322.1,7845.5 v1(5342.1,7825.5)
  Bottom Layer w7.9: v1(5322.1,8296.9) 5325.4,8300.1 U1$CBB17.12@5505.3,8300.1
$1I34\$1I33\$1N1: R9$CBB17/CBB5.1 U6$CBB17/CBB5.15 | length 334.2
  Top Layer w7.9: R9$CBB17/CBB5.1@5425.8,7381.8 5543,7381.8 5601.3,7323.6 5602.5,7323.6 5614.6,7311.4 5614.6,7310.2 5636.3,7288.6 U6$CBB17/CBB5.15@5720.7,7288.6
$1I34\$1I33\$1N2: R8$CBB17/CBB5.1 U6$CBB17/CBB5.1 | length 77.6
  Top Layer w7.9: R8$CBB17/CBB5.1@5425.8,7336.8 5500.9,7336.8 U6$CBB17/CBB5.1@5502.6,7338.6
$1I34\$1I33\$1N3: R7$CBB17/CBB5.1 U6$CBB17/CBB5.2 | length 77.6
  Top Layer w7.9: R7$CBB17/CBB5.1@5425.8,7286.8 5500.9,7286.8 U6$CBB17/CBB5.2@5502.6,7288.6
$1I34\$1I33\$1N4: R6$CBB17/CBB5.1 U6$CBB17/CBB5.3 | length 77.6
  Top Layer w7.9: R6$CBB17/CBB5.1@5425.8,7236.8 5500.9,7236.8 U6$CBB17/CBB5.3@5502.6,7238.6
$1I34\$1I33\$1N5: R5$CBB17/CBB5.1 U6$CBB17/CBB5.4 | length 77.6
  Top Layer w7.9: R5$CBB17/CBB5.1@5425.8,7186.8 5500.9,7186.8 U6$CBB17/CBB5.4@5502.6,7188.6
$1I34\$1I33\$1N6: R4$CBB17/CBB5.1 U6$CBB17/CBB5.5 | length 77.6
  Top Layer w7.9: R4$CBB17/CBB5.1@5425.8,7136.8 5500.9,7136.8 U6$CBB17/CBB5.5@5502.6,7138.6
$1I34\$1I33\$1N7: R3$CBB17/CBB5.1 U6$CBB17/CBB5.6 | length 77.6
  Top Layer w7.9: R3$CBB17/CBB5.1@5425.8,7086.8 5500.9,7086.8 U6$CBB17/CBB5.6@5502.6,7088.6
$1I34\$1I33\$1N8: R1$CBB17/CBB5.1 U6$CBB17/CBB5.7 | length 77.6
  Top Layer w7.9: R1$CBB17/CBB5.1@5425.8,7036.8 5500.9,7036.8 U6$CBB17/CBB5.7@5502.6,7038.6
$1I34\$1I33\$1N11: R2$CBB17/CBB5.1 R8$CBB17/CBB5.2 R10$CBB17/CBB5.2 | length 99.6
  Top Layer w7.9: R2$CBB17/CBB5.1@5298.8,7324.8 5342.9,7324.8 R10$CBB17/CBB5.2@5343.8,7323.8 5344.9,7322.7 5357.1,7322.7 5371.2,7336.8 R8$CBB17/CBB5.2@5391.7,7336.8
$1I34\$1I33\$1N12: R6$CBB17/CBB5.2 R11$CBB17/CBB5.1 R12$CBB17/CBB5.2 | length 102.9
  Top Layer w7.9: R11$CBB17/CBB5.1@5298.8,7244.8 5315.1,7244.8 5331,7228.8 R12$CBB17/CBB5.2@5343.8,7228.8 5363.3,7228.8 5371.2,7236.8 R6$CBB17/CBB5.2@5391.7,7236.8
$1I34\$1I33\$1N13: R7$CBB17/CBB5.2 R10$CBB17/CBB5.1 R11$CBB17/CBB5.2 | length 98.8
  Top Layer w7.9: R11$CBB17/CBB5.2@5298.8,7278.8 5308.3,7278.8 5319.2,7289.8 R10$CBB17/CBB5.1@5343.8,7289.8 5388.8,7289.8 R7$CBB17/CBB5.2@5391.7,7286.8
$1I34\$1I33\$1N14: R4$CBB17/CBB5.2 R13$CBB17/CBB5.1 R14$CBB17/CBB5.2 | length 102.9
  Top Layer w7.9: R13$CBB17/CBB5.1@5298.8,7144.8 5315.1,7144.8 5331,7128.8 R14$CBB17/CBB5.2@5343.8,7128.8 5358.3,7128.8 5366.2,7136.8 R4$CBB17/CBB5.2@5391.7,7136.8
$1I34\$1I33\$1N15: R5$CBB17/CBB5.2 R12$CBB17/CBB5.1 R13$CBB17/CBB5.2 | length 102.9
  Top Layer w7.9: R13$CBB17/CBB5.2@5298.8,7178.8 5313.3,7178.8 5329.2,7194.8 R12$CBB17/CBB5.1@5343.8,7194.8 5360.1,7194.8 5368,7186.8 R5$CBB17/CBB5.2@5391.7,7186.8
$1I34\$1I33\$1N16: R1$CBB17/CBB5.2 R15$CBB17/CBB5.1 R16$CBB17/CBB5.2 | length 143.3
  Top Layer w7.9: R15$CBB17/CBB5.1@5298.8,7049.8 5330.1,7049.8 5343,7036.8 R1$CBB17/CBB5.2@5391.7,7036.8 R16$CBB17/CBB5.2@5391.7,6991.8
$1I34\$1I33\$1N17: R3$CBB17/CBB5.2 R14$CBB17/CBB5.1 R15$CBB17/CBB5.2 | length 100.8
  Top Layer w7.9: R15$CBB17/CBB5.2@5298.8,7083.8 5313.3,7083.8 5324.2,7094.8 R14$CBB17/CBB5.1@5343.8,7094.8 5365.1,7094.8 5372.1,7087.7 5390.8,7087.7 R3$CBB17/CBB5.2@5391.7,7086.8
$1I34\$1I33\DAC_LAD_OUT: R2$CBB17/CBB5.2 R9$CBB17/CBB5.2 R129$CBB17.1 R130$CBB17.2 U2$CBB17.3 | length 1604.5
  Top Layer w7.9: R2$CBB17/CBB5.2@5298.8,7358.8 5328.3,7358.8 v1(5342.1,7372.7) 5351.2,7381.8 R9$CBB17/CBB5.2@5391.7,7381.8 5391.7,7398.4 5394.8,7401.4 5784.5,7401.4 5793.5,7392.4 5793.5,7381.7 5793.7,7381.5 5793.7,7377.2 5834.2,7336.7 R130$CBB17.2@5834.2,7237.7 ; R130$CBB17.2@5832,7237.1 5832.1,7237 5832.1,7138.7 5869.2,7101.7 v3(5869.2,6492.6)
  Bottom Layer w7.9: U2$CBB17.3@5723.4,6489.1 5865.7,6489.1 v3(5869.2,6492.6)
$1I34\$1I34\$1N1: R9$CBB17/CBB6.1 U6$CBB17/CBB6.15 | length 333.5
  Top Layer w7.9: R9$CBB17/CBB6.1@5425.8,6929 5543,6929 5636.3,6835.8 U6$CBB17/CBB6.15@5720.7,6835.8
$1I34\$1I34\$1N2: R8$CBB17/CBB6.1 U6$CBB17/CBB6.1 | length 77.6
  Top Layer w7.9: R8$CBB17/CBB6.1@5425.8,6884 5500.9,6884 U6$CBB17/CBB6.1@5502.6,6885.8
$1I34\$1I34\$1N3: R7$CBB17/CBB6.1 U6$CBB17/CBB6.2 | length 77.6
  Top Layer w7.9: R7$CBB17/CBB6.1@5425.8,6834 5500.9,6834 U6$CBB17/CBB6.2@5502.6,6835.8
$1I34\$1I34\$1N4: R6$CBB17/CBB6.1 U6$CBB17/CBB6.3 | length 77.6
  Top Layer w7.9: R6$CBB17/CBB6.1@5425.8,6784 5500.9,6784 U6$CBB17/CBB6.3@5502.6,6785.8
$1I34\$1I34\$1N5: R5$CBB17/CBB6.1 U6$CBB17/CBB6.4 | length 77.6
  Top Layer w7.9: R5$CBB17/CBB6.1@5425.8,6734 5500.9,6734 U6$CBB17/CBB6.4@5502.6,6735.8
$1I34\$1I34\$1N6: R4$CBB17/CBB6.1 U6$CBB17/CBB6.5 | length 77.6
  Top Layer w7.9: R4$CBB17/CBB6.1@5425.8,6684 5500.9,6684 U6$CBB17/CBB6.5@5502.6,6685.8
$1I34\$1I34\$1N7: R3$CBB17/CBB6.1 U6$CBB17/CBB6.6 | length 77.6
  Top Layer w7.9: R3$CBB17/CBB6.1@5425.8,6634 5500.9,6634 U6$CBB17/CBB6.6@5502.6,6635.8
$1I34\$1I34\$1N8: R1$CBB17/CBB6.1 U6$CBB17/CBB6.7 | length 77.6
  Top Layer w7.9: R1$CBB17/CBB6.1@5425.8,6584 5500.9,6584 U6$CBB17/CBB6.7@5502.6,6585.8
$1I34\$1I34\$1N11: R2$CBB17/CBB6.1 R8$CBB17/CBB6.2 R10$CBB17/CBB6.2 | length 99.5
  Top Layer w7.9: R2$CBB17/CBB6.1@5298.8,6872 5342.9,6872 R10$CBB17/CBB6.2@5343.8,6871.1 5344.9,6870 5357.1,6870 5371.2,6884 R8$CBB17/CBB6.2@5391.7,6884
$1I34\$1I34\$1N12: R6$CBB17/CBB6.2 R11$CBB17/CBB6.1 R12$CBB17/CBB6.2 | length 102.8
  Top Layer w7.9: R11$CBB17/CBB6.1@5298.8,6792 5315.1,6792 5331,6776.1 R12$CBB17/CBB6.2@5343.8,6776.1 5363.3,6776.1 5371.2,6784 R6$CBB17/CBB6.2@5391.7,6784
$1I34\$1I34\$1N13: R7$CBB17/CBB6.2 R10$CBB17/CBB6.1 R11$CBB17/CBB6.2 | length 98.7
  Top Layer w7.9: R11$CBB17/CBB6.2@5298.8,6826.1 5308.3,6826.1 5319.2,6837 R10$CBB17/CBB6.1@5343.8,6837 5388.8,6837 R7$CBB17/CBB6.2@5391.7,6834
$1I34\$1I34\$1N14: R4$CBB17/CBB6.2 R13$CBB17/CBB6.1 R14$CBB17/CBB6.2 | length 102.8
  Top Layer w7.9: R13$CBB17/CBB6.1@5298.8,6692 5315.1,6692 5331,6676.1 R14$CBB17/CBB6.2@5343.8,6676.1 5358.3,6676.1 5366.2,6684 R4$CBB17/CBB6.2@5391.7,6684
$1I34\$1I34\$1N15: R5$CBB17/CBB6.2 R12$CBB17/CBB6.1 R13$CBB17/CBB6.2 | length 102.8
  Top Layer w7.9: R13$CBB17/CBB6.2@5298.8,6726.1 5313.3,6726.1 5329.2,6742 R12$CBB17/CBB6.1@5343.8,6742 5360.1,6742 5368,6734 R5$CBB17/CBB6.2@5391.7,6734
$1I34\$1I34\$1N16: R1$CBB17/CBB6.2 R15$CBB17/CBB6.1 R16$CBB17/CBB6.2 | length 143.3
  Top Layer w7.9: R15$CBB17/CBB6.1@5298.8,6597 5330.1,6597 5343,6584 R1$CBB17/CBB6.2@5391.7,6584 R16$CBB17/CBB6.2@5391.7,6539
$1I34\$1I34\$1N17: R3$CBB17/CBB6.2 R14$CBB17/CBB6.1 R15$CBB17/CBB6.2 | length 100.8
  Top Layer w7.9: R15$CBB17/CBB6.2@5298.8,6631.1 5313.3,6631.1 5324.2,6642 R14$CBB17/CBB6.1@5343.8,6642 5365.1,6642 5372.1,6635 5390.8,6635 R3$CBB17/CBB6.2@5391.7,6634
$1I34\$1I34\DAC_LAD_OUT: R2$CBB17/CBB6.2 R9$CBB17/CBB6.2 R131$CBB17.1 R132$CBB17.2 U2$CBB17.5 | length 1272.5
  Top Layer w7.9: R2$CBB17/CBB6.2@5298.8,6906.1 5328.3,6906.1 v1(5342.1,6920) 5351.2,6929 R9$CBB17/CBB6.2@5391.7,6929 5391.7,6945.6 5394.8,6948.6 5784.5,6948.6 5793.5,6939.6 5793.5,6929 5793.7,6928.8 5793.7,6924.4 5834.2,6883.9 R132$CBB17.2@5834.2,6785 ; R132$CBB17.2@5832,6784.4 5832,6473.9 5872.1,6433.7 v3(5872.1,6378.7)
  Bottom Layer w7.9: U2$CBB17.5@5723.4,6389.1 5861.8,6389.1 v3(5872.1,6378.7)
$1I34\$1I35\$1N1: R9$CBB17/CBB7.1 U6$CBB17/CBB7.15 | length 333.5
  Top Layer w7.9: R9$CBB17/CBB7.1@5425.8,6476.3 5543,6476.3 5636.3,6383.1 U6$CBB17/CBB7.15@5720.7,6383.1
$1I34\$1I35\$1N2: R8$CBB17/CBB7.1 U6$CBB17/CBB7.1 | length 77.6
  Top Layer w7.9: R8$CBB17/CBB7.1@5425.8,6431.3 5500.9,6431.3 U6$CBB17/CBB7.1@5502.6,6433.1
$1I34\$1I35\$1N3: R7$CBB17/CBB7.1 U6$CBB17/CBB7.2 | length 77.6
  Top Layer w7.9: R7$CBB17/CBB7.1@5425.8,6381.3 5500.9,6381.3 U6$CBB17/CBB7.2@5502.6,6383.1
$1I34\$1I35\$1N4: R6$CBB17/CBB7.1 U6$CBB17/CBB7.3 | length 77.6
  Top Layer w7.9: R6$CBB17/CBB7.1@5425.8,6331.3 5500.9,6331.3 U6$CBB17/CBB7.3@5502.6,6333.1
$1I34\$1I35\$1N5: R5$CBB17/CBB7.1 U6$CBB17/CBB7.4 | length 77.6
  Top Layer w7.9: R5$CBB17/CBB7.1@5425.8,6281.3 5500.9,6281.3 U6$CBB17/CBB7.4@5502.6,6283.1
$1I34\$1I35\$1N6: R4$CBB17/CBB7.1 U6$CBB17/CBB7.5 | length 77.6
  Top Layer w7.9: R4$CBB17/CBB7.1@5425.8,6231.3 5500.9,6231.3 U6$CBB17/CBB7.5@5502.6,6233.1
$1I34\$1I35\$1N7: R3$CBB17/CBB7.1 U6$CBB17/CBB7.6 | length 77.6
  Top Layer w7.9: R3$CBB17/CBB7.1@5425.8,6181.3 5500.9,6181.3 U6$CBB17/CBB7.6@5502.6,6183.1
$1I34\$1I35\$1N8: R1$CBB17/CBB7.1 U6$CBB17/CBB7.7 | length 77.6
  Top Layer w7.9: R1$CBB17/CBB7.1@5425.8,6131.3 5500.9,6131.3 U6$CBB17/CBB7.7@5502.6,6133.1
$1I34\$1I35\$1N11: R2$CBB17/CBB7.1 R8$CBB17/CBB7.2 R10$CBB17/CBB7.2 | length 99.6
  Top Layer w7.9: R2$CBB17/CBB7.1@5298.8,6419.3 5342.9,6419.3 R10$CBB17/CBB7.2@5343.8,6418.3 5344.9,6417.2 5357.1,6417.2 5371.2,6431.3 R8$CBB17/CBB7.2@5391.7,6431.3
$1I34\$1I35\$1N12: R6$CBB17/CBB7.2 R11$CBB17/CBB7.1 R12$CBB17/CBB7.2 | length 102.9
  Top Layer w7.9: R11$CBB17/CBB7.1@5298.8,6339.3 5315.1,6339.3 5331,6323.3 R12$CBB17/CBB7.2@5343.8,6323.3 5363.3,6323.3 5371.2,6331.3 R6$CBB17/CBB7.2@5391.7,6331.3
$1I34\$1I35\$1N13: R7$CBB17/CBB7.2 R10$CBB17/CBB7.1 R11$CBB17/CBB7.2 | length 98.8
  Top Layer w7.9: R11$CBB17/CBB7.2@5298.8,6373.3 5308.3,6373.3 5319.2,6384.3 R10$CBB17/CBB7.1@5343.8,6384.3 5388.8,6384.3 R7$CBB17/CBB7.2@5391.7,6381.3
$1I34\$1I35\$1N14: R4$CBB17/CBB7.2 R13$CBB17/CBB7.1 R14$CBB17/CBB7.2 | length 102.9
  Top Layer w7.9: R13$CBB17/CBB7.1@5298.8,6239.3 5315.1,6239.3 5331,6223.3 R14$CBB17/CBB7.2@5343.8,6223.3 5358.3,6223.3 5366.2,6231.3 R4$CBB17/CBB7.2@5391.7,6231.3
$1I34\$1I35\$1N15: R5$CBB17/CBB7.2 R12$CBB17/CBB7.1 R13$CBB17/CBB7.2 | length 102.9
  Top Layer w7.9: R13$CBB17/CBB7.2@5298.8,6273.3 5313.3,6273.3 5329.2,6289.3 R12$CBB17/CBB7.1@5343.8,6289.3 5360.1,6289.3 5368,6281.3 R5$CBB17/CBB7.2@5391.7,6281.3
$1I34\$1I35\$1N16: R1$CBB17/CBB7.2 R15$CBB17/CBB7.1 R16$CBB17/CBB7.2 | length 143.3
  Top Layer w7.9: R15$CBB17/CBB7.1@5298.8,6144.3 5330.1,6144.3 5343,6131.3 R1$CBB17/CBB7.2@5391.7,6131.3 R16$CBB17/CBB7.2@5391.7,6086.3
$1I34\$1I35\$1N17: R3$CBB17/CBB7.2 R14$CBB17/CBB7.1 R15$CBB17/CBB7.2 | length 100.8
  Top Layer w7.9: R15$CBB17/CBB7.2@5298.8,6178.3 5313.3,6178.3 5324.2,6189.3 R14$CBB17/CBB7.1@5343.8,6189.3 5365.1,6189.3 5372.1,6182.2 5390.8,6182.2 R3$CBB17/CBB7.2@5391.7,6181.3
$1I34\$1I35\DAC_LAD_OUT: R2$CBB17/CBB7.2 R9$CBB17/CBB7.2 R133$CBB17.1 R134$CBB17.2 U2$CBB17.10 | length 902.2
  Top Layer w7.9: R2$CBB17/CBB7.2@5298.8,6453.3 5334.7,6453.3 v1(5344.4,6463.1) 5357.6,6476.3 R9$CBB17/CBB7.2@5391.7,6476.3 5391.7,6492.8 5394.8,6495.9 5784.5,6495.9 5793.5,6486.9 5793.5,6476.2 5793.7,6476 5793.7,6471.7 5834.2,6431.2 R134$CBB17.2@5834.2,6332.2
  Bottom Layer w7.9: v1(5344.4,6463.1) 5344.4,6440.4 5395.8,6389.1 U2$CBB17.10@5505.4,6389.1
$1I34\$1I36\$1N1: R9$CBB17/CBB8.1 U6$CBB17/CBB8.15 | length 333.5
  Top Layer w7.9: R9$CBB17/CBB8.1@5425.8,6023.5 5543,6023.5 5636.3,5930.3 U6$CBB17/CBB8.15@5720.7,5930.3
$1I34\$1I36\$1N2: R8$CBB17/CBB8.1 U6$CBB17/CBB8.1 | length 77.6
  Top Layer w7.9: R8$CBB17/CBB8.1@5425.8,5978.5 5500.9,5978.5 U6$CBB17/CBB8.1@5502.6,5980.3
$1I34\$1I36\$1N3: R7$CBB17/CBB8.1 U6$CBB17/CBB8.2 | length 77.6
  Top Layer w7.9: R7$CBB17/CBB8.1@5425.8,5928.5 5500.9,5928.5 U6$CBB17/CBB8.2@5502.6,5930.3
$1I34\$1I36\$1N4: R6$CBB17/CBB8.1 U6$CBB17/CBB8.3 | length 77.6
  Top Layer w7.9: R6$CBB17/CBB8.1@5425.8,5878.5 5500.9,5878.5 U6$CBB17/CBB8.3@5502.6,5880.3
$1I34\$1I36\$1N5: R5$CBB17/CBB8.1 U6$CBB17/CBB8.4 | length 77.6
  Top Layer w7.9: R5$CBB17/CBB8.1@5425.8,5828.5 5500.9,5828.5 U6$CBB17/CBB8.4@5502.6,5830.3
$1I34\$1I36\$1N6: R4$CBB17/CBB8.1 U6$CBB17/CBB8.5 | length 77.6
  Top Layer w7.9: R4$CBB17/CBB8.1@5425.8,5778.5 5500.9,5778.5 U6$CBB17/CBB8.5@5502.6,5780.3
$1I34\$1I36\$1N7: R3$CBB17/CBB8.1 U6$CBB17/CBB8.6 | length 77.6
  Top Layer w7.9: R3$CBB17/CBB8.1@5425.8,5728.5 5500.9,5728.5 U6$CBB17/CBB8.6@5502.6,5730.3
$1I34\$1I36\$1N8: R1$CBB17/CBB8.1 U6$CBB17/CBB8.7 | length 77.6
  Top Layer w7.9: R1$CBB17/CBB8.1@5425.8,5678.5 5500.9,5678.5 U6$CBB17/CBB8.7@5502.6,5680.3
$1I34\$1I36\$1N11: R2$CBB17/CBB8.1 R8$CBB17/CBB8.2 R10$CBB17/CBB8.2 | length 99.6
  Top Layer w7.9: R2$CBB17/CBB8.1@5298.8,5966.5 5342.9,5966.5 R10$CBB17/CBB8.2@5343.8,5965.6 5344.9,5964.4 5357.1,5964.4 5371.2,5978.5 R8$CBB17/CBB8.2@5391.7,5978.5
$1I34\$1I36\$1N12: R6$CBB17/CBB8.2 R11$CBB17/CBB8.1 R12$CBB17/CBB8.2 | length 102.8
  Top Layer w7.9: R11$CBB17/CBB8.1@5298.8,5886.5 5315.1,5886.5 5331,5870.6 R12$CBB17/CBB8.2@5343.8,5870.6 5363.3,5870.6 5371.2,5878.5 R6$CBB17/CBB8.2@5391.7,5878.5
$1I34\$1I36\$1N13: R7$CBB17/CBB8.2 R10$CBB17/CBB8.1 R11$CBB17/CBB8.2 | length 98.7
  Top Layer w7.9: R11$CBB17/CBB8.2@5298.8,5920.6 5308.3,5920.6 5319.2,5931.5 R10$CBB17/CBB8.1@5343.8,5931.5 5388.8,5931.5 R7$CBB17/CBB8.2@5391.7,5928.5
$1I34\$1I36\$1N14: R4$CBB17/CBB8.2 R13$CBB17/CBB8.1 R14$CBB17/CBB8.2 | length 102.8
  Top Layer w7.9: R13$CBB17/CBB8.1@5298.8,5786.5 5315.1,5786.5 5331,5770.6 R14$CBB17/CBB8.2@5343.8,5770.6 5358.3,5770.6 5366.2,5778.5 R4$CBB17/CBB8.2@5391.7,5778.5
$1I34\$1I36\$1N15: R5$CBB17/CBB8.2 R12$CBB17/CBB8.1 R13$CBB17/CBB8.2 | length 102.8
  Top Layer w7.9: R13$CBB17/CBB8.2@5298.8,5820.6 5313.3,5820.6 5329.2,5836.5 R12$CBB17/CBB8.1@5343.8,5836.5 5360.1,5836.5 5368,5828.5 R5$CBB17/CBB8.2@5391.7,5828.5
$1I34\$1I36\$1N16: R1$CBB17/CBB8.2 R15$CBB17/CBB8.1 R16$CBB17/CBB8.2 | length 143.3
  Top Layer w7.9: R15$CBB17/CBB8.1@5298.8,5691.5 5330.1,5691.5 5343,5678.5 R1$CBB17/CBB8.2@5391.7,5678.5 R16$CBB17/CBB8.2@5391.7,5633.5
$1I34\$1I36\$1N17: R3$CBB17/CBB8.2 R14$CBB17/CBB8.1 R15$CBB17/CBB8.2 | length 100.8
  Top Layer w7.9: R15$CBB17/CBB8.2@5298.8,5725.6 5313.3,5725.6 5324.2,5736.5 R14$CBB17/CBB8.1@5343.8,5736.5 5365.1,5736.5 5372.1,5729.4 5390.8,5729.4 R3$CBB17/CBB8.2@5391.7,5728.5
$1I34\$1I36\DAC_LAD_OUT: R2$CBB17/CBB8.2 R9$CBB17/CBB8.2 R135$CBB17.1 R136$CBB17.2 U2$CBB17.12 | length 1362.5
  Top Layer w7.9: R2$CBB17/CBB8.2@5298.8,6000.6 5328.3,6000.6 v1(5342.1,6014.4) 5351.2,6023.5 R9$CBB17/CBB8.2@5391.7,6023.5 5391.7,6040.1 5394.8,6043.1 5784.5,6043.1 5793.5,6034.1 5793.5,6023.5 5793.7,6023.2 5793.7,6018.9 5834.2,5978.4 R136$CBB17.2@5834.2,5879.4
  Inner4 w7.9: v1(5322.1,6487.5) 5322.1,6034.4 v1(5342.1,6014.4)
  Bottom Layer w7.9: v1(5322.1,6487.5) 5323.8,6489.1 U2$CBB17.12@5505.3,6489.1
$1I35\$1I15\$1N1: R9$CBB18/CBB1.1 U6$CBB18/CBB1.15 | length 333.5
  Top Layer w7.9: R9$CBB18/CBB1.1@6055.7,9192.8 6173,9192.8 6266.2,9099.6 U6$CBB18/CBB1.15@6350.6,9099.6
$1I35\$1I15\$1N2: R8$CBB18/CBB1.1 U6$CBB18/CBB1.1 | length 77.6
  Top Layer w7.9: R8$CBB18/CBB1.1@6055.7,9147.8 6130.8,9147.8 U6$CBB18/CBB1.1@6132.6,9149.6
$1I35\$1I15\$1N3: R7$CBB18/CBB1.1 U6$CBB18/CBB1.2 | length 77.6
  Top Layer w7.9: R7$CBB18/CBB1.1@6055.7,9097.8 6130.8,9097.8 U6$CBB18/CBB1.2@6132.6,9099.6
$1I35\$1I15\$1N4: R6$CBB18/CBB1.1 U6$CBB18/CBB1.3 | length 77.6
  Top Layer w7.9: R6$CBB18/CBB1.1@6055.7,9047.8 6130.8,9047.8 U6$CBB18/CBB1.3@6132.6,9049.6
$1I35\$1I15\$1N5: R5$CBB18/CBB1.1 U6$CBB18/CBB1.4 | length 77.6
  Top Layer w7.9: R5$CBB18/CBB1.1@6055.7,8997.8 6130.8,8997.8 U6$CBB18/CBB1.4@6132.6,8999.6
$1I35\$1I15\$1N6: R4$CBB18/CBB1.1 U6$CBB18/CBB1.5 | length 77.6
  Top Layer w7.9: R4$CBB18/CBB1.1@6055.7,8947.8 6130.8,8947.8 U6$CBB18/CBB1.5@6132.6,8949.6
$1I35\$1I15\$1N7: R3$CBB18/CBB1.1 U6$CBB18/CBB1.6 | length 77.6
  Top Layer w7.9: R3$CBB18/CBB1.1@6055.7,8897.8 6130.8,8897.8 U6$CBB18/CBB1.6@6132.6,8899.6
$1I35\$1I15\$1N8: R1$CBB18/CBB1.1 U6$CBB18/CBB1.7 | length 77.6
  Top Layer w7.9: R1$CBB18/CBB1.1@6055.7,8847.8 6130.8,8847.8 U6$CBB18/CBB1.7@6132.6,8849.6
$1I35\$1I15\$1N11: R2$CBB18/CBB1.1 R8$CBB18/CBB1.2 R10$CBB18/CBB1.2 | length 99.7
  Top Layer w7.9: R2$CBB18/CBB1.1@5928.7,9135.8 5972.8,9135.8 R10$CBB18/CBB1.2@5973.7,9134.9 5974.8,9133.7 5987,9133.7 6001.1,9147.8 R8$CBB18/CBB1.2@6021.7,9147.8
$1I35\$1I15\$1N12: R6$CBB18/CBB1.2 R11$CBB18/CBB1.1 R12$CBB18/CBB1.2 | length 102.9
  Top Layer w7.9: R11$CBB18/CBB1.1@5928.7,9055.8 5945,9055.8 5960.9,9039.9 R12$CBB18/CBB1.2@5973.7,9039.9 5993.2,9039.9 6001.1,9047.8 R6$CBB18/CBB1.2@6021.7,9047.8
$1I35\$1I15\$1N13: R7$CBB18/CBB1.2 R10$CBB18/CBB1.1 R11$CBB18/CBB1.2 | length 98.8
  Top Layer w7.9: R11$CBB18/CBB1.2@5928.7,9089.9 5938.2,9089.9 5949.1,9100.8 R10$CBB18/CBB1.1@5973.7,9100.8 6018.7,9100.8 R7$CBB18/CBB1.2@6021.7,9097.8
$1I35\$1I15\$1N14: R4$CBB18/CBB1.2 R13$CBB18/CBB1.1 R14$CBB18/CBB1.2 | length 102.9
  Top Layer w7.9: R13$CBB18/CBB1.1@5928.7,8955.8 5945,8955.8 5960.9,8939.9 R14$CBB18/CBB1.2@5973.7,8939.9 5988.2,8939.9 5996.1,8947.8 R4$CBB18/CBB1.2@6021.7,8947.8
$1I35\$1I15\$1N15: R5$CBB18/CBB1.2 R12$CBB18/CBB1.1 R13$CBB18/CBB1.2 | length 102.9
  Top Layer w7.9: R13$CBB18/CBB1.2@5928.7,8989.9 5943.2,8989.9 5959.1,9005.8 R12$CBB18/CBB1.1@5973.7,9005.8 5990,9005.8 5998,8997.8 R5$CBB18/CBB1.2@6021.7,8997.8
$1I35\$1I15\$1N16: R1$CBB18/CBB1.2 R15$CBB18/CBB1.1 R16$CBB18/CBB1.2 | length 143.4
  Top Layer w7.9: R15$CBB18/CBB1.1@5928.7,8860.8 5960,8860.8 5973,8847.8 R1$CBB18/CBB1.2@6021.7,8847.8 R16$CBB18/CBB1.2@6021.7,8802.8
$1I35\$1I15\$1N17: R3$CBB18/CBB1.2 R14$CBB18/CBB1.1 R15$CBB18/CBB1.2 | length 100.9
  Top Layer w7.9: R15$CBB18/CBB1.2@5928.7,8894.9 5943.2,8894.9 5954.1,8905.8 R14$CBB18/CBB1.1@5973.7,8905.8 5995,8905.8 6002,8898.7 6020.8,8898.7 R3$CBB18/CBB1.2@6021.7,8897.8
$1I35\$1I15\DAC_LAD_OUT: R2$CBB18/CBB1.2 R9$CBB18/CBB1.2 R16$CBB18.1 R32$CBB18.2 U1$CBB18.3 | length 1609.9
  Top Layer w7.9: R2$CBB18/CBB1.2@5928.7,9169.9 5958.2,9169.9 v1(5972,9183.7) 5981.1,9192.8 R9$CBB18/CBB1.2@6021.7,9192.8 6021.7,9209.4 6024.7,9212.4 6414.4,9212.4 6423.4,9203.4 6423.4,9188.4 6464.1,9147.7 R32$CBB18.2@6464.1,9048.7 ; R32$CBB18.2@6461.9,9048.1 6487.1,9022.9 6487.1,8407.1 6494.9,8399.4 6494.9,8371 6507.1,8358.7 v3(6507.1,8313.7)
  Bottom Layer w7.9: U1$CBB18.3@6353.3,8300.1 6493.5,8300.1 v3(6507.1,8313.7)
$1I35\$1I19\$1N1: R9$CBB18/CBB2.1 U6$CBB18/CBB2.15 | length 333.6
  Top Layer w7.9: R9$CBB18/CBB2.1@6055.7,8740.1 6173,8740.1 6266.2,8646.8 U6$CBB18/CBB2.15@6350.6,8646.8
$1I35\$1I19\$1N2: R8$CBB18/CBB2.1 U6$CBB18/CBB2.1 | length 77.6
  Top Layer w7.9: R8$CBB18/CBB2.1@6055.7,8695.1 6130.8,8695.1 U6$CBB18/CBB2.1@6132.6,8696.8
$1I35\$1I19\$1N3: R7$CBB18/CBB2.1 U6$CBB18/CBB2.2 | length 77.6
  Top Layer w7.9: R7$CBB18/CBB2.1@6055.7,8645.1 6130.8,8645.1 U6$CBB18/CBB2.2@6132.6,8646.8
$1I35\$1I19\$1N4: R6$CBB18/CBB2.1 U6$CBB18/CBB2.3 | length 77.6
  Top Layer w7.9: R6$CBB18/CBB2.1@6055.7,8595.1 6130.8,8595.1 U6$CBB18/CBB2.3@6132.6,8596.8
$1I35\$1I19\$1N5: R5$CBB18/CBB2.1 U6$CBB18/CBB2.4 | length 77.6
  Top Layer w7.9: R5$CBB18/CBB2.1@6055.7,8545.1 6130.8,8545.1 U6$CBB18/CBB2.4@6132.6,8546.8
$1I35\$1I19\$1N6: R4$CBB18/CBB2.1 U6$CBB18/CBB2.5 | length 77.6
  Top Layer w7.9: R4$CBB18/CBB2.1@6055.7,8495.1 6130.8,8495.1 U6$CBB18/CBB2.5@6132.6,8496.8
$1I35\$1I19\$1N7: R3$CBB18/CBB2.1 U6$CBB18/CBB2.6 | length 77.6
  Top Layer w7.9: R3$CBB18/CBB2.1@6055.7,8445.1 6130.8,8445.1 U6$CBB18/CBB2.6@6132.6,8446.8
$1I35\$1I19\$1N8: R1$CBB18/CBB2.1 U6$CBB18/CBB2.7 | length 77.6
  Top Layer w7.9: R1$CBB18/CBB2.1@6055.7,8395.1 6130.8,8395.1 U6$CBB18/CBB2.7@6132.6,8396.8
$1I35\$1I19\$1N11: R2$CBB18/CBB2.1 R8$CBB18/CBB2.2 R10$CBB18/CBB2.2 | length 99.7
  Top Layer w7.9: R2$CBB18/CBB2.1@5928.7,8683 5972.8,8683 R10$CBB18/CBB2.2@5973.7,8682.1 5974.8,8681 5987,8681 6001.1,8695.1 R8$CBB18/CBB2.2@6021.7,8695.1
$1I35\$1I19\$1N12: R6$CBB18/CBB2.2 R11$CBB18/CBB2.1 R12$CBB18/CBB2.2 | length 102.9
  Top Layer w7.9: R11$CBB18/CBB2.1@5928.7,8603 5945,8603 5960.9,8587.1 R12$CBB18/CBB2.2@5973.7,8587.1 5993.2,8587.1 6001.1,8595.1 R6$CBB18/CBB2.2@6021.7,8595.1
$1I35\$1I19\$1N13: R7$CBB18/CBB2.2 R10$CBB18/CBB2.1 R11$CBB18/CBB2.2 | length 98.7
  Top Layer w7.9: R11$CBB18/CBB2.2@5928.7,8637.1 5938.2,8637.1 5949.1,8648 R10$CBB18/CBB2.1@5973.7,8648 6018.7,8648 R7$CBB18/CBB2.2@6021.7,8645.1
$1I35\$1I19\$1N14: R4$CBB18/CBB2.2 R13$CBB18/CBB2.1 R14$CBB18/CBB2.2 | length 102.9
  Top Layer w7.9: R13$CBB18/CBB2.1@5928.7,8503 5945,8503 5960.9,8487.1 R14$CBB18/CBB2.2@5973.7,8487.1 5988.2,8487.1 5996.1,8495.1 R4$CBB18/CBB2.2@6021.7,8495.1
$1I35\$1I19\$1N15: R5$CBB18/CBB2.2 R12$CBB18/CBB2.1 R13$CBB18/CBB2.2 | length 102.8
  Top Layer w7.9: R13$CBB18/CBB2.2@5928.7,8537.1 5943.2,8537.1 5959.1,8553 R12$CBB18/CBB2.1@5973.7,8553 5990,8553 5998,8545.1 R5$CBB18/CBB2.2@6021.7,8545.1
$1I35\$1I19\$1N16: R1$CBB18/CBB2.2 R15$CBB18/CBB2.1 R16$CBB18/CBB2.2 | length 143.3
  Top Layer w7.9: R15$CBB18/CBB2.1@5928.7,8408 5960,8408 5973,8395.1 R1$CBB18/CBB2.2@6021.7,8395.1 R16$CBB18/CBB2.2@6021.7,8350.1
$1I35\$1I19\$1N17: R3$CBB18/CBB2.2 R14$CBB18/CBB2.1 R15$CBB18/CBB2.2 | length 100.8
  Top Layer w7.9: R15$CBB18/CBB2.2@5928.7,8442.1 5943.2,8442.1 5954.1,8453 R14$CBB18/CBB2.1@5973.7,8453 5995,8453 6002,8446 6020.8,8446 R3$CBB18/CBB2.2@6021.7,8445.1
$1I35\$1I19\DAC_LAD_OUT: R2$CBB18/CBB2.2 R9$CBB18/CBB2.2 R48$CBB18.1 R64$CBB18.2 U1$CBB18.5 | length 1250.9
  Top Layer w7.9: R2$CBB18/CBB2.2@5928.7,8717.1 5958.2,8717.1 v1(5972,8731) 5981.1,8740.1 R9$CBB18/CBB2.2@6021.7,8740.1 6021.7,8756.6 6024.7,8759.6 6414.4,8759.6 6423.4,8750.7 6423.4,8735.7 6464.1,8695 R64$CBB18.2@6464.1,8596 ; R64$CBB18.2@6461.9,8595.4 6461.9,8414.1 6482,8394 6482,8215.2 v3(6497.1,8200.1)
  Bottom Layer w7.9: U1$CBB18.5@6353.3,8200.1 v3(6497.1,8200.1)
$1I35\$1I21\$1N1: R9$CBB18/CBB3.1 U6$CBB18/CBB3.15 | length 333.5
  Top Layer w7.9: R9$CBB18/CBB3.1@6055.7,8287.3 6173,8287.3 6266.2,8194.1 U6$CBB18/CBB3.15@6350.6,8194.1
$1I35\$1I21\$1N2: R8$CBB18/CBB3.1 U6$CBB18/CBB3.1 | length 77.6
  Top Layer w7.9: R8$CBB18/CBB3.1@6055.7,8242.3 6130.8,8242.3 U6$CBB18/CBB3.1@6132.6,8244.1
$1I35\$1I21\$1N3: R7$CBB18/CBB3.1 U6$CBB18/CBB3.2 | length 77.6
  Top Layer w7.9: R7$CBB18/CBB3.1@6055.7,8192.3 6130.8,8192.3 U6$CBB18/CBB3.2@6132.6,8194.1
$1I35\$1I21\$1N4: R6$CBB18/CBB3.1 U6$CBB18/CBB3.3 | length 77.6
  Top Layer w7.9: R6$CBB18/CBB3.1@6055.7,8142.3 6130.8,8142.3 U6$CBB18/CBB3.3@6132.6,8144.1
$1I35\$1I21\$1N5: R5$CBB18/CBB3.1 U6$CBB18/CBB3.4 | length 77.6
  Top Layer w7.9: R5$CBB18/CBB3.1@6055.7,8092.3 6130.8,8092.3 U6$CBB18/CBB3.4@6132.6,8094.1
$1I35\$1I21\$1N6: R4$CBB18/CBB3.1 U6$CBB18/CBB3.5 | length 77.6
  Top Layer w7.9: R4$CBB18/CBB3.1@6055.7,8042.3 6130.8,8042.3 U6$CBB18/CBB3.5@6132.6,8044.1
$1I35\$1I21\$1N7: R3$CBB18/CBB3.1 U6$CBB18/CBB3.6 | length 77.6
  Top Layer w7.9: R3$CBB18/CBB3.1@6055.7,7992.3 6130.8,7992.3 U6$CBB18/CBB3.6@6132.6,7994.1
$1I35\$1I21\$1N8: R1$CBB18/CBB3.1 U6$CBB18/CBB3.7 | length 77.6
  Top Layer w7.9: R1$CBB18/CBB3.1@6055.7,7942.3 6130.8,7942.3 U6$CBB18/CBB3.7@6132.6,7944.1
$1I35\$1I21\$1N11: R2$CBB18/CBB3.1 R8$CBB18/CBB3.2 R10$CBB18/CBB3.2 | length 99.7
  Top Layer w7.9: R2$CBB18/CBB3.1@5928.7,8230.3 5972.8,8230.3 R10$CBB18/CBB3.2@5973.7,8229.4 5974.8,8228.2 5987,8228.2 6001.1,8242.3 R8$CBB18/CBB3.2@6021.7,8242.3
$1I35\$1I21\$1N12: R6$CBB18/CBB3.2 R11$CBB18/CBB3.1 R12$CBB18/CBB3.2 | length 102.9
  Top Layer w7.9: R11$CBB18/CBB3.1@5928.7,8150.3 5945,8150.3 5960.9,8134.4 R12$CBB18/CBB3.2@5973.7,8134.4 5993.2,8134.4 6001.1,8142.3 R6$CBB18/CBB3.2@6021.7,8142.3
$1I35\$1I21\$1N13: R7$CBB18/CBB3.2 R10$CBB18/CBB3.1 R11$CBB18/CBB3.2 | length 98.8
  Top Layer w7.9: R11$CBB18/CBB3.2@5928.7,8184.4 5938.2,8184.4 5949.1,8195.3 R10$CBB18/CBB3.1@5973.7,8195.3 6018.7,8195.3 R7$CBB18/CBB3.2@6021.7,8192.3
$1I35\$1I21\$1N14: R4$CBB18/CBB3.2 R13$CBB18/CBB3.1 R14$CBB18/CBB3.2 | length 102.9
  Top Layer w7.9: R13$CBB18/CBB3.1@5928.7,8050.3 5945,8050.3 5960.9,8034.4 R14$CBB18/CBB3.2@5973.7,8034.4 5988.2,8034.4 5996.1,8042.3 R4$CBB18/CBB3.2@6021.7,8042.3
$1I35\$1I21\$1N15: R5$CBB18/CBB3.2 R12$CBB18/CBB3.1 R13$CBB18/CBB3.2 | length 102.9
  Top Layer w7.9: R13$CBB18/CBB3.2@5928.7,8084.4 5943.2,8084.4 5959.1,8100.3 R12$CBB18/CBB3.1@5973.7,8100.3 5990,8100.3 5998,8092.3 R5$CBB18/CBB3.2@6021.7,8092.3
$1I35\$1I21\$1N16: R1$CBB18/CBB3.2 R15$CBB18/CBB3.1 R16$CBB18/CBB3.2 | length 143.4
  Top Layer w7.9: R15$CBB18/CBB3.1@5928.7,7955.3 5960,7955.3 5973,7942.3 R1$CBB18/CBB3.2@6021.7,7942.3 R16$CBB18/CBB3.2@6021.7,7897.3
$1I35\$1I21\$1N17: R3$CBB18/CBB3.2 R14$CBB18/CBB3.1 R15$CBB18/CBB3.2 | length 100.9
  Top Layer w7.9: R15$CBB18/CBB3.2@5928.7,7989.4 5943.2,7989.4 5954.1,8000.3 R14$CBB18/CBB3.1@5973.7,8000.3 5995,8000.3 6002,7993.2 6020.8,7993.2 R3$CBB18/CBB3.2@6021.7,7992.3
$1I35\$1I21\DAC_LAD_OUT: R2$CBB18/CBB3.2 R9$CBB18/CBB3.2 R80$CBB18.1 R96$CBB18.2 U1$CBB18.10 | length 906.3
  Top Layer w7.9: R2$CBB18/CBB3.2@5928.7,8264.4 5960.3,8264.4 v1(5974.2,8278.2) 5983.3,8287.3 R9$CBB18/CBB3.2@6021.7,8287.3 6021.7,8303.9 6024.7,8306.9 6414.4,8306.9 6423.4,8297.9 6423.4,8282.9 6464.1,8242.2 R96$CBB18.2@6464.1,8143.2
  Bottom Layer w7.9: v1(5974.2,8278.2) 5974.2,8251.6 6025.7,8200.1 U1$CBB18.10@6135.3,8200.1
$1I35\$1I23\$1N1: R9$CBB18/CBB4.1 U6$CBB18/CBB4.15 | length 333.6
  Top Layer w7.9: R9$CBB18/CBB4.1@6055.7,7834.6 6173,7834.6 6266.2,7741.3 U6$CBB18/CBB4.15@6350.6,7741.3
$1I35\$1I23\$1N2: R8$CBB18/CBB4.1 U6$CBB18/CBB4.1 | length 77.6
  Top Layer w7.9: R8$CBB18/CBB4.1@6055.7,7789.6 6130.8,7789.6 U6$CBB18/CBB4.1@6132.6,7791.3
$1I35\$1I23\$1N3: R7$CBB18/CBB4.1 U6$CBB18/CBB4.2 | length 77.6
  Top Layer w7.9: R7$CBB18/CBB4.1@6055.7,7739.6 6130.8,7739.6 U6$CBB18/CBB4.2@6132.6,7741.3
$1I35\$1I23\$1N4: R6$CBB18/CBB4.1 U6$CBB18/CBB4.3 | length 77.6
  Top Layer w7.9: R6$CBB18/CBB4.1@6055.7,7689.6 6130.8,7689.6 U6$CBB18/CBB4.3@6132.6,7691.3
$1I35\$1I23\$1N5: R5$CBB18/CBB4.1 U6$CBB18/CBB4.4 | length 77.6
  Top Layer w7.9: R5$CBB18/CBB4.1@6055.7,7639.6 6130.8,7639.6 U6$CBB18/CBB4.4@6132.6,7641.3
$1I35\$1I23\$1N6: R4$CBB18/CBB4.1 U6$CBB18/CBB4.5 | length 77.6
  Top Layer w7.9: R4$CBB18/CBB4.1@6055.7,7589.6 6130.8,7589.6 U6$CBB18/CBB4.5@6132.6,7591.3
$1I35\$1I23\$1N7: R3$CBB18/CBB4.1 U6$CBB18/CBB4.6 | length 77.6
  Top Layer w7.9: R3$CBB18/CBB4.1@6055.7,7539.6 6130.8,7539.6 U6$CBB18/CBB4.6@6132.6,7541.3
$1I35\$1I23\$1N8: R1$CBB18/CBB4.1 U6$CBB18/CBB4.7 | length 77.6
  Top Layer w7.9: R1$CBB18/CBB4.1@6055.7,7489.6 6130.8,7489.6 U6$CBB18/CBB4.7@6132.6,7491.3
$1I35\$1I23\$1N11: R2$CBB18/CBB4.1 R8$CBB18/CBB4.2 R10$CBB18/CBB4.2 | length 99.7
  Top Layer w7.9: R2$CBB18/CBB4.1@5928.7,7777.5 5972.8,7777.5 R10$CBB18/CBB4.2@5973.7,7776.6 5974.8,7775.5 5987,7775.5 6001.1,7789.6 R8$CBB18/CBB4.2@6021.7,7789.6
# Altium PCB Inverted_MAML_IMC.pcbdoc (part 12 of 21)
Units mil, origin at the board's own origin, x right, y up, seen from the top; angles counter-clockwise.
Board outline 7677.1 x 6771.6 mil, 6 copper layers (Top Layer, Inner1, Inner2, Inner3, Inner4, Bottom Layer), stack 60.7 mil thick; 2732 components, 1531 nets, 7765 pads, 3701 vias.

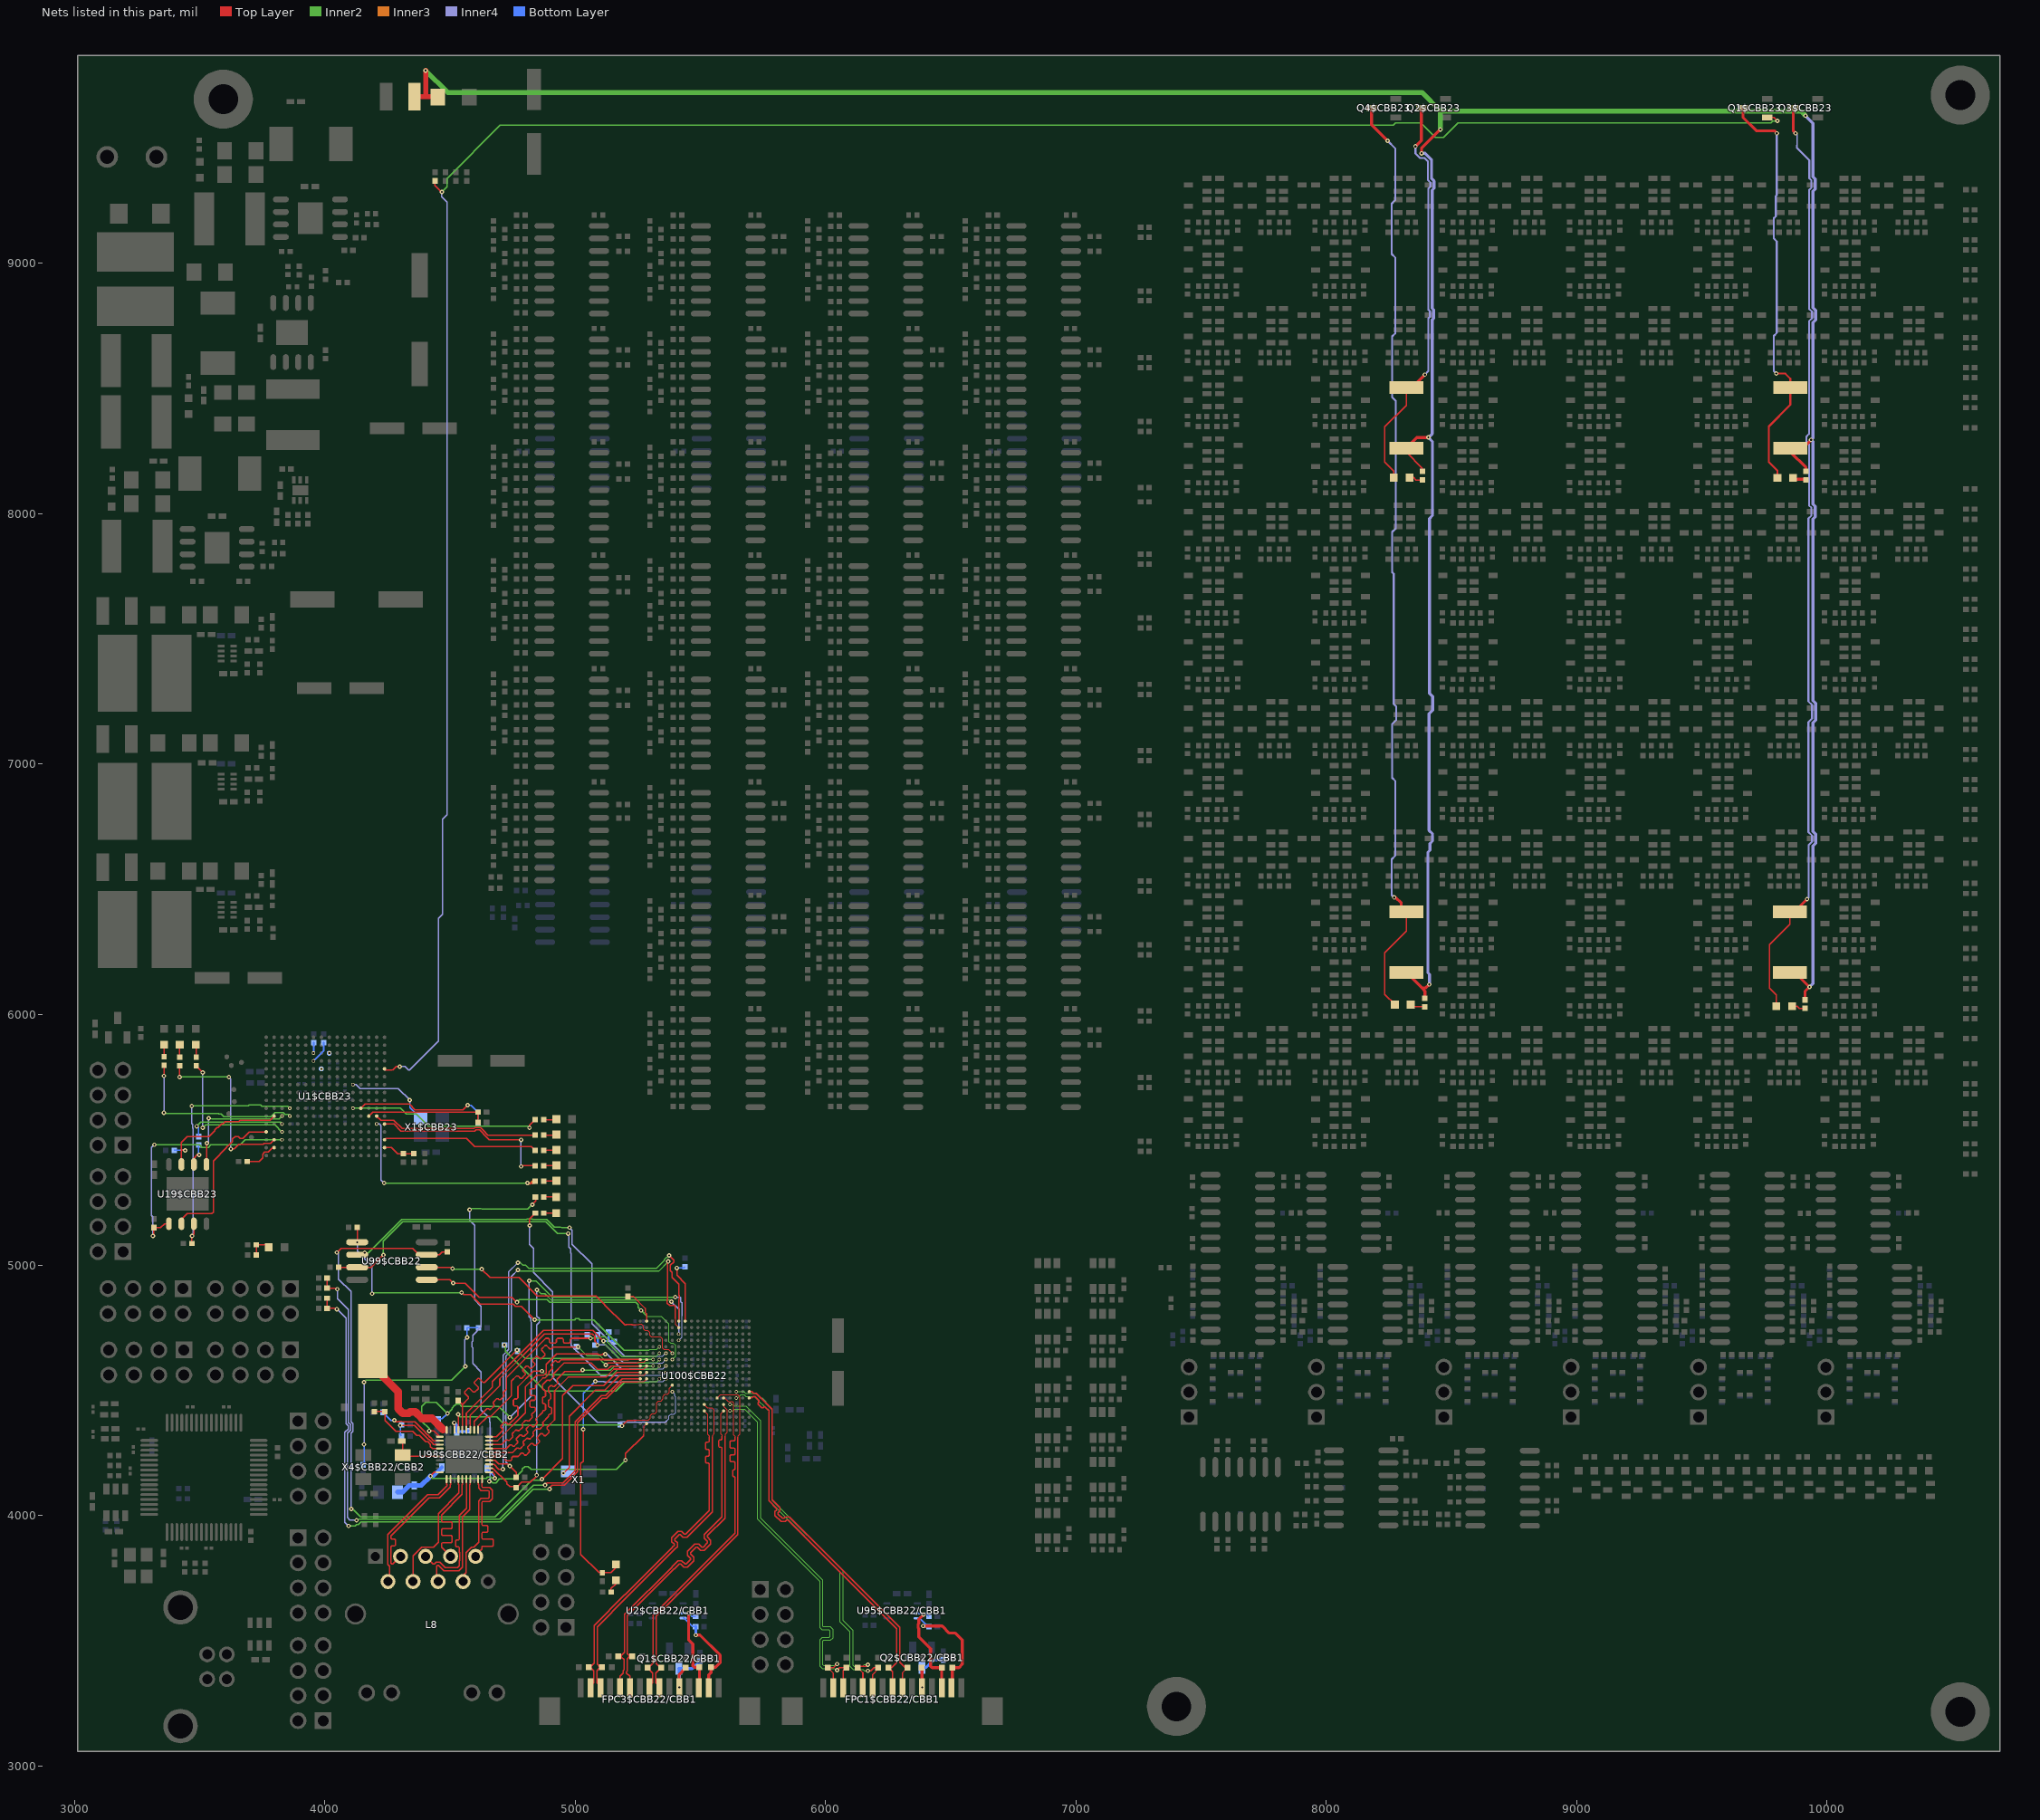
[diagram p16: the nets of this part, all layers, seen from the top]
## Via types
v1: diameter 17.7, hole 7.9, Top Layer to Bottom Layer, 3369 vias
v2: diameter 13.8, hole 7.9, Top Layer to Bottom Layer, 287 vias
v3: diameter 23.6, hole 11.8, Top Layer to Bottom Layer, 45 vias

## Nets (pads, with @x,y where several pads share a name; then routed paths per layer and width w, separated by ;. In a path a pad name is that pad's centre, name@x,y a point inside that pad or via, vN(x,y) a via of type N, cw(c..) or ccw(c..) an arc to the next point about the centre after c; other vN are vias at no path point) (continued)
$4I2\$1I143359\AVDD33: C126$CBB22/CBB2.1 C132$CBB22/CBB2.1 C134$CBB22/CBB2.1 L13.2 U98$CBB22/CBB2.11 U98$CBB22/CBB2.40 | length 618.5
  Top Layer w4.7: v1(4422.4,4156.5) 4438.2,4172.3 U98$CBB22/CBB2.40@4459.5,4172.3 ; U98$CBB22/CBB2.11@4656.3,4172.3 4669.6,4172.3 4679.1,4162.8 v1(4679.1,4148)
  Inner2 w4.7: v1(4422.4,4156.5) 4430.9,4148 4646.1,4148 4650.6,4152.5 4664,4152.5 4668.5,4148 v1(4679.1,4148)
  Bottom Layer w4.7: C126$CBB22/CBB2.1@4647.9,4186.7 4679.1,4155.5 v1(4679.1,4148)
  Bottom Layer w15.7: v1(4422.4,4156.5) 4432.6,4156.5 C132$CBB22/CBB2.1@4467.9,4191.7
  Bottom Layer w19.7: L13.2@4290.9,4093.2 4310.9,4093.2 4337.4,4119.6 C134$CBB22/CBB2.1@4357.9,4119.6 4385.6,4119.6 v1(4422.4,4156.5)
$4I2\$1I143359\DVDD_RG: C133$CBB22/CBB2.1 R174$CBB22/CBB2.1 U98$CBB22/CBB2.28 | length 114.5
  Top Layer w4.7: v1(4517.5,4369.7) 4517.5,4342.6 U98$CBB22/CBB2.28@4518.5,4341.6
  Bottom Layer w11.8: v1(4517.5,4369.7) 4527.9,4359.3 C133$CBB22/CBB2.1@4527.9,4334.6 4569.4,4334.6 R174$CBB22/CBB2.1@4573,4338.2
$4I2\$1I143359\LED0: R164$CBB22/CBB2.1 U98$CBB22/CBB2.32 | length 276.2
  Top Layer w4.7: v1(4277.8,4379.4) 4283.9,4373.3 4293,4373.3 4295.2,4375.5 4308.6,4375.5 4310.8,4373.3 4360.2,4373.3 4401.8,4331.7 4401.8,4330.5 4411.3,4321 4412.5,4321 4420.9,4312.6 4421.1,4312.6 4435.5,4298.3 U98$CBB22/CBB2.32@4459.5,4298.3
  Bottom Layer w4.7: R164$CBB22/CBB2.1@4232.7,4411.5 4264.8,4379.4 v1(4277.8,4379.4)
$4I2\$1I143359\LED1: R165$CBB22/CBB2.2 R166$CBB22/CBB2.2 U98$CBB22/CBB2.33 | length 235.1
  Top Layer w4.7: v1(4301.9,4359.3) 4358.1,4359.3 4414.5,4302.9 4417.1,4302.9 4432.3,4287.7 4432.3,4285.2 4434.9,4282.6 U98$CBB22/CBB2.33@4459.5,4282.6
  Bottom Layer w4.7: v1(4301.9,4359.3) 4301.9,4322.2 R166$CBB22/CBB2.2@4307,4317.1
$4I2\$1I143359\LED2: R167$CBB22/CBB2.2 R168$CBB22/CBB2.2 U98$CBB22/CBB2.34 | length 348.6
  Top Layer w4.7: R168$CBB22/CBB2.2@4198.3,4414.5 R167$CBB22/CBB2.2@4240.5,4414.5 4240.5,4378.6 4283.9,4335.2 4352.1,4335.2 4368.2,4319.1 4378.2,4319.1 4404.2,4293.2 4413.1,4293.2 4422.6,4283.7 4422.6,4274.8 4430.6,4266.8 U98$CBB22/CBB2.34@4459.5,4266.8
$4I2\$1I143359\MDI0_N: L8.P3 U98$CBB22/CBB2.2 | length 540.3
  Top Layer w4.7: L8.P3@4302.9,3836 4272.2,3805.3 4267.5,3805.3 4264.1,3808.7 4264.1,3873.9 4267.5,3877.3 4278.5,3877.3 4281.9,3880.6 4281.9,3901.5 4278.5,3904.8 4267.5,3904.8 4264.1,3908.2 4264.1,3917.9 4416.4,4070.2 4458.6,4070.2 4501.2,4112.8 4501.2,4122.7 4502.8,4124.3 U98$CBB22/CBB2.2@4502.8,4144.8
$4I2\$1I143359\MDI0_P: L8.P2 U98$CBB22/CBB2.1 | length 537.7
  Top Layer w4.7: L8.P2@4252.9,3736 4258.6,3741.7 4258.6,3796.4 4251.5,3803.4 4251.5,3923.1 4411.2,4082.8 4453.3,4082.8 4488.6,4118 4488.6,4122.7 4487,4124.3 U98$CBB22/CBB2.1@4487,4144.8
$4I2\$1I143359\MDI1_N: L8.P7 U98$CBB22/CBB2.5 | length 511.3
  Top Layer w4.7: L8.P7@4502.9,3836 4466.6,3872.3 4466.6,3888.2 4469.9,3891.6 4505.4,3891.6 4508.7,3894.9 4508.7,3915.8 4505.4,3919.1 4469.9,3919.1 4466.6,3922.5 4466.6,3943.4 4469.9,3946.7 4505.4,3946.7 4508.7,3950 4508.7,3970.9 4505.4,3974.3 4469.9,3974.3 4466.6,3977.6 4466.6,4001.9 4548.4,4083.7 4548.4,4122.8 4550,4124.3 U98$CBB22/CBB2.5@4550,4144.8
$4I2\$1I143359\MDI1_P: L8.P4 U98$CBB22/CBB2.4 | length 512.4
  Top Layer w4.7: L8.P4@4352.9,3736 4352.9,3838.8 4387.4,3873.4 4433.9,3873.4 4454,3893.5 4454,4007.4 4535.8,4089.2 4535.8,4122.8 4534.3,4124.3 U98$CBB22/CBB2.4@4534.3,4144.8
$4I2\$1I143359\MDI2_N: L8.P6 U98$CBB22/CBB2.7 | length 546.3
  Top Layer w4.7: L8.P6@4452.9,3736 4447.2,3741.7 4447.2,3796.4 4450.5,3799.8 4455.3,3799.8 4476,3779 4536,3779 4550.9,3793.9 4550.9,3993.9 4579.9,4022.9 4579.9,4122.8 4581.5,4124.3 U98$CBB22/CBB2.7@4581.5,4144.8
$4I2\$1I143359\MDI2_P: L8.P5 U98$CBB22/CBB2.6 | length 546
  Top Layer w4.7: L8.P5@4402.9,3836 4433.6,3805.3 4438.3,3805.3 4445.3,3812.4 4460.5,3812.4 4481.2,3791.6 4530.8,3791.6 4538.3,3799.1 4538.3,3818.6 4540.2,3820.5 4540.2,3851.5 4538.3,3853.4 4538.3,3871.3 4535,3874.7 4526.1,3874.7 4522.8,3878 4522.8,3898.9 4526.1,3902.2 4535,3902.2 4538.3,3905.6 4538.3,3999.1 4567.3,4028.1 4567.3,4122.8 4565.8,4124.3 U98$CBB22/CBB2.6@4565.8,4144.8
$4I2\$1I143359\MDI3_N: L8.P9 U98$CBB22/CBB2.10 | length 512.9
  Top Layer w4.7: L8.P9@4602.9,3836 4602.9,3840.7 4627.2,3865 4627.2,3873.8 4630.5,3877.2 4670,3877.2 4673.4,3880.5 4673.4,3901.4 4670,3904.7 4630.5,3904.7 4627.2,3908.1 4627.2,3928.9 4630.5,3932.3 4648,3932.3 4651.3,3935.6 4651.3,3956.5 4648,3959.8 4630.5,3959.8 4627.2,3963.2 4627.2,4052 4630.5,4055.4 4658.9,4055.4 4669.6,4066.1 4669.6,4101.4 4658.9,4112.1 4630.5,4112.1 4627.2,4115.4 4627.2,4122.7 4628.8,4124.3 U98$CBB22/CBB2.10@4628.8,4144.8
$4I2\$1I143359\MDI3_P: L8.P8 U98$CBB22/CBB2.9 | length 511.3
  Top Layer w4.7: L8.P8@4552.9,3736 4549.2,3739.7 4549.2,3754.9 4565.5,3771.2 4565.5,3851.5 4587.4,3873.4 4595.7,3873.4 4614.6,3892.3 4614.6,4057.3 4625.3,4068 4653.7,4068 4657,4071.3 4657,4096.1 4653.7,4099.5 4625.3,4099.5 4614.6,4110.2 4614.6,4122.7 4613,4124.3 U98$CBB22/CBB2.9@4613,4144.8
$4I2\$1I143359\REG-OUT: L12.1 U98$CBB22/CBB2.30 | length 542.9
  Top Layer w7.9: 4474.2,4341.6 U98$CBB22/CBB2.30@4487,4341.6
  Top Layer w31.5: L12.1@4192.2,4696.3 4192.2,4595.5 4293.9,4493.8 4293.9,4425.8 4311.8,4408 4336.3,4408 4341.8,4413.5 4362.2,4413.5 4388.3,4387.4 4428.4,4387.4 4472.6,4343.2
$4I2\$1I143359\XTAL-IN: C55$CBB22/CBB2.1 U98$CBB22/CBB2.36 X4$CBB22/CBB2.3 | length 207.4
  Top Layer w4.7: C55$CBB22/CBB2.1@4307.8,4296.4 4312.4,4291.8 X4$CBB22/CBB2.3@4312.4,4239.9 4317,4235.3 U98$CBB22/CBB2.36@4459.5,4235.3
$4I2\$1I160024\CAM_A_EN_OD: D15.2 FPC3$CBB22/CBB1.11 Q1$CBB22/CBB1.3 R74$CBB22/CBB1.2 | length 264.4
  Top Layer w11.8: FPC3$CBB22/CBB1.11@5415.9,3311.3 5415.9,3365.4 D15.2@5442.4,3391.9
  Bottom Layer w11.8: v1(5416.3,3313.2) 5416.3,3386.3 Q1$CBB22/CBB1.3@5414.3,3388.3 5468.3,3388.3 R74$CBB22/CBB1.2@5498.6,3418.6
$4I2\$1I160024\CAM_B_EN_OD: D18.2 FPC1$CBB22/CBB1.11 Q2$CBB22/CBB1.3 R84$CBB22/CBB1.2 | length 257.2
  Top Layer w11.8: D18.2@6384.1,3391.9 6385.8,3390.2 FPC1$CBB22/CBB1.11@6385.8,3311.3
  Bottom Layer w11.8: v1(6386.1,3313.2) Q2$CBB22/CBB1.3@6386.1,3392.3 6400.9,3392.3 6431.3,3422.6 R84$CBB22/CBB1.2@6470.4,3422.6
$4I2\$1I160024\I2C_CAMA_SCL: D14.2 FPC3$CBB22/CBB1.13 R128$CBB22/CBB1.1 U2$CBB22/CBB1.3 | length 394.3
  Top Layer w11.8: v1(5453.2,3609.6) 5453.2,3503.2 5470.7,3485.7 5470.5,3485.6 5470.5,3399.5 5476.1,3393.9 D14.2@5496.6,3393.9 5496.6,3313.2 FPC3$CBB22/CBB1.13@5494.7,3311.3
  Inner2 w11.8: v1(5453.2,3609.6) 5458.5,3604.3 5458.5,3602.3
  Bottom Layer w4.7: U2$CBB22/CBB1.3@5431.4,3609.6 v1(5453.2,3609.6) 5466.6,3596.2 R128$CBB22/CBB1.1@5481.4,3596.2
$4I2\$1I160024\I2C_CAMA_SDA: D13.2 FPC3$CBB22/CBB1.14 R97$CBB22/CBB1.1 U2$CBB22/CBB1.4 | length 387.9
  Top Layer w11.8: v1(5482.6,3522) 5498.6,3522 5578.9,3441.7 5578.9,3411.6 5561.3,3393.9 D13.2@5542.8,3393.9 5542.8,3371.4 5534.1,3362.7 FPC3$CBB22/CBB1.14@5534.1,3311.3
  Bottom Layer w4.7: U2$CBB22/CBB1.4@5431.4,3589.9 5434.7,3589.9 5468.6,3556 R97$CBB22/CBB1.1@5481.4,3556
  Bottom Layer w11.8: R97$CBB22/CBB1.1@5481.4,3556 5482.6,3554.9 v1(5482.6,3522)
$4I2\$1I160024\I2C_CAMB_SCL: D17.2 FPC1$CBB22/CBB1.13 R129$CBB22/CBB1.1 U95$CBB22/CBB1.3 | length 414.9
  Top Layer w11.8: v1(6392.1,3604.3) 6373.3,3585.5 6373.3,3569.3 6370.4,3566.3 6370.4,3550 6373.3,3547 6373.3,3514.7 6420.2,3467.8 6420.2,3397.5 6425.9,3391.9 D17.2@6464.4,3391.9 6464.5,3391.8 FPC1$CBB22/CBB1.13@6464.5,3311.3
  Bottom Layer w4.7: U95$CBB22/CBB1.3@6367.1,3609 6400.6,3609 R129$CBB22/CBB1.1@6413.2,3596.3
$4I2\$1I160024\I2C_CAMB_SDA: D16.2 FPC1$CBB22/CBB1.14 R130$CBB22/CBB1.1 U95$CBB22/CBB1.4 | length 481.6
  Top Layer w11.8: v1(6390.1,3558.1) 6466.4,3558.1 6494.5,3530 6518.6,3530 6546.7,3501.9 6546.7,3405.6 6533.1,3391.9 D16.2@6506.6,3391.9 6506.6,3314 FPC1$CBB22/CBB1.14@6503.9,3311.3
  Bottom Layer w4.7: U95$CBB22/CBB1.4@6367.1,3589.3 6377,3589.3 R130$CBB22/CBB1.1@6408.1,3558.1
  Bottom Layer w11.8: v1(6390.1,3558.1) 6408.1,3558.1 6411.2,3558.1 R130$CBB22/CBB1.1@6413.2,3556.1
$4I2\$1N148787: R183$CBB22.2 U100$CBB22.V11 | length 260.2
  Top Layer w4.7: v1(5406.5,4988.1) 5406.5,4958.8 5439.5,4925.8 U100$CBB22.V11@5439.5,4775.7
  Bottom Layer w5.5: v1(5406.5,4988.1) 5434.2,4988.1 5438.4,4992.3 R183$CBB22.2@5438.4,4992.8
$4I2\$1N159653: LED5.2 R260$CBB22.1 | length 54.7
  Top Layer w4.7: R260$CBB22.1@5144.1,3693.9 5144.1,3707.6 5163.2,3726.7 LED5.2@5163.2,3740.7
$4I2\$1N192738: LED9.2 R95$CBB22.1 | length 49.8
  Top Layer w4.7: R95$CBB22.1@4875.3,5207.2 LED9.2@4925.1,5207.2
$4I2\$1N240613: R78.2 U100$CBB22.V17 | length 141.7
  Top Layer w5.5: R78.2@5211.5,4874.3 5232.6,4874.3 5280.3,4826.6 5280.3,4810.5 5285.9,4804.8 U100$CBB22.V17@5285.9,4775.7
$4I2\$1N253907: LED1$CBB22.2 R1$CBB22.1 | length 49.8
  Top Layer w4.7: R1$CBB22.1@4875.3,5271.4 LED1$CBB22.2@4925.1,5271.4
$4I2\CAM2_CLK_N: D2.2 FPC3$CBB22/CBB1.8 U100$CBB22.F5 | length 1421.2
  Top Layer w3.9: U100$CBB22.F5@5593,4468.6 5598.1,4468.6 5611.1,4455.7 5613.2,4455.7 5613.3,4455.8 5623.9,4455.8 5624.1,4455.7 5627.1,4455.7 5631.8,4451 5631.8,4397.5 5631.4,4397.2 5631.4,4386.6 5631.8,4386.2 5631.8,4323.1 5638.5,4316.5 5638.5,4311.7
  Top Layer w4.7: FPC3$CBB22/CBB1.8@5297.9,3313.3 5297.9,3318.5 5310.6,3331.3 5310.6,3370.3 D2.2@5289.4,3391.5 5293.8,3391.5 5311.5,3409.2 5311.5,3419.2 5311.9,3419.6 5311.9,3602.3 5638.5,3928.9 5638.5,4151.9 5635.2,4155.2 5632.5,4155.2 5629.1,4158.5 5629.1,4179.4 5632.5,4182.8 5635.2,4182.8 5638.5,4186.1 5638.5,4211.2 5635.2,4214.5 5622.4,4214.5 5619.1,4217.9 5619.1,4238.7 5622.4,4242.1 5635.2,4242.1 5638.5,4245.4 5638.5,4266.3 5635.2,4269.6 5622.4,4269.6 5619.1,4273 5619.1,4293.9 5622.4,4297.2 5635.2,4297.2 5638.5,4300.5 5638.5,4311.7
$4I2\CAM2_CLK_P: D1.2 FPC3$CBB22/CBB1.9 U100$CBB22.F6 | length 1422.4
  Top Layer w3.9: U100$CBB22.F6@5567.4,4468.6 5580.2,4481.4 5649.5,4481.4 5657,4473.9 5657,4323.1 5650.3,4316.5 5650.3,4311.7
  Top Layer w4.7: FPC3$CBB22/CBB1.9@5337.2,3313.3 5337.2,3318.5 5323.2,3332.6 5323.2,3370.3 D1.2@5344.4,3391.5 5340,3391.5 5323.7,3407.8 5323.7,3597.4 5650.3,3924 5650.3,4311.7
$4I2\CAM2_D0_N: D5.2 FPC3$CBB22/CBB1.2 U100$CBB22.D8 | length 1413.5
  Top Layer w3.9: U100$CBB22.D8@5516.3,4417.4 5529.1,4404.6 5529.1,4386.6 5528.7,4386.2 5528.7,4325.2 5535.8,4318.1 5535.8,4313.4
  Top Layer w4.7: D5.2@5054.5,3393.5 D5.2@5062.9,3393.5 ; FPC3$CBB22/CBB1.2@5061.7,3313.3 5061.7,3318.5 5074.7,3331.6 5074.7,3379.7 5062.9,3391.5 D5.2@5062.9,3393.5 ; 5198.7,3682.5 5198.5,3682.2 ; 5535.8,4313.4 5535.8,4294.8 5532.4,4291.4 5524,4291.4 5520.7,4288.1 5520.7,4267.2 5524,4263.9 5532.4,4263.9 5535.8,4260.5 5535.8,4239.6 5532.4,4236.3 5524,4236.3 5520.7,4233 5520.7,4212.1 5524,4208.7 5532.4,4208.7 5535.8,4205.4 5535.8,4019 5441.7,3924.9 5436.4,3924.9 5426.1,3935.2 5410.9,3935.2 5386,3910.2 5386,3895.1 5396.3,3884.8 5396.3,3880.1 5390.1,3873.8 5390.1,3873.3 5199,3682.2 5198.5,3682.2 ; D5.2@5062.9,3393.5 5062.9,3395.5 5076.4,3409 5076.4,3560.2 5198.5,3682.2
$4I2\CAM2_D0_P: D6.2 FPC3$CBB22/CBB1.3 U100$CBB22.E8 | length 1412.8
  Top Layer w3.9: U100$CBB22.E8@5516.3,4443 5529.1,4430.2 5547.1,4430.2 5554.6,4422.7 5554.6,4325.2 5547.6,4318.1 5547.6,4313.4
  Top Layer w4.7: FPC3$CBB22/CBB1.3@5101,3313.3 5101,3318.5 5087.3,3332.3 5087.3,3379.7 5100.8,3393.2 D6.2@5100.8,3393.5 ; D6.2@5107.5,3393.5 D6.2@5100.8,3393.5 ; 5547.6,4313.4 5547.6,4014.1 5446.3,3912.8 5446.3,3912.3 5431.2,3912.3 5420.9,3922.6 5416.2,3922.6 5398.6,3905 5398.6,3900.3 5408.9,3890 5408.9,3874.8 5399,3864.9 5398.5,3864.9 5207.4,3673.8 5207.4,3673.3 5089,3554.9 5089,3405.6 5100.8,3393.8 D6.2@5100.8,3393.5
$4I2\CAM2_D1_N: D3.2 FPC3$CBB22/CBB1.5 U100$CBB22.D5 | length 1418.5
  Top Layer w3.9: 5586.9,4316.1 5586.9,4320.9 5580.6,4327.2 5580.6,4386.2 5580.2,4386.6 5580.2,4404.6 U100$CBB22.D5@5593,4417.4
  Top Layer w4.7: D3.2@5173,3437.7 5185,3437.7 ; FPC3$CBB22/CBB1.5@5179.8,3313.3 5179.8,3357.4 5193.1,3370.8 5193.1,3380.7 5195.2,3382.7 5195.2,3423.9 5185,3434.1 5185,3437.7 ; 5586.9,4316.1 5586.9,4304 5583.6,4300.7 5576.3,4300.7 5572.9,4297.3 5572.9,4276.5 5576.3,4273.1 5583.6,4273.1 5586.9,4269.8 5586.9,3993.8 5516.6,3923.5 5516.1,3923.5 5516.1,3908.4 5529.1,3895.4 5529.1,3890.7 5511.5,3873.1 5506.8,3873.1 5493.8,3886.1 5478.7,3886.1 5448.5,3856 5448.5,3840.8 5461.5,3827.8 5461.5,3823.1 5443.9,3805.5 5439.2,3805.5 5426.2,3818.5 5411.1,3818.5 5387.1,3794.5 5387.1,3794 5197.4,3604.3 5197.4,3453.7 5185,3441.3 5185,3437.7
$4I2\CAM2_D1_P: D4.2 FPC3$CBB22/CBB1.6 U100$CBB22.E5 | length 1418.1
  Top Layer w3.9: U100$CBB22.E5@5593,4443 5593,4435 5605.8,4422.2 5605.8,4330 5598.7,4322.9 5598.7,4316.1
  Top Layer w4.7: D4.2@5216.5,3436.7 5216.5,3434.7 5207.8,3425.9 5207.8,3377.5 5205.7,3375.5 5205.7,3370.8 5219.1,3357.4 FPC3$CBB22/CBB1.6@5219.1,3313.3 ; D4.2@5228,3437.7 5219.5,3437.7 5209.3,3448 5209.3,3599.4 5395.4,3785.6 5396,3785.6 5416.3,3805.9 5421,3805.9 5434,3792.9 5449.2,3792.9 5474.1,3817.9 5474.1,3833 5461.1,3846 5461.1,3850.7 5483.9,3873.5 5488.6,3873.5 5501.6,3860.5 5516.7,3860.5 5541.7,3885.4 5541.7,3900.6 5528.7,3913.6 5528.7,3918.9 5598.7,3988.9 5598.7,4316.1
$4I2\CAM3_CLK_N: D7.2 FPC1$CBB22/CBB1.8 U100$CBB22.F1 | length 1495.9
  Top Layer w4.7: U100$CBB22.F1@5695.4,4468.6 5706.4,4468.6 5712.9,4475.1 5717.6,4475.1 5734.7,4458.1 5734.7,4453.4 5730.6,4449.3 5730.6,4444.6 5745.3,4429.8 5750.1,4429.8 5754.1,4433.9 5758.9,4433.9 5773.7,4419.1 5773.7,4058.1 5805.2,4026.6 5805.2,4021.8 5798.7,4015.3 5798.7,4000.1 5823.6,3975.2 5838.8,3975.2 5845.3,3981.8 5850.1,3981.8 6283.7,3548.1 6283.7,3411.6 6264,3391.9 D7.2@6251.6,3391.9
  Top Layer w5.9: D7.2@6251.6,3391.9 6267.9,3375.6 FPC1$CBB22/CBB1.8@6267.9,3313.3
$4I2\CAM3_CLK_P: D12.2 FPC1$CBB22/CBB1.9 U100$CBB22.G1 | length 1499.5
  Top Layer w4.7: U100$CBB22.G1@5695.4,4494.2 5706.4,4494.2 5712.9,4487.7 5722.9,4487.7 5786.3,4424.3 5786.3,4063.3 5817.8,4031.8 5817.8,4016.6 5811.3,4010.1 5811.3,4005.3 5828.8,3987.8 5833.6,3987.8 5840.1,3994.4 5855.3,3994.4 6296.3,3553.3 6296.3,3414.2 6318.7,3391.9 D12.2@6327.9,3391.9
  Top Layer w5.9: FPC1$CBB22/CBB1.9@6307.2,3313.3 6307.2,3371.3 D12.2@6327.9,3391.9
$4I2\CAM3_D0_N: D11.2 FPC1$CBB22/CBB1.2 U100$CBB22.E4 | length 1483.1
  Top Layer w5.5: FPC1$CBB22/CBB1.2@6031.7,3313.3 6031.7,3368.9 D11.2@6008.6,3391.9 6031.6,3391.9 v1(6046.1,3406.3)
  Inner2 w4.3: v2(5618.6,4443) 5629.8,4443 5636.5,4436.3 5681.8,4436.3 5739.7,4378.4 5739.7,3990.9 5988.5,3742.1 5988.5,3558.7 5991.7,3555.6 6018.6,3555.6 6028.8,3545.4 6028.8,3509.9 6018.6,3499.7 5991.7,3499.7 5988.6,3496.6 5988.6,3481.9 ; 5988.5,3481.8 5988.5,3404.7 5993.2,3400.1 6036.7,3400.1 6042.9,3406.3 v1(6046.1,3406.3)
$4I2\CAM3_D0_P: D10.2 FPC1$CBB22/CBB1.3 U100$CBB22.D4 | length 1476
  Top Layer w5.5: v1(6046.1,3381.7) 6056.3,3391.9 D10.2@6082.9,3391.9 6071,3380 FPC1$CBB22/CBB1.3@6071,3313.3
  Inner2 w4.3: v2(5618.6,4417.4) 5629.8,4417.4 5636.5,4424.1 5676.7,4424.1 5727.5,4373.3 5727.5,3985.8 5976.5,3736.9 5976.5,3553.7 5976.4,3553.6 5986.6,3543.4 6013.5,3543.4 6016.6,3540.3 6016.6,3515 6013.5,3511.9 5986.6,3511.9 5976.4,3501.7 5976.4,3481.9 ; 5976.5,3481.8 5976.5,3399.5 5988.1,3387.9 6036.7,3387.9 6042.9,3381.7 v1(6046.1,3381.7)
$4I2\CAM3_D1_N: D8.2 FPC1$CBB22/CBB1.5 U100$CBB22.G3 | length 1527.3
  Top Layer w5.9: FPC1$CBB22/CBB1.5@6149.8,3313.3 6149.8,3371.2 D8.2@6129.1,3391.9 6134.7,3397.5 6163.1,3397.5 v1(6169.3,3403.7)
  Inner2 w4.3: v2(5644.2,4494.2) 5674.6,4494.2 5681.2,4487.5 ; 5681.4,4487.6 5720.5,4487.6 5738.3,4469.8 5742.6,4469.8 5742.9,4470.1 5747.2,4470.1 5762.4,4454.9 5762.4,4450.6 5762.1,4450.3 5762.1,4446 5785.9,4422.2 5785.9,4063.2 6069,3780.1 6069,3581.3 6109.2,3541.1 6109.2,3403.5 6115.2,3397.5 6149.9,3397.5 6156.1,3403.7 v1(6169.3,3403.7)
$4I2\CAM3_D1_P: D9.2 FPC1$CBB22/CBB1.6 U100$CBB22.F3 | length 1527
  Top Layer w5.9: v1(6169.3,3379.1) 6181,3379.1 6193.7,3391.9 D9.2@6209.4,3391.9 6209.4,3385.5 6189.1,3365.2 FPC1$CBB22/CBB1.6@6189.1,3313.3
  Inner2 w4.3: v2(5644.2,4468.6) 5649.8,4468.6 5662.8,4481.6 5675.2,4481.6 5681.4,4475.4 5715.5,4475.4 5773.7,4417.1 5773.7,4058.1 6056.8,3775 6056.8,3576.2 6097,3536.1 6097,3398.5 6110.1,3385.3 6149.9,3385.3 6156.1,3379.1 v1(6169.3,3379.1)
$4I2\F2-EXT_CLK: R47.2 R48.2 R77.2 | length 968.3
  Inner2 w4.7: v1(4157.4,4532) 4165.4,4540 4506.7,4540 v1(4561.6,4594.9)
  Inner4 w4.7: v1(4157.4,4283) v1(4157.4,4532) ; v1(4561.6,4594.9) 4558.9,4597.6 4558.9,4700.6 v1(4569,4710.7)
  Bottom Layer w4.7: R48.2@4153.3,4201.6 4157.4,4205.7 v1(4157.4,4283) ; v1(4569,4710.7) 4567.9,4711.7 R47.2@4567.9,4748.8 R77.2@4614.2,4748.8
$4I2\F2-INTB: R179$CBB22/CBB2.2 U98$CBB22/CBB2.31 U100$CBB22.R12 | length 2018.1
  Top Layer w4.7: v1(4418,4337.2) 4436.4,4337.2 U98$CBB22/CBB2.31@4459.5,4314.1
  Inner2 w4.7: v1(4418,4337.2) 4418,4345.6 4388.3,4375.4 4388.3,4435.6 4404.3,4451.7 4445.7,4451.7 v1(4490.7,4406.7) 4508.6,4424.6 4508.6,4428.3 4518.1,4437.8 4519.5,4437.8 4525.5,4443.8 4538.9,4443.8 4547.1,4435.6 4695.5,4435.6 v1(4739.6,4391.4)
  Inner2 w5.5: v1(4816.8,4936.4) 4843.1,4936.4 4908.2,4871.3 v1(5400.2,4871.3)
  Inner4 w3.9: v2(5413.9,4698.9) 5426.7,4711.7 5426.7,4796.2
  Inner4 w4.7: v1(4739.6,4391.4) 4824.9,4476.7 4824.9,4772.2 4822.7,4774.5 4822.7,4787.9 4816.8,4793.8 v1(4816.8,4936.4) ; v1(5400.2,4871.3) 5420.3,4871.3 5421.3,4870.3 5421.3,4853.6 5426.7,4848.3 5426.7,4796.2
  Bottom Layer w4.7: R179$CBB22/CBB2.2@4453.5,4385.4 4469.3,4385.4 v1(4490.7,4406.7)
$4I2\F2-MDC: U98$CBB22/CBB2.13 U100$CBB22.V12 | length 1843.2
  Top Layer w4.7: U98$CBB22/CBB2.13@4656.3,4203.8 4676.3,4203.8 4695.5,4184.6 v1(4711.5,4184.6) ; v1(5376.1,5037.6) 5394.2,5019.5 5394.2,5012.6 5380.5,4998.9 5380.5,4977.4 5387,4970.9 5387,4950.8 5413.9,4923.9 5413.9,4886.6 5414.4,4886 5414.4,4880 5416.5,4878 5416.5,4864.6 5413.9,4862 U100$CBB22.V12@5413.9,4775.7
  Inner2 w5.5: v1(4771.8,5009.4) 4781.3,5009.4 4791.5,4999.3 4802.4,4999.3 4815.9,4985.7 5324.3,4985.7 5356,5017.4 5356,5020.7 5365.7,5030.5 5369.1,5030.5 v1(5376.1,5037.6)
  Inner4 w5.5: v1(4711.5,4184.6) 4711.5,4206.7 4713,4208.2 4713,4379.7 4712.5,4380.2 4712.5,4402.7 4713,4403.2 4713,4640.7 4735.1,4662.8 4735.1,4676.8 ; 4734.3,4676 4735.1,4676.8 ; v1(4771.8,5009.4) 4735.1,4972.8 4735.1,4676.8
$4I2\F2-MDIO: R180$CBB22/CBB2.2 U98$CBB22/CBB2.14 U100$CBB22.U12 | length 1875.5
  Top Layer w4.3: 5400.9,4785.2 5401.3,4784.8 5401.3,4762.7 U100$CBB22.U12@5413.9,4750.1
  Top Layer w4.7: U98$CBB22/CBB2.14@4656.3,4219.6 4680.6,4219.6 4695.5,4204.7 4731.6,4204.7 v1(4739.6,4196.7) 4764.8,4171.5 R180$CBB22/CBB2.2@4764.8,4152.5 ; v1(5372.6,5013.9) 5369.5,5010.8 5369.5,4865.8 5369.6,4865.6 5369.3,4865.3 5369.3,4861.4 5368.2,4860.3 5368.2,4846.9 5377.7,4837.4 5391.1,4837.4 5394.5,4840.8 5400.9,4834.3 5400.9,4785.2
  Inner2 w5.5: v1(4771.8,4979.7) 4776.3,4975.2 5334,4975.2 v1(5372.6,5013.9)
  Inner4 w5.5: v1(4739.6,4196.7) 4723.6,4212.7 4723.6,4384 4723,4384.5 4723,4398.3 4723.6,4398.9 4723.6,4636.4 4745.7,4658.5 4745.7,4953.6 v1(4771.8,4979.7)
$4I2\F2-RSTB: R1$CBB22/CBB2.1 U98$CBB22/CBB2.12 U100$CBB22.T12 | length 1696.1
  Top Layer w4.7: U98$CBB22/CBB2.12@4656.3,4188.1 4671.9,4188.1 4727.6,4132.4 4727.6,4126.4 4739.6,4114.3 4760.8,4114.3 R1$CBB22/CBB2.1@4764.8,4110.3 4786.9,4132.4 4822,4132.4 4846.8,4157.3 v1(4846.8,4160.5)
  Inner2 w5.5: v1(4847.6,4900.9) 4863.6,4884.9 4879.8,4884.9 4903.9,4860.8 5377.2,4860.8 v1(5384.4,4853.6)
  Inner4 w4.7: v1(4846.8,4160.5) 4847,4160.7 4847,4762.7 4847.9,4762.7 4857.4,4772.2 4857.4,4785.7 4847.6,4795.4 v1(4847.6,4900.9) ; v1(5384.4,4853.6) 5413.9,4824.1 v2(5413.9,4724.5)
$4I2\F2-RXC: R176$CBB22/CBB2.2 U98$CBB22/CBB2.27 U100$CBB22.H13 | length 1052.2
  Top Layer w3.9: 5242,4379.1 5291.2,4379.1 5298.7,4386.6 5298.7,4397.2 5306.2,4404.6 5316.8,4404.6 5324.3,4412.1 5324.3,4448.3 5331.8,4455.8 5342.4,4455.8 5349.9,4463.3 5349.9,4473.9 5357.4,4481.4 5368,4481.4 5375.5,4488.9 5375.5,4499.5 5374.1,4500.9 5374.1,4505.6 U100$CBB22.H13@5388.3,4519.8
  Top Layer w4.7: 5209.6,4379.1 5242,4379.1
  Top Layer w5.9: v1(4532.8,4403.9) 4534.3,4402.4 U98$CBB22/CBB2.27@4534.3,4341.6 ; v1(5187.8,4357.3) 5209.6,4379.1
  Inner2 w5.5: v1(4532.8,4403.9) 4539,4397.7 4539,4394.6 4540.2,4393.4 4687.4,4393.4 4719.6,4361.3 5183.8,4361.3 v1(5187.8,4357.3)
$4I2\F2-RXCTL: R71.1 R251$CBB22.2 U98$CBB22/CBB2.26 U100$CBB22.M17 | length 1086.4
  Top Layer w4.3: 5250.9,4609.2 5251.2,4609.6 5273.3,4609.6 U100$CBB22.M17@5285.9,4622.2
  Top Layer w4.7: R71.1@4528.8,4452.7 4540,4452.7 4550,4442.7 ; 5214.7,4609.2 5250.9,4609.2
  Top Layer w5.9: U98$CBB22/CBB2.26@4550,4341.6 4550,4442.7 4574.2,4466.9 4574.2,4472.8 4559,4488 4559,4493.9 4572.6,4507.5 4578.5,4507.5 4593.7,4492.3 4599.6,4492.3 4613.2,4505.9 4613.2,4511.8 4598,4527 4598,4532.9 4611.6,4546.5 4617.5,4546.5 4632.7,4531.3 4638.6,4531.3 v1(4767.7,4660.4) ; v1(5123.1,4600.2) 5132.1,4609.2 5214.7,4609.2
  Inner2 w5.5: v1(4767.7,4660.4) 4801.7,4626.3 5096.4,4626.3 5113,4609.8 5113.6,4609.8 v1(5123.1,4600.2)
$4I2\F2-RXD0: R70.1 R73.2 U98$CBB22/CBB2.25 U100$CBB22.M16 | length 1098.1
  Top Layer w5.9: U98$CBB22/CBB2.25@4565.8,4341.6 4565.8,4408.3 4669.4,4511.9 4669.4,4534 4874.2,4738.8 5070.9,4738.8 v1(5113.1,4696.6)
  Inner2 w4.7: 5213.5,4622.2 v2(5311.5,4622.2)
  Inner2 w5.5: v1(5113.1,4696.6) 5113.1,4688.8 5179.8,4622.2 5213.5,4622.2
  Bottom Layer w7.9: v1(5113.1,4696.6) 5130.7,4696.6 ; R70.1@5134.2,4732.8 5134.2,4700.2 5130.7,4696.6 ; R73.2@5157.3,4693.6 5154.2,4696.6 5130.7,4696.6
$4I2\F2-RXD1: R69.1 R72.2 U98$CBB22/CBB2.24 U100$CBB22.M14 | length 1101.2
  Top Layer w5.9: U98$CBB22/CBB2.24@4581.5,4341.6 4581.5,4399.9 4699.5,4517.9 4699.5,4546 4877.6,4724.2 5069.2,4724.2 5079,4714.3 5079,4694.9 5091.2,4682.7 v1(5089,4680.6)
  Inner4 w3.9: 5242,4609.8 5242.4,4609.4 5349.9,4609.4 v2(5362.7,4622.2)
  Inner4 w4.7: 5213.5,4609.8 5242,4609.8
  Inner4 w5.1: v1(5089,4680.6) 5106,4680.6 5106.3,4680.2 5119.9,4680.2 5120.3,4680.6 5121.1,4680.6 5191.9,4609.8 5213.5,4609.8
  Bottom Layer w7.9: v1(5089,4680.6) 5091,4682.6 R72.2@5091,4721.7
$4I2\F2-RXD2: R169$CBB22/CBB2.1 U98$CBB22/CBB2.23 U100$CBB22.N15 | length 1072.7
  Top Layer w5.9: U98$CBB22/CBB2.23@4597.3,4341.6 4597.3,4375.5 4648.2,4426.5 4654.1,4426.5 4657.2,4423.3 4663.1,4423.3 4676.7,4436.9 4676.7,4442.8 4673.6,4445.9 4673.6,4451.8 4687.2,4465.4 4693.1,4465.4 4696.2,4462.3 4702.1,4462.3 4715.7,4475.9 4715.7,4481.8 4712.6,4484.9 4712.6,4490.8 4725.6,4503.9 4725.6,4550 4882.9,4707.3 4893.8,4707.3 4898,4703.2 4898,4692.8 4902.2,4688.6 4921.4,4688.6 4925.6,4692.8 4925.6,4703.2 4929.7,4707.3 4948.9,4707.3 4953.1,4703.2 4953.1,4692.8 4957.3,4688.6 4976.5,4688.6 4980.7,4692.8 4980.7,4703.2 4984.9,4707.3 v1(5062.2,4707.3)
  Inner2 w3.9: 5295.8,4633.9 5296.9,4635 5324.3,4635 v2(5337.1,4647.8)
  Inner2 w4.7: 5213.5,4633.9 5295.8,4633.9
  Inner2 w5.5: v1(5062.2,4707.3) 5100.3,4707.3 5106.2,4713.2 5120,4713.2 5129.7,4703.5 5129.7,4692 5187.9,4633.9 5213.5,4633.9
$4I2\F2-RXD3: R173$CBB22/CBB2.1 U98$CBB22/CBB2.22 U100$CBB22.M15 | length 1054
  Top Layer w5.9: U98$CBB22/CBB2.22@4613,4341.6 4613,4357.1 4651.3,4395.4 4663.3,4395.4 4745.7,4477.8 4745.7,4536 4766.5,4556.8 4772.4,4556.8 4781.5,4547.6 4787.4,4547.6 4801,4561.2 4801,4567.1 4791.9,4576.3 4791.9,4582.2 4805.5,4595.8 4811.4,4595.8 4820.5,4586.6 4826.4,4586.6 4840,4600.2 4840,4606.1 4830.8,4615.3 4830.8,4621.2 4844.4,4634.7 4850.3,4634.7 4859.5,4625.6 4865.4,4625.6 4879.6,4639.8 4879.6,4645.7 4866.4,4658.8 4866.4,4664.7 4880,4678.3 4885.9,4678.3 4899.1,4665.2 4905,4665.2 4912.3,4672.5 v1(5012.7,4672.5)
  Inner2 w3.9: 5295.8,4608.3 5296.9,4609.4 5324.3,4609.4 v2(5337.1,4622.2)
  Inner2 w4.7: 5213.5,4608.3 5295.8,4608.3
  Inner2 w5.5: v1(5012.7,4672.5) 5046.9,4638.4 5099.3,4638.4 5117.3,4620.3 5155.3,4620.3 5167.3,4608.3 5213.5,4608.3
$4I2\F2-TXC: U98$CBB22/CBB2.20 U100$CBB22.L15 | length 929.8
  Top Layer w5.9: U98$CBB22/CBB2.20@4656.3,4314.1 4686.4,4314.1 4711.2,4338.9 4711.2,4344.8 4704.1,4351.9 4704.1,4357.8 4717.6,4371.4 4723.6,4371.4 4730.7,4364.3 4736.6,4364.3 4771.8,4399.4 4771.8,4433 4767.6,4437.2 4757.9,4437.2 4753.7,4441.4 4753.7,4460.6 4757.9,4464.8 4767.6,4464.8 4771.8,4468.9 4771.8,4513.9 4834,4576.1 v1(4868.1,4576.1)
  Inner2 w3.9: 5295.8,4582.7 5296.9,4583.8 5324.3,4583.8 v2(5337.1,4596.6)
  Inner2 w4.7: 5213.5,4582.7 5295.8,4582.7
  Inner2 w5.5: v1(4868.1,4576.1) 4882.2,4562.1 5149.3,4562.1 5169.9,4582.7 5213.5,4582.7
$4I2\F2-TXCTL: U98$CBB22/CBB2.19 U100$CBB22.L14 | length 963.3
  Top Layer w5.9: U98$CBB22/CBB2.19@4656.3,4298.3 4690.7,4298.3 4801.9,4409.5 4801.9,4513.9 4847.3,4559.3 4875.1,4559.3 4885,4569.2 4885,4603 4926.4,4644.4 5091.3,4644.4 5094.1,4641.7 5108,4641.7 5110.8,4644.4 v1(5121.1,4644.4)
  Inner4 w3.9: 5242,4584.2 5242.4,4583.8 5349.9,4583.8 v2(5362.7,4596.6)
  Inner4 w4.7: 5213.5,4584.2 5242,4584.2
  Inner4 w5.1: v1(5121.1,4644.4) 5127.2,4644.4 5187.4,4584.2 5213.5,4584.2
$4I2\F2-TXD0: U98$CBB22/CBB2.18 U100$CBB22.M18 | length 933.6
  Top Layer w4.7: 5214.7,4622.2 U100$CBB22.M18@5260.4,4622.2
  Top Layer w5.9: U98$CBB22/CBB2.18@4656.3,4282.6 4705.5,4282.6 4724,4301.1 4730,4301.1 4731.9,4299.2 4737.8,4299.2 4751.4,4312.8 4751.4,4318.7 4749.4,4320.6 4749.4,4326.5 4763,4340.1 4768.9,4340.1 4770.9,4338.2 4776.8,4338.2 4790.3,4351.8 4790.3,4357.7 4788.4,4359.6 4788.4,4365.5 4802,4379.1 4807.9,4379.1 4809.8,4377.2 4815.7,4377.2 4829.3,4390.7 4829.3,4396.6 4827.4,4398.6 4827.4,4404.5 4842,4419.1 4842,4427.9 4837.9,4432 4824.1,4432 4820,4436.2 4820,4455.4 4824.1,4459.6 4837.9,4459.6 4842,4463.8 4842,4474.4 4837.9,4478.6 4824.1,4478.6 4820,4482.8 4820,4502 4824.1,4506.1 4837.9,4506.1 4842,4510.3 4842,4519.2 4871.3,4548.4 4879.6,4548.4 4895.9,4564.7 4895.9,4573 4910,4587.2 4910,4593.1 4905.5,4597.6 4905.5,4603.5 4919.1,4617.1 4925,4617.1 4929.5,4612.6 4935.4,4612.6 4945,4622.2 5214.7,4622.2
$4I2\F2-TXD1: U98$CBB22/CBB2.17 U100$CBB22.L18 | length 930.9
  Top Layer w4.7: 5214.7,4596.6 U100$CBB22.L18@5260.4,4596.6
  Top Layer w5.9: U98$CBB22/CBB2.17@4656.3,4266.8 4725.4,4266.8 4740.5,4281.8 4746.4,4281.8 4751.8,4276.5 4757.7,4276.5 4771.2,4290.1 4771.2,4296 4765.9,4301.3 4765.9,4307.2 4779.5,4320.8 4785.4,4320.8 4790.7,4315.5 4796.6,4315.5 4810.2,4329.1 4810.2,4335 4804.9,4340.3 4804.9,4346.2 4818.5,4359.8 4824.4,4359.8 4829.7,4354.4 4835.6,4354.4 4849.2,4368 4849.2,4373.9 4843.8,4379.3 4843.8,4385.2 4870.2,4411.5 4870.2,4414.1 4874.3,4418.3 4878,4418.3 4882.2,4422.5 4882.2,4441.7 4878,4445.8 4874.3,4445.8 4870.2,4450 4870.2,4469.2 4874.3,4473.4 4878,4473.4 4882.2,4477.6 4882.2,4496.8 4878,4501 4874.3,4501 4870.2,4505.1 4870.2,4521.9 4888.2,4540 4894.1,4540 4895.3,4538.9 4901.2,4538.9 4914.7,4552.5 4914.7,4558.4 4913.6,4559.5 4913.6,4565.4 4956.5,4608.3 5001.6,4608.3 5002,4608.7 5016,4608.7 5016.4,4608.3 5064.9,4608.3 5089.8,4583.4 5130.1,4583.4 5142.9,4596.2 5214.4,4596.2 5214.7,4596.6
$4I2\F2-TXD2: U98$CBB22/CBB2.16 U100$CBB22.L16 | length 939.4
  Top Layer w5.9: U98$CBB22/CBB2.16@4656.3,4251.1 4750.2,4251.1 4767.7,4268.6 4773.6,4268.6 4775.6,4266.6 4781.5,4266.6 4795.1,4280.2 4795.1,4286.1 4793.1,4288.1 4793.1,4294 4806.7,4307.6 4812.6,4307.6 4814.6,4305.6 4820.5,4305.6 4834,4319.2 4834,4325.1 4832.1,4327 4832.1,4332.9 4845.7,4346.5 4851.6,4346.5 4853.5,4344.6 4859.4,4344.6 4873,4358.1 4873,4364 4871.1,4366 4871.1,4371.9 4894.3,4395.1 4894.3,4400 4898.4,4404.2 4902.1,4404.2 4906.3,4408.3 4906.3,4427.5 4902.1,4431.7 4898.4,4431.7 4894.3,4435.9 4894.3,4458.6 4902.3,4466.6 4902.3,4486.2 4894.3,4494.2 4894.3,4509.9 4902.4,4518 4908.3,4518 4911.4,4514.9 4917.3,4514.9 4930.9,4528.5 4930.9,4534.4 4927.8,4537.5 4927.8,4543.4 4958.5,4574.1 5024.8,4574.1 v1(5030.8,4580.2)
  Inner2 w4.7: 5213.5,4596.6 v2(5311.5,4596.6)
  Inner2 w5.5: v1(5030.8,4580.2) 5141.2,4580.2 5157.6,4596.6 5213.5,4596.6
$4I2\F2-TXD3: U98$CBB22/CBB2.15 U100$CBB22.L17 | length 958.1
  Top Layer w4.3: 5250.9,4583.6 5251.2,4584 5273.3,4584 U100$CBB22.L17@5285.9,4596.6
  Top Layer w4.7: 5214.7,4583.6 5250.9,4583.6
  Top Layer w5.9: U98$CBB22/CBB2.15@4656.3,4235.3 4715.6,4235.3 4719.8,4231.1 4719.8,4222.9 4723.9,4218.7 4743.2,4218.7 4747.3,4222.9 4747.3,4231.1 4751.5,4235.3 4772.3,4235.3 4785.2,4248.3 4791.1,4248.3 4798.9,4240.5 4804.8,4240.5 4818.4,4254.1 4818.4,4260 4810.6,4267.7 4810.6,4273.6 4824.2,4287.2 4830.1,4287.2 4837.9,4279.5 4843.8,4279.5 4857.4,4293 4857.4,4298.9 4849.6,4306.7 4849.6,4312.6 4863.2,4326.2 4869.1,4326.2 4876.8,4318.4 4882.7,4318.4 4896.3,4332 4896.3,4337.9 4888.6,4345.7 4888.6,4351.6 4918.3,4381.4 4918.3,4497.8 4972.6,4552 5123.1,4552 5155.3,4584.2 5214.2,4584.2 5214.7,4583.6
$4I2\T120_CBSEL0: R76.2 R158$CBB22.2 U100$CBB22.J17 | length 2528.1
  Top Layer w4.3: 5250.9,4532.4 5251.2,4532.8 5273.3,4532.8 U100$CBB22.J17@5285.9,4545.4
  Top Layer w4.7: v1(4897.8,4104.8) 4897.8,4109.8 4908.3,4120.4 4956.5,4120.4 5010.4,4174.3 5010.4,4369.3 5109.4,4468.3 5125.2,4468.3 5189.3,4532.4 5250.9,4532.4
  Top Layer w5.9: R76.2@4009.8,4867.3 R158$CBB22.2@4009.8,4827.1 4045.5,4827.1 v1(4049.1,4823.5)
  Inner2 w4.7: v1(4095.1,3957.7) 4121.2,3957.7 4127.1,3963.6 4134,3963.6 4144.8,3974.4 4701.8,3974.4 4831.9,4104.5 4897.5,4104.5 v1(4897.8,4104.8)
  Inner4 w4.7: v1(4049.1,4823.5) 4085.4,4787.2 4085.4,4366.4 4093.8,4358 4093.8,4344.5 4080.8,4331.5 4080.8,3972 v1(4095.1,3957.7)
$4I2\T120_CBSEL1: R65.2 R75.2 U100$CBB22.J18 | length 2545.7
  Top Layer w4.7: v1(4880.2,4120.7) 4886.9,4127.5 4886.9,4128.2 4888.8,4130.1 4952.5,4130.1 5000.7,4178.3 5000.7,4373.3 5105.4,4478.1 5121.2,4478.1 5188.5,4545.4 U100$CBB22.J18@5260.4,4545.4
  Top Layer w5.9: R65.2@4009.8,4947.6 R75.2@4009.8,4907.4 4046.9,4907.4 v1(4050.9,4903.4)
  Inner2 w4.7: v1(4127.2,3979.8) 4131.6,3984.1 4697.8,3984.1 4834.4,4120.7 v1(4880.2,4120.7)
  Inner4 w4.7: v1(4050.9,4903.4) 4050.9,4865.3 4095.1,4821.1 4095.1,4370.4 4103.5,4362 4103.5,4340.5 4090.5,4327.5 4090.5,3991.6 4100.4,3981.7 4125.4,3981.7 v1(4127.2,3979.8)
$4I2\T120_CCK: U99$CBB22.6 U100$CBB22.N13 | length 1159.3
  Top Layer w3.9: 5242,4760.9 5253,4760.9 5255.1,4762.9 5265.7,4762.9 5273.2,4755.4 5273.2,4744.8 5280.6,4737.3 5291.2,4737.3 ; 5291.3,4737.3 5298.7,4729.8 5298.7,4719.2 5306.2,4711.7 5342.4,4711.7 5349.9,4704.2 5349.9,4668 5357.4,4660.6 5375.5,4660.6 v2(5388.3,4647.8)
  Top Layer w4.7: U99$CBB22.6@4407.9,4990.8 4505.7,4990.8 v1(4510.7,4985.7) ; v1(4627,4983.2) 4660.7,4949.6 4776,4949.6 4849.1,4876.5 5083.1,4876.5 5153.1,4806.5 5153.1,4806.2 5162.6,4796.7 5162.9,4796.7 5198.7,4760.9 5202.9,4760.9 5204.8,4762.7 5226.3,4762.7 5228.1,4760.9 5242,4760.9
  Inner2 w4.7: v1(4510.7,4985.7) 4513.3,4983.2 v1(4627,4983.2)
$4I2\T120_CDI0: U99$CBB22.5 U100$CBB22.M13 | length 1220.1
  Top Layer w4.7: U99$CBB22.5@4407.9,4940.8 4499.5,4940.8 v1(4512.8,4927.5) 4560.9,4927.5 4617.2,4871.3 4747.7,4871.3 v1(4767.8,4851.2)
  Inner2 w3.9: 5286.6,4796.2 5289.8,4793 5346,4793 5375.5,4763.5 5375.5,4693.6 5383,4686.1 5393.6,4686.1 5401.1,4678.6 5401.1,4642.5 5402.2,4641.3 5402.2,4636.1 v2(5388.3,4622.2)
  Inner2 w4.7: v1(4767.8,4851.2) 4777.8,4861.3 4889.1,4861.3 4899.7,4850.7 5242.2,4850.7 5251.7,4841.2 5251.7,4830.4 v1(5263.7,4818.4) 5285.8,4796.2 5286.6,4796.2
$4I2\T120_CDI1: U99$CBB22.2 U100$CBB22.N14 | length 1663.6
  Inner2 w4.7: v1(4159.8,5048.4) 4173.9,5048.4 4307.6,5182.2 4806.6,5182.2 4807.7,5183.3 4829.2,5183.3 4830.3,5182.2 4886.2,5182.2 4917.1,5151.4 4943.3,5151.4 4945.5,5149.2 v1(4977.8,5149.2)
  Inner4 w3.9: 5242,4635.4 5242.4,4635 5349.9,4635 v2(5362.7,4647.8)
  Inner4 w4.7: v1(4977.8,5149.2) 4988.5,5138.5 4988.5,5082.3 5066.9,5003.8 5066.9,4765.7 5197.3,4635.4 5242,4635.4
$4I2\T120_CDI2: R67.1 U99$CBB22.3 U100$CBB22.K14 | length 1930.8
  Top Layer w4.7: R67.1@4055.4,4991 4129.8,4991 U99$CBB22.3@4130,4990.8 4185.7,4990.8 v1(4234.8,5040)
  Inner2 w4.7: v1(4234.8,5040) 4234.8,5095.3 4312,5172.5 4810.7,5172.5 4811.8,5173.6 4825.2,5173.6 4826.3,5172.5 4882.2,5172.5 4929.2,5125.5 v1(4972.2,5125.5)
  Inner4 w3.9: 5242,4558.6 5242.4,4558.2 5349.9,4558.2 v2(5362.7,4571)
  Inner4 w4.7: v1(4972.2,5125.5) 4974.9,5122.8 4974.9,5070.8 4982,5063.8 4982,5047.6 4984,5045.6 4984,4679.2 4996.5,4666.7 4996.5,4665.8 5006,4656.3 5006.9,4656.3 5104.5,4558.6 5242,4558.6
$4I2\T120_CDI3: R66.1 U99$CBB22.7 U100$CBB22.K18 | length 3070.7
  Top Layer w4.7: v1(4049.1,5050) 4065.2,5066.1 4350.8,5066.1 4376,5040.8 U99$CBB22.7@4407.9,5040.8 4457.4,5040.8 4468.9,5052.3 R66.1@4490.1,5052.3 ; v1(4868.1,4144.4) 4950.5,4226.8 4950.5,4477.8 4991.7,4519 5115.1,4519 5167.1,4571 U100$CBB22.K18@5260.4,4571
  Inner2 w4.7: v1(4106.8,4026) 4111.2,4026 4143.3,3993.9 4680,3993.9 4826.6,4140.4 4864.1,4140.4 v1(4868.1,4144.4)
  Inner4 w4.7: v1(4049.1,5050) 4055.6,5043.5 4055.6,4943.6 4104.8,4894.3 4104.8,4374.4 4113.2,4366 4113.2,4336.5 4104.8,4328.1 4104.8,4027.9 v1(4106.8,4026)
$4I2\T120_GCLK: U100$CBB22.K17 X1.3 | length 618.6
  Top Layer w4.3: 5251.2,4558.4 5273.3,4558.4 U100$CBB22.K17@5285.9,4571
  Top Layer w5.9: v1(4953.7,4168.4) 4976.6,4191.3 4976.6,4395.4 5081,4499.8 5119.1,4499.8 5177.3,4558 5250.9,4558 5251.2,4558.4
$4I2\T120_LED1: R95$CBB22.2 U100$CBB22.G13 | length 1382.8
  Top Layer w4.7: v1(4818.5,5157.4) 4818.5,5184.4 R95$CBB22.2@4841.2,5207.2
  Inner4 w3.9: 5366.6,4377.6 5375.5,4386.6 5375.5,4397.2 5383,4404.6 5395.4,4404.6 5401.1,4410.4 5401.1,4473.9 5398.2,4476.8 5398.2,4484.3 v2(5388.3,4494.2)
  Inner4 w4.7: v1(4818.5,5157.4) 4818.5,5081.6 4834,5066.1 4834,4969.7 4910.3,4893.4 4910.3,4550 5089,4371.3 5178.9,4371.3 5181.1,4373.5 5202.8,4373.5 5204.8,4371.5 5218.2,4371.5 5218.4,4371.3 5360.3,4371.3 5366.6,4377.6
$4I2\T120_LED2: R1$CBB22.2 U100$CBB22.B17 | length 2229.7
  Top Layer w3.9: 5273.1,4322.1 5273.1,4353.5 U100$CBB22.B17@5285.9,4366.3
  Top Layer w4.7: v1(4829.6,5241.1) 4844.1,5255.6 4844.1,5268.5 R1$CBB22.2@4841.2,5271.4 ; v1(5201.3,4220.7) 5201.3,4246.4 5273.1,4318.2 5273.1,4322.1
  Inner2 w4.7: v1(4579,5220.7) 4583.8,5225.4 4624.7,5225.4 4627.5,5222.6 4811.1,5222.6 v1(4829.6,5241.1) ; v1(4657.3,4136.3) 4657.8,4136.7 4664.3,4136.7 4670.8,4130.2 4684.3,4130.2 4695.3,4141.3 4695.3,4146.5 4757.7,4146.5 4789.7,4178.4 4789.7,4185.3 4799.2,4194.8 4812.6,4194.8 4816.6,4190.8 4818.6,4190.8 4824.8,4184.6 5165.2,4184.6 v1(5201.3,4220.7)
  Inner4 w4.7: v1(4579,5220.7) 4579,5178.5 4599.1,5158.4 4599.1,5068.2 4598.7,5067.8 4598.7,5014.1 4599.1,5013.7 4599.1,4861.2 4625.2,4835.2 4625.2,4752.5 4591.4,4718.7 4591.4,4695.6 4589.1,4693.3 4589.1,4671.8 4591.4,4669.5 4591.4,4606.2 4625.2,4572.4 4625.2,4421.5 4659.3,4387.4 4659.3,4373.4 4661.2,4371.5 4661.2,4346.9 4660.3,4345.9 4660.3,4139.2 v1(4657.3,4136.3)
$4I2\T120_NSTATUS: LED5.1 R253$CBB22.1 U100$CBB22.J14 | length 1195
  Top Layer w4.7: v1(5032.8,4343.2) 5032.8,4259.8 5032.6,4259.6 5032.6,4246.2 5032.8,4246 5032.8,4216.7 5022.8,4206.7 5022.8,3844 5095.6,3771.1 R253$CBB22.1@5109,3771.1 5143.4,3771.1 5163.2,3791 LED5.1@5163.2,3803.6
  Inner4 w3.9: 5242,4533 5242.4,4532.6 5349.9,4532.6 v2(5362.7,4545.4)
  Inner4 w4.7: v1(5081,4535.2) 5113.9,4535.2 5116.1,4533 5242,4533
  Bottom Layer w4.7: v1(5032.8,4343.2) 5032.8,4487 v1(5081,4535.2)
$4I2\T120_SS: R68.1 U99$CBB22.1 U100$CBB22.P15 | length 1543.1
  Top Layer w4.7: v1(4130,5090.8) 4130,5150.1 R68.1@4130.2,5150.4 ; v1(4546.9,4889.4) 4554.9,4881.3 4583,4881.3 4621.2,4843.2 4752.8,4843.2 4761,4835 4785.1,4835 v1(4838.9,4781.2)
  Inner2 w3.9: 5295.8,4659.5 5296.9,4660.6 5324.3,4660.6 v2(5337.1,4673.3)
  Inner2 w4.7: v1(4189.5,4885.4) 4193.5,4889.4 v1(4546.9,4889.4) ; v1(4838.9,4781.2) 4998.1,4781.2 5002,4785.1 5015.4,4785.1 5019.3,4781.2 5074.7,4781.2 5196.4,4659.5 5295.8,4659.5
  Inner4 w4.7: v1(4130,5090.8) 4130,5055.3 4189.5,4995.8 v1(4189.5,4885.4)
$4I2\T120_TEST: R252$CBB22.1 U100$CBB22.J15 | length 728.6
  Inner2 w3.9: 5295.8,4531.5 5296.9,4532.6 5324.3,4532.6 v2(5337.1,4545.4)
  Inner2 w4.7: v1(4717.7,4680.7) 4722.2,4676.2 4722.2,4655.4 4881.7,4495.9 5162.8,4495.9 5198.4,4531.5 5295.8,4531.5
$4I198\$1N187: R182$CBB23.2 U1$CBB23.M3 | length 394.2
  Inner2 w4.7: v1(3489.1,5554) 3504.9,5569.7 3822.9,5569.7 v2(3829.6,5563)
  Bottom Layer w4.7: v1(3489.1,5554) 3496.6,5546.5 3496.6,5512.9 R182$CBB23.2@3496.8,5512.8
$4I198\$1N222: LED12$CBB23.2 R11$CBB23.1 R19$CBB23.1 | length 94.1
  Top Layer w4.7: R19$CBB23.1@3726.8,5040.5 R11$CBB23.1@3726.8,5080.6 3766.6,5080.6 LED12$CBB23.2@3776.7,5070.6
$4I198\$1N228: LED1$CBB23.2 R12$CBB23.1 | length 50.6
  Top Layer w4.7: LED1$CBB23.2@3485.3,5879.5 3487.3,5877.5 R12$CBB23.1@3487.3,5829.7
$4I198\$1N229: LED2$CBB23.2 R13$CBB23.1 | length 47.8
  Top Layer w4.7: R13$CBB23.1@3358.8,5831.7 LED2$CBB23.2@3358.8,5879.5
$4I198\$1N234: LED3$CBB23.2 R14$CBB23.1 | length 49.8
  Top Layer w4.7: R14$CBB23.1@3421.1,5829.7 LED3$CBB23.2@3421.1,5879.5
$4I198\$1N235: R14$CBB23.2 U1$CBB23.P2 | length 720.3
  Top Layer w4.7: v1(3420.5,5750.7) 3421.1,5751.4 R14$CBB23.2@3421.1,5795.6 ; v1(3625.3,5463.6) 3639.3,5463.6 3656.9,5481.2 3754.3,5481.2 3758.6,5485.5 3783.7,5485.5 U1$CBB23.P2@3798.2,5500
  Inner2 w4.7: v1(3420.5,5750.7) v1(3617.2,5750.7)
  Inner4 w4.7: v1(3617.2,5750.7) 3625.3,5742.7 v1(3625.3,5463.6)
$4I198\$1N245: U1$CBB23.G12 X1$CBB23.3 | length 344.1
  Inner4 w4.7: v2(4113.1,5720.4) 4125.4,5720.4 4141.3,5704.6 4294.1,5704.6 v1(4340.1,5658.5)
  Bottom Layer w4.7: v1(4340.1,5658.5) 4340.1,5627.6 X1$CBB23.3@4382.9,5584.7
$4I198\$1N257: LED4$CBB23.2 R15$CBB23.1 | length 51.7
  Top Layer w4.7: R15$CBB23.1@4874.4,5396.2 4923.3,5396.2 LED4$CBB23.2@4925.3,5398.2
$4I198\$1N258: LED6$CBB23.2 R17$CBB23.1 | length 51.7
  Top Layer w4.7: R17$CBB23.1@4874.4,5457.7 4923.3,5457.7 LED6$CBB23.2@4925.3,5459.7
$4I198\$1N259: LED5$CBB23.2 R16$CBB23.1 | length 51.7
  Top Layer w4.7: R16$CBB23.1@4874.4,5334.6 4923.3,5334.6 LED5$CBB23.2@4925.3,5336.6
$4I198\$1N262: LED7$CBB23.2 R18$CBB23.1 | length 51.7
  Top Layer w4.7: R18$CBB23.1@4874.4,5518.7 4923.3,5518.7 LED7$CBB23.2@4925.3,5520.7
$4I198\$1N263: LED8$CBB23.2 R20$CBB23.1 | length 51.8
  Top Layer w4.7: R20$CBB23.1@4874.4,5580.3 4923.3,5580.3 LED8$CBB23.2@4925.3,5582.4
$4I198\$1N264: R16$CBB23.2 U1$CBB23.M15 | length 946.3
  Top Layer w4.7: v1(4809.9,5327.1) 4832.9,5327.1 R16$CBB23.2@4840.3,5334.6
  Inner2 w4.7: v1(4237.7,5327.1) v1(4809.9,5327.1)
  Inner3 w4.7: v1@4809.9,5323.1 4817.9,5323.1 4821.9,5327.1 ; v1(4809.9,5327.1) 4821.9,5327.1 ; 4821.9,5327.1 4838,5327.1 4844.1,5333.1 4844.1,5337.8 4840.7,5341.2 4836,5341.2 4821.9,5327.1
  Inner4 w4.7: v2(4207.6,5563) 4219.6,5563 4225.6,5556.9 4225.6,5443.7 4224.8,5442.9 4224.8,5431.1 4225.6,5430.3 4225.6,5339.1 v1(4237.7,5327.1)
$4I198\$1N265: R15$CBB23.2 U1$CBB23.M16 | length 740
  Top Layer w4.7: U1$CBB23.M16@4239.1,5563 4277.2,5563 4305.2,5535 4600,5535 4605.1,5540 4618.5,5540 4633.6,5524.9 4633.6,5523.5 4657.3,5499.8 v1(4784,5499.8) ; v1(4784,5393.3) 4786.9,5396.2 R15$CBB23.2@4840.3,5396.2
  Inner4 w4.7: v1(4784,5393.3) v1(4784,5499.8)
$4I198\$1N266: R17$CBB23.2 U1$CBB23.P16 | length 623.5
  Top Layer w4.7: U1$CBB23.P16@4239.1,5500 4244.9,5505.8 4567.4,5505.8 4599.5,5473.7 4824.3,5473.7 R17$CBB23.2@4840.3,5457.7
$4I198\$1N267: R18$CBB23.2 U1$CBB23.L15 | length 669.1
  Top Layer w4.7: U1$CBB23.L15@4207.6,5594.5 4224,5578.1 4275.8,5578.1 4309.2,5544.7 4596,5544.7 4601,5549.7 4622.5,5549.7 4643.3,5529 4643.3,5527.5 4652.2,5518.7 R18$CBB23.2@4840.3,5518.7
$4I198\$1N268: R20$CBB23.2 U1$CBB23.K12 | length 778.6
  Top Layer w4.7: v1(4818,5548) 4818,5558 R20$CBB23.2@4840.3,5580.3
  Inner2 w4.7: v2(4113.1,5625.9) 4302.2,5625.9 4326,5602.2 4366.2,5602.2 4414.4,5554 4811.9,5554 v1(4818,5548)
$4I198\$1N327: TP2$CBB23.1 U1$CBB23.E8
  other v2: 3987.1,5783.4
$4I198\$1N328: TP3$CBB23.1 U1$CBB23.C9
  other v2: 4018.6,5846.4
$4I198\$1N329: R51$CBB23.1 U1$CBB23.R2 | length 138.8
  Top Layer w4.7: R51$CBB23.1@3690.5,5413.4 3737.7,5413.4 3752.9,5428.6 3752.9,5442.7 3760.9,5450.7 3775,5450.7 3792.8,5468.5 U1$CBB23.R2@3798.2,5468.5
$4I198\$1N505: LED9$CBB23.2 R31$CBB23.2 | length 60.6
  Top Layer w4.7: LED9$CBB23.2@8337.1,6039.9 8346.1,6030.9 R31$CBB23.2@8394,6030.9
$4I198\$1N507: LED9$CBB23.1 Q4$CBB23.3 R30$CBB23.1 | length 3751.8
  Top Layer w4.7: LED9$CBB23.1@8274.2,6039.9 8233.3,6080.7 8233.3,6246.7 8319.7,6333 R30$CBB23.1@8319.7,6409.6
  Top Layer w11.8: Q4$CBB23.3@8180.7,9619.9 8180.7,9554.1 v1(8245.4,9489.4) ; v1(8271.5,6467.6) 8277.5,6467.6 8299.6,6445.5 8299.6,6429.7 R30$CBB23.1@8319.7,6409.6
  Inner4 w7.9: v1(8245.4,9489.4) 8275.5,9459.3 8275.5,9252.5 8261.5,9238.4 8261.5,9037.6 8275.5,9023.6 8275.5,8720.4 8263.5,8708.3 8263.5,8465.4 8277.5,8451.3 8277.5,7941.3 8263.5,7927.3 8263.5,7766.7 8269.5,7760.6 8269.5,7240.6 8279.5,7230.6 8279.5,7176.3 8263.5,7160.3 8263.5,6945.4 8275.5,6933.4 8275.5,6634.2 8261.5,6620.2 8261.5,6477.6 v1(8271.5,6467.6)
$4I198\$1N508: LED10$CBB23.1 Q3$CBB23.3 R29$CBB23.1 | length 3758
  Top Layer w4.7: LED10$CBB23.1@9797.7,6033.3 9797.7,6077.8 9769.4,6106.1 9769.4,6278.8 9851.7,6361.1 R29$CBB23.1@9851.7,6409.6
  Top Layer w11.8: R29$CBB23.1@9851.7,6409.6 9869,6409.6 v1(9920.5,6461) ; Q3$CBB23.3@9865.3,9619.9 9865.3,9528 v1(9873.8,9519.5)
  Inner4 w4.7: v1(9873.8,9519.5) 9879.8,9513.5 9879.8,9471.3
  Inner4 w7.9: 9879.8,9471.3 9879.8,9461.3 9929.2,9411.9 9929.2,9339.6 9938,9330.8 9938,9302.7 9928,9292.6 9928,8818.8 9940,8806.7 9940,8780.6 9928,8768.6 9928,8318.8 9918,8308.8 9918,8288.7 9928,8278.7 9928,8033.7 9938,8023.7 9938,7993.5 9926,7981.5 9926,7250.6 9940,7236.6 9940,7182.4 9926,7168.3 9926,6728.6 9940,6714.5 9940,6690.4 9927,6677.4 9927,6467.6 v1(9920.5,6461)
$4I198\$1N509: LED10$CBB23.2 R32$CBB23.2 | length 54.8
  Top Layer w4.7: LED10$CBB23.2@9860.6,6033.3 9880.3,6033.3 9888.8,6024.8 R32$CBB23.2@9911.9,6024.8
$4I198\$1N511: LED11$CBB23.1 Q2$CBB23.3 R28$CBB23.1 | length 1629.2
  Top Layer w4.7: LED11$CBB23.1@8269.7,8144.7 8269.7,8170 8233.3,8206.4 8233.3,8346.9 8319.7,8433.3 R28$CBB23.1@8319.7,8503.8
  Top Layer w11.8: R28$CBB23.1@8319.7,8503.8 8342,8503.8 v1(8394,8555.7) ; v1(8356.2,9467.2) 8379.5,9490.5 Q2$CBB23.3@8379.5,9619.9
  Inner4 w7.9: v1(8356.2,9467.2) 8356.2,9438.9 8373.9,9421.1 8392,9421.1 8406,9407.1 8406,9332.8 8416.1,9322.8 8416.1,9306.7 8408,9298.7 8408,8814.8 8414.1,8808.7 8414.1,8786.7 8408,8780.6 8408,8569.8 v1(8394,8555.7)
$4I198\$1N512: LED11$CBB23.2 R33$CBB23.2 | length 55.3
  Top Layer w4.7: LED11$CBB23.2@8332.6,8144.7 8349.2,8144.7 8358.8,8135.1 R33$CBB23.2@8383.9,8135.1
$4I198\$1N514: LED13$CBB23.1 Q1$CBB23.3 R27$CBB23.1 | length 1688
  Top Layer w7.9: v1(9797.5,8559.8) 9833.6,8559.8 9853.7,8539.7 R27$CBB23.1@9853.7,8503.8 9853.7,8435.3 9767.4,8348.9 9767.4,8206.4 9801.7,8172.1 LED13$CBB23.1@9801.7,8143.8
  Top Layer w11.8: Q1$CBB23.3@9664.5,9619.9 9664.5,9582.2 9717.2,9529.6 9789.4,9529.6 v1(9799.5,9519.5)
  Inner4 w7.9: v1(9797.5,8559.8) 9787.4,8569.8 9787.4,8710.4 9799.5,8722.4 9799.5,9087.8 9787.4,9099.9 9787.4,9180.2 9795.5,9188.2 9795.5,9268.5 9799.5,9272.6 v1(9799.5,9519.5)
$4I198\$1N515: LED13$CBB23.2 R34$CBB23.2 | length 54.9
  Top Layer w11.8: LED13$CBB23.2@9864.6,8143.8 9870.3,8138.1 9913,8138.1 R34$CBB23.2@9915.9,8135.1
$4I198\$1N516: C32$CBB23.2 R27$CBB23.2 R28$CBB23.2 R29$CBB23.2 R30$CBB23.2 R31$CBB23.1 R32$CBB23.1 R33$CBB23.1 R34$CBB23.1 R58$CBB23.2 | length 13700.8
  Top Layer w4.7: R28$CBB23.2@8319.7,8262.4 8319.7,8246.5 8383.9,8182.3 R33$CBB23.1@8383.9,8169.2
  Top Layer w11.8: R30$CBB23.2@8319.7,6168.1 8381,6106.9 ; R28$CBB23.2@8319.7,8262.4 8362.1,8304.8 v1(8408,8304.8) ; v1(8380.6,9439.6) 8380.6,9460 v1(8455.6,9535) ; R31$CBB23.1@8394,6065 8394,6093.8 8381,6106.9 ; v1(8412,6120.2) 8398.7,6106.9 8381,6106.9 ; R29$CBB23.2@9851.7,6168.1 9872,6168.1 v1(9930,6110.2) 9911.9,6092.1 R32$CBB23.1@9911.9,6058.9 ; R34$CBB23.1@9915.9,8169.2 9915.9,8184.3 9853.7,8246.5 R27$CBB23.2@9853.7,8262.4 9903.4,8262.4 v1(9936.4,8295.4)
  Top Layer w19.7: R58$CBB23.2@4358.7,9666.1 4403.2,9666.1 ; v1(4403.2,9770.5) 4403.2,9666.1 ; C32$CBB23.2@4452.1,9664.1 4450.1,9666.1 4403.2,9666.1
  Inner2 w19.7: v1(4403.2,9770.5) 4491.6,9682.2 8381.9,9682.2 8455.6,9608.5 ; v1(8455.6,9535) 8455.6,9608.5 ; v1@9911.9,9591.8 9895.3,9608.5 8455.6,9608.5
  Inner4 w11.8: v1(8380.6,9439.6) 8394.5,9439.6 8420.9,9413.2 8420.9,9338.9 8430.9,9328.9 8430.9,9300.5 8422.9,9292.5 8422.9,8820.9 8428.9,8814.9 8428.9,8780.5 8422.9,8774.5 8422.9,8319.6 v1(8408,8304.8) 8424.1,8288.7 8424.1,7993.5 8412,7981.5 8412,7282.8 8425,7269.8 8425,7215.4 8411,7201.4 8411,6735.6 8424.1,6722.6 8424.1,6692.4 8414.1,6682.4 8414.1,6656.3 8406,6648.3 8406,6166.4 8412,6160.4 v1(8412,6120.2) ; v1(9913.9,9589.8) 9944.1,9559.7 9944.1,9345.8 9952.9,9336.9 9952.9,9296.5 9944.1,9287.7 9944.1,8823.7 9954.9,8812.9 9954.9,8774.5 9944.1,8763.7 9944.1,8303 v1(9936.4,8295.4) 9944.1,8287.8 9944.1,8038.6 9952.9,8029.8 9952.9,7987.4 9944.1,7978.6 9944.1,7253.5 9954.9,7242.7 9954.9,7176.2 9944.1,7165.4 9944.1,6731.5 9954.9,6720.7 9954.9,6684.3 9944.1,6673.5 9944.1,6124.2 v1(9930,6110.2)
$4I198\CBSEL0: R158$CBB23.2 U1$CBB23.C7 | length 42.3
  Bottom Layer w7.9: v2(3955.6,5846.4) 3956.6,5847.4 R158$CBB23.2@3956.6,5888.3
$4I198\CBSEL1: R159$CBB23.2 U1$CBB23.D7 | length 90.4
  Bottom Layer w7.9: v2(3955.6,5814.9) 3996.7,5856 R159$CBB23.2@3996.7,5888.3
$4I198\CBUS0: R7$CBB23.1 R9$CBB23.2 U1$CBB23.K13 | length 544.9
  Top Layer w4.7: U1$CBB23.K13@4144.6,5625.9 4161,5642.3 4338.1,5642.3 4360.2,5620.2 4552.9,5620.2 v1(4571,5638.3)
  Bottom Layer w4.7: v1(4571,5638.3) 4584.1,5638.3 R7$CBB23.1@4612.2,5610.2 R9$CBB23.2@4612.2,5568
$4I198\CBUS1: R6$CBB23.1 R8$CBB23.2 U1$CBB23.L14 | length 482.8
  Top Layer w4.7: U1$CBB23.L14@4176.1,5594.5 4191.8,5610.2 R6$CBB23.1@4612.2,5610.2 R8$CBB23.2@4612.2,5570
$4I198\CBUS2: R3$CBB23.1 R10$CBB23.2 U1$CBB23.R16 | length 127
  Top Layer w4.7: U1$CBB23.R16@4239.1,5468.5 4267,5468.5 4290.9,5444.5 R10$CBB23.2@4314,5444.5 R3$CBB23.1@4356.1,5444.5
$4I198\FL_CLK: R182$CBB23.1 U19$CBB23.6 | length 91.1
  Top Layer w4.7: U19$CBB23.6@3477.9,5401.8 3477.9,5426.7 3490.7,5439.5 v1(3498.8,5439.5)
  Bottom Layer w4.7: R182$CBB23.1@3496.8,5478.7 3496.8,5441.5 v1(3498.8,5439.5)
$4I198\FL_CS: R5$CBB23.1 U1$CBB23.P3 U19$CBB23.1 | length 999.5
  Top Layer w4.7: v1(3313.9,5116.3) 3318.1,5120.4 R5$CBB23.1@3318.1,5149.4 3345.2,5149.4 3360.4,5164.6 U19$CBB23.1@3377.9,5164.6
  Inner2 w4.7: v1(3319.7,5480.1) 3500.5,5480.1 3510.8,5469.8 3536.3,5469.8 3545.8,5479.3 3545.8,5480.1 3642.1,5480.1 3642.7,5479.5 3656.1,5479.5 3656.2,5479.7 3662.9,5479.7 3683.2,5500 v2(3829.6,5500)
  Inner4 w4.7: v1(3313.9,5116.3) 3313.9,5193 3308.3,5198.6 3308.3,5468.8 v1(3319.7,5480.1)
$4I198\FL_CSI: R12$CBB23.2 U1$CBB23.N3 | length 591.7
  Top Layer w4.7: R12$CBB23.2@3487.3,5795.6 3512.8,5770.1 v1(3512.8,5768.8)
  Inner2 w4.7: v1(3512.8,5548) 3524.9,5560 3801.1,5560 v2(3829.6,5531.5)
  Inner4 w4.7: v1(3512.8,5548) v1(3512.8,5768.8)
$4I198\FL_CSO: R13$CBB23.2 U1$CBB23.L4 | length 711
  Top Layer w4.7: v1(3358.2,5754.8) 3358.8,5755.4 R13$CBB23.2@3358.8,5797.6
  Inner2 w4.7: v1(3358.2,5608.2) 3362.2,5604.2 3576.2,5604.2 3577.7,5602.7 3586.9,5602.7 3597.2,5592.4 3785.9,5592.4 3801.3,5607.8 3835.2,5607.8 3841.9,5601.1 3854.5,5601.1 v2(3861.1,5594.5)
  Inner4 w4.7: v1(3358.2,5608.2) v1(3358.2,5754.8)
$4I198\FL_DI: U1$CBB23.L3 U19$CBB23.5 | length 486.7
  Top Layer w4.7: U19$CBB23.5@3527.9,5401.8 3527.9,5484.3 v1(3529.6,5486)
  Inner2 w4.7: v1(3536.9,5585.9) 3545.9,5585.9 3549.1,5582.7 3817.9,5582.7 v2(3829.6,5594.5)
  Inner4 w4.7: v1(3529.6,5486) 3536.9,5493.4 v1(3536.9,5585.9)
$4I198\FL_DO: U1$CBB23.N1 U19$CBB23.2 | length 633
  Top Layer w4.7: U19$CBB23.2@3427.9,5164.6 3427.9,5181.9 3450.6,5204.6 3549,5204.6 3555,5210.6 3555,5415.1 3609.1,5469.2 3609.1,5470.3 3618.6,5479.8 3619.7,5479.8 3632.7,5492.9 3632.7,5502.9 3642.2,5512.4 3655.7,5512.4 3662.6,5505.5 3673.1,5505.5 3699.1,5531.5 U1$CBB23.N1@3766.7,5531.5
$4I198\FL_IO2: R22$CBB23.1 U1$CBB23.K4 U19$CBB23.3 | length 1003.3
  Top Layer w4.7: R22$CBB23.1@3469.6,5086.1 3469.6,5115.2 3477.9,5123.5 U19$CBB23.3@3477.9,5164.6
  Inner2 w4.7: v1(3469.2,5634.9) 3577.5,5634.9 3577.7,5635.1 3591.2,5635.1 3591.4,5634.9 3695.8,5634.9 3699.6,5638.6 3744.1,5638.6 3748.8,5633.9 3853.2,5633.9 v2(3861.1,5625.9)
  Inner4 w4.7: v1(3469.2,5634.9) 3469.2,5566 3472.9,5562.3 3472.9,5547.3 3474.7,5545.5 3474.7,5120.3 v1(3470.7,5116.3)
$4I198\FL_IO3: R21$CBB23.1 U1$CBB23.L2 U19$CBB23.7 | length 561.5
  Top Layer w4.7: U19$CBB23.7@3427.9,5401.8 3427.9,5457.6 ; v1(3442.6,5457.6) 3427.9,5457.6 ; U1$CBB23.L2@3798.2,5594.5 3781.8,5578.1 3663.1,5578.1 3657.7,5572.7 3603.3,5572.7 3593.6,5563 3588.1,5563 3574,5548.9 3570.4,5548.9 3560.9,5539.4 3560.9,5535.7 3537.2,5512.1 3450.6,5512.1 3427.9,5489.4 3427.9,5457.6
  Bottom Layer w4.7: R21$CBB23.1@3399.4,5457.6 v1(3442.6,5457.6)
$4I198\HEAT_1_EN: Q1$CBB23.1 R23$CBB23.2 U1$CBB23.E16 | length 9309.7
  Top Layer w4.7: U1$CBB23.E16@4239.1,5783.4 4243.8,5778.7 4269.8,5778.7 ; 4272,5778.7 4285.6,5792.4 v1(4300.4,5792.4) ; R23$CBB23.2@4440.5,9329.8 4440.5,9312.2 v1(4467.6,9285.2) ; Q1$CBB23.1@9761.8,9582.5 9788,9582.5 v1(9801.5,9569)
  Inner2 w4.7: v1(4467.6,9285.2) 4489,9306.6 4489,9338.9 4701.3,9551.2 8267,9551.2 8277.5,9561.7 8377.7,9561.7 8436.5,9502.8 8467.6,9502.8 8526.5,9561.7 9775.4,9561.7 9782.7,9569 v1(9801.5,9569)
  Inner4 w4.7: v1(4300.4,5792.4) 4320.8,5792.4 4334.8,5778.4 4338.7,5778.4 4454.5,5894.2 4454.5,6383.4 4471.5,6400.4 4471.5,6779.9 4489.6,6798 4489.6,9244.3 ; v1(4467.6,9285.2) 4467.6,9266.3 4489.6,9244.3 ; 4489.6,9244.4 4489.6,9244.3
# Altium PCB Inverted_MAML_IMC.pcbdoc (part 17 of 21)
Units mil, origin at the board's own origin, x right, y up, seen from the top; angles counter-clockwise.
Board outline 7677.1 x 6771.6 mil, 6 copper layers (Top Layer, Inner1, Inner2, Inner3, Inner4, Bottom Layer), stack 60.7 mil thick; 2732 components, 1531 nets, 7765 pads, 3701 vias.

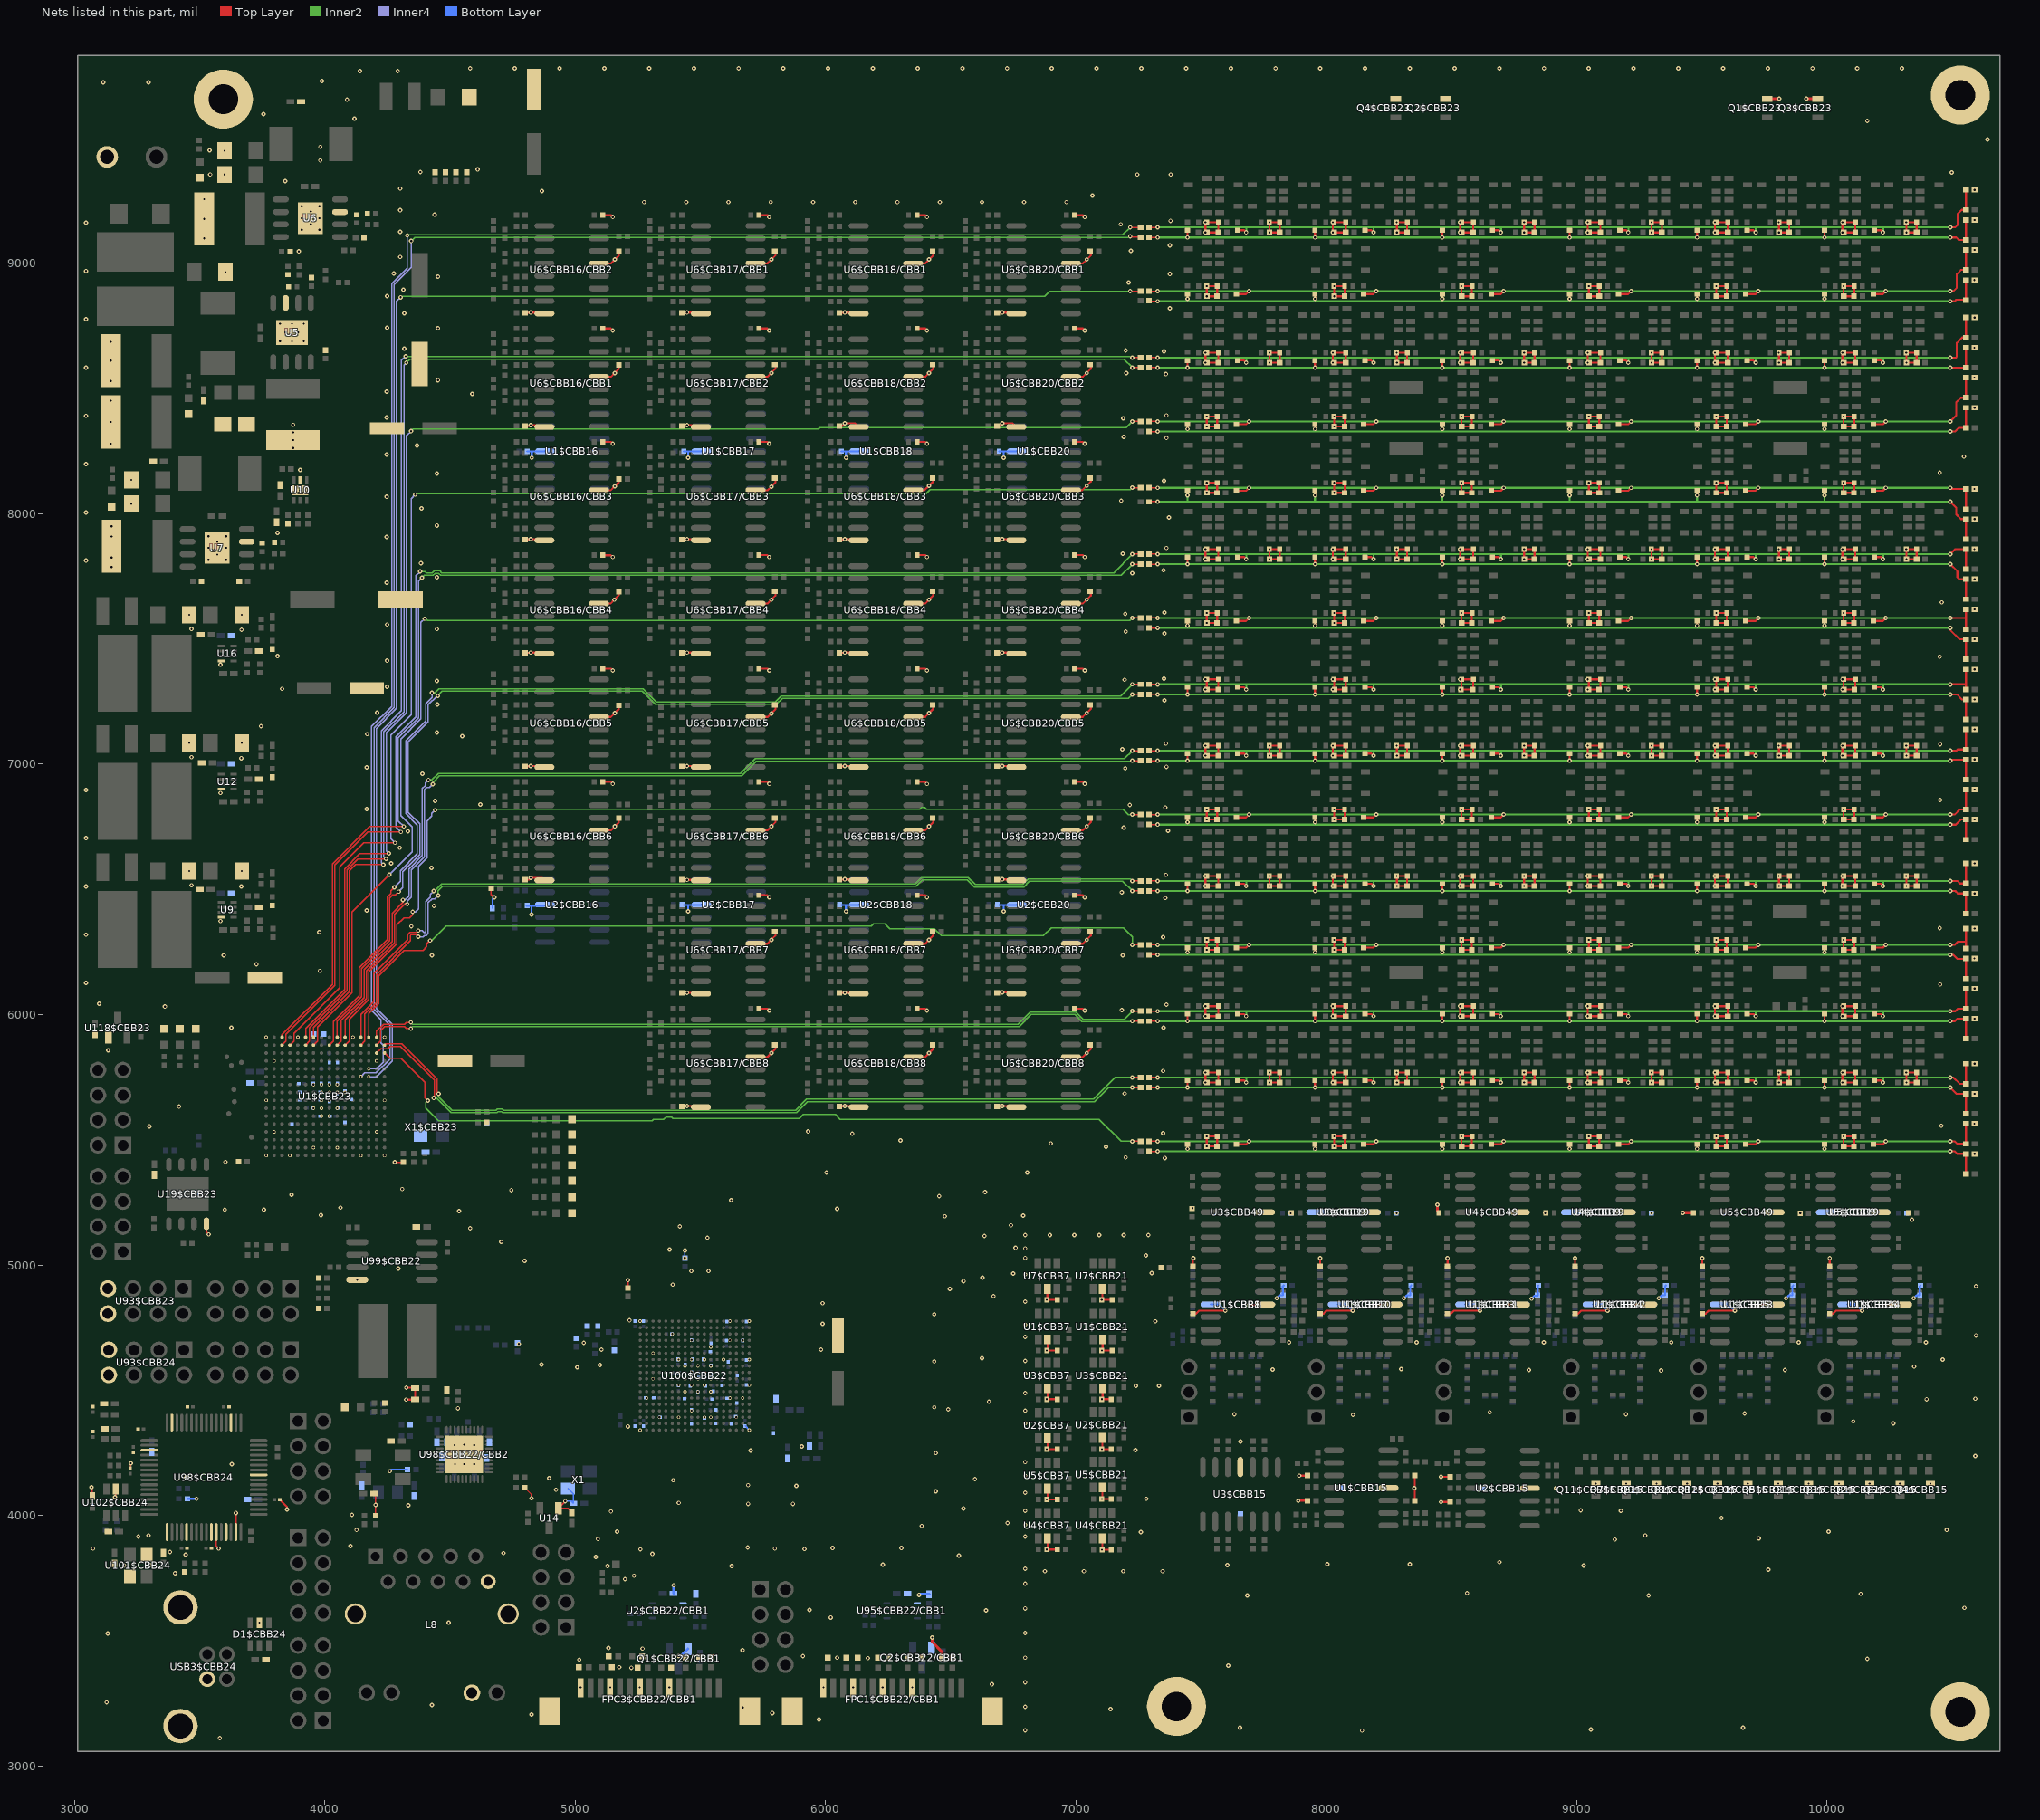
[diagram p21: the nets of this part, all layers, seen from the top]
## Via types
v1: diameter 17.7, hole 7.9, Top Layer to Bottom Layer, 3369 vias
v2: diameter 13.8, hole 7.9, Top Layer to Bottom Layer, 287 vias
v3: diameter 23.6, hole 11.8, Top Layer to Bottom Layer, 45 vias

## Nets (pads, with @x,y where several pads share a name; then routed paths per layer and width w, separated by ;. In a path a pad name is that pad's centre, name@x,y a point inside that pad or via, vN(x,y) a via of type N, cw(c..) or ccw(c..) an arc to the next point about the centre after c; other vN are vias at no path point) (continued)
GND: (continued)
  Bottom Layer w5.5: v1(4960.9,4056.9) 4984.4,4056.9 C57$CBB22.2@4993.3,4048.1 4993.3,4086.1 X1.2@4971.9,4107.5 ; R183$CBB22.1@5438.4,5026.9 v1(5438.4,5058)
  Bottom Layer w7.9: R181$CBB24.1@3451.6,4066.1 v1(3488.7,4066.1) ; C1$CBB16.1@4806,6434.4 4824.4,6434.4 ; C193$CBB16.1@4808.7,8248.7 4827.1,8248.7 ; v1(4826.4,6399.5) 4826.4,6432.4 4824.4,6434.4 ; v1(4827.1,8223.7) 4827.1,8248.7 ; U2$CBB16.11@4877.6,6435.8 4876.3,6434.4 4824.4,6434.4 ; U1$CBB16.11@4880.3,8250.1 4879,8248.7 4827.1,8248.7 ; C1$CBB17.1@5433.7,6437.7 5452.1,6437.7 ; C193$CBB17.1@5433.7,8248.7 5452.1,8248.7 ; v1(5452.1,6412.7) 5452.1,6437.7 ; v1(5452.1,8223.7) 5452.1,8248.7 ; U2$CBB17.11@5505.4,6439.1 5504,6437.7 5452.1,6437.7 ; U1$CBB17.11@5505.4,8250.1 5504,8248.7 5452.1,8248.7 ; C1$CBB18.1@6063.6,6437.7 6082.1,6437.7 ; C193$CBB18.1@6063.6,8248.7 6082.1,8248.7 ; v1(6082.1,6412.7) 6082.1,6437.7 ; v1(6082.1,8223.7) 6082.1,8248.7 ; U2$CBB18.11@6135.3,6439.1 6133.9,6437.7 6082.1,6437.7 ; U1$CBB18.11@6135.3,8250.1 6133.9,8248.7 6082.1,8248.7 ; C1$CBB20.1@6693.5,6437.7 6712,6437.7 ; C193$CBB20.1@6693.5,8248.7 6712,8248.7 ; v1(6712,6412.7) 6712,6437.7 ; v1(6712,8223.7) 6712,8248.7 ; U2$CBB20.11@6765.2,6439.1 6763.8,6437.7 6712,6437.7 ; U1$CBB20.11@6765.2,8250.1 6763.8,8248.7 6712,8248.7 ; U1$CBB8.11@7537.9,4842.6 7571.7,4842.6 v1(7597.1,4817.2) ; v1(7802.1,4867.2) 7814.1,4879.2 C193$CBB8.1@7826.9,4879.2 7826.9,4914.7 R5$CBB8.1@7829.9,4917.6 ; U1$CBB10.11@8046.6,4842.6 8080.4,4842.6 v1(8105.8,4817.2) ; v1(8310.8,4867.2) 8322.8,4879.2 C193$CBB10.1@8335.6,4879.2 8335.6,4914.7 R5$CBB10.1@8338.6,4917.6 ; U1$CBB11.11@8555.3,4842.6 8589.1,4842.6 v1(8614.5,4817.2) ; v1(8819.7,4865.5) 8831.7,4877.5 C193$CBB11.1@8844.5,4877.5 ; C193$CBB11.1@8844.3,4879.2 8844.3,4914.7 R5$CBB11.1@8847.3,4917.6 ; U1$CBB12.11@9064,4842.6 9097.8,4842.6 v1(9123.2,4817.2) ; v1(9328.2,4867.2) 9340.2,4879.2 C193$CBB12.1@9353,4879.2 9353,4914.7 R5$CBB12.1@9356,4917.6 ; U1$CBB13.11@9572.7,4842.6 9606.5,4842.6 v1(9631.9,4817.2) ; v1(9836.9,4867.2) 9848.9,4879.2 C193$CBB13.1@9861.7,4879.2 9861.7,4914.7 R5$CBB13.1@9864.7,4917.6 ; U1$CBB14.11@10081.4,4842.6 10115.2,4842.6 v1(10140.6,4817.2) ; v1(10345.6,4867.2) 10357.6,4879.2 C193$CBB14.1@10370.4,4879.2 10370.4,4914.7 R5$CBB14.1@10373.4,4917.6
  Bottom Layer w11.8: C43$CBB22/CBB1.1@5393.4,3688.5 v1(5393.4,3720.8) ; v1(5414.3,3437.5) 5422.2,3437.5 Q1$CBB22/CBB1.2@5451.7,3467 ; v1(6374.1,3682.6) 6376.8,3685.4 C59$CBB22/CBB1.1@6414.1,3685.4
  other v1: 3581.1,3110.4 8143,3140.5 6797.7,3140.9 9056.6,3144.5 7655.1,3152.6 9665,3152.6 5974.5,3184.7 4826,3204.8 5787.8,3210.8 7139.1,3226.9 5669.3,3232.9 6797.7,3234.9 4427.9,3242.3 3129.3,3253 5022.3,3313.3 5140.4,3313.3 5258.5,3313.3 5376.6,3313.3 5992.3,3313.3 6110.4,3313.3 6228.5,3313.3 6346.6,3313.3 6665.2,3325.2 6797.7,3333.3 5224.8,3391.6 5177.4,3393.5 7608.9,3399.5 5016.7,3423.6 10160.9,3427.6 6169.3,3429.6 6046.8,3431.7 6797.7,3431.7 5910.2,3437.7 5669.3,3461.8 5269.7,3467.8 5133.2,3469.8 3133.3,3528 6797.7,3530 4494.7,3572.2 6020.7,3592.3 6641.1,3620.4 5936.3,3622.4 6797.7,3628.4 10548.4,3630.4 7685.2,3680.6 9287.5,3680.6 10134.8,3686.7 8562.6,3688.7 6797.7,3726.8 5199.4,3744.9 5235.6,3758.9 3402.4,3769 6876,3777 7032.6,3777 7189.3,3777 7345.9,3777 9765.4,3783 6797.7,3787 5129.2,3797.1 5625.1,3797.1 3199.6,3799.1 9028.5,3799.1 3302,3801.1 7604.9,3801.1 6229.5,3803.1 8004.4,3805.1 8333.7,3805.1 8691.1,3813.1 5083,3834.2 6532.7,3839.3 3444.6,3843.3 5309.3,3845.9 4713.5,3849.3 3382.3,3853.3 5261,3864.7 5916.3,3865.4 3075.1,3867.4 5797.8,3867.4 6028.7,3869.4 6303.8,3869.4 5689.4,3871.4 4103.1,3877.4 9153,3903.5 5091,3905.5 9727.2,3907.5 3255.8,3915.6 6797.7,3915.6 3296.4,3919.6 9273.4,3919.6 7259.5,3933.6 5167.3,3935.6 10006.3,3935.6 4127.2,3941.7 10478.1,3941.7 6384.1,3957.7 6797.7,3961.7 6727.4,3969.8 9578.6,3989.8 4109.2,4001.9 5143.2,4015.9 6797.7,4018 9177,4018 9016.4,4020 6550.7,4028 4334.1,4040 5691.4,4046.1 5870.1,4046.1 5414.3,4050.1 7281.6,4066.1 6797.7,4090.2 6440.3,4096.3 4924.4,4102.3 5884.1,4118.3 5691.4,4120.4 9076.7,4127.3 9198.2,4127.3 9319.6,4127.3 9441.1,4127.3 9562.3,4127.3 9683.7,4127.3 9805.2,4127.3 9926.6,4127.3 10048.1,4127.3 10169.6,4127.3 10291,4127.3 10412.5,4127.3 5392.2,4140.4 6596.9,4144.4 4896.3,4148.5 3446.6,4152.5 6797.7,4158.5 3629.3,4204.7 4520.8,4204.7 4557.9,4204.8 4597.1,4204.7 6797.7,4212.7 10592.6,4236.8 4520.1,4243.2 4557.9,4243.2 4596.9,4243.2 6440.3,4248.9 5701.4,4258.9 7237.4,4260.9 5905.3,4274.6 4518.8,4281 4597.1,4281 4557.9,4282 5211.5,4355.3 6797.7,4367.3 10265.3,4367.3 10104.7,4375.4 8106.8,4401.5 7633,4403.5 9197.1,4403.5 9671,4407.5 8653,4411.5 6797.7,4417.5 6490.5,4423.5 4532.2,4427.6 6434.3,4431.6 6653.1,4453.7 10397.8,4463.7 10592.6,4465.7 6797.7,4487.8 7239.4,4517.9 7331.8,4517.9 6797.7,4566.1 9337.7,4578.1 8809.6,4580.2 9831.6,4580.2 7785.6,4582.2 8299.6,4584.2 5009,4591.9 10347.6,4594.2 5099.1,4600.2 4866.1,4602.2 6434.3,4614.3 6797.7,4616.3 10462.1,4622.3 6625,4628.3 5105.4,4662.2 5982.5,4662.5 4775.8,4684.6 5034.8,4688.6 7851.9,4690.6 8360.6,4690.6 8869.3,4690.6 9378,4690.6 9886.7,4690.6 10395.4,4690.6 6797.7,4712.7 10594.6,4718.7 6797.7,4760.9 5988.5,4764.9 7317.8,4774.9 5217.5,4778.9 6434.3,4803 5988.5,4847.2 6797.7,4853.2 6671.2,4875.3 6496.5,4903.7 10594.6,4915.5 5390.2,4921.5 6551.6,4935.6 4130,4940.8 6627,4949.6 6797.7,4961.7 6749.5,4965.7 7303.7,4967.7 5464.5,4975.7 5532.8,4975.7 4293.9,4985.7 4798.3,5015.9 5438.4,5027.9 6797.7,5027.9 7279.6,5038 5378.1,5061.3 6797.7,5066.1 6759.6,5068.1 4705.5,5092.2 5528.5,5108.2 6635.1,5116.3 6797.7,5119.4 6896.1,5119.4 6994.5,5119.4 7092.9,5119.4 7191.3,5119.4 7289.6,5119.4 4581,5146.4 5418.3,5153.4 6741.5,5158.4 10339.6,5180.5 6476.5,5194.6 6789.7,5196.6 3984.7,5198.6 7858.7,5206.3 8281.7,5207.2 8874.9,5207.2 9299.1,5207.2 9893.5,5207.2 4536.9,5214.6 3601.2,5220.7 3757.8,5220.7 6046.8,5224.7 7465.3,5227 4063,5228.7 5623.1,5258.8 6454.4,5274.9 3868.2,5280.9 6637.1,5290.9 4745.7,5299 4310,5303 6004,5369.3 6805.7,5369.3 3603.2,5411.4 7355.9,5427.5 7199.3,5429.5 10589.2,5443.7 7121,5471.7 6900.1,5485.7 6299.8,5497.8 6107,5523.9 7347.9,5525.9 5931.2,5532.8 3300,5554 10456.1,5556 10588.9,5563.7 3418.5,5632.3 7195.3,5684.5 10589.2,5683.7 7347.9,5774.8 10589.2,5803.7 3135.4,5857.2 3627.3,5947.5 7349.9,5947.5 10589.2,5983.7 7183.2,6017.8 3362.2,6031.9 7361.9,6039.9 3099.2,6043.9 10589.2,6103.7 10452,6120.2 3047,6126.2 3980.7,6174.4 3727.7,6200.5 10588.9,6223.7 3597.2,6236.7 4428.4,6236.7 7187.2,6236.7 7347.9,6308.9 3047,6319 3978.7,6329 10589.2,6343.7 10450,6345.1 4346.1,6353.1 3583.9,6373.3 4167.4,6415.4 4436.5,6433.4 7357.9,6465.6 10589.2,6483.7 7183.2,6487.6 3047,6511.7 3667.4,6512.1 3468.7,6516.1 7359.9,6557.9 3458.8,6573.3 3668.8,6573.3 4426.4,6586 4265.8,6604.1 10589.2,6603.7 4299.9,6666.3 3047,6704.5 4332,6732.6 7368,6734.6 7191.3,6746.7 10589.2,6778.7 4167.4,6820.9 7357.9,6827 7215.4,6837 4621.2,6839 4440.5,6853.1 10452,6857.1 3583.9,6885.2 3047,6897.2 10589.2,6898.7 4390.3,6961.5 7197.3,6983.6 4167.4,6987.6 7361.9,6989.6 10589.2,7018.7 3667.4,7023.9 3468.7,7028 7185.2,7059.9 10452,7080 7359.9,7082 3458.8,7085.2 3668.8,7085.2 4548.9,7112.1 4169.4,7120.1 4448.4,7126 10589.2,7138.7 3745.7,7152.2 4209.6,7206.5 4450.5,7238.6 7353.9,7254.6 10589.2,7258.7 3830.1,7300.8 4249.7,7308.9 4448.4,7332.8 7195.3,7337 7351.9,7341 10589.2,7378.7 3583.9,7397 4249.7,7413.3 10450,7429.3 3812,7431.3 10589.2,7498.7 7353.9,7521.7 7199.3,7529.7 3668,7536.3 3468.7,7539.8 4448.4,7539.6 4249.7,7557.8 3458.8,7597 3668.8,7597 7197.3,7600 7353.9,7606 10589.2,7618.7 10458.1,7646.2 4247.7,7724.5 10589.2,7738.7 4448.4,7746.5 7225.4,7762.6 7349.9,7774.7 3149.1,7787.1 4384.3,7802.8 3047,7812.8 3536.3,7816.1 3606.6,7816.1 3149.1,7825.1 3570.7,7837.3 7187.2,7840.9 10588.9,7858.7 7361.9,7863 3536.2,7863.8 3606.8,7863.8 3570.7,7888.7 4247.7,7907.2 3149.1,7909.7 3536.3,7910.4 3606.6,7910.4 3812,7923.3 3149.1,7950.3 4448.4,7953.3 10589.2,7978.7 7372,7985.5 3047,8005.6 4386.3,8021.7 3228,8040.6 7181.2,8051.8 4247.7,8067.8 3902.7,8094.1 10588.9,8098.7 7351.9,8132.1 3228,8135.6 4448.4,8160.1 10450,8164.2 3902.7,8175.3 3047,8198.3 10546.4,8228.5 4247.7,8236.5 3874.3,8262.6 4368.2,8272.6 3146.3,8280 3874.3,8294.8 7361.9,8302.8 7191.3,8306.8 3874.3,8324.8 3874.3,8355 3146.3,8366.5 7189.3,8381.1 4247.7,8385.1 3047,8391.1 7361.9,8393.1 10589.2,8423.7 3146.3,8451.3 4589.1,8479.4 4247.7,8487.5 3146.3,8530.5 4452.5,8533.7 10588.9,8543.7 7359.9,8557.8 7201.3,8561.8 3047,8583.9 3146.3,8611.5 7351.9,8648.1 7199.3,8652.1 4318,8660.2 10588.9,8663.7 3146.3,8686.9 3821.9,8689.2 3869.7,8689 3916.3,8689.2 3843.2,8725 3894.6,8725 4452.5,8740.5 4249.7,8742.5 3821.9,8759.5 3869.7,8759.5 3916.3,8759.5 3047,8776.6 10589.2,8783.7 4318,8800.7 7376,8820.8 4249.7,8869 4314,8895.1 7211.3,8923.2 10588.9,8933.7 4452.5,8947.3 7376,8957.3 4275.8,8959.3 3603.6,8965.4 3047,8969.4 4301.9,9025.6 3896.3,9047.7 7219.4,9049.7 10589.2,9053.7 7376,9071.8 3519,9099.9 4301.9,9126 3908.4,9134 3978.7,9134 3944.3,9155.7 7179.2,9156.1 3047,9162.1 7378,9170.2 10589.2,9173.7 3519,9177.4 3908.2,9180.6 3978.7,9180.6 4438.5,9194.3 3944.3,9207.1 4301.9,9212.3 3908.4,9228.4 3978.7,9228.4 5275.7,9244.4 5444.4,9244.4 5613.1,9244.4 5781.7,9244.4 5950.4,9244.4 6119.1,9244.4 6287.7,9244.4 6456.4,9244.4 6625,9244.4 6793.7,9244.4 6962.4,9244.4 3519,9256.2 7066.8,9270.6 4868.1,9288.6 10589.2,9293.7 4301.9,9298.7 3842.1,9328.8 3543,9354.9 3600.3,9354.9 7245.5,9354.9 7378.6,9354.9 10498.2,9362.9 4382.2,9364.9 4611.1,9375 3982.7,9411.1 3600.3,9449.9 3540.9,9451.3 3982.7,9465.3 10640.8,9495.4 10160.9,9569.7 4119.2,9577.8 3755.8,9595.8 4089.1,9654.1 3115.3,9722.3 3296,9722.3 3988.7,9728.3 4141.3,9768.5 4291.9,9768.5 4581,9778.5 4759.7,9778.5 4938.4,9778.5 5117.1,9778.5 5295.8,9778.5 5474.5,9778.5 5653.2,9778.5 5831.9,9778.5 6010.6,9778.5 6189.3,9778.5 6368,9778.5 6546.7,9778.5 6725.4,9778.5 6904.1,9778.5 7082.8,9778.5 7261.5,9778.5 7440.2,9778.5 7618.9,9778.5 7797.6,9778.5 7976.3,9778.5 8155,9778.5 8333.7,9778.5 8512.4,9778.5 8691.1,9778.5 8869.8,9778.5 9048.5,9778.5 9227.2,9778.5 9405.9,9778.5 9584.6,9778.5 9763.3,9778.5 9942,9778.5 10120.7,9778.5 10299.4,9778.5
  other v2: 5260.4,4340.7 5337.1,4391.9 5413.9,4391.9 5516.3,4391.9 5541.9,4391.9 5644.2,4391.9 5465.1,4417.4 5285.9,4468.6 5618.6,4468.6 5669.8,4468.6 5439.5,4494.2 5490.7,4494.2 5541.9,4494.2 5413.9,4519.8 5465.1,4519.8 5516.3,4519.8 5695.4,4519.8 5311.5,4545.4 5439.5,4545.4 5490.7,4545.4 5541.9,4545.4 5413.9,4571 5465.1,4571 5516.3,4571 5439.5,4596.6 5490.7,4596.6 5541.9,4596.6 5413.9,4622.2 5465.1,4622.2 5516.3,4622.2 5593,4622.2 5695.4,4622.2 5311.5,4647.8 5541.9,4673.3 5465.1,4698.9 5618.6,4698.9 5669.8,4698.9 5388.3,4724.5 5260.4,4775.7 5618.6,4775.7 5695.4,4775.7 3766.7,5437 3861.1,5437 4144.6,5437 4239.1,5437 3955.6,5468.5 4050.1,5468.5 3798.2,5531.5 4207.6,5531.5 3987.1,5594.5 4018.6,5594.5 3955.6,5625.9 3987.1,5625.9 4050.1,5625.9 3766.7,5657.4 3987.1,5657.4 4018.6,5657.4 4239.1,5657.4 3987.1,5688.9 4018.6,5688.9 4050.1,5688.9 4081.6,5688.9 3955.6,5720.4 3987.1,5720.4 4018.6,5720.4 4050.1,5720.4 3798.2,5814.9 4207.6,5814.9 3766.7,5909.4 3892.6,5909.4 4113.1,5909.4 4239.1,5909.4
H1+M(3): C2$CBB49/CBB1.1 C2$CBB49/CBB7.1 C2$CBB49/CBB13.1 C2$CBB49/CBB19.1 C2$CBB49/CBB25.1 C2$CBB49/CBB31.1 R2.2 R3.2 R4.2 | length 3523.7
  Top Layer w4.7: R3.2@7286.6,9103.9 7286.8,9103.7 v1(7326.2,9103.7)
  Top Layer w7.9: v1(7446.2,9103.7) C2$CBB49/CBB1.1@7446.2,9132.2 ; v1(7954.9,9103.7) C2$CBB49/CBB7.1@7954.9,9132.2 ; v1(8463.6,9103.7) C2$CBB49/CBB13.1@8463.6,9132.2 ; v1(8972.3,9103.7) C2$CBB49/CBB19.1@8972.3,9132.2 ; v1(9481,9103.7) C2$CBB49/CBB25.1@9481,9132.2 ; v1(9989.7,9103.7) C2$CBB49/CBB31.1@9989.7,9132.2 ; v1(10492.1,9103.7) 10516.5,9103.7 10526.5,9093.7 R2.2@10555.1,9093.7 R4.2@10555.1,9173.7
  Inner2 w7.9: v1(7326.2,9103.7) v1(7446.2,9103.7) v1(7954.9,9103.7) v1(8463.6,9103.7) v1(8972.3,9103.7) v1(9481,9103.7) v1(9989.7,9103.7) v1(10492.1,9103.7)
H1+M(8): C2$CBB9/CBB1.1 C2$CBB9/CBB7.1 C2$CBB9/CBB13.1 C2$CBB9/CBB19.1 C2$CBB9/CBB25.1 C2$CBB9/CBB31.1 R81.2 R82.2 R83.2 | length 3456.6
  Top Layer w4.7: R82.2@7292.6,8848.9 7326,8848.9 v1(7326.2,8848.7)
  Top Layer w7.9: v1(7446.2,8858.7) C2$CBB9/CBB1.1@7446.2,8877.2 ; v1(7954.9,8858.7) C2$CBB9/CBB7.1@7954.9,8877.2 ; v1(8463.6,8858.7) C2$CBB9/CBB13.1@8463.6,8877.2 ; v1(8972.3,8858.7) C2$CBB9/CBB19.1@8972.3,8877.2 ; v1(9481,8858.7) C2$CBB9/CBB25.1@9481,8877.2 ; v1(9989.7,8858.7) C2$CBB9/CBB31.1@9989.7,8877.2 ; v1(10492.1,8848.7) 10510.1,8848.7 10516.3,8854.9 10553.9,8854.9 R81.2@10555.1,8853.7 R83.2@10555.1,8933.7
  Inner2 w7.9: v1(7326.2,8848.7) v1(10492.1,8848.7)
H1-M(3): C4$CBB49/CBB1.1 C4$CBB49/CBB7.1 C4$CBB49/CBB13.1 C4$CBB49/CBB19.1 C4$CBB49/CBB25.1 C4$CBB49/CBB31.1 R5.2 R6.2 R7.2 | length 3743.6
  Top Layer w4.7: R6.2@7292.6,9144.1 7325.9,9144.1 v1(7326.2,9143.7)
  Top Layer w7.9: C4$CBB49/CBB1.1@7646.2,9132.2 7671.6,9132.2 v1(7680.1,9123.7) ; C4$CBB49/CBB7.1@8154.9,9132.2 8180.3,9132.2 v1(8188.8,9123.7) ; C4$CBB49/CBB13.1@8663.6,9132.2 8689,9132.2 v1(8697.5,9123.7) ; C4$CBB49/CBB19.1@9172.3,9132.2 9197.7,9132.2 v1(9206.2,9123.7) ; C4$CBB49/CBB25.1@9681,9132.2 9706.4,9132.2 v1(9714.9,9123.7) ; C4$CBB49/CBB31.1@10189.7,9132.2 10215.1,9132.2 v1(10223.6,9123.7) ; v1(10492.1,9143.7) 10512,9143.7 10522.3,9154.1 10522.3,9198.3 10537.8,9213.7 R5.2@10555.1,9213.7 R7.2@10555.1,9293.7
  Inner2 w7.9: v1(7326.2,9143.7) 7680.7,9143.7 ; v1(7680.1,9123.7) 7680.7,9124.3 7680.7,9143.7 ; v1(8188.8,9123.7) 8189.4,9124.3 8189.4,9143.7 ; v1(8697.5,9123.7) 8698.1,9124.3 8698.1,9143.7 ; v1(9206.2,9123.7) 9206.8,9124.3 9206.8,9143.7 ; v1(9714.9,9123.7) 9715.5,9124.3 9715.5,9143.7 ; v1(10223.6,9123.7) 10224.2,9124.3 10224.2,9143.7 ; v1(10492.1,9143.7) 10224.2,9143.7 ; 7680.7,9143.7 8189.4,9143.7 ; 8189.4,9143.7 9206.8,9143.7 ; 9206.8,9143.7 9715.5,9143.7 ; 9715.5,9143.7 10224.2,9143.7
H1-M(8): C4$CBB9/CBB1.1 C4$CBB9/CBB7.1 C4$CBB9/CBB13.1 C4$CBB9/CBB19.1 C4$CBB9/CBB25.1 C4$CBB9/CBB31.1 R84.2 R85.2 R86.2 | length 3738.1
  Top Layer w4.7: R85.2@7292.6,8889.1 7325.9,8889.1 v1(7326.2,8888.7)
  Top Layer w7.9: C4$CBB9/CBB1.1@7641.2,8877.2 7679.6,8877.2 v1(7691.2,8888.7) ; C4$CBB9/CBB7.1@8149.9,8877.2 8188.3,8877.2 v1(8199.9,8888.7) ; C4$CBB9/CBB13.1@8658.6,8877.2 8697,8877.2 v1(8708.6,8888.7) ; C4$CBB9/CBB19.1@9167.3,8877.2 9205.7,8877.2 v1(9217.3,8888.7) ; C4$CBB9/CBB25.1@9676,8877.2 9714.4,8877.2 v1(9726,8888.7) ; C4$CBB9/CBB31.1@10184.7,8877.2 10223.1,8877.2 v1(10234.7,8888.7) ; v1(10492.1,8888.7) 10503.9,8888.7 10518.3,8903.1 10518.3,8957.3 10534.7,8973.7 R84.2@10555.1,8973.7 R86.2@10555.1,9053.7
  Inner2 w7.9: v1(7326.2,8888.7) v1(7691.2,8888.7) v1(8199.9,8888.7) v1(8708.6,8888.7) v1(9217.3,8888.7) v1(9726,8888.7) v1(10234.7,8888.7) v1(10492.1,8888.7)
H2+M(3): C2$CBB49/CBB2.1 C2$CBB49/CBB8.1 C2$CBB49/CBB14.1 C2$CBB49/CBB20.1 C2$CBB49/CBB26.1 C2$CBB49/CBB32.1 R8.2 R9.2 R10.2 | length 3513.6
  Top Layer w4.7: R9.2@7292.6,8583.9 7326.1,8583.9 v1(7326.2,8583.7)
  Top Layer w7.9: v1(7446.2,8583.7) C2$CBB49/CBB2.1@7446.2,8612.2 ; v1(7954.9,8583.7) C2$CBB49/CBB8.1@7954.9,8612.2 ; v1(8463.6,8583.7) C2$CBB49/CBB14.1@8463.6,8612.2 ; v1(8972.3,8583.7) C2$CBB49/CBB20.1@8972.3,8612.2 ; v1(9481,8583.7) C2$CBB49/CBB26.1@9481,8612.2 ; v1(9989.7,8583.7) C2$CBB49/CBB32.1@9989.7,8612.2 ; v1(10492.1,8583.7) R8.2@10555.1,8583.7 R10.2@10555.1,8663.7
  Inner2 w7.9: v1(7326.2,8583.7) v1(7446.2,8583.7) v1(7954.9,8583.7) v1(8463.6,8583.7) v1(8972.3,8583.7) v1(9481,8583.7) v1(9989.7,8583.7) v1(10492.1,8583.7)
H2+M(8): C2$CBB9/CBB2.1 C2$CBB9/CBB8.1 C2$CBB9/CBB14.1 C2$CBB9/CBB20.1 C2$CBB9/CBB26.1 C2$CBB9/CBB32.1 R87.2 R88.2 R89.2 | length 3459.8
  Top Layer w4.7: R88.2@7292.7,8328.7 v1(7326.2,8328.7) v1@7326.3,8328.6
  Top Layer w7.9: v1(7446.2,8338.7) C2$CBB9/CBB2.1@7446.2,8357.2 ; v1(7954.9,8338.7) C2$CBB9/CBB8.1@7954.9,8357.2 ; v1(8463.6,8338.7) C2$CBB9/CBB14.1@8463.6,8357.2 ; v1(8972.3,8338.7) C2$CBB9/CBB20.1@8972.3,8357.2 ; v1(9481,8338.7) C2$CBB9/CBB26.1@9481,8357.2 ; v1(9989.7,8338.7) C2$CBB9/CBB32.1@9989.7,8357.2 ; v1(10492.1,8328.7) 10511.3,8328.7 10526.3,8343.7 R87.2@10555.1,8343.7 R89.2@10555.1,8423.7
  Inner2 w7.9: v1(7326.2,8328.7) v1(10492.1,8328.7)
H2-M(3): C4$CBB49/CBB2.1 C4$CBB49/CBB8.1 C4$CBB49/CBB14.1 C4$CBB49/CBB20.1 C4$CBB49/CBB26.1 C4$CBB49/CBB32.1 R11.2 R12.2 R13.2 | length 3753.5
  Top Layer w4.7: R12.2@7292.6,8624 7325.9,8624 v1(7326.2,8623.7)
  Top Layer w7.9: C4$CBB49/CBB2.1@7646.2,8612.2 7671.6,8612.2 v1(7680.1,8603.7) ; C4$CBB49/CBB8.1@8154.9,8612.2 8180.3,8612.2 v1(8188.8,8603.7) ; C4$CBB49/CBB14.1@8663.6,8612.2 8689,8612.2 v1(8697.5,8603.7) ; C4$CBB49/CBB20.1@9172.3,8612.2 9197.7,8612.2 v1(9206.2,8603.7) ; C4$CBB49/CBB26.1@9681,8612.2 9706.4,8612.2 v1(9714.9,8603.7) ; C4$CBB49/CBB32.1@10189.7,8612.2 10215.1,8612.2 v1(10223.6,8603.7) ; v1(10492.1,8623.7) 10514,8623.7 10518.3,8628 10518.3,8682.2 10539.8,8703.7 R11.2@10555.1,8703.7 R13.2@10555.1,8783.7
  Inner2 w7.9: v1(7326.2,8623.7) 7680.7,8623.7 ; v1(7680.1,8603.7) 7680.7,8604.3 7680.7,8623.7 ; v1(8188.8,8603.7) 8189.4,8604.3 8189.4,8623.7 ; v1(8697.5,8603.7) 8698.1,8604.3 8698.1,8623.7 ; v1(9206.2,8603.7) 9206.8,8604.3 9206.8,8623.7 ; v1(9714.9,8603.7) 9715.5,8604.3 9715.5,8623.7 ; v1(10223.6,8603.7) 10224.2,8604.3 10224.2,8623.7 ; v1(10492.1,8623.7) 10224.2,8623.7 ; 7680.7,8623.7 8189.4,8623.7 ; 8189.4,8623.7 9206.8,8623.7 ; 9206.8,8623.7 9715.5,8623.7 ; 9715.5,8623.7 10224.2,8623.7
H2-M(8): C4$CBB9/CBB2.1 C4$CBB9/CBB8.1 C4$CBB9/CBB14.1 C4$CBB9/CBB20.1 C4$CBB9/CBB26.1 C4$CBB9/CBB32.1 R90.2 R91.2 R92.2 | length 3741.1
  Top Layer w4.7: R91.2@7292.7,8368.9 7326,8368.9 v1@7326.3,8368.6
  Top Layer w7.9: C4$CBB9/CBB2.1@7641.2,8357.2 7679.6,8357.2 v1(7691.2,8368.7) ; C4$CBB9/CBB8.1@8149.9,8357.2 8188.3,8357.2 v1(8199.9,8368.7) ; C4$CBB9/CBB14.1@8658.6,8357.2 8697,8357.2 v1(8708.6,8368.7) ; C4$CBB9/CBB20.1@9167.3,8357.2 9205.7,8357.2 v1(9217.3,8368.7) ; C4$CBB9/CBB26.1@9676,8357.2 9714.4,8357.2 v1(9726,8368.7) ; C4$CBB9/CBB32.1@10184.7,8357.2 10223.1,8357.2 v1(10234.7,8368.7) ; v1(10492.1,8368.7) 10516.3,8392.9 10516.3,8445.3 10534.7,8463.7 R90.2@10555.1,8463.7 R92.2@10555.1,8543.7
  Inner2 w7.9: v1(7326.2,8368.7) v1(7691.2,8368.7) v1(8199.9,8368.7) v1(8708.6,8368.7) v1(9217.3,8368.7) v1(9726,8368.7) v1(10234.7,8368.7) v1(10492.1,8368.7)
H3+M(3): C2$CBB49/CBB3.1 C2$CBB49/CBB9.1 C2$CBB49/CBB15.1 C2$CBB49/CBB21.1 C2$CBB49/CBB27.1 C2$CBB49/CBB33.1 R14.2 R15.2 R16.2 | length 3552.5
  Top Layer w4.7: R15.2@7292.7,7798.7 v1(7326.2,7798.7) v1@7326.3,7798.6
  Top Layer w7.9: v1(7446.2,7798.7) C2$CBB49/CBB3.1@7446.2,7827.2 ; v1(7954.9,7798.7) C2$CBB49/CBB9.1@7954.9,7827.2 ; v1(8463.6,7798.7) C2$CBB49/CBB15.1@8463.6,7827.2 ; v1(8972.3,7798.7) C2$CBB49/CBB21.1@8972.3,7827.2 ; v1(9481,7798.7) C2$CBB49/CBB27.1@9481,7827.2 ; v1(9989.7,7798.7) C2$CBB49/CBB33.1@9989.7,7827.2 ; v1(10492.1,7798.7) 10520.3,7770.6 10520.3,7746.6 10528.1,7738.7 R16.2@10555.1,7738.7 R14.2@10555.1,7658.7
  Inner2 w7.9: v1(7326.2,7798.7) v1(7446.2,7798.7) v1(7954.9,7798.7) v1(8463.6,7798.7) v1(8972.3,7798.7) v1(9481,7798.7) v1(9989.7,7798.7) v1(10492.1,7798.7)
H3+M(8): C2$CBB9/CBB3.1 C2$CBB9/CBB9.1 C2$CBB9/CBB15.1 C2$CBB9/CBB21.1 C2$CBB9/CBB27.1 C2$CBB9/CBB33.1 R93.2 R94.2 R95.2 | length 3476.8
  Top Layer w4.7: R94.2@7292.7,7543.7 v1(7326.2,7543.7) v1@7326.3,7543.6
  Top Layer w7.9: v1(7446.2,7553.7) C2$CBB9/CBB3.1@7446.2,7572.2 ; v1(7954.9,7553.7) C2$CBB9/CBB9.1@7954.9,7572.2 ; v1(8463.6,7553.7) C2$CBB9/CBB15.1@8463.6,7572.2 ; v1(8972.3,7553.7) C2$CBB9/CBB21.1@8972.3,7572.2 ; v1(9481,7553.7) C2$CBB9/CBB27.1@9481,7572.2 ; v1(9989.7,7553.7) C2$CBB9/CBB33.1@9989.7,7572.2 ; v1(10492.1,7543.7) 10492.1,7535.8 10529.2,7498.7 R95.2@10555.1,7498.7 R93.2@10555.1,7418.7
  Inner2 w7.9: v1(7326.2,7543.7) v1(10492.1,7543.7)
H3-M(3): C4$CBB49/CBB3.1 C4$CBB49/CBB9.1 C4$CBB49/CBB15.1 C4$CBB49/CBB21.1 C4$CBB49/CBB27.1 C4$CBB49/CBB33.1 R17.2 R18.2 R19.2 | length 3696.9
  Top Layer w4.7: R18.2@7292.7,7838.9 7326,7838.9 v1@7326.3,7838.6
  Top Layer w7.9: C4$CBB49/CBB3.1@7646.2,7827.2 7671.6,7827.2 v1(7680.1,7818.7) ; C4$CBB49/CBB9.1@8154.9,7827.2 8180.3,7827.2 v1(8188.8,7818.7) ; C4$CBB49/CBB15.1@8663.6,7827.2 8689,7827.2 v1(8697.5,7818.7) ; C4$CBB49/CBB21.1@9172.3,7827.2 9197.7,7827.2 v1(9206.2,7818.7) ; C4$CBB49/CBB27.1@9681,7827.2 9706.4,7827.2 v1(9714.9,7818.7) ; C4$CBB49/CBB33.1@10189.7,7827.2 10215.1,7827.2 v1(10223.6,7818.7) ; v1(10492.1,7838.7) 10512.1,7858.7 R19.2@10555.1,7858.7 R17.2@10555.1,7778.7
  Inner2 w7.9: v1(7326.2,7838.7) 7680.7,7838.7 ; v1(7680.1,7818.7) 7680.7,7819.3 7680.7,7838.7 ; v1(8188.8,7818.7) 8189.4,7819.3 8189.4,7838.7 ; v1(8697.5,7818.7) 8698.1,7819.3 8698.1,7838.7 ; v1(9206.2,7818.7) 9206.8,7819.3 9206.8,7838.7 ; v1(9714.9,7818.7) 9715.5,7819.3 9715.5,7838.7 ; v1(10223.6,7818.7) 10224.2,7819.3 10224.2,7838.7 ; v1(10492.1,7838.7) 10224.2,7838.7 ; 7680.7,7838.7 8189.4,7838.7 ; 8189.4,7838.7 9206.8,7838.7 ; 9206.8,7838.7 9715.5,7838.7 ; 9715.5,7838.7 10224.2,7838.7
H3-M(8): C4$CBB9/CBB3.1 C4$CBB9/CBB9.1 C4$CBB9/CBB15.1 C4$CBB9/CBB21.1 C4$CBB9/CBB27.1 C4$CBB9/CBB33.1 R97.2 R98.2 R99.2 | length 3671.2
  Top Layer w4.7: R98.2@7292.7,7583.9 7326,7583.9 v1@7326.3,7583.6
  Top Layer w7.9: C4$CBB9/CBB3.1@7641.2,7572.2 7679.6,7572.2 v1(7691.2,7583.7) ; C4$CBB9/CBB9.1@8149.9,7572.2 8188.3,7572.2 v1(8199.9,7583.7) ; C4$CBB9/CBB15.1@8658.6,7572.2 8697,7572.2 v1(8708.6,7583.7) ; C4$CBB9/CBB21.1@9167.3,7572.2 9205.7,7572.2 v1(9217.3,7583.7) ; C4$CBB9/CBB27.1@9676,7572.2 9714.4,7572.2 v1(9726,7583.7) ; C4$CBB9/CBB33.1@10184.7,7572.2 10223.1,7572.2 v1(10234.7,7583.7) ; v1(10492.1,7583.7) 10554.6,7583.7 10555.1,7583.3 ; R97.2@10555.1,7538.7 10555.1,7583.3 ; R99.2@10555.1,7618.7 10555.1,7583.3
  Inner2 w7.9: v1(7326.2,7583.7) v1(7691.2,7583.7) v1(8199.9,7583.7) v1(8708.6,7583.7) v1(9217.3,7583.7) v1(9726,7583.7) v1(10234.7,7583.7) v1(10492.1,7583.7)
H4+M(3): C2$CBB49/CBB4.1 C2$CBB49/CBB10.1 C2$CBB49/CBB16.1 C2$CBB49/CBB22.1 C2$CBB49/CBB28.1 C2$CBB49/CBB34.1 R20.2 R21.2 R22.2 | length 3515.6
  Top Layer w4.7: R21.2@7292.7,7013.7 v1(7326.2,7013.7) v1@7326.3,7013.6
  Top Layer w7.9: v1(7446.2,7013.7) C2$CBB49/CBB4.1@7446.2,7042.2 ; v1(7954.9,7013.7) C2$CBB49/CBB10.1@7954.9,7042.2 ; v1(8463.6,7013.7) C2$CBB49/CBB16.1@8463.6,7042.2 ; v1(8972.3,7013.7) C2$CBB49/CBB22.1@8972.3,7042.2 ; v1(9481,7013.7) C2$CBB49/CBB28.1@9481,7042.2 ; v1(9989.7,7013.7) C2$CBB49/CBB34.1@9989.7,7042.2 ; v1(10492.1,7013.7) 10496.1,7017.7 10554.1,7017.7 R22.2@10555.1,7018.7 R20.2@10555.1,6938.7
  Inner2 w7.9: v1(7326.2,7013.7) v1(7446.2,7013.7) v1(7954.9,7013.7) v1(8463.6,7013.7) v1(8972.3,7013.7) v1(9481,7013.7) v1(9989.7,7013.7) v1(10492.1,7013.7)
H4+M(8): C2$CBB9/CBB4.1 C2$CBB9/CBB10.1 C2$CBB9/CBB16.1 C2$CBB9/CBB22.1 C2$CBB9/CBB28.1 C2$CBB9/CBB34.1 R100.2 R101.2 R102.2 | length 3461.8
  Top Layer w4.7: R101.2@7292.7,6758.7 v1(7326.2,6758.7) v1@7326.3,6758.6
  Top Layer w7.9: v1(7446.2,6768.7) C2$CBB9/CBB4.1@7446.2,6787.2 ; v1(7954.9,6768.7) C2$CBB9/CBB10.1@7954.9,6787.2 ; v1(8463.6,6768.7) C2$CBB9/CBB16.1@8463.6,6787.2 ; v1(8972.3,6768.7) C2$CBB9/CBB22.1@8972.3,6787.2 ; v1(9481,6768.7) C2$CBB9/CBB28.1@9481,6787.2 ; v1(9989.7,6768.7) C2$CBB9/CBB34.1@9989.7,6787.2 ; v1(10492.1,6758.7) 10514.3,6758.7 10534.3,6778.7 R102.2@10555.1,6778.7 R100.2@10555.1,6698.7
  Inner2 w7.9: v1(7326.2,6758.7) v1(10492.1,6758.7)
H4-M(3): C4$CBB49/CBB4.1 C4$CBB49/CBB10.1 C4$CBB49/CBB16.1 C4$CBB49/CBB22.1 C4$CBB49/CBB28.1 C4$CBB49/CBB34.1 R23.2 R24.2 R25.2 | length 3690.7
  Top Layer w4.7: R24.2@7292.7,7053.9 7326,7053.9 v1@7326.3,7053.6
  Top Layer w7.9: C4$CBB49/CBB4.1@7646.2,7042.2 7671.6,7042.2 v1(7680.1,7033.7) ; C4$CBB49/CBB10.1@8154.9,7042.2 8180.3,7042.2 v1(8188.8,7033.7) ; C4$CBB49/CBB16.1@8663.6,7042.2 8689,7042.2 v1(8697.5,7033.7) ; C4$CBB49/CBB22.1@9172.3,7042.2 9197.7,7042.2 v1(9206.2,7033.7) ; C4$CBB49/CBB28.1@9681,7042.2 9706.4,7042.2 v1(9714.9,7033.7) ; C4$CBB49/CBB34.1@10189.7,7042.2 10215.1,7042.2 v1(10223.6,7033.7) ; v1(10492.1,7053.7) 10516.2,7053.7 10521.2,7058.7 R23.2@10555.1,7058.7 R25.2@10555.1,7138.7
  Inner2 w7.9: v1(7326.2,7053.7) 7680.7,7053.7 ; v1(7680.1,7033.7) 7680.7,7034.3 7680.7,7053.7 ; v1(8188.8,7033.7) 8189.4,7034.3 8189.4,7053.7 ; v1(8697.5,7033.7) 8698.1,7034.3 8698.1,7053.7 ; v1(9206.2,7033.7) 9206.8,7034.3 9206.8,7053.7 ; v1(9714.9,7033.7) 9715.5,7034.3 9715.5,7053.7 ; v1(10223.6,7033.7) 10224.2,7034.3 10224.2,7053.7 ; v1(10492.1,7053.7) 10224.2,7053.7 ; 7680.7,7053.7 8189.4,7053.7 ; 8189.4,7053.7 9206.8,7053.7 ; 9206.8,7053.7 9715.5,7053.7 ; 9715.5,7053.7 10224.2,7053.7
H4-M(8): C4$CBB9/CBB4.1 C4$CBB9/CBB10.1 C4$CBB9/CBB16.1 C4$CBB9/CBB22.1 C4$CBB9/CBB28.1 C4$CBB9/CBB34.1 R103.2 R104.2 R105.2 | length 3679.3
  Top Layer w4.7: R104.2@7292.7,6798.9 7326,6798.9 v1@7326.3,6798.6
  Top Layer w7.9: C4$CBB9/CBB4.1@7641.2,6787.2 7679.6,6787.2 v1(7691.2,6798.7) ; C4$CBB9/CBB10.1@8149.9,6787.2 8188.3,6787.2 v1(8199.9,6798.7) ; C4$CBB9/CBB16.1@8658.6,6787.2 8697,6787.2 v1(8708.6,6798.7) ; C4$CBB9/CBB22.1@9167.3,6787.2 9205.7,6787.2 v1(9217.3,6798.7) ; C4$CBB9/CBB28.1@9676,6787.2 9714.4,6787.2 v1(9726,6798.7) ; C4$CBB9/CBB34.1@10184.7,6787.2 10223.1,6787.2 v1(10234.7,6798.7) ; v1(10492.1,6798.7) 10510.2,6798.7 10530.2,6818.7 R103.2@10555.1,6818.7 R105.2@10555.1,6898.7
  Inner2 w7.9: v1(7326.2,6798.7) v1(7691.2,6798.7) v1(8199.9,6798.7) v1(8708.6,6798.7) v1(9217.3,6798.7) v1(9726,6798.7) v1(10234.7,6798.7) v1(10492.1,6798.7)
H5+M(3): C2$CBB49/CBB5.1 C2$CBB49/CBB11.1 C2$CBB49/CBB17.1 C2$CBB49/CBB23.1 C2$CBB49/CBB29.1 C2$CBB49/CBB35.1 R26.2 R27.2 R28.2 | length 3517.7
  Top Layer w4.7: R27.2@7292.7,6493.7 v1(7326.2,6493.7) v1@7326.3,6493.6
  Top Layer w7.9: v1(7446.2,6493.7) C2$CBB49/CBB5.1@7446.2,6522.2 ; v1(7954.9,6493.7) C2$CBB49/CBB11.1@7954.9,6522.2 ; v1(8463.6,6493.7) C2$CBB49/CBB17.1@8463.6,6522.2 ; v1(8972.3,6493.7) C2$CBB49/CBB23.1@8972.3,6522.2 ; v1(9481,6493.7) C2$CBB49/CBB29.1@9481,6522.2 ; v1(9989.7,6493.7) C2$CBB49/CBB35.1@9989.7,6522.2 ; v1(10492.1,6493.7) 10512.2,6493.7 10522.2,6483.7 R28.2@10555.1,6483.7 R26.2@10555.1,6403.7
  Inner2 w7.9: v1(7326.2,6493.7) v1(7446.2,6493.7) v1(7954.9,6493.7) v1(8463.6,6493.7) v1(8972.3,6493.7) v1(9481,6493.7) v1(9989.7,6493.7) v1(10492.1,6493.7)
H5+M(8): C2$CBB9/CBB5.1 C2$CBB9/CBB11.1 C2$CBB9/CBB17.1 C2$CBB9/CBB23.1 C2$CBB9/CBB29.1 C2$CBB9/CBB35.1 R106.2 R107.2 R108.2 | length 3460.6
  Top Layer w4.7: R107.2@7292.7,6238.7 v1(7326.2,6238.7) v1@7326.3,6238.6
  Top Layer w7.9: v1(7446.2,6248.7) C2$CBB9/CBB5.1@7446.2,6267.2 ; v1(7954.9,6248.7) C2$CBB9/CBB11.1@7954.9,6267.2 ; v1(8463.6,6248.7) C2$CBB9/CBB17.1@8463.6,6267.2 ; v1(8972.3,6248.7) C2$CBB9/CBB23.1@8972.3,6267.2 ; v1(9481,6248.7) C2$CBB9/CBB29.1@9481,6267.2 ; v1(9989.7,6248.7) C2$CBB9/CBB35.1@9989.7,6267.2 ; v1(10492.1,6238.7) 10504.2,6238.7 10520.3,6222.6 10553.9,6222.6 R108.2@10555.1,6223.7 R106.2@10555.1,6143.7
  Inner2 w7.9: v1(7326.2,6238.7) v1(10492.1,6238.7)
H5-M(3): C4$CBB49/CBB5.1 C4$CBB49/CBB11.1 C4$CBB49/CBB17.1 C4$CBB49/CBB23.1 C4$CBB49/CBB29.1 C4$CBB49/CBB35.1 R29.2 R30.2 R31.2 | length 3692.9
  Top Layer w4.7: R30.2@7292.7,6533.9 7326,6533.9 v1@7326.3,6533.6
  Top Layer w7.9: C4$CBB49/CBB5.1@7646.2,6522.2 7671.6,6522.2 v1(7680.1,6513.7) ; C4$CBB49/CBB11.1@8154.9,6522.2 8180.3,6522.2 v1(8188.8,6513.7) ; C4$CBB49/CBB17.1@8663.6,6522.2 8689,6522.2 v1(8697.5,6513.7) ; C4$CBB49/CBB23.1@9172.3,6522.2 9197.7,6522.2 v1(9206.2,6513.7) ; C4$CBB49/CBB29.1@9681,6522.2 9706.4,6522.2 v1(9714.9,6513.7) ; C4$CBB49/CBB35.1@10189.7,6522.2 10215.1,6522.2 v1(10223.6,6513.7) ; v1(10492.1,6533.7) 10492.2,6533.8 10520.3,6533.8 10530.4,6523.7 R29.2@10555.1,6523.7 R31.2@10555.1,6603.7
  Inner2 w7.9: v1(7326.2,6533.7) 7680.7,6533.7 ; v1(7680.1,6513.7) 7680.7,6514.3 7680.7,6533.7 ; v1(8188.8,6513.7) 8189.4,6514.3 8189.4,6533.7 ; v1(8697.5,6513.7) 8698.1,6514.3 8698.1,6533.7 ; v1(9206.2,6513.7) 9206.8,6514.3 9206.8,6533.7 ; v1(9714.9,6513.7) 9715.5,6514.3 9715.5,6533.7 ; v1(10223.6,6513.7) 10224.2,6514.3 10224.2,6533.7 ; v1(10492.1,6533.7) 10224.2,6533.7 ; 7680.7,6533.7 8189.4,6533.7 ; 8189.4,6533.7 9206.8,6533.7 ; 9206.8,6533.7 9715.5,6533.7 ; 9715.5,6533.7 10224.2,6533.7
H5-M(8): C4$CBB9/CBB5.1 C4$CBB9/CBB11.1 C4$CBB9/CBB17.1 C4$CBB9/CBB23.1 C4$CBB9/CBB29.1 C4$CBB9/CBB35.1 R109.2 R110.2 R111.2 | length 3677.1
  Top Layer w4.7: R110.2@7292.7,6278.9 7326,6278.9 v1@7326.3,6278.6
  Top Layer w7.9: C4$CBB9/CBB5.1@7641.2,6267.2 7679.6,6267.2 v1(7691.2,6278.7) ; C4$CBB9/CBB11.1@8149.9,6267.2 8188.3,6267.2 v1(8199.9,6278.7) ; C4$CBB9/CBB17.1@8658.6,6267.2 8697,6267.2 v1(8708.6,6278.7) ; C4$CBB9/CBB23.1@9167.3,6267.2 9205.7,6267.2 v1(9217.3,6278.7) ; C4$CBB9/CBB29.1@9676,6267.2 9714.4,6267.2 v1(9726,6278.7) ; C4$CBB9/CBB35.1@10184.7,6267.2 10223.1,6267.2 v1(10234.7,6278.7) ; v1(10492.1,6278.7) 10510.2,6278.7 10522.3,6290.9 10552.7,6290.9 10555.1,6293.3 ; R109.2@10555.1,6263.7 10555.1,6293.3 ; R111.2@10555.1,6343.7 10555.1,6293.3
  Inner2 w7.9: v1(7326.2,6278.7) v1(7691.2,6278.7) v1(8199.9,6278.7) v1(8708.6,6278.7) v1(9217.3,6278.7) v1(9726,6278.7) v1(10234.7,6278.7) v1(10492.1,6278.7)
H6+M(3): C2$CBB49/CBB6.1 C2$CBB49/CBB12.1 C2$CBB49/CBB18.1 C2$CBB49/CBB24.1 C2$CBB49/CBB30.1 C2$CBB49/CBB36.1 R32.2 R33.2 R34.2 | length 3523.9
  Top Layer w4.7: R33.2@7292.7,5708.7 v1(7326.2,5708.7) v1@7326.3,5708.6
  Top Layer w7.9: v1(7446.2,5708.7) C2$CBB49/CBB6.1@7446.2,5737.2 ; v1(7954.9,5708.7) C2$CBB49/CBB12.1@7954.9,5737.2 ; v1(8463.6,5708.7) C2$CBB49/CBB18.1@8463.6,5737.2 ; v1(8972.3,5708.7) C2$CBB49/CBB24.1@8972.3,5737.2 ; v1(9481,5708.7) C2$CBB49/CBB30.1@9481,5737.2 ; v1(9989.7,5708.7) C2$CBB49/CBB36.1@9989.7,5737.2 ; v1(10492.1,5708.7) 10517.1,5683.7 R34.2@10555.1,5683.7 R32.2@10555.1,5603.7
  Inner2 w7.9: v1(7326.2,5708.7) v1(7446.2,5708.7) v1(7954.9,5708.7) v1(8463.6,5708.7) v1(8972.3,5708.7) v1(9481,5708.7) v1(9989.7,5708.7) v1(10492.1,5708.7)
H6+M(8): C2$CBB9/CBB6.1 C2$CBB9/CBB12.1 C2$CBB9/CBB18.1 C2$CBB9/CBB24.1 C2$CBB9/CBB30.1 C2$CBB9/CBB36.1 R112.2 R113.2 R114.2 | length 3457.7
  Top Layer w4.7: R113.2@7292.7,5453.7 v1(7326.2,5453.7) v1@7326.3,5453.6
  Top Layer w7.9: v1(7446.2,5463.7) C2$CBB9/CBB6.1@7446.2,5482.2 ; v1(7954.9,5463.7) C2$CBB9/CBB12.1@7954.9,5482.2 ; v1(8463.6,5463.7) C2$CBB9/CBB18.1@8463.6,5482.2 ; v1(8972.3,5463.7) C2$CBB9/CBB24.1@8972.3,5482.2 ; v1(9481,5463.7) C2$CBB9/CBB30.1@9481,5482.2 ; v1(9989.7,5463.7) C2$CBB9/CBB36.1@9989.7,5482.2 ; v1(10492.1,5453.7) 10510.1,5453.7 10520.1,5443.7 R114.2@10555.1,5443.7 R112.2@10555.1,5363.7
  Inner2 w7.9: v1(7326.2,5453.7) v1(10492.1,5453.7)
H6-M(3): C4$CBB49/CBB6.1 C4$CBB49/CBB12.1 C4$CBB49/CBB18.1 C4$CBB49/CBB24.1 C4$CBB49/CBB30.1 C4$CBB49/CBB36.1 R35.2 R36.2 R37.2 | length 3699
  Top Layer w4.7: R36.2@7292.7,5748.9 7326,5748.9 v1@7326.3,5748.6
  Top Layer w7.9: C4$CBB49/CBB6.1@7646.2,5737.2 7671.6,5737.2 v1(7680.1,5728.7) ; C4$CBB49/CBB12.1@8154.9,5737.2 8180.3,5737.2 v1(8188.8,5728.7) ; C4$CBB49/CBB18.1@8663.6,5737.2 8689,5737.2 v1(8697.5,5728.7) ; C4$CBB49/CBB24.1@9172.3,5737.2 9197.7,5737.2 v1(9206.2,5728.7) ; C4$CBB49/CBB30.1@9681,5737.2 9706.4,5737.2 v1(9714.9,5728.7) ; C4$CBB49/CBB36.1@10189.7,5737.2 10215.1,5737.2 v1(10223.6,5728.7) ; v1(10492.1,5748.7) 10504.3,5748.7 10529.3,5723.7 R35.2@10555.1,5723.7 R37.2@10555.1,5803.7
  Inner2 w7.9: v1(7326.2,5748.7) 7680.7,5748.7 ; v1(7680.1,5728.7) 7680.7,5729.3 7680.7,5748.7 ; v1(8188.8,5728.7) 8189.4,5729.3 8189.4,5748.7 ; v1(8697.5,5728.7) 8698.1,5729.3 8698.1,5748.7 ; v1(9206.2,5728.7) 9206.8,5729.3 9206.8,5748.7 ; v1(9714.9,5728.7) 9715.5,5729.3 9715.5,5748.7 ; v1(10223.6,5728.7) 10224.2,5729.3 10224.2,5748.7 ; v1(10492.1,5748.7) 10224.2,5748.7 ; 7680.7,5748.7 8189.4,5748.7 ; 8189.4,5748.7 9206.8,5748.7 ; 9206.8,5748.7 9715.5,5748.7 ; 9715.5,5748.7 10224.2,5748.7
H6-M(8): C4$CBB9/CBB6.1 C4$CBB9/CBB12.1 C4$CBB9/CBB18.1 C4$CBB9/CBB24.1 C4$CBB9/CBB30.1 C4$CBB9/CBB36.1 R115.2 R116.2 R117.2 | length 3675.2
  Top Layer w4.7: R116.2@7292.7,5493.9 7326,5493.9 v1@7326.3,5493.6
  Top Layer w7.9: C4$CBB9/CBB6.1@7641.2,5482.2 7679.6,5482.2 v1(7691.2,5493.7) ; C4$CBB9/CBB12.1@8149.9,5482.2 8188.3,5482.2 v1(8199.9,5493.7) ; C4$CBB9/CBB18.1@8658.6,5482.2 8697,5482.2 v1(8708.6,5493.7) ; C4$CBB9/CBB24.1@9167.3,5482.2 9205.7,5482.2 v1(9217.3,5493.7) ; C4$CBB9/CBB30.1@9676,5482.2 9714.4,5482.2 v1(9726,5493.7) ; C4$CBB9/CBB36.1@10184.7,5482.2 10223.1,5482.2 v1(10234.7,5493.7) ; v1(10492.1,5493.7) 10510.3,5493.7 10520.3,5483.7 R115.2@10555.1,5483.7 R117.2@10555.1,5563.7
  Inner2 w7.9: v1(7326.2,5493.7) v1(7691.2,5493.7) v1(8199.9,5493.7) v1(8708.6,5493.7) v1(9217.3,5493.7) v1(9726,5493.7) v1(10234.7,5493.7) v1(10492.1,5493.7)
H7+M(3): C2$CBB49/CBB37.1 C2$CBB49/CBB38.1 C2$CBB49/CBB39.1 C2$CBB49/CBB40.1 C2$CBB49/CBB41.1 C2$CBB49/CBB42.1 R38.2 R39.2 R40.2 | length 3517.7
  Top Layer w4.7: R39.2@7292.7,5973.7 v1(7326.2,5973.7) v1@7326.3,5973.6
  Top Layer w7.9: v1(7446.2,5973.7) C2$CBB49/CBB37.1@7446.2,6002.2 ; v1(7954.9,5973.7) C2$CBB49/CBB38.1@7954.9,6002.2 ; v1(8463.6,5973.7) C2$CBB49/CBB39.1@8463.6,6002.2 ; v1(8972.3,5973.7) C2$CBB49/CBB40.1@8972.3,6002.2 ; v1(9481,5973.7) C2$CBB49/CBB41.1@9481,6002.2 ; v1(9989.7,5973.7) C2$CBB49/CBB42.1@9989.7,6002.2 ; v1(10492.1,5973.7) 10510.4,5973.7 10520.4,5983.7 R40.2@10555.1,5983.7 R38.2@10555.1,5903.7
  Inner2 w7.9: v1(7326.2,5973.7) v1(7446.2,5973.7) v1(7954.9,5973.7) v1(8463.6,5973.7) v1(8972.3,5973.7) v1(9481,5973.7) v1(9989.7,5973.7) v1(10492.1,5973.7)
H7+M(8): C2$CBB9/CBB37.1 C2$CBB9/CBB38.1 C2$CBB9/CBB39.1 C2$CBB9/CBB40.1 C2$CBB9/CBB41.1 C2$CBB9/CBB42.1 R118.2 R119.2 R120.2 | length 3648.4
  Top Layer w4.7: R119.2@7292.6,8049 7325.9,8049 v1(7326.2,8048.7)
  Top Layer w7.9: v1(7446.2,8073.7) C2$CBB9/CBB37.1@7446.2,8092.2 ; v1(7954.9,8073.7) C2$CBB9/CBB38.1@7954.9,8092.2 ; v1(8463.6,8073.7) C2$CBB9/CBB39.1@8463.6,8092.2 ; v1(8972.3,8073.7) C2$CBB9/CBB40.1@8972.3,8092.2 ; v1(9481,8073.7) C2$CBB9/CBB41.1@9481,8092.2 ; v1(9989.7,8073.7) C2$CBB9/CBB42.1@9989.7,8092.2 ; v1(10492.1,8048.7) 10492.1,8047.8 10516.3,8023.7 10516.3,7997.6 10535.1,7978.7 R120.2@10555.1,7978.7 R118.2@10555.1,7898.7
  Inner2 w7.9: v1(7326.2,8048.7) 7446.2,8048.7 ; v1(7446.2,8073.7) 7446.2,8048.7 ; v1(7954.9,8073.7) 7954.9,8048.7 ; v1(8463.6,8073.7) 8463.6,8048.7 ; v1(8972.3,8073.7) 8972.3,8048.7 ; v1(9481,8073.7) 9481,8048.7 ; v1(9989.7,8073.7) 9989.7,8048.7 ; v1(10492.1,8048.7) 9989.7,8048.7 ; 7446.2,8048.7 7954.9,8048.7 ; 7954.9,8048.7 8463.6,8048.7 ; 8463.6,8048.7 8972.3,8048.7 ; 8972.3,8048.7 9481,8048.7 ; 9481,8048.7 9989.7,8048.7
H7-M(3): C4$CBB49/CBB37.1 C4$CBB49/CBB38.1 C4$CBB49/CBB39.1 C4$CBB49/CBB40.1 C4$CBB49/CBB41.1 C4$CBB49/CBB42.1 R41.2 R42.2 R43.2 | length 3692.9
  Top Layer w4.7: R42.2@7292.7,6013.9 7326,6013.9 v1@7326.3,6013.6
  Top Layer w7.9: C4$CBB49/CBB37.1@7646.2,6002.2 7671.6,6002.2 v1(7680.1,5993.7) ; C4$CBB49/CBB38.1@8154.9,6002.2 8180.3,6002.2 v1(8188.8,5993.7) ; C4$CBB49/CBB39.1@8663.6,6002.2 8689,6002.2 v1(8697.5,5993.7) ; C4$CBB49/CBB40.1@9172.3,6002.2 9197.7,6002.2 v1(9206.2,5993.7) ; C4$CBB49/CBB41.1@9681,6002.2 9706.4,6002.2 v1(9714.9,5993.7) ; C4$CBB49/CBB42.1@10189.7,6002.2 10215.1,6002.2 v1(10223.6,5993.7) ; v1(10492.1,6013.7) 10512.2,6013.7 10522.3,6023.8 10555,6023.8 R41.2@10555.1,6023.7 R43.2@10555.1,6103.7
  Inner2 w7.9: v1(7326.2,6013.7) 7680.7,6013.7 ; v1(7680.1,5993.7) 7680.7,5994.3 7680.7,6013.7 ; v1(8188.8,5993.7) 8189.4,5994.3 8189.4,6013.7 ; v1(8697.5,5993.7) 8698.1,5994.3 8698.1,6013.7 ; v1(9206.2,5993.7) 9206.8,5994.3 9206.8,6013.7 ; v1(9714.9,5993.7) 9715.5,5994.3 9715.5,6013.7 ; v1(10223.6,5993.7) 10224.2,5994.3 10224.2,6013.7 ; v1(10492.1,6013.7) 10224.2,6013.7 ; 7680.7,6013.7 8189.4,6013.7 ; 8189.4,6013.7 8698.1,6013.7 ; 8698.1,6013.7 9206.8,6013.7 ; 9206.8,6013.7 9715.5,6013.7 ; 9715.5,6013.7 10224.2,6013.7
H7-M(8): C4$CBB9/CBB37.1 C4$CBB9/CBB38.1 C4$CBB9/CBB39.1 C4$CBB9/CBB40.1 C4$CBB9/CBB41.1 C4$CBB9/CBB42.1 R121.2 R122.2 R123.2 | length 3673.1
  Top Layer w4.7: R122.2@7292.6,8104 7325.9,8104 v1(7326.2,8103.7)
  Top Layer w7.9: C4$CBB9/CBB37.1@7641.2,8092.2 7679.6,8092.2 v1(7691.2,8103.7) ; C4$CBB9/CBB38.1@8149.9,8092.2 8188.3,8092.2 v1(8199.9,8103.7) ; C4$CBB9/CBB39.1@8658.6,8092.2 8697,8092.2 v1(8708.6,8103.7) ; C4$CBB9/CBB40.1@9167.3,8092.2 9205.7,8092.2 v1(9217.3,8103.7) ; C4$CBB9/CBB41.1@9676,8092.2 9714.4,8092.2 v1(9726,8103.7) ; C4$CBB9/CBB42.1@10184.7,8092.2 10223.1,8092.2 v1(10234.7,8103.7) ; v1(10492.1,8103.7) 10497.1,8098.7 R123.2@10555.1,8098.7 R121.2@10555.1,8018.7
  Inner2 w7.9: v1(7326.2,8103.7) v1(7691.2,8103.7) v1(8199.9,8103.7) v1(8708.6,8103.7) v1(9217.3,8103.7) v1(9726,8103.7) v1(10234.7,8103.7) v1(10492.1,8103.7)
H8+M(3): C2$CBB49/CBB43.1 C2$CBB49/CBB44.1 C2$CBB49/CBB45.1 C2$CBB49/CBB46.1 C2$CBB49/CBB47.1 C2$CBB49/CBB48.1 R44.2 R62.2 R63.2 | length 3521.8
  Top Layer w4.7: R62.2@7292.7,7278.7 v1(7326.2,7278.7) v1@7326.3,7278.6
  Top Layer w7.9: v1(7446.2,7278.7) C2$CBB49/CBB43.1@7446.2,7307.2 ; v1(7954.9,7278.7) C2$CBB49/CBB44.1@7954.9,7307.2 ; v1(8463.6,7278.7) C2$CBB49/CBB45.1@8463.6,7307.2 ; v1(8972.3,7278.7) C2$CBB49/CBB46.1@8972.3,7307.2 ; v1(9481,7278.7) C2$CBB49/CBB47.1@9481,7307.2 ; v1(9989.7,7278.7) C2$CBB49/CBB48.1@9989.7,7307.2 ; v1(10492.1,7278.7) 10518.3,7278.7 10538.3,7258.7 R63.2@10555.1,7258.7 R44.2@10555.1,7178.7
  Inner2 w7.9: v1(7326.2,7278.7) v1(7446.2,7278.7) v1(7954.9,7278.7) v1(8463.6,7278.7) v1(8972.3,7278.7) v1(9481,7278.7) v1(9989.7,7278.7) v1(10492.1,7278.7)
H8-M(3): C4$CBB49/CBB43.1 C4$CBB49/CBB44.1 C4$CBB49/CBB45.1 C4$CBB49/CBB46.1 C4$CBB49/CBB47.1 C4$CBB49/CBB48.1 R74.2 R79.2 R80.2 | length 3688.9
  Top Layer w4.7: R79.2@7292.7,7318.9 7326,7318.9 v1@7326.3,7318.6
  Top Layer w7.9: C4$CBB49/CBB43.1@7646.2,7307.2 7671.6,7307.2 v1(7680.1,7298.7) ; C4$CBB49/CBB44.1@8154.9,7307.2 8180.3,7307.2 v1(8188.8,7298.7) ; C4$CBB49/CBB45.1@8663.6,7307.2 8689,7307.2 v1(8697.5,7298.7) ; C4$CBB49/CBB46.1@9172.3,7307.2 9197.7,7307.2 v1(9206.2,7298.7) ; C4$CBB49/CBB47.1@9681,7307.2 9706.4,7307.2 v1(9714.9,7298.7) ; C4$CBB49/CBB48.1@10189.7,7307.2 10215.1,7307.2 v1(10223.6,7298.7) ; v1(10492.1,7318.7) 10554.3,7318.7 10555.1,7318 ; R74.2@10555.1,7298.7 10555.1,7318 ; R80.2@10555.1,7378.7 10555.1,7318
  Inner2 w7.9: v1(7326.2,7318.7) 7680.7,7318.7 ; v1(7680.1,7298.7) 7680.7,7299.3 7680.7,7318.7 ; v1(8188.8,7298.7) 8189.4,7299.3 8189.4,7318.7 ; v1(8697.5,7298.7) 8698.1,7299.3 8698.1,7318.7 ; v1(9206.2,7298.7) 9206.8,7299.3 9206.8,7318.7 ; v1(9714.9,7298.7) 9715.5,7299.3 9715.5,7318.7 ; v1(10223.6,7298.7) 10224.2,7299.3 10224.2,7318.7 ; v1(10492.1,7318.7) 10224.2,7318.7 ; 7680.7,7318.7 8189.4,7318.7 ; 8189.4,7318.7 8698.1,7318.7 ; 8698.1,7318.7 9206.8,7318.7 ; 9206.8,7318.7 9715.5,7318.7 ; 9715.5,7318.7 10224.2,7318.7
H_M3_N1: R6.1 U1$CBB23.E14 | length 6391.3
  Top Layer w4.7: v1(7217.4,9144.1) R6.1@7258.6,9144.1
  Inner2 w4.7: v1(4329.6,9111.9) 4331.6,9113.9 7187.2,9113.9 v1(7217.4,9144.1)
  Inner4 w4.7: v2(4176.1,5783.4) 4207.4,5783.4 4216.4,5792.5 4216.9,5792.5 4233.7,5809.2 4233.7,5877.2 4224.8,5886.1 4224.8,5979.2 4187.5,6016.6 4187.5,7150.2 4267.8,7230.6 4267.8,8919.2 4329.6,8980.9 v1(4329.6,9111.9)
H_M3_N2: R12.1 U1$CBB23.A7 | length 5880.4
  Top Layer w4.7: U1$CBB23.A7@3955.6,5909.4 3955.6,5948.7 4098.9,6091.9 4098.9,6573.7 4124,6598.9 v1(4234.2,6598.9) ; v1(7225.4,8624) R12.1@7258.6,8624
  Inner2 w4.7: v1(4322.9,8628.9) 4324,8627.7 7221.7,8627.7 v1(7225.4,8624)
  Inner4 w4.7: v1(4234.2,6598.9) 4226.4,6606.7 4226.4,7133.2 4306.7,7213.5 4306.7,8612.7 v1(4322.9,8628.9)
H_M3_N3: R18.1 U1$CBB23.B3 | length 5130.8
  Top Layer w4.7: U1$CBB23.B3@3829.6,5877.9 3845.5,5893.8 3845.5,5921.1 4040.6,6116.1 4040.6,6597.9 4172.2,6729.6 v1(4304.6,6729.6) ; v1(7225.5,7838.9) R18.1@7258.7,7838.9
  Inner2 w4.7: v1(4381.4,7769.5) 4401.5,7769.5 4406.3,7764.6 4429.9,7764.6 4437.7,7772.4 4459.2,7772.4 4467,7764.6 7151.3,7764.6 v1(7225.5,7838.9)
  Inner4 w4.7: v1(4304.6,6729.6) 4284.7,6749.5 4284.7,7109 4365,7189.4 4365,7753.2 v1(4381.4,7769.5)
H_M3_N4: R24.1 U1$CBB23.B10 | length 4108.9
  Top Layer w4.7: U1$CBB23.B10@4050.1,5877.9 4066,5893.8 4066,5976.5 4157.2,6067.8 4157.2,6179.1 4269.5,6291.4 4269.5,6404.7 4314,6449.2 4314,6456.6 v1(4312.4,6458.1) ; v1(7225.5,7053.9) R24.1@7258.7,7053.9
  Inner2 w4.7: v1(4414.8,6937.2) 4428.1,6937.2 4454.4,6963.5 5661.3,6963.5 5719.5,7021.7 7193.3,7021.7 v1(7225.5,7053.9)
  Inner4 w4.7: v1(4312.4,6458.1) 4320.9,6458.1 4336.3,6473.5 4336.3,6581.4 4389.5,6634.7 4389.5,6902.2 4401.5,6914.2 4401.5,6923.9 v1(4414.8,6937.2)
H_M3_N5: R30.1 U1$CBB23.A13 | length 3616.2
  Top Layer w4.7: U1$CBB23.A13@4144.6,5909.4 4144.6,6000.1 4196.1,6051.7 4196.1,6163 4332,6298.9 4332,6319 4341.1,6328 4367.2,6328 4374.2,6335 v1(4374.2,6335.5) ; v1(7225.5,6533.9) R30.1@7258.7,6533.9
  Inner2 w4.7: v1(4435.7,6493.4) 4438.2,6493.4 4466.6,6521.8 6358.3,6521.8 6384.1,6547.6 6570.8,6547.6 6598.6,6519.8 6788,6519.8 6809.8,6541.5 7217.9,6541.5 v1(7225.5,6533.9)
  Inner4 w4.7: v1(4374.2,6335.5) 4389.8,6335.5 4398.9,6326.4 4403.9,6331.4 4403.9,6451 4422.4,6469.6 4422.4,6480.1 v1(4435.7,6493.4)
H_M3_N6: R36.1 U1$CBB23.B16 | length 3226.9
  Top Layer w4.7: U1$CBB23.B16@4239.1,5877.9 4244.8,5883.6 4307.6,5883.6 4448.2,5743 4448.2,5690.5 v1(4454.7,5684) ; v1(7225.5,5748.9) R36.1@7258.7,5748.9
  Inner2 w4.7: v1(4454.7,5684) 4454.7,5672.3 4508.7,5618.2 4684.9,5618.2 4688.7,5622.1 4710.2,5622.1 4714.1,5618.2 5880.4,5618.2 5924.6,5662.4 7071.1,5662.4 7157.6,5748.9 v1(7225.5,5748.9)
H_M3_N7: R42.1 U1$CBB23.A15 | length 3137.7
  Top Layer w4.7: U1$CBB23.A15@4207.6,5909.4 4207.6,5933.5 4235.4,5961.3 4318,5961.3 4325.4,5968.7 v1(4344.3,5968.7) ; v1(7225.5,6013.9) R42.1@7258.7,6013.9
  Inner2 w4.7: v1(4344.3,5968.7) 4351.4,5961.6 6769.6,5961.6 6817.8,6009.8 7000.5,6009.8 7028.6,5981.7 7193.3,5981.7 v1(7225.5,6013.9)
H_M3_N8: R79.1 U1$CBB23.B9 | length 4502.5
  Top Layer w4.7: U1$CBB23.B9@4018.6,5877.9 4034.5,5893.8 4034.5,5972.5 4137.8,6075.8 4137.8,6187.2 4250,6299.4 4250,6469.6 4264.9,6484.5 4264.9,6495 v1(4278.3,6508.3) ; v1(7225.5,7318.9) R79.1@7258.7,7318.9
  Inner2 w4.7: v1(4428.4,7284.8) 4440.5,7284.8 4456.5,7300.8 5271.7,7300.8 5323.9,7248.6 5799.8,7248.6 5823.9,7272.7 7179.3,7272.7 v1(7225.5,7318.9)
  Inner4 w4.7: v1(4278.3,6508.3) 4302.1,6532.2 4302.1,6574.8 4370.1,6642.8 4370.1,6757 4324,6803.1 4324,6812.1 4324.1,6812.2 4324.1,7093.4 4403.9,7173.3 4403.9,7241.9 4428.4,7266.4 v1(4428.4,7284.8)
H_M3_P1: R3.1 U1$CBB23.F13 | length 6421.1
  Top Layer w4.7: v1(7217.4,9107.5) 7218.9,9105.9 R3.1@7258.6,9105.9
  Inner2 w4.7: v1(4345.8,9089.3) 4360.7,9104.2 7214.1,9104.2 v1(7217.4,9107.5)
  Inner4 w4.7: v2(4144.6,5751.9) 4159.5,5766.8 4205.6,5766.8 4260.4,5821.7 4260.4,5957.4 4197.2,6020.6 4197.2,7146.2 4277.5,7226.5 4277.5,8915.1 4345.8,8983.4 v1(4345.8,9089.3)
H_M3_P2: R9.1 U1$CBB23.B6 | length 5918.2
  Top Layer w4.7: U1$CBB23.B6@3924.1,5877.9 3940,5893.8 3940,5946.8 4089.2,6096 4089.2,6577.8 4132.9,6621.5 v1(4245.1,6621.5) ; v1(7225.4,8583.9) R9.1@7258.6,8583.9
  Inner2 w4.7: v1(4326,8603.9) 4340.1,8618 7191.3,8618 v1(7225.4,8583.9)
  Inner4 w4.7: v1(4245.1,6621.5) 4236.1,6630.5 4236.1,7129.2 4316.4,7209.5 4316.4,8594.3 v1(4326,8603.9)
H_M3_P3: R15.1 U1$CBB23.A3 | length 5064.4
  Top Layer w4.7: U1$CBB23.A3@3829.6,5909.4 3829.6,5918.9 4030.8,6120.1 4030.8,6601.9 4180.1,6751.2 v1(4316.5,6751.2) ; v1(7225.5,7798.7) R15.1@7258.7,7798.7
  Inner2 w4.7: v1(4388.3,7744.6) 4398.3,7754.6 4433.7,7754.6 4441.7,7762.7 4455.2,7762.7 4463.2,7754.6 7181.4,7754.6 v1(7225.5,7798.7)
  Inner4 w4.7: v1(4316.5,6751.2) 4294.4,6773.3 4294.4,7105 4374.8,7185.3 4374.8,7731.1 v1(4388.3,7744.6)
H_M3_P4: R21.1 U1$CBB23.A11 | length 4040.1
  Top Layer w4.7: U1$CBB23.A11@4081.6,5909.4 4081.6,5978.4 4167,6063.7 4167,6175.1 4279.2,6287.4 4279.2,6400.7 4322,6443.5 4327.1,6443.5 v1(4329.8,6440.7) ; v1(7225.5,7013.7) R21.1@7258.7,7013.7
  Inner2 w4.7: v1(4432.2,6920.6) 4432.2,6927.1 4458.5,6953.5 5663.3,6953.5 5663.6,6953.8 5665.3,6953.8 5723.5,7012 7223.8,7012 v1(7225.5,7013.7)
  Inner4 w4.7: v1(4329.8,6440.7) 4329.8,6453.3 4346,6469.5 4346,6577.4 4399.3,6630.6 4399.3,6898.2 4408.3,6907.3 4418.9,6907.3 v1(4432.2,6920.6)
H_M3_P5: R27.1 U1$CBB23.B13 | length 3653.6
  Top Layer w4.7: U1$CBB23.B13@4144.6,5877.9 4160.5,5893.8 4160.5,6002.2 4205.9,6047.6 4205.9,6159 4341.8,6294.9 4341.8,6315 4345.1,6318.3 4366.8,6318.3 v1(4374.2,6310.9) ; v1(7225.5,6493.7) R27.1@7258.7,6493.7
  Inner2 w4.7: v1(4453.1,6476) 4453.1,6494.6 4470.3,6511.7 6362,6511.7 6388.1,6537.8 6566.8,6537.8 6594.9,6509.7 6791.7,6509.7 6813.8,6531.8 7187.4,6531.8 v1(7225.5,6493.7)
  Inner4 w4.7: v1(4374.2,6310.9) 4393.1,6310.9 4398.2,6315.9 4405.5,6315.9 4413.6,6324 4413.6,6447 4429.3,6462.7 4439.8,6462.7 v1(4453.1,6476)
H_M3_P6: R33.1 U1$CBB23.C15 | length 3262.7
  Top Layer w4.7: U1$CBB23.C15@4207.6,5846.4 4224.4,5863.2 4251.7,5863.2 4261.8,5873.2 4303.3,5873.2 4438.5,5738.1 4438.5,5669.3 v1(4435.8,5666.6) ; v1(7225.5,5708.7) R33.1@7258.7,5708.7
  Inner2 w4.7: v1(4435.8,5666.6) 4446.6,5666.6 4505,5608.2 4688.6,5608.2 4692.8,5612.4 4706.2,5612.4 4710.4,5608.2 5884.1,5608.2 5928.3,5652.4 7074.8,5652.4 7131.2,5708.7 v1(7225.5,5708.7)
H_M3_P7: R39.1 U1$CBB23.B15 | length 3144.7
  Top Layer w4.7: U1$CBB23.B15@4207.6,5877.9 4223,5893.3 4223,5935.2 4239.4,5951.5 4318,5951.5 4325.4,5944.1 v1(4344.3,5944.1) ; v1(7225.5,5973.7) R39.1@7258.7,5973.7
  Inner2 w4.7: v1(4344.3,5944.1) 4352,5951.9 6773.9,5951.9 6822.1,6000 6996.5,6000 7024.6,5971.9 7223.7,5971.9 v1(7225.5,5973.7)
H_M3_P8: R62.1 U1$CBB23.A10 | length 4428.6
  Top Layer w4.7: U1$CBB23.A10@4050.1,5909.4 4050.1,5974.4 4147.5,6071.8 4147.5,6183.2 4259.8,6295.4 4259.8,6465.6 4271.8,6477.6 4282.3,6477.6 v1(4295.7,6490.9) ; v1(7225.5,7278.7) R62.1@7258.7,7278.7
  Inner2 w4.7: v1(4451.4,7272.7) 4469.7,7291.1 5267.7,7291.1 5319.9,7238.9 5803.8,7238.9 5827.9,7263 7209.8,7263 v1(7225.5,7278.7)
  Inner4 w4.7: v1(4295.7,6490.9) 4311.9,6507.1 4311.9,6570.8 4379.8,6638.7 4379.8,6761.3 4333.9,6807.2 4333.9,6812.1 4333.8,6812.2 4333.8,7089.4 4413.7,7169.2 4413.7,7237.9 4448.5,7272.7 v1(4451.4,7272.7)
H_M8_N1: R85.1 U1$CBB23.F14 | length 6201
  Top Layer w4.7: v1(7217.4,8889.1) R85.1@7258.6,8889.1
  Inner2 w4.7: v1(4303.8,8864.6) 4308.2,8869 6876,8869 6896.1,8889.1 v1(7217.4,8889.1)
  Inner4 w4.7: v2(4176.1,5751.9) 4207,5751.9 4270.1,5815 4270.1,5961.5 4206.9,6024.6 4206.9,7142.2 4287.2,7222.5 4287.2,8848 v1(4303.8,8864.6)
H_M8_N2: R91.1 U1$CBB23.A6 | length 5602
  Top Layer w4.7: U1$CBB23.A6@3924.1,5909.4 3924.1,5944.7 4079.4,6100 4079.4,6581.8 4140.8,6643.1 v1(4257,6643.1) ; v1(7225.5,8368.9) R91.1@7258.7,8368.9
  Inner2 w4.7: v1(4345.2,8330) 4353.1,8337.9 5971.8,8337.9 5978.5,8344.6 7201.2,8344.6 v1(7225.5,8368.9)
  Inner4 w4.7: v1(4257,6643.1) 4245.8,6654.3 4245.8,7125.2 4326.1,7205.5 4326.1,8310.9 v1(4345.2,8330)
H_M8_N3: R98.1 U1$CBB23.B7 | length 4791.8
  Top Layer w4.7: U1$CBB23.B7@3955.6,5877.9 3971.5,5893.8 3971.5,5950.8 4108.6,6087.9 4108.6,6409 v1(4258.2,6558.5) ; v1(7225.5,7583.9) R98.1@7258.7,7583.9
  Inner2 w4.7: v1(4400,7581.3) 4403,7581.3 4410.4,7573.9 7215.5,7573.9 v1(7225.5,7583.9)
  Inner4 w4.7: v1(4258.2,6558.5) 4285.6,6585.9 4285.8,6585.9 4350.4,6650.6 4350.4,6748.7 4304.2,6794.9 4304.2,7101 4384.5,7181.3 4384.5,7565.8 v1(4400,7581.3)
H_M8_N4: R104.1 U1$CBB23.B11 | length 3940.7
  Top Layer w4.7: U1$CBB23.B11@4081.6,5877.9 4097.5,5893.8 4097.5,5980.5 4176.7,6059.7 4176.7,6171.1 4288.9,6283.3 4288.9,6358.2 4316.8,6386.1 4339.2,6386.1 4351.4,6398.3 v1(4351.4,6409.9) ; v1(7225.5,6798.9) R104.1@7258.7,6798.9
  Inner2 w4.7: v1(4441.2,6816.2) 4445.6,6820.5 6376.7,6820.5 6383.1,6826.9 6396.6,6826.9 6403,6820.5 7187.7,6820.5 7209.3,6798.9 v1(7225.5,6798.9)
  Inner4 w4.7: v1(4351.4,6409.9) 4363.1,6409.9 4375.3,6422.1 4375.3,6592.9 4409.4,6627 4409.4,6773.8 4427.9,6792.3 4427.9,6802.8 v1(4441.2,6816.2)
H_M8_N5: R110.1 U1$CBB23.A14 | length 3477.6
  Top Layer w4.7: U1$CBB23.A14@4176.1,5909.4 4176.1,6004.1 4215.6,6043.6 4215.6,6155 4317,6256.4 4392.3,6256.4 4407.5,6271.6 4407.5,6282.2 v1(4420.8,6295.5) ; v1(7225.5,6278.9) R110.1@7258.7,6278.9
  Inner2 w4.7: v1(4420.8,6295.5) 4427,6295.5 4485.7,6354.2 6182.2,6354.2 6191.2,6363.1 6237.7,6363.1 6257.7,6343.1 6434.4,6343.1 6462.5,6315 6869.9,6315 6902,6347.1 7189.3,6347.1 7225.5,6310.8 v1(7225.5,6278.9)
H_M8_N6: R116.1 U1$CBB23.C16 | length 3256.2
  Top Layer w4.7: U1$CBB23.C16@4239.1,5846.4 4260.9,5824.6 4304.8,5824.6 4400.3,5729.1 4400.3,5668 v1(4412.1,5656.1) ; v1(7225.5,5493.9) R116.1@7258.7,5493.9
  Inner2 w4.7: v1(4412.1,5656.1) 4404,5648 4404,5626.6 4454.5,5576.1 5307.5,5576.1 5312.9,5581.5 5353.7,5581.5 5363.4,5591.2 5384.9,5591.2 5391.4,5584.7 5895.1,5584.7 5911.4,5601 6039.9,5601 6058.8,5582.1 7093,5582.1 7181.2,5493.9 v1(7225.5,5493.9)
H_M8_N7: R122.1 U1$CBB23.B4 | length 5400.2
  Top Layer w4.7: U1$CBB23.B4@3861.1,5877.9 3877,5893.8 3877,5925 4060,6108 4060,6589.9 4156.5,6686.3 v1(4280.8,6686.3) ; v1(7225.4,8104) R122.1@7258.6,8104
  Inner2 w4.7: v1(4361.3,8076.7) 4364.5,8079.9 6402.5,8079.9 6418.2,8095.6 6630.7,8095.6 6631.1,8095.9 7217.3,8095.9 v1(7225.4,8104)
  Inner4 w4.7: v1(4280.8,6686.3) 4265.3,6701.9 4265.3,7117.1 4345.6,7197.4 4345.6,8061 v1(4361.3,8076.7)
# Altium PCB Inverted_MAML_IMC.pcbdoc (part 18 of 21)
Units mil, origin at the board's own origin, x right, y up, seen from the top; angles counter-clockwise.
Board outline 7677.1 x 6771.6 mil, 6 copper layers (Top Layer, Inner1, Inner2, Inner3, Inner4, Bottom Layer), stack 60.7 mil thick; 2732 components, 1531 nets, 7765 pads, 3701 vias.

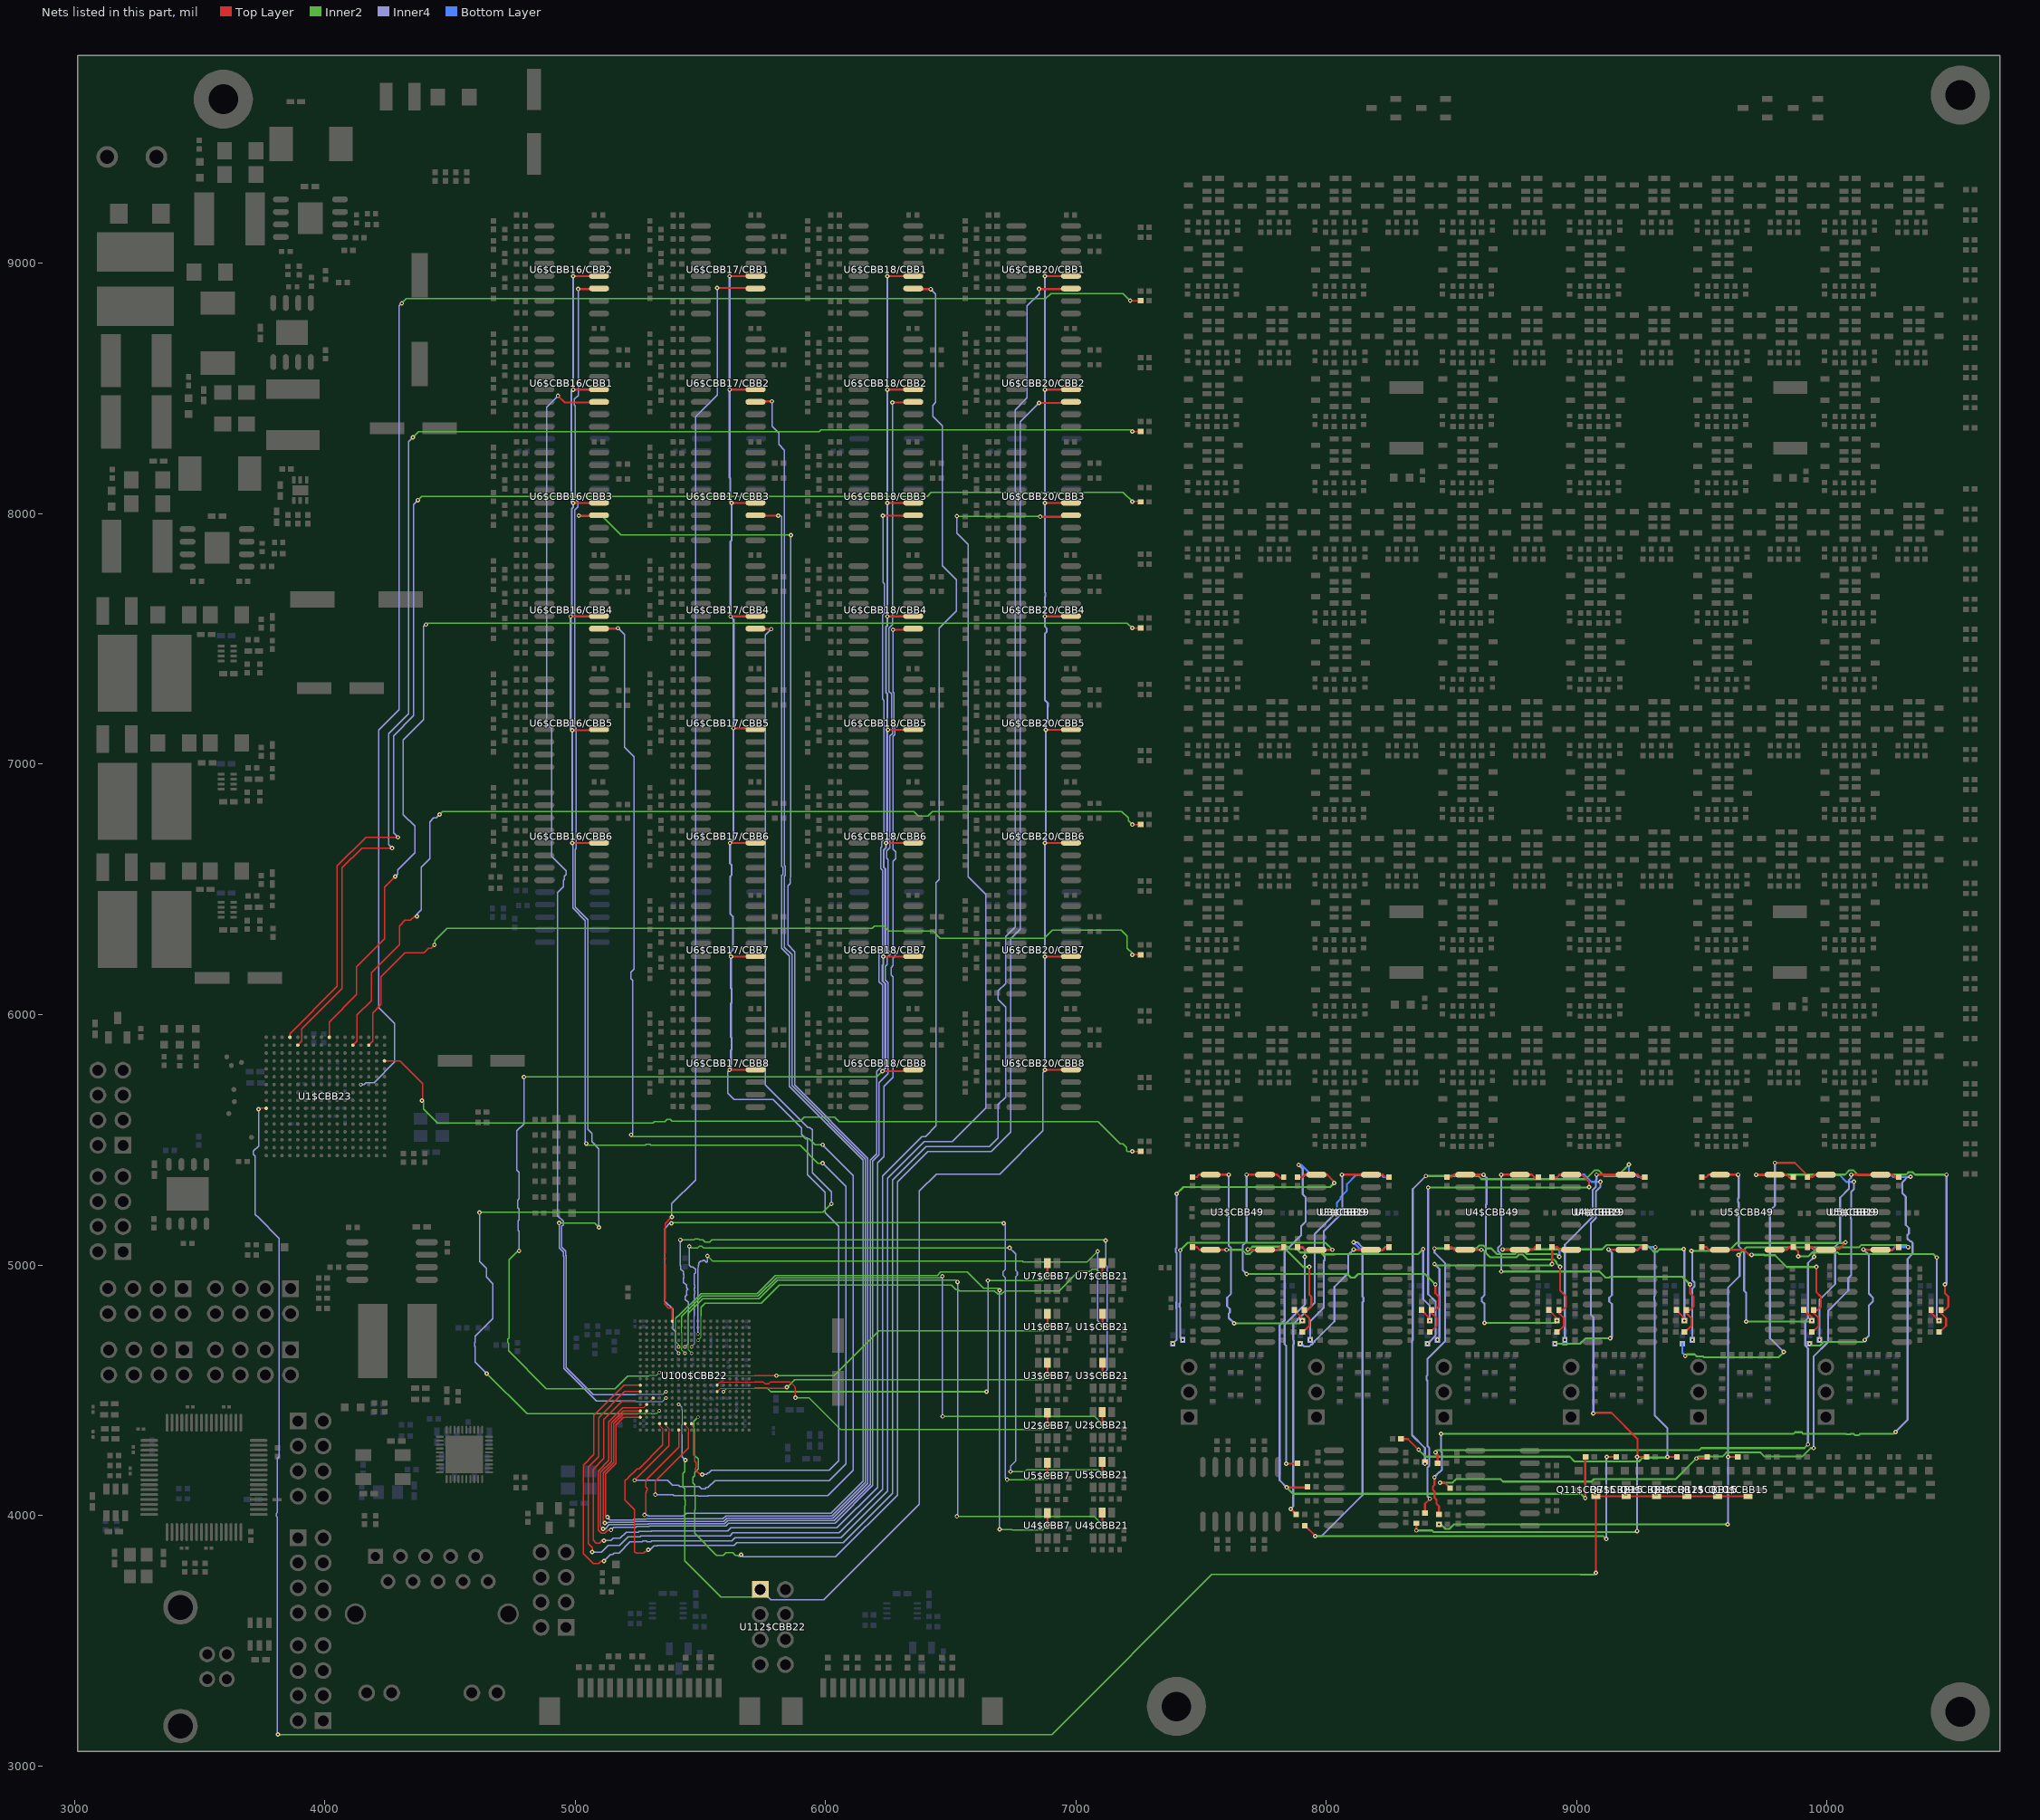
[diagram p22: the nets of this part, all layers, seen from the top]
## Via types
v1: diameter 17.7, hole 7.9, Top Layer to Bottom Layer, 3369 vias
v2: diameter 13.8, hole 7.9, Top Layer to Bottom Layer, 287 vias
v3: diameter 23.6, hole 11.8, Top Layer to Bottom Layer, 45 vias

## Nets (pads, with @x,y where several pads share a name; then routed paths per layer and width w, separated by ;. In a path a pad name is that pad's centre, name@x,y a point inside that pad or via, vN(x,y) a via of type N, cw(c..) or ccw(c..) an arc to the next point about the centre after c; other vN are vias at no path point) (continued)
H_M8_P1: R82.1 U1$CBB23.G13 | length 6244.8
  Top Layer w4.7: v1(7217.4,8850.9) R82.1@7258.6,8850.9
  Inner2 w4.7: v1(4308,8840.9) 4326,8858.9 6879.7,8858.9 6900.1,8879.3 7188.9,8879.3 v1(7217.4,8850.9)
  Inner4 w4.7: v2(4144.6,5720.4) 4157.2,5720.4 4165.4,5728.7 4197.5,5728.7 4279.8,5811 4279.8,5965.5 4216.7,6028.7 4216.7,7137.2 4297,7217.6 4297,8829.9 v1(4308,8840.9)
H_M8_P2: R88.1 U1$CBB23.B5 | length 5620.3
  Top Layer w4.7: U1$CBB23.B5@3892.6,5877.9 3908.5,5893.8 3908.5,5942.8 4069.7,6104 4069.7,6585.8 4148.6,6664.7 v1(4268.9,6664.7) ; v1(7225.5,8328.7) R88.1@7258.7,8328.7
  Inner2 w4.7: v1(4352.1,8304.8) 4375.5,8328.1 5975.8,8328.1 5982.5,8334.9 7219.4,8334.9 v1(7225.5,8328.7)
  Inner4 w4.7: v1(4268.9,6664.7) 4255.6,6678.1 4255.6,7121.1 4335.9,7201.4 4335.9,8288.5 v1(4352.1,8304.8)
H_M8_P3: R94.1 U1$CBB23.A9 | length 4713.1
  Top Layer w4.7: U1$CBB23.A9@4018.6,5909.4 4018.6,5970.4 4128.1,6079.8 4128.1,6191.2 4239.7,6302.8 4239.7,6509.7 v1(4281.9,6551.9) ; v1(7225.5,7543.7) R94.1@7258.7,7543.7
  Inner2 w4.7: v1(4404.3,7557.6) 4405.2,7557.6 4411.5,7563.9 7205.4,7563.9 v1(7225.5,7543.7)
  Inner4 w4.7: v1(4281.9,6551.9) 4291.9,6561.9 4291.9,6578.3 4360.2,6646.6 4360.2,6752.7 4313.9,6798.9 4313.9,7097 4394.2,7177.3 4394.2,7549.7 4402.1,7557.6 v1(4404.3,7557.6)
H_M8_P4: R101.1 U1$CBB23.B12 | length 3937.1
  Top Layer w4.7: U1$CBB23.B12@4113.1,5877.9 4129,5893.8 4129,5998.2 4186.4,6055.7 4186.4,6167.1 4298.7,6279.3 4298.7,6354.2 4320.9,6376.4 4343.2,6376.4 4360.2,6393.3 4368.1,6393.3 v1(4368.8,6392.5) ; v1(7225.5,6758.7) R101.1@7258.7,6758.7
  Inner2 w4.7: v1(4458.6,6798.8) 4470.6,6810.8 6352.1,6810.8 6370.2,6792.7 6408.9,6792.7 6427,6810.8 7183.7,6810.8 7209.3,6785.1 7209.3,6774.9 v1(7225.5,6758.7)
  Inner4 w4.7: v1(4368.8,6392.5) 4368.8,6401.9 4385,6418.1 4385,6588.9 4419.3,6623.2 4419.3,6770 4434.8,6785.4 4445.3,6785.4 v1(4458.6,6798.8)
H_M8_P5: R107.1 U1$CBB23.B14 | length 3524.9
  Top Layer w4.7: U1$CBB23.B14@4176.1,5877.9 4192,5893.8 4192,6006.2 4225.6,6039.9 4225.6,6151.3 4321.1,6246.7 4396.3,6246.7 4414.4,6264.8 4424.9,6264.8 v1(4438.2,6278.1) ; v1(7225.5,6238.7) R107.1@7258.7,6238.7
  Inner2 w4.7: v1(4438.2,6278.1) 4440.2,6280 4440.2,6294.9 4489.4,6344.1 6186.4,6344.1 6195.4,6353.1 6233.5,6353.1 6253.6,6333 6430.3,6333 6458.4,6304.9 6874,6304.9 6906.1,6337 7181.2,6337 7205.3,6313 7205.3,6264.8 7225.5,6244.6 v1(7225.5,6238.7)
H_M8_P6: R113.1 U1$CBB23.D16 | length 3262.5
  Top Layer w4.7: U1$CBB23.D16@4239.1,5814.9 4300.8,5814.9 4390.6,5725.1 4390.6,5659 v1(4388.4,5656.8) ; v1(7225.5,5453.7) R113.1@7258.7,5453.7
  Inner2 w4.7: v1(4388.4,5656.8) 4394.3,5650.9 4394.3,5622.5 4450.5,5566.3 5311.5,5566.3 5316.9,5571.7 5357.7,5571.7 5367.4,5581.5 5380.9,5581.5 5387.3,5575 5899.1,5575 5915.4,5591.3 6035.9,5591.3 6054.8,5572.4 7089,5572.4 7177.2,5484.2 7188.8,5484.2 7203.3,5469.6 7203.3,5457.1 7206.7,5453.7 v1(7225.5,5453.7)
H_M8_P7: R119.1 U1$CBB23.A4 | length 5361.1
  Top Layer w4.7: U1$CBB23.A4@3861.1,5909.4 3861.1,5922.9 4050.3,6112.1 4050.3,6593.9 4164.4,6708 v1(4292.7,6708) ; v1(7225.4,8049) R119.1@7258.6,8049
  Inner2 w4.7: v1(4372.7,8054.6) 4388.3,8070.2 6406.5,8070.2 6422.2,8085.9 7188.5,8085.9 v1(7225.4,8049)
  Inner4 w4.7: v1(4292.7,6708) 4275,6725.7 4275,7113.1 4355.3,7193.4 4355.3,8037.2 v1(4372.7,8054.6)
M(3)COL_N_TAI1: R4$CBB49.1 R6$CBB1.2 R11$CBB1.1 U3$CBB49.7 | length 818.5
  Top Layer w7.9: R4$CBB49.1@7465.3,5071.3 7482.9,5071.3 7493.7,5060.6 U3$CBB49.7@7537.6,5060.6 v1(7602.1,5060.6) ; R6$CBB1.2@7904.2,4732.2 7907.1,4732.2 7932.1,4757.2 7932.1,4787.2 7912.1,4807.2 R11$CBB1.1@7912.1,4820.1 7927.1,4820.1 7940.6,4833.6 7940.6,4873.6 7932.1,4882.2 v1(7932.1,4992.2)
  Inner2 w7.9: v1(7602.1,5060.6) 7663.5,5060.6 7679.8,5044.4 7694.5,5044.4 7710.7,5060.6 7840.3,5060.6 7908.7,4992.2 v1(7932.1,4992.2)
M(3)COL_N_TAI2: R6$CBB2.2 R6$CBB49.1 R11$CBB2.1 U3$CBB49.14 | length 1584.7
  Top Layer w7.9: v1(7682.1,5360.6) U3$CBB49.14@7755.6,5360.6 7803.7,5360.6 7817.1,5347.2 7827,5347.2 R6$CBB49.1@7830.3,5350.4 ; R6$CBB2.2@8412.9,4732.2 8415.8,4732.2 8440.8,4757.2 8440.8,4787.2 8420.8,4807.2 R11$CBB2.1@8420.8,4820.1 8435.8,4820.1 8449.3,4833.6 8449.3,4873.6 8435.8,4887.2 v1(8435.8,4922.2)
  Inner2 w7.9: v1(7682.1,4963.7) 8084.1,4963.7 8098.5,4949.4 8113.2,4949.4 8127.6,4963.7 8394.3,4963.7 v1(8435.8,4922.2)
  Inner4 w7.9: v1(7682.1,4963.7) 7667.1,4978.7 7667.1,5078.7 7682.1,5093.7 v1(7682.1,5360.6)
M(3)COL_N_TAI3: R6$CBB3.2 R8$CBB49.1 R11$CBB3.1 U4$CBB49.7 | length 807.5
  Top Layer w7.9: R8$CBB49.1@8482.7,5071.3 8500.3,5071.3 8511.1,5060.6 U4$CBB49.7@8555,5060.6 v1(8619.5,5060.6) ; R6$CBB3.2@8921.6,4732.2 8924.5,4732.2 8949.5,4757.2 8949.5,4787.2 8929.5,4807.2 R11$CBB3.1@8929.5,4820.1 8944.5,4820.1 8958,4833.6 8958,4873.6 8934.5,4897.2 v1(8934.5,4992.2)
  Inner2 w7.9: v1(8619.5,5060.6) 8625.3,5060.6 8654.8,5031.1 8759.3,5031.1 8769.8,5041.5 8784.5,5041.5 8804.5,5021.5 8909.5,5021.5 8919.9,5011.1 8919.9,5006.8 v1(8934.5,4992.2)
M(3)COL_N_TAI4: R6$CBB4.2 R10$CBB49.1 R11$CBB4.1 U4$CBB49.14 | length 1568.5
  Top Layer w7.9: v1(8699.5,5360.6) U4$CBB49.14@8773,5360.6 8821.1,5360.6 8834.5,5347.2 8844.4,5347.2 R10$CBB49.1@8847.7,5350.4 ; R6$CBB4.2@9430.3,4732.2 9433.2,4732.2 9458.2,4757.2 9458.2,4787.2 9438.2,4807.2 R11$CBB4.1@9438.2,4820.1 9453.2,4820.1 9466.7,4833.6 9466.7,4873.6 9453.2,4887.2 v1(9453.2,4922.2)
  Inner2 w7.9: v1(8699.5,4973.7) 9091.5,4973.7 9115.9,4949.4 9130.6,4949.4 9134.7,4953.4 9422,4953.4 v1(9453.2,4922.2)
  Inner4 w7.9: v1(8699.5,4973.7) 8699.5,5042 8686.7,5054.8 8686.7,5069.5 8699.5,5082.3 v1(8699.5,5360.6)
M(3)COL_N_TAI5: R6$CBB5.2 R11$CBB5.1 R12$CBB49.1 U5$CBB49.7 | length 799.3
  Top Layer w7.9: R12$CBB49.1@9500.1,5071.3 9517.7,5071.3 9528.5,5060.6 U5$CBB49.7@9572.4,5060.6 9668.4,5060.6 9688.5,5040.5 v1(9699.2,5040.5) ; R6$CBB5.2@9939,4732.2 9941.9,4732.2 9966.9,4757.2 9966.9,4787.2 9946.9,4807.2 R11$CBB5.1@9946.9,4820.1 9961.9,4820.1 9975.4,4833.6 9975.4,4873.6 9956.9,4892.2 v1(9956.9,4992.2)
  Inner2 w7.9: v1(9699.2,5040.5) 9748.7,5040.5 9750.5,5038.7 9792.1,5038.7 9838.7,4992.2 v1(9956.9,4992.2)
M(3)COL_N_TAI6: R6$CBB6.2 R11$CBB6.1 R14$CBB49.1 U5$CBB49.14 | length 1617.6
  Top Layer w7.9: v1(9716.9,5360.6) U5$CBB49.14@9790.4,5360.6 9838.5,5360.6 9851.9,5347.2 9861.8,5347.2 R14$CBB49.1@9865.1,5350.4 ; R6$CBB6.2@10447.7,4732.2 10450.6,4732.2 10475.6,4757.2 10475.6,4787.2 10455.6,4807.2 R11$CBB6.1@10455.6,4820.1 10470.6,4820.1 10484.2,4833.6 10484.2,4873.6 10470.6,4887.2 v1(10470.6,4922.2)
  Inner2 w7.9: v1(9716.9,5360.6) 10071.7,5360.6 10089.5,5378.4 10104.3,5378.4 10122.1,5360.6 10315.8,5360.6 10326.2,5371 10341,5371 10351.3,5360.6 v1(10477.1,5360.6)
  Inner4 w7.9: v1(10470.6,4922.2) 10477.1,4928.7 v1(10477.1,5360.6)
M(3)COL_P_TAI1: R3$CBB49.1 R7$CBB1.2 R12$CBB1.1 U3$CBB49.1 | length 1103.2
  Top Layer w5.9: R12$CBB1.1@7872.1,4820.1 7904.2,4788.1 v1(7904.2,4777.2)
  Top Layer w7.9: R3$CBB49.1@7465.3,5350.4 7482,5350.4 7492.1,5360.6 U3$CBB49.1@7537.6,5360.6 v1(7610.5,5360.6) v1@7612.1,5362.2
  Inner2 w7.9: v1(7632.1,4767.2) 7894.2,4767.2 v1(7904.2,4777.2)
  Inner4 w7.9: v1(7610.5,5360.6) 7610.5,5077.3 7619.9,5068 7619.9,4885.1 7604.3,4869.5 7604.3,4835.1 7614.9,4824.5 7614.9,4809.8 7610.5,4805.4 7610.5,4788.7 v1(7632.1,4767.2)
M(3)COL_P_TAI2: R5$CBB49.1 R7$CBB2.2 R12$CBB2.1 U3$CBB49.8 | length 1227.7
  Top Layer w7.9: v1(7687.1,5062.2) 7688.7,5060.6 U3$CBB49.8@7755.6,5060.6 7805.5,5060.6 7816.3,5071.3 R5$CBB49.1@7830.3,5071.3 ; R12$CBB2.1@8380.8,4820.1 8412.9,4788.1 v1(8412.9,4777.2)
  Inner2 w7.9: v1(7687.1,5062.2) 7688.7,5063.7 7695.7,5063.7 7705.4,5073.5 7845.6,5073.5 7855.3,5063.7 7882.1,5063.7 7895.9,5050 7978.2,5050 7985.4,5042.8 8032.5,5042.8 8033.5,5043.7 8367.1,5043.7 v1(8387.1,5063.7)
  Inner4 w7.9: v1(8387.1,5063.7) 8387.1,4863.7 8412.9,4838 v1(8412.9,4777.2)
M(3)COL_P_TAI3: R7$CBB3.2 R7$CBB49.1 R12$CBB3.1 U4$CBB49.1 | length 1110.1
  Top Layer w5.9: R12$CBB3.1@8889.5,4820.1 8921.6,4788.1 v1(8921.6,4777.2)
  Top Layer w7.9: R7$CBB49.1@8482.7,5350.4 8499.3,5350.4 8509.5,5360.6 U4$CBB49.1@8555,5360.6 v1(8627.9,5360.6) v1@8629.5,5362.2
  Inner2 w7.9: v1(8632.1,4768.7) 8913.1,4768.7 v1(8921.6,4777.2)
  Inner4 w7.9: v1(8627.9,5360.6) 8640.2,5348.4 8640.2,5243.6 8637.3,5240.7 8637.3,5052.8 8632.3,5047.8 8632.3,4959.8 8632.1,4959.6 8632.1,4879.9 8621.7,4869.5 8621.7,4854.8 8632.1,4844.4 8632.1,4824.7 8632.3,4824.5 8632.3,4809.8 8632.1,4809.6 v1(8632.1,4768.7)
M(3)COL_P_TAI4: R7$CBB4.2 R9$CBB49.1 R12$CBB4.1 U4$CBB49.8 | length 1241.7
  Top Layer w7.9: v1(8704.5,5062.2) 8706.1,5060.6 U4$CBB49.8@8773,5060.6 8822.9,5060.6 8833.7,5071.3 R9$CBB49.1@8847.7,5071.3 ; R12$CBB4.1@9398.2,4820.1 9430.3,4788.1 v1(9430.3,4777.2)
  Inner2 w7.9: v1(8704.5,5062.2) 8754,5062.2 8759.1,5067.3 8795.2,5067.3 8800.3,5062.2 9102.4,5062.2 9120.2,5080 9280.7,5080 9307.1,5053.6 9321.9,5053.6 9330.5,5062.2 9425.6,5062.2 v1(9427.1,5063.7)
  Inner4 w7.9: v1(9427.1,5063.7) 9430.3,5060.6 v1(9430.3,4777.2)
M(3)COL_P_TAI5: R7$CBB5.2 R11$CBB49.1 R12$CBB5.1 U5$CBB49.1 | length 1075.9
  Top Layer w7.9: R11$CBB49.1@9500.1,5350.4 9516.8,5350.4 9526.9,5360.6 U5$CBB49.1@9572.4,5360.6 v1(9645.3,5360.6) v1@9646.9,5362.2 ; R12$CBB5.1@9906.9,4820.1 9928.3,4798.7 9932.1,4798.7 9939,4791.9 v1(9939,4777.2)
  Inner2 w7.9: v1(9677.1,4773.7) 9935.5,4773.7 v1(9939,4777.2)
  Inner4 w7.9: v1(9645.3,5360.6) 9647.1,5358.8 9647.1,5268.9 9644.3,5266.1 9644.3,5251.4 9647.1,5248.6 9647.1,5075.5 9669,5053.7 9669,4896.9 9677.1,4888.7 v1(9677.1,4773.7)
M(3)COL_P_TAI6: R7$CBB6.2 R12$CBB6.1 R13$CBB49.1 U5$CBB49.8 | length 1022.4
  Top Layer w7.9: U5$CBB49.8@9790.4,5060.6 9840.3,5060.6 9849.2,5069.4 ; R13$CBB49.1@9865.1,5071.3 9851.1,5071.3 9849.2,5069.4 ; v1(9884.6,5034.1) 9884.6,5054.4 9869.5,5069.4 9849.2,5069.4 ; R12$CBB6.1@10415.6,4820.1 10415.6,4809.2 10428.1,4796.7 10428.4,4796.7 10433.7,4791.5 10433.7,4791.2 v1(10447.7,4777.2)
  Inner2 w7.9: v1(9884.6,5034.1) 9925.2,5034.1 9941.1,5050 10042.5,5050 10048.5,5044 10423.9,5044 v1(10438,5029.9)
  Inner4 w7.9: v1(10438,5029.9) 10438,4786.8 v1(10447.7,4777.2)
M(8)COL_N_TAI1: R4$CBB9.1 R6$CBB8.2 U3$CBB9.7 | length 1137.4
  Top Layer w7.9: R4$CBB9.1@7888.3,5071.3 7906,5071.3 7916.7,5060.6 U3$CBB9.7@7960.6,5060.6 v1(8025.1,5060.6)
  Inner2 w7.9: v1(7417.1,5058.7) 7447.1,5088.7 7997,5088.7 v1(8025.1,5060.6)
  Inner4 w7.9: v1(7417.1,5058.7) 7417.1,4849.3 7414.4,4846.5 7414.4,4831.8 7417.1,4829.1 7417.1,4710.7 v1(7426.9,4700.9)
M(8)COL_N_TAI2: R6$CBB9.1 R6$CBB10.2 U3$CBB9.14 | length 918
  Top Layer w7.9: v1(8062.1,5360.6) U3$CBB9.14@8178.6,5360.6 8226.7,5360.6 8240.1,5347.2 8250,5347.2 8253.3,5350.4 R6$CBB9.1@8250.3,5350.4
  Inner4 w7.9: v1(7935.6,4700.9) 7935.6,4774.4 7990.4,4829.1 7990.4,5016.6 7993.6,5019.8 7993.6,5034.5 7990.4,5037.8 7990.4,5135.3 8064.7,5209.6 8064.7,5358 v1(8062.1,5360.6)
M(8)COL_N_TAI3: R6$CBB11.2 R8$CBB9.1 U4$CBB9.7 | length 934.1
  Top Layer w7.9: v1(8902.1,5003.7) R8$CBB9.1@8902.1,5071.3 ; R8$CBB9.1@8905.7,5071.3 8923.3,5071.3 8934.1,5060.6 U4$CBB9.7@8978,5060.6
  Inner2 w7.9: v1(8432.1,5003.7) 8437.3,4998.6 8897,4998.6 v1(8902.1,5003.7)
  Inner4 w7.9: v1(8432.1,5003.7) 8452.1,4983.7 8452.1,4931 8453.6,4929.5 8453.6,4914.8 8452.1,4913.3 8452.1,4708.7 v1(8444.3,4700.9)
M(8)COL_N_TAI4: R6$CBB12.2 R10$CBB9.1 U4$CBB9.14 | length 913.2
  Top Layer w7.9: v1(9079.5,5360.6) U4$CBB9.14@9196,5360.6 9244.1,5360.6 9257.5,5347.2 9267.4,5347.2 9270.7,5350.4 R10$CBB9.1@9267.7,5350.4
  Inner4 w7.9: v1(8953,4700.9) 8953,5081 9064.3,5192.2 9064.3,5299.1 9076.7,5311.5 9076.7,5339.5 9079.5,5342.3 v1(9079.5,5360.6)
M(8)COL_N_TAI5: R6$CBB13.2 R12$CBB9.1 U5$CBB9.7 | length 1160.6
  Top Layer w7.9: R12$CBB9.1@9923.1,5071.3 9940.7,5071.3 9948.6,5063.5 10047.9,5063.5 10074,5089.6 v1(10074,5090.7)
  Inner2 w7.9: v1(9458.1,5056) 9607.2,5056 9639.3,5088.1 10071.4,5088.1 v1(10074,5090.7)
  Inner4 w7.9: v1(9458.1,5056) 9461.7,5052.4 9461.7,4938.8 9471,4929.5 9471,4914.8 9461.7,4905.5 v1(9461.7,4700.9)
M(8)COL_N_TAI6: R6$CBB14.2 R14$CBB9.1 U5$CBB9.14 | length 913.2
  Top Layer w7.9: v1(10096.9,5360.6) U5$CBB9.14@10213.4,5360.6 10261.5,5360.6 10274.9,5347.2 10284.8,5347.2 10288.1,5350.4 R14$CBB9.1@10285.1,5350.4
  Inner4 w7.9: v1(9970.4,4700.9) 9970.4,4862.1 10032.1,4923.7 10032.1,5073.7 10052.1,5093.7 10052.1,5268.7 10087.1,5303.7 10087.1,5338.7 10096.9,5348.5 v1(10096.9,5360.6)
M(8)COL_P_TAI1: R3$CBB9.1 R7$CBB8.2 U3$CBB9.1 | length 1420
  Top Layer w7.9: R3$CBB9.1@7888.3,5350.4 7905,5350.4 7915.1,5360.6 U3$CBB9.1@7960.6,5360.6 8003.7,5360.6 8032.1,5332.2 v1(8032.1,5327.5)
  Inner2 w7.9: v1(7402.1,5283.7) 7429.4,5311 8015.6,5311 v1(8032.1,5327.5)
  Inner4 w7.9: v1(7387.1,4685.4) 7402.1,4700.4 7402.1,4825.9 7401.5,4826.5 7401.5,4851.9 7402.1,4852.5 7402.1,5048.6 7399.3,5051.4 7399.3,5066.1 7402.1,5068.9 v1(7402.1,5283.7)
M(8)COL_P_TAI2: R5$CBB9.1 R7$CBB10.2 U3$CBB9.8 | length 651.3
  Top Layer w7.9: v1(8110.1,5062.2) 8111.7,5060.6 U3$CBB9.8@8178.6,5060.6 8228.6,5060.6 8239.3,5071.3 R5$CBB9.1@8253.3,5071.3
  Inner4 w7.9: v1(7895.8,4685.4) 7900.4,4685.4 7910.6,4675.2 7932.9,4675.2 7940.7,4683.1 7943,4683.1 7953.4,4693.5 7953.4,4695.8 8032.6,4774.9 8032.6,4912.1 8088,4967.6 8088,5040.1 v1(8110.1,5062.2)
M(8)COL_P_TAI3: R7$CBB9.1 R7$CBB11.2 U4$CBB9.1 | length 1473.4
  Top Layer w7.9: R7$CBB9.1@8905.7,5350.4 8922.4,5350.4 8932.5,5360.6 U4$CBB9.1@8978,5360.6 9021.1,5360.6 9049.5,5332.2 v1(9049.5,5311.4)
  Inner2 w7.9: v1(8407.1,5308.7) 9046.9,5308.7 v1(9049.5,5311.4)
  Inner4 w7.9: v1(8404.5,4685.4) 8426.5,4707.4 8426.5,4708.3 8437.1,4718.9 8437.1,4853.7 8407.1,4883.7 v1(8407.1,5308.7)
M(8)COL_P_TAI4: R7$CBB12.2 R9$CBB9.1 U4$CBB9.8 | length 752.5
  Top Layer w7.9: v1(9127.5,5062.2) 9129.1,5060.6 U4$CBB9.8@9196,5060.6 9245.9,5060.6 9256.7,5071.3 R9$CBB9.1@9270.7,5071.3
  Inner2 w7.9: v1(8913.2,4685.4) 8943.3,4685.4 8945.7,4683.1 8960.4,4683.1 8962.7,4685.4 9013.8,4685.4 9035.2,4706.8 v1(9134.1,4706.8)
  Inner4 w7.9: v1(9127.5,5062.2) 9141,5048.7 9141,4880.1 9130.4,4869.5 9130.4,4854.8 9141,4844.2 9141,4713.7 v1(9134.1,4706.8)
M(8)COL_P_TAI5: R7$CBB13.2 R11$CBB9.1 U5$CBB9.1 | length 1545
  Top Layer w7.9: v1(9791.8,5407.8) 9871.4,5407.8 9926,5353.2 9942.5,5353.2 ; R11$CBB9.1@9923.1,5350.4 9939.8,5350.4 9942.5,5353.2 ; 9942.5,5353.2 9949.9,5360.6 ; 9949.9,5360.6 U5$CBB9.1@9995.4,5360.6 9949.9,5360.6
  Inner2 w7.9: v1(9434,4637.2) 9439.9,4643.1 9471.5,4643.1 9480.1,4634.6 9504.5,4634.6 9508,4631.1 9806.3,4631.1 v1(9827.6,4652.4)
  Inner4 w7.9: v1(9791.8,5407.8) 9791.8,5236.4 9783.9,5228.4 9783,5228.4 9772.6,5218 9772.6,5206 9772.3,5205.7 9772.3,4707.7 v1(9827.6,4652.4)
  Bottom Layer w7.9: R7$CBB13.2@9421.9,4685.1 9421.9,4649.3 v1(9434,4637.2)
M(8)COL_P_TAI6: R7$CBB14.2 R13$CBB9.1 U5$CBB9.8 | length 771.6
  Top Layer w7.9: v1(10144.9,5062.2) 10146.5,5060.6 U5$CBB9.8@10213.4,5060.6 10263.4,5060.6 10274.1,5071.3 R13$CBB9.1@10288.1,5071.3
  Inner2 w7.9: v1(9930.6,4685.4) 9937.5,4678.5 9972.2,4678.5 9976.7,4683.1 9977.8,4683.1 9987.3,4692.6 10142.8,4692.6 v1(10150.9,4700.6)
  Inner4 w7.9: v1(10144.9,5062.2) 10166.9,5040.2 10166.9,4886 10183.4,4869.5 10183.4,4854.8 10166.9,4838.3 10166.9,4716.7 v1(10150.9,4700.6)
M(33)N_TAI1: R5$CBB19.1 R90$CBB15.2 U3$CBB19.8 | length 1612.4
  Top Layer w7.9: v1(7857.9,4026) R90$CBB15.2@7880.1,4003.7
  Inner4 w7.9: v1(7857.9,4026) 7867.9,4036 7867.9,4681.4 7869.7,4683.2 7869.7,4698 7867.9,4699.8 7867.9,4762.9 7886.4,4781.3 7886.4,4784.5 7896.8,4795 7900,4795 7954.3,4849.2 7954.3,5124.3 v1(8042.6,5212.6)
  Bottom Layer w7.9: v1(8042.6,5212.6) 8042.6,5248.8 8056.7,5262.8 8056.7,5270.9 8082.8,5297 8082.8,5323.1 8120.3,5360.6 U3$CBB19.8@8178.6,5360.6 8218.7,5360.6 8228.9,5350.4 R5$CBB19.1@8250.3,5350.4
M(33)N_TAI2: R9$CBB19.1 R98$CBB15.2 U4$CBB19.8 | length 2174.9
  Inner2 w7.9: v1(8398,5355.2) 8608.2,5355.2 8620.6,5342.8 9036.5,5342.8 9072.1,5378.4 9086.9,5378.4 9110.1,5355.2 9163,5355.2 v1(9209.2,5401.4)
  Inner4 w7.9: v1(8394.2,4206.5) 8394.2,4268.7 8342.8,4320.1 8342.8,4698 8345.8,4700.9 8345.8,5303 v1(8398,5355.2)
  Bottom Layer w7.9: U4$CBB19.8@9196,5360.6 U4$CBB19.8@9196.1,5360.6 ; v1(9209.2,5401.4) 9209.2,5373.6 U4$CBB19.8@9196.1,5360.6 ; R9$CBB19.1@9267.7,5350.4 9246.3,5350.4 9236.1,5360.6 U4$CBB19.8@9196.1,5360.6
M(33)N_TAI3: R13$CBB19.1 R106$CBB15.2 U5$CBB19.8 | length 3394
  Top Layer w7.9: v1(8432.1,4152.5) 8432.1,4121.9 8426.4,4116.1 8426.4,4101.4 8432.1,4095.6 8432.1,4073.8 8431.8,4073.5 8431.8,4070.4 8440.4,4061.9 8440.4,4046.4 8450.1,4036.7 R106$CBB15.2@8450.1,4003.7
  Inner2 w7.9: v1(8458.2,4325.2) 9866.5,4325.2 9873.1,4331.7 9898.5,4331.7 9905.1,4325.2 10075.5,4325.2 10077.2,4323.4 10092,4323.4 10093.7,4325.2 10106.7,4325.2 10111.9,4319.9 10126.7,4319.9 10131.9,4325.2 10265.3,4325.2 v1(10273.3,4333.2)
  Inner4 w7.9: v1(8432.1,4152.5) 8440.4,4160.8 8440.4,4161.9 8450.9,4172.3 8452,4172.3 8462,4182.3 8462,4250.2 8458.2,4253.9 v1(8458.2,4325.2) ; v1(10273.3,4333.2) 10321.5,4381.4 10321.5,5023.9 10341.6,5044 10341.6,5088.5 10335.6,5094.5 10331.5,5094.5 10321.1,5105 10321.1,5119.7 10327,5125.6 10327,5146.9 10314.3,5159.6 10314.3,5272.8 10300.6,5286.5 10300.6,5330.3 10323.5,5353.2 v1(10333.6,5353.2)
  Bottom Layer w7.9: U5$CBB19.8@10213.4,5360.6 10253.5,5360.6 10263.7,5350.4 R13$CBB19.1@10285.1,5350.4 ; R13$CBB19.1@10287.1,5350.4 10330.8,5350.4 v1(10333.6,5353.2)
M(33)N_TAI4: R6$CBB19.1 R16$CBB15.2 R89$CBB15.2 U3$CBB19.14 | length 3044.3
  Top Layer w7.9: R89$CBB15.2@7914.2,3958.7 7915.1,3958.7 v1(7956.3,3917.6) ; v1(9119.8,4233.3) R16$CBB15.2@9157.8,4233.3
  Inner2 w7.9: v1(7956.3,3917.6) 9106.8,3917.6 v1(9118.8,3905.5)
  Inner4 w7.9: v1(7956.3,3917.6) 7982.4,3917.6 8145,4080.2 8145,4851.2 8148.6,4854.8 8148.6,4869.5 8145,4873.2 8145,5070.1 8124.9,5090.2 v1(8108.9,5090.2) ; v1(9118.8,3905.5) 9118.8,4232.3 v1(9119.8,4233.3)
  Bottom Layer w7.9: v1(8108.9,5090.2) 8138.4,5060.6 U3$CBB19.14@8178.6,5060.6 8225.6,5060.6 8236.3,5071.3 R6$CBB19.1@8250.3,5071.3
M(33)N_TAI5: R10$CBB19.1 R17$CBB15.2 R97$CBB15.2 U4$CBB19.14 | length 2130.9
  Top Layer w7.9: R97$CBB15.2@8298.6,4305.1 8325.7,4305.1 v1(8368.9,4261.9) ; v1(9362.7,4233.3) R17$CBB15.2@9400.7,4233.3
  Inner2 w7.9: v1(8368.9,4261.9) 8396.7,4234.1 8972.5,4234.1 8991,4215.5 9248.6,4215.5 9263.9,4230.8 9360.2,4230.8 v1(9362.7,4233.3)
  Inner4 w7.9: v1(9314.5,5071.3) 9311.6,5068.4 9311.6,4875.7 9310.4,4874.5 9310.4,4859.8 9311.6,4858.7 9311.6,4399.4 9362.7,4348.3 v1(9362.7,4233.3)
  Bottom Layer w7.9: U4$CBB19.14@9196,5060.6 9242.9,5060.6 9253.7,5071.3 ; 9253.7,5071.7 v1@9314.5,5071.7
M(33)N_TAI6: R14$CBB19.1 R19$CBB15.2 R105$CBB15.2 U5$CBB19.14 | length 3115.1
  Top Layer w7.9: v1(9605.3,4233.3) R19$CBB15.2@9643.3,4233.3
  Inner2 w7.9: v1(8450.1,3963.7) 8459,3963.7 8476.8,3945.9 8491.5,3945.9 8509.3,3963.7 v1(9602.7,3963.7) ; v1(9646.9,5040) 9677,5070.1 10127.7,5070.1 10137.6,5080 10315.2,5080 v1(10323.8,5071.3)
  Inner4 w7.9: v1(9602.7,3963.7) 9605.3,3966.4 v1(9605.3,4233.3) 9605.3,4910.1 9650.9,4955.6 9650.9,5035.9 v1(9646.9,5040)
  Bottom Layer w7.9: U5$CBB19.14@10213.4,5060.6 10260.3,5060.6 10271.1,5071.3 R14$CBB19.1@10287.1,5071.3 v1(10323.8,5071.3)
M(33)P_TAI1: R3$CBB19.1 R86$CBB15.2 U3$CBB19.1 | length 1015.4
  Top Layer w7.9: v1(7839.8,4206.5) 7882.9,4206.5 R86$CBB15.2@7885.1,4208.7
  Inner4 w7.9: v1(7839.8,4206.5) 7839.8,4677.6 7834.1,4683.2 7834.1,4761.2 7913.7,4840.8 v1(7913.7,5032.2)
  Bottom Layer w7.9: R3$CBB19.1@7885.3,5071.3 7902.9,5071.3 7913.7,5060.6 ; v1(7913.7,5032.2) 7913.7,5060.6 ; U3$CBB19.1@7960.6,5060.6 7913.7,5060.6
M(33)P_TAI2: R7$CBB19.1 R94$CBB15.2 U4$CBB19.1 | length 1765.7
  Top Layer w7.9: R94$CBB15.2@8394.2,4008.7 8394.2,4046.3 v1(8414.1,4066.1)
  Inner2 w7.9: v1(8432.1,5066.1) 8599.8,5066.1 8612.1,5078.4 8626.9,5078.4 8639.2,5066.1 8659,5066.1 8681.1,5044 8754,5044 8764.4,5054.4 8789.8,5054.4 8800.3,5044 8919.3,5044 v1(8931.1,5032.2)
  Inner4 w7.9: v1(8414.1,4066.1) 8404.3,4075.9 8404.3,4191.5 8412,4199.2 8412,4269.2 8404.3,4276.8 8404.3,4537.5 8400.5,4541.3 8400.5,4556.1 8404.3,4559.9 8404.3,4624.6 8474.3,4694.6 8474.3,5007.8 8432.1,5050 v1(8432.1,5066.1)
  Bottom Layer w7.9: R7$CBB19.1@8902.7,5071.3 8920.3,5071.3 8931.1,5060.6 ; v1(8931.1,5032.2) 8931.1,5060.6 ; U4$CBB19.1@8978,5060.6 8931.1,5060.6
M(33)P_TAI3: R11$CBB19.1 R102$CBB15.2 U5$CBB19.1 | length 2425.1
  Top Layer w7.9: v1(8436.1,4251.9) 8445.1,4242.9 R102$CBB15.2@8445.1,4208.7
  Inner2 w7.9: v1(8436.1,4251.9) 8436.1,4253 8444,4260.9 9490.3,4260.9 9498.2,4268.8 9909.8,4268.8 v1(9924,4283)
  Inner4 w7.9: v1(9924,4283) 9924,4666.9 9912.8,4678 9912.8,4776.2 9924,4787.3 9924,5007.7 v1(9948.5,5032.2)
  Bottom Layer w7.9: R11$CBB19.1@9920.1,5071.3 9937.7,5071.3 9948.5,5060.6 ; v1(9948.5,5032.2) 9948.5,5060.6 ; U5$CBB19.1@9995.4,5060.6 9948.5,5060.6
M(33)P_TAI4: R4$CBB19.1 R22$CBB15.2 R85$CBB15.2 U3$CBB19.7 | length 2959.8
  Top Layer w7.9: v1(7841.8,4111.7) 7923.1,4111.7 R85$CBB15.2@7925.1,4113.7 ; v1(9034.5,4068.7) 9034.5,4231.5 R22$CBB15.2@9036.3,4233.3
  Inner2 w7.9: v1(7841.8,4111.7) 7867.3,4086.2 9016.9,4086.2 v1(9034.5,4068.7)
  Inner4 w7.9: v1(7841.8,4111.7) 7813.7,4139.8 7813.7,4759 7834.1,4779.4 7834.1,5052.4 7900,5118.3 7900,5154.9 7917.9,5172.8 7917.9,5255.2 7918.2,5255.5 7918.2,5270.2 7906.1,5282.3 7906.1,5383.3 v1(7890,5399.4)
  Bottom Layer w7.9: R4$CBB19.1@7885.3,5350.4 7905.4,5350.4 7915.6,5360.6 U3$CBB19.7@7939.9,5360.6 ; v1(7890,5399.4) 7901.1,5399.4 U3$CBB19.7@7939.9,5360.6 ; U3$CBB19.7@7960.6,5360.6 U3$CBB19.7@7939.9,5360.6
M(33)P_TAI5: R8$CBB19.1 R18$CBB15.2 R93$CBB15.2 U4$CBB19.7 | length 2693.4
  Top Layer w7.9: v1(8359.8,3939.6) 8360.1,3939.9 R93$CBB15.2@8360.1,3968.7 ; v1(9066.6,4407.5) 9068.6,4409.5 9138.9,4409.5 9243.3,4305.1 v1@9243.3,4233.3 ; v1(9241.3,4233.3) v1@9243.3,4233.3 ; R18$CBB15.2@9279.3,4233.3 v1@9243.3,4233.3
  Inner2 w7.9: v1(8359.8,3939.6) 8422.1,3939.6 8428.7,3933.1 9236.7,3933.1 v1(9241.3,3937.6)
  Inner4 w7.9: v1(9066.6,4407.5) 9066.6,4791 9057.1,4800.5 9057.1,5166.9 9077.1,5186.9 9077.1,5293.7 9094.5,5311.1 v1(9094.5,5332.2) ; v1(9241.3,3937.6) v1(9241.3,4233.3)
  Bottom Layer w7.9: R8$CBB19.1@8902.7,5350.4 8922.8,5350.4 8932.9,5360.6 U4$CBB19.7@8978.1,5360.6 9031.1,5360.6 9059.5,5332.2 v1(9094.5,5332.2)
M(33)P_TAI6: R12$CBB19.1 R21$CBB15.2 R101$CBB15.2 U5$CBB19.7 | length 3002.5
  Top Layer w7.9: v1(8454.2,4130.8) 8473,4130.8 R101$CBB15.2@8495.1,4108.7 ; v1(9477.9,4227.3) 9515.9,4227.3 R21$CBB15.2@9521.9,4233.3
  Inner2 w7.9: v1(8454.2,4130.8) 8504.8,4130.8 8518.5,4144.4 8696.1,4144.4 8705.9,4134.7 9059,4134.7 9069.4,4145.1 9327,4145.1 9327.7,4144.4 9395,4144.4 v1(9477.9,4227.3) 9485.4,4234.8 9581.7,4234.8 9598,4251.1 9734.2,4251.1 9750.5,4234.8 9901,4234.8 9935.1,4268.9 v1(9946.1,4268.9)
  Inner4 w7.9: v1(9946.1,4268.9) 9946.1,4634.4 10004.3,4692.6 10004.3,4817.1 10084.6,4897.4 10084.6,4947.6 10096.8,4959.8 10096.8,5183.9 10094.3,5186.4 10094.3,5201.1 10096.8,5203.6 10096.8,5291.6 10106.9,5301.7 v1(10106.9,5332.2)
  Bottom Layer w7.9: R12$CBB19.1@9920.1,5350.4 9940.2,5350.4 9950.3,5360.6 U5$CBB19.7@9995.4,5360.6 10048.5,5360.6 10076.9,5332.2 v1(10106.9,5332.2)
MAT33_LED_ON: Q7$CBB15.1 Q8$CBB15.1 Q9$CBB15.1 Q10$CBB15.1 Q11$CBB15.1 Q12$CBB15.1 U1$CBB23.K1 | length 9030.5
  Top Layer w4.7: v1(3735.9,5622.4) 3739.4,5625.9 U1$CBB23.K1@3766.7,5625.9
  Top Layer w7.9: v1(9076.7,3771) Q11$CBB15.1@9076.7,4076.1 Q7$CBB15.1@9198.2,4076.1 Q9$CBB15.1@9319.6,4076.1 Q8$CBB15.1@9441.1,4076.1 Q12$CBB15.1@9562.6,4076.1 Q10$CBB15.1@9684,4076.1
  Inner2 w4.7: v1(3813.6,3124.6) 6904.3,3124.6 7543.5,3763.8 9016.4,3763.8
  Inner2 w7.9: 9016.4,3763.8 9069.5,3763.8 v1(9076.7,3771)
  Inner4 w4.7: v1(3735.9,5622.4) 3735.9,5475.1 3715.8,5455 3715.8,5441.5 3722.3,5435 3722.3,5202.3 3735.9,5188.7 3735.9,5188.4 3818,5106.2 3818,4235.1 3810,4227.1 3810,4010.8 3807.8,4008.6 3807.8,3995.2 3810,3993 3810,3128.3 v1(3813.6,3124.6)
OUT1_ADC(45): U7$CBB7.5 U100$CBB22.G5 | length 1801.8
  Top Layer w7.9: U7$CBB7.5@6886.6,5006.9 6886.6,4959.7 v1(6886.8,4959.5)
  Inner2 w3.9: v2(5593,4494.2) 5605.8,4507 5716,4507
  Inner2 w4.7: v1(6648.8,4937.9) 6865.2,4937.9 v1(6886.8,4959.5)
  Inner2 w5.5: 5716,4507 5768.5,4507 5781.7,4493.8 v1(6643.1,4493.8)
  Inner4 w5.5: v1(6643.1,4493.8) 6648.8,4499.5 v1(6648.8,4937.9)
OUT1_ADC(49): U7$CBB21.5 U100$CBB22.R9 | length 1891.8
  Top Layer w7.9: U7$CBB21.5@7105.9,5006.9 7105.9,4959.7 v1(7106.1,4959.5)
  Inner2 w3.9: v2(5490.7,4698.9) 5503.5,4711.7 5503.5,4796.2
  Inner2 w4.7: 5503.5,4796.2 5503.5,4831.5 5518.6,4846.6 5743.5,4846.6 5816.4,4919.5 6489.4,4919.5 6489.8,4919.9 6503.3,4919.9 6521.6,4901.6 6529.4,4901.6 6529.9,4902.1 6535.4,4896.7 6675.1,4896.7 6688.6,4883.2 6702,4883.2 6715.6,4896.7 6933.6,4896.7 7010.1,4973.2 7054.2,4973.2 7064.8,4983.7 7081.8,4983.7 v1(7106.1,4959.5)
OUT2_ADC(45): U1$CBB7.5 U100$CBB22.K6 | length 1455.7
  Top Layer w3.9: U100$CBB22.K6@5567.4,4571 5580.4,4558.1 5664.4,4558.1 5664.5,4558.2 5675.1,4558.2 5675.2,4558.1 5716,4558.1
  Top Layer w5.5: 5716,4558.1 5758.2,4558.1 5758.8,4558.6 5772.6,4558.6 5773.1,4558.1 v1(5803.8,4558.1)
  Top Layer w7.9: U1$CBB7.5@6887.1,4804.9 6887.1,4757.7 v1(6887.3,4757.5)
  Inner2 w4.7: v1(5803.8,4558.1) 6034.7,4558.1 6214.3,4737.6 6867.4,4737.6 v1(6887.3,4757.5)
OUT2_ADC(49): U1$CBB21.5 U100$CBB22.T9 | length 2292.2
  Top Layer w7.9: U1$CBB21.5@7107.1,4804.9 7107.1,4757.7 v1(7107.3,4757.5)
  Inner2 w5.5: v1(5528.5,5036.4) 5549.8,5015.1 6787.1,5015.1 6790.8,5011.3 6804.6,5011.3 6804.8,5011.5 7044.3,5011.5 v1(7086.9,5054)
  Inner4 w4.7: v2(5490.7,4724.5) 5490.7,4972.3 5490.4,4972.5 5490.4,4986.5 5489.7,4987.1 5492.5,4989.9 5492.5,4999.4 5493.5,5000.3 5493.5,5009 5500.8,5016.3 5509.4,5016.3 5511.6,5018.5 5516.4,5018.5 5524.9,5010 5528.5,5013.6 v1(5528.5,5036.4)
  Inner4 w5.5: v1(7086.9,5054) 7086.9,4778 v1(7107.3,4757.5)
OUT3_ADC(45): U3$CBB7.5 U100$CBB22.G6 | length 1396.4
  Top Layer w3.9: U100$CBB22.G6@5567.4,4494.2 5581.1,4507.9 5587.4,4507.9 5587.9,4507.4 5623.8,4507.4 5624.2,4507 5700.7,4507 5701.6,4507.9 5716,4507.9
  Top Layer w5.5: 5716,4507.9 5842,4507.9 v1(5846,4511.9)
  Top Layer w7.9: U3$CBB7.5@6887.1,4609.9 6887.1,4562.7 v1(6887.3,4562.5)
  Inner2 w4.7: v1(5846,4511.9) 5876.7,4542.6 6867.4,4542.6 v1(6887.3,4562.5)
OUT3_ADC(49): U3$CBB21.5 U100$CBB22.P11 | length 2762.1
  Top Layer w7.9: U3$CBB21.5@7107.1,4609.9 7107.1,4562.7 v1(7107.3,4562.5)
  Inner2 w5.5: v1(5420.3,5100.2) 5475,5100.2 5479.5,5104.7 5493.2,5104.7 5497.7,5100.2 5510.7,5100.2 5519.3,5091.6 5537.6,5091.6 5546.2,5100.2 6627.6,5100.2 6628.2,5099.6 6642,5099.6 6642.5,5100.2 7117,5100.2 v1(7119,5098.2)
  Inner4 w3.9: v2(5439.5,4673.3) 5452.3,4686.1 5452.3,4796.2
  Inner4 w4.7: v1(5420.3,5100.2) 5420.3,4997.2 5422.7,4994.8 5422.7,4983.4 5432.4,4973.7 5432.4,4965.1 5434.7,4962.7 5434.7,4949.3 5432.4,4946.9 5432.4,4931.2 5444.8,4918.8 5444.8,4907.9 5450.1,4902.6 5444.8,4897.2 5444.8,4883.8 5447.1,4881.5 5440.7,4875.1 5440.7,4861.7 5450.2,4852.2 5452.3,4852.2 5452.3,4796.2
  Inner4 w5.5: v1(7107.3,4562.5) 7125,4580.2 7125,4993.8 7119,4999.8 v1(7119,5098.2)
OUT4_ADC(45): U2$CBB7.5 U100$CBB22.H6 | length 1490
  Top Layer w3.9: U100$CBB22.H6@5567.4,4519.8 5579.8,4532.2 5638.5,4532.2 5638.9,4532.6 5700.7,4532.6 5701.1,4532.2 5716,4532.2
  Top Layer w5.5: 5716,4532.2 5752,4532.2 5758.8,4525.4 5772.6,4525.4 5779.4,4532.2 5859.8,4532.2 5880.1,4511.9 v1(5880.1,4469.7)
  Top Layer w7.9: U2$CBB7.5@6887.1,4409.9 6887.1,4362.7 v1(6887.3,4362.5)
  Inner2 w4.7: 6736,4342.6 6867.4,4342.6 v1(6887.3,4362.5)
  Inner2 w5.5: v1(5880.1,4469.7) 5934.3,4469.7 6061.4,4342.6 6736,4342.6
OUT4_ADC(49): U2$CBB21.5 U100$CBB22.N11 | length 2518.7
  Top Layer w7.9: U2$CBB21.5@7105.9,4412.2 7105.9,4364.9 v1(7106.1,4364.7)
  Inner2 w3.9: 5426.3,4750.8 5426.3,4730.2 5426.7,4729.8 5426.7,4668 5426.3,4667.7 5426.3,4660.9 v2(5439.5,4647.8)
  Inner2 w4.7: 5426.3,4750.8 5426.3,4795.6 5506.5,4875.8 5731.4,4875.8 5804.3,4948.7 6460.3,4948.7 v1(6466.8,4955.2)
  Inner2 w5.5: v1(6468.4,4395.4) 7075.4,4395.4 v1(7106.1,4364.7)
  Inner4 w5.5: v1(6466.8,4955.2) 6466.8,4397 v1(6468.4,4395.4)
OUT5_ADC(45): U5$CBB7.5 U100$CBB22.N12 | length 3144.1
  Top Layer w7.9: U5$CBB7.5@6887.1,4209.9 6887.1,4162.7 v1(6887.3,4162.5)
  Inner2 w4.7: v1(6725.4,4142.4) 6725.6,4142.6 6790.7,4142.6 6791,4142.3 6804.4,4142.3 6804.8,4142.6 6867.4,4142.6 v1(6887.3,4162.5)
  Inner2 w5.5: v1(5384.2,5166.5) 5387.8,5170 6707.8,5170 v1(6711.4,5166.5)
  Inner4 w3.9: 5401.1,4733.9 5401.1,4660.6 v2(5413.9,4647.8)
  Inner4 w4.7: v1(5384.2,5166.5) 5378.1,5166.5 5358.1,5146.4 5358.1,5046.8 5355.9,5044.7 5355.9,5031.2 5358.1,5029.1 5358.1,5022.3 5356.4,5020.6 5356.4,5007.1 5358.1,5005.4 5358.1,4855.2 5390.2,4823.1 5390.2,4744.8 5401.1,4733.9
  Inner4 w5.5: v1(6711.4,5166.5) 6717.4,5160.4 6717.4,4980.7 6709.2,4972.6 6709.2,4958.8 6717.4,4950.6 6717.4,4150.5 v1(6725.4,4142.4)
OUT5_ADC(49): U5$CBB21.5 U100$CBB22.P10 | length 3052.7
  Top Layer w7.9: U5$CBB21.5@7105.9,4213.9 7105.9,4166.7 v1(7106.1,4166.5)
  Inner2 w5.5: v1(5456.3,5074.2) 5462.4,5068.1 5489.8,5068.1 5496.8,5075 5506.1,5075 5513.1,5068.1 v1(6735.9,5068.1) ; v1(6739.5,4174.6) 6790.3,4174.6 6790.8,4175.1 6796.3,4175.1 6803.7,4182.6 7090,4182.6 v1(7106.1,4166.5)
  Inner4 w3.9: v2(5465.1,4673.3) 5477.9,4686.1 5477.9,4729.8 5476.5,4731.2 5476.5,4796.2
  Inner4 w4.7: v1(5456.3,5074.2) 5456.3,5000 5464.3,4991.9 5471.2,4991.9 5480.7,4982.4 5480.7,4969 5476.5,4964.8 5476.5,4922 5477.2,4921.3 5477.2,4907.9 5476.5,4907.2 5476.5,4897.9 5477.2,4897.2 5477.2,4883.8 5476.5,4883.1 5476.5,4796.2
  Inner4 w5.5: v1(6735.9,5068.1) 6759.6,5044.4 6759.6,4979.1 6766.1,4972.6 6766.1,4958.8 6759.6,4952.2 6759.6,4216.7 6739.5,4196.7 v1(6739.5,4174.6)
OUT6_ADC(45): U4$CBB7.5 U100$CBB22.P12 | length 2723.8
  Top Layer w7.9: U4$CBB7.5@6887.1,4009.9 6887.1,3962.7 v1(6887.3,3962.5)
  Inner2 w3.9: 5402.2,4787.7 5402.2,4731 5401.1,4729.8 5401.1,4693.6 5413.9,4680.8 v2(5413.9,4673.3)
  Inner2 w4.7: 5402.2,4787.7 5408.9,4794.4 5411.4,4794.4 5502.5,4885.5 5727.4,4885.5 5800.2,4958.4 6447.1,4958.4 6460.1,4971.4 6567.1,4971.4 6632.1,4906.4 6688.3,4906.4 v1(6695.3,4899.4) ; 6745.2,3942.6 6746.2,3941.7 6866.5,3941.7 v1(6887.3,3962.5)
  Inner2 w5.5: v1(6695.3,3943.7) 6744.2,3943.7 6745.2,3942.6
  Inner4 w5.5: v1(6695.3,3943.7) v1(6695.3,4899.4)
OUT6_ADC(49): U4$CBB21.5 U100$CBB22.N10 | length 2878.5
  Top Layer w7.9: U4$CBB21.5@7105.9,4010.7 7105.9,3963.4 v1(7106.1,3963.3)
  Inner2 w3.9: 5452.4,4796.2 5452.4,4730 5452.3,4729.8 5452.3,4693.6 5452.4,4693.5 5452.4,4678.8 5452.3,4678.6 5452.3,4660.6 v2(5465.1,4647.8)
  Inner2 w4.7: 5452.4,4796.2 5452.4,4808 5510.5,4866.1 5735.4,4866.1 5808.3,4938.9 6481.3,4938.9 6481.8,4939.4 6520.5,4939.4 v1(6527.9,4932)
  Inner2 w5.5: v1(6524.6,3995.9) 7073.5,3995.9 v1(7106.1,3963.3)
  Inner4 w5.5: v1(6524.6,3995.9) 6527.9,3999.2 v1(6527.9,4932)
RCK_DAC(2): U6$CBB16/CBB1.12 U6$CBB16/CBB2.12 U6$CBB16/CBB3.12 U6$CBB16/CBB4.12 U6$CBB16/CBB5.12 U6$CBB16/CBB6.12 U100$CBB22.B14 | length 7557.9
  Top Layer w4.3: U100$CBB22.B14@5362.7,4366.3 5362.7,4358.5 5375.3,4345.9 5375.3,4331.5 5375.7,4331.2
  Top Layer w4.7: v1(5237.5,4140.4) 5375.7,4278.5 5375.7,4331.2
  Top Layer w7.9: v1(4982.4,7590.2) 5094.5,7590.2 U6$CBB16/CBB4.12@5095.7,7591.3 ; v1(4988.5,6684.7) 5094.5,6684.7 U6$CBB16/CBB6.12@5095.7,6685.8 ; v1(4988.5,7135.7) 5092.8,7135.7 U6$CBB16/CBB5.12@5095.7,7138.6 ; v1(4992,8043) 5094.5,8043 U6$CBB16/CBB3.12@5095.7,8044.1 ; v1(4992,8495.7) 5094.5,8495.7 U6$CBB16/CBB1.12@5095.7,8496.8 ; v1(4992,8948.5) 5094.5,8948.5 U6$CBB16/CBB2.12@5095.7,8949.6
  Inner2 w4.7: v1(5044.4,5485.3) 5044.4,5482.4 5049.1,5477.7 5280.9,5477.7 5285.1,5481.9 5298.5,5481.9 5302.7,5477.7 5898.3,5477.7 5969.7,5406.3 v1(5988.5,5406.3)
  Inner4 w4.7: v1(4988.5,6684.7) 4990.9,6682.2 4990.9,6425.4 5041.1,6375.2 5041.1,5489.7 5047.5,5483.4 5046.3,5483.4 v1(5044.4,5485.3) ; v1(5237.5,4140.4) 5369.3,4140.4 5389.2,4120.5 5412.7,4120.5 5417.4,4115.8 5496.2,4115.8 5505.2,4106.7 5518.7,4106.7 5523,4111.1 5531,4111.1 5558.4,4138.4 6015.1,4138.4 6081.9,4205.2 6081.9,5314.2 5989.8,5406.3 v1(5988.5,5406.3)
  Inner4 w7.9: v1(4988.5,6684.7) v1(4988.5,7135.7) 4982.4,7141.7 v1(4982.4,7590.2) 4987.4,7595.1 4987.4,8020.3 4992,8024.9 v1(4992,8043) 4985.4,8049.6 4985.4,8489.1 v1(4992,8495.7) v1(4992,8948.5)
RCK_DAC_W(12): U6$CBB18/CBB1.12 U6$CBB18/CBB2.12 U6$CBB18/CBB3.12 U6$CBB18/CBB4.12 U6$CBB18/CBB5.12 U6$CBB18/CBB6.12 U6$CBB18/CBB7.12 U6$CBB18/CBB8.12 U100$CBB22.K15 | length 7349.2
  Top Layer w7.9: v1(6228,5774.5) 6344.8,5774.5 U6$CBB18/CBB8.12@6350.6,5780.3 ; v1(6230.7,6231.9) 6349.5,6231.9 U6$CBB18/CBB7.12@6350.6,6233.1 ; v1(6241.4,6684.7) 6349.5,6684.7 U6$CBB18/CBB6.12@6350.6,6685.8 ; v1(6246.9,7590.2) 6349.5,7590.2 U6$CBB18/CBB4.12@6350.6,7591.3 ; v1(6246.9,8043) 6349.5,8043 U6$CBB18/CBB3.12@6350.6,8044.1 ; v1(6246.9,8495.7) 6349.5,8495.7 U6$CBB18/CBB2.12@6350.6,8496.8 ; v1(6246.9,8948.5) 6349.5,8948.5 U6$CBB18/CBB1.12@6350.6,8949.6 ; v1(6249.7,7137.4) 6349.5,7137.4 U6$CBB18/CBB5.12@6350.6,7138.6
  Inner2 w3.9: 5295.8,4557.1 5296.9,4558.2 5324.3,4558.2 v2(5337.1,4571)
  Inner2 w4.7: v1(4776.3,5055.8) 4774.2,5053.7 4768.9,5053.7 4736.7,5021.5 4736.7,4708.9 4731.9,4704.1 4731.9,4690.2 4734.7,4687.4 4734.7,4674 4733.9,4673.2 4733.9,4657.4 4885.7,4505.7 5158.8,4505.7 5210.2,4557.1 5295.8,4557.1 ; v1(4795.9,5750.7) 6204.2,5750.7 v1(6228,5774.5)
  Inner4 w4.7: v1(4776.3,5055.8) 4776.3,5135.3 4773.1,5138.6 4773.1,5176.2 4776.3,5179.4 4776.3,5222.6 4770.3,5228.7 4770.3,5258.2 4776.3,5264.3 4776.3,5369.9 4767.8,5378.4 4767.8,5535.9 4795.9,5564 v1(4795.9,5750.7)
  Inner4 w7.9: v1(6228,5774.5) 6238.9,5785.4 6238.9,6122.9 6228.2,6133.6 6228.2,6197.2 6230.7,6199.6 v1(6230.7,6231.9) 6230.7,6242.5 6239.3,6251 6239.3,6581.3 6233.2,6587.4 6233.2,6658 6241.4,6666.1 v1(6241.4,6684.7) 6241.4,6686 6246.3,6691 6246.3,7134 v1(6249.7,7137.4) 6246.9,7140.3 6246.9,7281.5 6242.3,7286.1 6242.3,7548.5 6246.9,7553.1 v1(6246.9,7590.2) 6246.9,7984.4 6247.2,7984.8 6247.2,7999.5 6246.9,7999.9 v1(6246.9,8043) v1(6246.9,8495.7) v1(6246.9,8948.5)
RCK_DAC_W(15): U6$CBB17/CBB1.12 U6$CBB17/CBB2.12 U6$CBB17/CBB3.12 U6$CBB17/CBB4.12 U6$CBB17/CBB5.12 U6$CBB17/CBB6.12 U6$CBB17/CBB7.12 U6$CBB17/CBB8.12 U100$CBB22.B10 | length 6646.6
  Top Layer w4.3: U100$CBB22.B10@5465.1,4366.3 5465.1,4358.5 5477.7,4345.9 5477.7,4331.5 5478,4331.2
  Top Layer w4.7: 5478,4331.2 5478,4215.8 5482.4,4211.4 5482.4,4189.9 5479.6,4187.1 5479.6,4182.4 5498.7,4163.2 v1(5507.5,4163.2)
  Top Layer w7.9: v1(5617,8495.7) 5719.5,8495.7 U6$CBB17/CBB2.12@5720.7,8496.8 ; v1(5617,8948.5) 5719.5,8948.5 U6$CBB17/CBB1.12@5720.7,8949.6 ; v1(5617.2,5779.2) 5719.5,5779.2 U6$CBB17/CBB8.12@5720.7,5780.3 ; v1(5618.9,6684.7) 5719.5,6684.7 U6$CBB17/CBB6.12@5720.7,6685.8 ; v1(5620.9,7590.2) 5719.5,7590.2 U6$CBB17/CBB4.12@5720.7,7591.3 ; v1(5622.8,6231.9) 5719.5,6231.9 U6$CBB17/CBB7.12@5720.7,6233.1 ; v1(5625,8043) 5719.5,8043 U6$CBB17/CBB3.12@5720.7,8044.1 ; v1(5632,7143.4) 5715.8,7143.4 U6$CBB17/CBB5.12@5720.7,7138.6
  Inner4 w4.7: v1(5507.5,4163.2) 5524.7,4163.2 5530.7,4169.2 5534.5,4169.2 5545.2,4180 6015.4,4180 6052.8,4217.3 6052.8,5153.8 5998,5208.6 5998,5291 5928.9,5360 5928.9,5506.4 5928.5,5506.9 5920.5,5506.9 5905.3,5522 5905.3,5546.3 5790.7,5660.9 5635.7,5660.9 5610.1,5686.5 5610.1,5772 v1(5617.2,5779.2)
  Inner4 w7.9: v1(5617,8948.5) v1(5617,8495.7) 5617,8144 5620,8140.9 5620,8047.9 v1(5625,8043) 5625,7893.4 5620.9,7889.4 v1(5620.9,7590.2) 5633.1,7578 5633.1,7144.6 v1(5632,7143.4) 5632,6697.7 v1(5618.9,6684.7) 5618.9,6603.6 5624.8,6597.7 5624.8,6556.4 5620,6551.6 5620,6402 5630.1,6391.9 5630.1,6258.1 5618.9,6246.9 5618.9,6235.8 v1(5622.8,6231.9) 5622.8,6105.8 5625.7,6102.8 5625.7,6047.2 5622.8,6044.3 5622.8,5909 5625.7,5906 5625.7,5860.5 5622.8,5857.5 5622.8,5784.7 v1(5617.2,5779.2)
RCK_DAC_W(34): U6$CBB20/CBB1.12 U6$CBB20/CBB2.12 U6$CBB20/CBB3.12 U6$CBB20/CBB4.12 U6$CBB20/CBB5.12 U6$CBB20/CBB6.12 U6$CBB20/CBB7.12 U6$CBB20/CBB8.12 U100$CBB22.E12 U112$CBB22.1 | length 7935.6
  Top Layer w7.9: v1(6876.8,5779.2) 6979.4,5779.2 U6$CBB20/CBB8.12@6980.5,5780.3 ; v1(6876.8,6231.9) 6979.4,6231.9 U6$CBB20/CBB7.12@6980.5,6233.1 ; v1(6876.8,6684.7) 6979.4,6684.7 U6$CBB20/CBB6.12@6980.5,6685.8 ; v1(6876.8,7590.2) 6979.4,7590.2 U6$CBB20/CBB4.12@6980.5,7591.3 ; v1(6876.8,8043) 6979.4,8043 U6$CBB20/CBB3.12@6980.5,8044.1 ; v1(6876.8,8495.7) 6979.4,8495.7 U6$CBB20/CBB2.12@6980.5,8496.8 ; v1(6876.8,8948.5) 6979.4,8948.5 U6$CBB20/CBB1.12@6980.5,8949.6 ; v1(6879.9,7137.4) 6979.4,7137.4 U6$CBB20/CBB5.12@6980.5,7138.6
  Inner2 w4.7: v1(5440.4,4220.7) 5438.4,4218.7 5438.4,4174.6 5431.5,4167.7 5431.5,4114 5437.5,4108 5437.5,4107.6 5438.2,4106.9 5438.2,4106.6 5438.4,4106.4 5438.4,4062.7 5440.2,4060.8 5440.2,4039.3 5438.4,4037.5 5438.4,3819.2 5583,3674.6 5710.2,3674.6 U112$CBB22.1@5739.8,3704.1
  Inner4 w3.9: v2(5413.9,4443) 5416.9,4443 5426.3,4433.6 5426.3,4423.1 5426.7,4422.7 5426.7,4361 5426.3,4360.6 5426.3,4322.4 5426.7,4322.1
  Inner4 w4.7: 5426.7,4322.1 5426.7,4234.4 v1(5440.4,4220.7) ; U112$CBB22.1@5739.8,3704.1 5781.3,3662.6 5992.8,3662.6 6374.7,4044.5 6374.7,5295.1 6442.5,5362.9 6695.9,5362.9 6868.3,5535.3 6868.3,5768.2 6876.8,5776.7 v1(6876.8,5779.2)
  Inner4 w7.9: v1(6876.8,5779.2) v1(6876.8,6231.9) v1(6876.8,6684.7) 6879.9,6687.8 v1(6879.9,7137.4) 6879.9,7160.2 6886.9,7167.2 6886.9,7228.1 6888,7229.2 6888,7243.9 6876.8,7255.1 6876.8,7521.6 6883.2,7528 6883.2,7542.8 6876.8,7549.2 v1(6876.8,7590.2) 6876.8,7667.9 6878.8,7669.9 6878.8,7684.6 6876.8,7686.7 v1(6876.8,8043) v1(6876.8,8495.7) v1(6876.8,8948.5)
SCK_DAC1_DAC(2): U6$CBB16/CBB1.11 U100$CBB22.G14 | length 4590
  Top Layer w7.9: v1(4931.9,8470.9) 4957.9,8444.9 5093.8,8444.9 U6$CBB16/CBB1.11@5095.7,8446.8
  Inner4 w3.9: 5242,4481.9 5242.4,4481.4 5349.9,4481.4 v2(5362.7,4494.2)
  Inner4 w4.7: v1(4931.9,8470.9) 4886.2,8425.2 4886.2,8314.9 4886.1,8314.9 4886.1,7192.6 4886.2,7192.5 4886.2,7164.3 4906.3,7144.2 4906.3,6632.2 4964.5,6574 4964.5,6559.5 4957.8,6552.7 4957.8,6540.3 4954.2,6536.7 4954.2,6511.4 4930.1,6487.3 4930.1,5197 4952.8,5174.3 4952.8,5160.9 4946.3,5154.4 4946.3,5071.9 4962.5,5055.7 4962.5,5039.5 4964.5,5037.5 4964.5,4590.2 5072.9,4481.9 5242,4481.9
SCK_DAC1_W(12): U6$CBB18/CBB1.11 U100$CBB22.G18 | length 7079.1
  Top Layer w4.7: v1(5068.9,3853.3) 5068.9,3871.4 5052.2,3888.1 5052.2,4192.6 5094.4,4234.8 5094.4,4390.6 5198,4494.2 U100$CBB22.G18@5260.4,4494.2
  Top Layer w7.9: U6$CBB18/CBB1.11@6350.6,8899.6 6352.5,8897.7 v1@6420.2,8897.7
  Inner4 w4.7: v1(5068.9,3853.3) 5069.1,3853.1 5105.5,3853.1 5132.4,3880 5178.4,3880 5212.1,3913.7 5259.6,3913.7 5263,3917.1 5312.1,3917.1 5313.4,3918.3 5618.2,3918.3 5630.2,3930.4 6054.3,3930.4 6227.8,4103.9 6227.8,5354.5 6386.2,5512.9 6399.2,5512.9 6442.3,5556 6442.3,6527.8 6454.4,6539.8 6454.4,7543.8 6522.6,7612 6522.6,7736.5 6466.4,7792.8 6466.4,8350.9 6428.3,8389.1 6428.3,8433.3 6440.3,8445.3 6440.3,8877 v1(6420.2,8897.1)
SCK_DAC1_W(15): U6$CBB17/CBB1.11 U100$CBB22.V13 | length 4393.8
  Top Layer w4.7: v1(5386.2,5192.2) 5359.8,5165.8 5359.8,5048.5 5355.9,5044.7 5355.9,5031.2 5359.8,5027.4 5359.8,5024 5356.4,5020.6 5356.4,5007.1 5359.8,5003.7 5359.8,4869.5 5359.5,4869.3 5359.5,4865.4 5358.5,4864.4 5358.5,4842.9 5373.7,4827.7 5388.3,4827.7 U100$CBB22.V13@5388.3,4775.7
  Top Layer w7.9: v1(5567.4,8901.7) 5718.6,8901.7 U6$CBB17/CBB1.11@5720.7,8899.6
  Inner4 w4.7: v1(5386.2,5192.2) 5386.2,5244.8 5480.6,5339.1 5480.6,8336.6 5480.9,8336.9 5480.9,8387.4 5567.4,8473.9 v1(5567.4,8901.7)
SCK_DAC1_W(34): U6$CBB20/CBB1.11 U100$CBB22.B15 | length 7085
  Top Layer w4.3: U100$CBB22.B15@5337.1,4366.3 5337.1,4358.5 5349.7,4345.9 5349.7,4331.5 5350.1,4331.2
  Top Layer w4.7: v1(5292.5,3862.7) 5284.3,3854.5 5278.1,3854.5 5272.9,3849.3 5268.6,3849.3 5267.7,3848.4 5244.5,3848.4 5237.9,3855 5237.9,4022 5199.8,4060.1 5199.8,4137.9 5211.5,4149.7 5211.5,4151.1 5226.7,4166.3 5228.1,4166.3 5248,4186.2 5255.8,4186.2 5350.1,4280.5 5350.1,4331.2
  Top Layer w7.9: v1(6853.4,8897.7) 6978.6,8897.7 U6$CBB20/CBB1.11@6980.5,8899.6
  Inner4 w4.7: v1(5292.5,3862.7) 5299.1,3862.7 5314.7,3878.2 5328.3,3878.2 5329.5,3879.4 5634.3,3879.4 5646.4,3891.5 6070.4,3891.5 6267.6,4088.7 6267.6,5339.3 6402,5473.7 6655.4,5473.7 6689.3,5507.6 6689.3,5640.3 6719.4,5670.4 6719.4,6029.8 6689.3,6060 6689.3,6094.1 6719.4,6124.2 6719.4,6311.1 6757.6,6349.2 6757.6,8414.9 6805.7,8463.1 6805.7,8830.8 6853.4,8878.4 v1(6853.4,8897.7)
SCK_DAC2_DAC(2): U6$CBB16/CBB2.11 U100$CBB22.F14 | length 5114.3
  Top Layer w7.9: v1(5012.7,8897.7) 5093.8,8897.7 U6$CBB16/CBB2.11@5095.7,8899.6
  Inner2 w4.7: v1(4936.6,5167.6) 4967.9,5167.6 4968.4,5168.1 4981.9,5168.1 4982.4,5167.6 5078.2,5167.6 v1(5095.4,5150.4)
  Inner4 w3.9: 5242,4456.3 5242.4,4455.8 5349.9,4455.8 v2(5362.7,4468.6)
  Inner4 w4.7: v1(4936.6,5167.6) 4936.6,5067.9 4952.8,5051.7 4952.8,5035.5 4954.8,5033.5 4954.8,4586.2 5084.7,4456.3 5242,4456.3 ; v1(5012.7,8897.7) 5012.7,8473.4 4996.7,8457.4 4996.7,8435.3 5000.7,8431.3 5000.7,8057.8 5010.7,8047.8 5010.7,8027.7 4998.7,8015.6 4998.7,7150.2 5004.7,7144.2 5004.7,6663.6 5000.7,6659.6 5000.7,6429.4 5050.9,6379.2 5050.9,5541.9 5066.7,5526.1 5066.7,5492 5095.4,5463.3 v1(5095.4,5150.4)
SCK_DAC2_W(12): U6$CBB18/CBB2.11 U100$CBB22.E17 | length 6284.1
  Top Layer w4.3: 5250.9,4430.1 5251.2,4430.4 5273.3,4430.4 U100$CBB22.E17@5285.9,4443
  Top Layer w4.7: v1(5143.2,3941.7) 5131.2,3941.7 5124,3934.5 5123.5,3934.5 5118.4,3929.4 5105,3929.4 5092.5,3941.9 5092.5,4176.8 5134.7,4219 5134.7,4373.9 5190.8,4430.1 5250.9,4430.1
  Top Layer w7.9: v1(6267.6,8444.9) 6348.7,8444.9 U6$CBB18/CBB2.11@6350.6,8446.8
  Inner4 w4.7: v1(5143.2,3941.7) 5154.2,3952.6 5243.5,3952.6 5246.9,3956 5296,3956 5297.3,3957.2 5602.1,3957.2 5614.1,3969.3 6038.1,3969.3 6188.9,4120 6188.9,5415.3 6214.1,5440.5 6214.1,5727.3 6250.2,5763.4 6250.2,6127.6 6239.5,6138.3 6239.5,6192.5 6246.9,6199.9 6246.9,6229.3 6259.6,6242 6259.6,6246.7 6250.6,6255.7 6250.6,6619.2 6244.5,6625.2 6244.5,6653.3 6257.6,6666.3 6257.6,7112.1 6267.6,7122.1 6267.6,7150.2 6263.6,7154.3 6263.6,7280.7 6253.6,7290.8 6253.6,7543.8 6267.6,7557.8 v1(6267.6,8444.9)
SCK_DAC2_W(15): U6$CBB17/CBB2.11 U100$CBB22.C18 | length 6136.9
  Top Layer w4.7: v1(5129.2,3992.9) 5121.7,4000.4 5121.7,4164.8 5163.8,4206.9 5163.8,4361.8 5193.4,4391.4 5259.9,4391.4 U100$CBB22.C18@5260.4,4391.9
  Top Layer w7.9: U6$CBB17/CBB2.11@5720.7,8446.8 5722.8,8449 v1(5786.3,8449)
  Inner4 w4.7: v1(5129.2,3992.9) 5140.3,3981.8 5231.4,3981.8 5234.8,3985.2 5270.4,3985.2 5270.5,3985.1 5283.9,3985.1 5285.2,3986.4 5590,3986.4 5602,3998.4 6026.1,3998.4 6159.7,4132.1 6159.7,5422.6 5866.1,5716.3 5866.1,6238.7 5835.9,6268.8 5835.9,6552.5 5839.3,6555.9 5839.3,6593 5835.9,6596.4 5835.9,8254.6 5813.9,8276.7 5813.9,8322.8 5786.3,8350.4 v1(5786.3,8449)
SCK_DAC2_W(34): U6$CBB20/CBB2.11 U100$CBB22.C9 | length 6329
  Top Layer w7.9: v1(6853.4,8443.1) 6976.8,8443.1 U6$CBB20/CBB2.11@6980.5,8446.8
  Inner2 w4.7: v2(5490.7,4391.9) 5490.7,4391.5 5474.5,4375.4 5474.5,4242.2 5492.1,4224.6 5492.1,4185.9 5477.3,4171.1 5477.3,4158.5 5470.4,4151.6 5470.4,4130.1 5476.4,4124.1 5476.4,4123.7 5477,4123 5477,4122.7 5477.3,4122.5 5477.3,4078.8 5479.1,4076.9 5479.1,4023.2 5477.3,4021.4 5477.3,3928.5 5564.9,3840.9 5592.1,3840.9 5602.6,3851.5 5629.8,3851.5 5640.3,3840.9 5649.5,3840.9 5653.2,3837.2 5658,3837.2 v1(5663.6,3842.9)
  Inner4 w4.7: v1(5663.6,3842.9) 5671.9,3834.6 6041,3834.6 6287.2,4080.7 6287.2,5331.3 6409.1,5453.3 6662.5,5453.3 6739.8,5530.6 6739.8,6303.2 6777.6,6341 6777.6,8367.4 v1(6853.4,8443.1)
SCK_DAC3_DAC(2): U6$CBB16/CBB3.11 U100$CBB22.D17 | length 6571.3
  Top Layer w4.3: 5250.9,4404.5 5251.2,4404.8 5273.3,4404.8 U100$CBB22.D17@5285.9,4417.4
  Top Layer w4.7: v1(5118.7,3969.3) 5112,3976.1 5112,4168.8 5154.1,4211 5154.1,4365.9 5192.7,4404.5 5250.9,4404.5
  Top Layer w7.9: v1(5014.9,7992.2) 5093.8,7992.2 U6$CBB16/CBB3.11@5095.7,7994.1
  Inner2 w4.7: v1(5014.9,7992.2) 5106.4,7992.2 5183.4,7915.2 v1(5862,7915.2)
  Inner4 w4.7: v1(5118.7,3969.3) 5128.6,3969.3 5131.3,3972.1 5235.5,3972.1 5238.8,3975.4 5288,3975.4 5289.2,3976.7 5594,3976.7 5606.1,3988.7 6030.1,3988.7 6169.4,4128.1 6169.4,5426.7 5878.1,5718 5878.1,6250.7 5850,6278.8 5850,6513.7 5860,6523.8 5860,6545.9 5862,6547.9 v1(5862,7915.2)
SCK_DAC3_W(12): U6$CBB18/CBB3.11 U100$CBB22.D18 | length 5760.8
  Top Layer w4.7: v1(5111.7,3945.6) 5102.2,3955.1 5102.2,4172.8 5144.4,4215 5144.4,4369.9 5191.9,4417.4 U100$CBB22.D18@5260.4,4417.4
  Top Layer w7.9: v1(6229.5,7992.2) 6348.7,7992.2 U6$CBB18/CBB3.11@6350.6,7994.1
  Inner4 w4.7: v1(5111.7,3945.6) 5119.8,3945.6 5136.5,3962.4 5239.5,3962.4 5242.8,3965.7 5292,3965.7 5293.2,3966.9 5598.1,3966.9 5610.1,3979 6034.1,3979 6179.2,4124 6179.2,5419.3 6204.3,5444.5 6204.3,5773.8 6227.6,5797 6227.6,6118.2 6214.5,6131.4 6214.5,6242.2 6228,6255.7 6228,6576.7 6221.9,6582.7 6221.9,6666.1 6225.2,6669.3 6225.2,6691.4 6229.5,6695.7 6229.5,6718.5 6233.5,6722.6 6233.5,6778.3 6234.3,6779.1 6234.3,6792.5 6233.5,6793.4 6233.5,7231 6234.3,7231.9 6234.3,7245.3 6233.5,7246.1 6233.5,7254.6 6227.5,7260.7 6227.5,7596 6235.5,7604 6235.5,7720.5 6229.5,7726.5 v1(6229.5,7992.2)
SCK_DAC3_W(15): U6$CBB17/CBB3.11 U100$CBB22.A12 | length 5429.2
  Top Layer w4.7: v1(5277.2,4001.4) 5282.7,4006.9 5282.7,4089.1 5284.7,4091.1 5284.7,4097.6 5287.9,4100.8 5287.9,4107.7 5282.7,4113 5282.7,4140.5 5413.9,4271.7 U100$CBB22.A12@5413.9,4340.7
  Top Layer w7.9: U6$CBB17/CBB3.11@5720.7,7994.1 5722.6,7992.2 v1(5811.4,7992.2)
  Inner4 w4.7: v1(5277.2,4001.4) 5287.8,4001.4 5292.3,3996.9 5305.7,3996.9 5306,3997.2 5433.3,3997.2 5444.5,4008.4 6022.3,4008.4 6150,4136.1 6150,5418.6 5856,5712.6 5856,6234.5 5825.9,6264.6 5825.9,6556.2 5829.6,6559.9 5829.6,6589 5825.9,6592.7 5825.9,7987.5 5821.2,7992.2 v1(5811.4,7992.2)
SCK_DAC3_W(34): U6$CBB20/CBB3.11 U100$CBB22.H18 | length 6786.6
  Top Layer w4.7: v1(5115.1,3817.5) 5103.1,3817.5 5093.9,3808.3 5072.2,3808.3 5032.8,3847.7 5032.8,4200.7 5075,4242.8 5075,4398.7 5196.1,4519.8 U100$CBB22.H18@5260.4,4519.8
  Top Layer w7.9: v1(6857.4,7988.2) 6974.6,7988.2 U6$CBB20/CBB3.11@6980.5,7994.1
  Inner2 w4.7: v1(6524.6,7990.6) 6854.9,7990.6 v1(6857.4,7988.2)
  Inner4 w4.7: v1(5115.1,3817.5) 5140.8,3843.1 5149.9,3843.1 5156.1,3849.3 5175.2,3849.3 5220.2,3894.3 5267.7,3894.3 5271,3897.6 5284.5,3897.6 5287.8,3894.3 5303.3,3894.3 5306.6,3897.6 5320.2,3897.6 5321.4,3898.9 5626.2,3898.9 5638.3,3910.9 6062.3,3910.9 6247.6,4096.1 6247.6,5346.7 6394.3,5493.4 6506.3,5493.4 6639.8,5627 6639.8,6480.9 6570.8,6549.9 6570.8,7877.1 6524.6,7923.3 v1(6524.6,7990.6)
SCK_DAC4_DAC(2): U6$CBB16/CBB4.11 U100$CBB22.B11 | length 5452.1
  Top Layer w4.3: U100$CBB22.B11@5439.5,4366.3 5439.5,4358.5 5452.1,4345.9 5452.1,4331.5 5452.4,4331.2
  Top Layer w4.7: v1(5320.4,4082.8) 5320.4,4136.9 5452.4,4268.9 5452.4,4331.2
  Top Layer w7.9: U6$CBB16/CBB4.11@5095.7,7541.3 5169.8,7541.3 v1(5171.5,7543)
  Inner2 w4.7: v1(5223.4,5519.8) 5223.4,5514 5224,5513.3 5911.9,5513.3 5921.6,5503.6 5935.4,5503.6 5958.8,5480.1 v1(5988.5,5480.1)
  Inner4 w4.7: v1(5171.5,7543) 5197.4,7517.1 5197.4,7067.9 5235.6,7029.8 5235.6,6182.1 5222.2,6168.7 5222.2,6144.3 5229.9,6136.6 5229.9,5526.3 v1(5223.4,5519.8) ; v1(5320.4,4082.8) 5390.8,4082.8 5395.5,4078 5492.7,4078 5493.1,4077.6 5530.8,4077.6 5531.6,4078.4 6008.9,4078.4 6111.1,4180.7 6111.1,5357.6 v1(5988.5,5480.1)
SCK_DAC4_W(12): U6$CBB18/CBB4.11 U100$CBB22.F16 | length 5527.5
  Top Layer w3.9: 5242,4455.7 5298.6,4455.7 U100$CBB22.F16@5311.5,4468.6
  Top Layer w4.7: v1(5115.1,3899.5) 5107.9,3899.5 5097.7,3889.3 5084.3,3889.3 5072,3901.6 5072,4184.4 5114.2,4226.6 5114.2,4382.4 5187.4,4455.7 5242,4455.7
  Top Layer w7.9: v1(6269.9,7537.1) 6346.4,7537.1 U6$CBB18/CBB4.11@6350.6,7541.3
  Inner4 w4.7: v1(5115.1,3899.5) 5143.2,3899.5 5152,3908.2 5179.1,3908.2 5204,3933.2 5251.6,3933.2 5254.9,3936.5 5304.1,3936.5 5305.3,3937.8 5610.1,3937.8 5622.2,3949.8 6046.2,3949.8 6208.3,4111.9 6208.3,5407.2 6233.5,5432.4 6233.5,5713.2 6269.6,5749.3 6269.6,6150.3 6261.8,6158.1 6261.8,6187.3 6270.1,6195.6 6270.1,6225 6279.1,6233.9 6279.1,6254.7 6270.1,6263.7 6270.1,6611.6 6280.7,6622.2 6280.7,6649.3 6269.6,6660.3 6269.6,7110.4 6277.4,7118.1 6277.4,7154.3 6273.3,7158.3 6273.3,7284.8 6269.9,7288.2 v1(6269.9,7537.1)
SCK_DAC4_W(15): U6$CBB17/CBB4.11 U100$CBB22.D15 | length 5381.7
  Top Layer w7.9: U6$CBB17/CBB4.11@5720.7,7541.3 5722.6,7539.4 v1(5783.5,7539.4)
  Inner2 w3.9: 5280.5,4405 5280.9,4405.5 5305.4,4405.5 5306.2,4404.6 5316.8,4404.6 5317.7,4405.5 5325.2,4405.5 v2(5337.1,4417.4)
  Inner2 w4.7: v1(4618,5209.2) 4619.4,5210.6 5989.8,5210.6 v1(6023.9,5244.7) ; v1(4647.4,4566.1) 4808.1,4405.4 5279.2,4405.4 5279.6,4405 5280.5,4405
  Inner4 w4.7: v1(4618,5209.2) 4618.6,5208.6 4618.6,5060.2 4618.2,5059.8 4618.2,5022.2 4619.7,5020.6 4619.7,5013.3 4633.6,4999.5 4633.8,4999.5 4643.3,4990 4643.3,4989.8 4645.3,4987.8 4645.3,4951.6 4671.4,4925.5 4671.4,4785 4601.1,4714.7 4601.1,4691.6 4598.8,4689.3 4598.8,4675.8 4601.1,4673.5 4601.1,4612.4 v1(4647.4,4566.1) ; v1@5783.7,7539.8 5759.6,7515.7 5759.6,5719.4 5930,5549 5937.9,5549 5947.4,5539.5 5947.4,5531.6 5948.4,5530.7 5948.4,5368 6023.9,5292.5 v1(6023.9,5244.7)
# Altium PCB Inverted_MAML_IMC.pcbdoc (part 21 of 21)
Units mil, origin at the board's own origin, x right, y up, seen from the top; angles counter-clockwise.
Board outline 7677.1 x 6771.6 mil, 6 copper layers (Top Layer, Inner1, Inner2, Inner3, Inner4, Bottom Layer), stack 60.7 mil thick; 2732 components, 1531 nets, 7765 pads, 3701 vias.

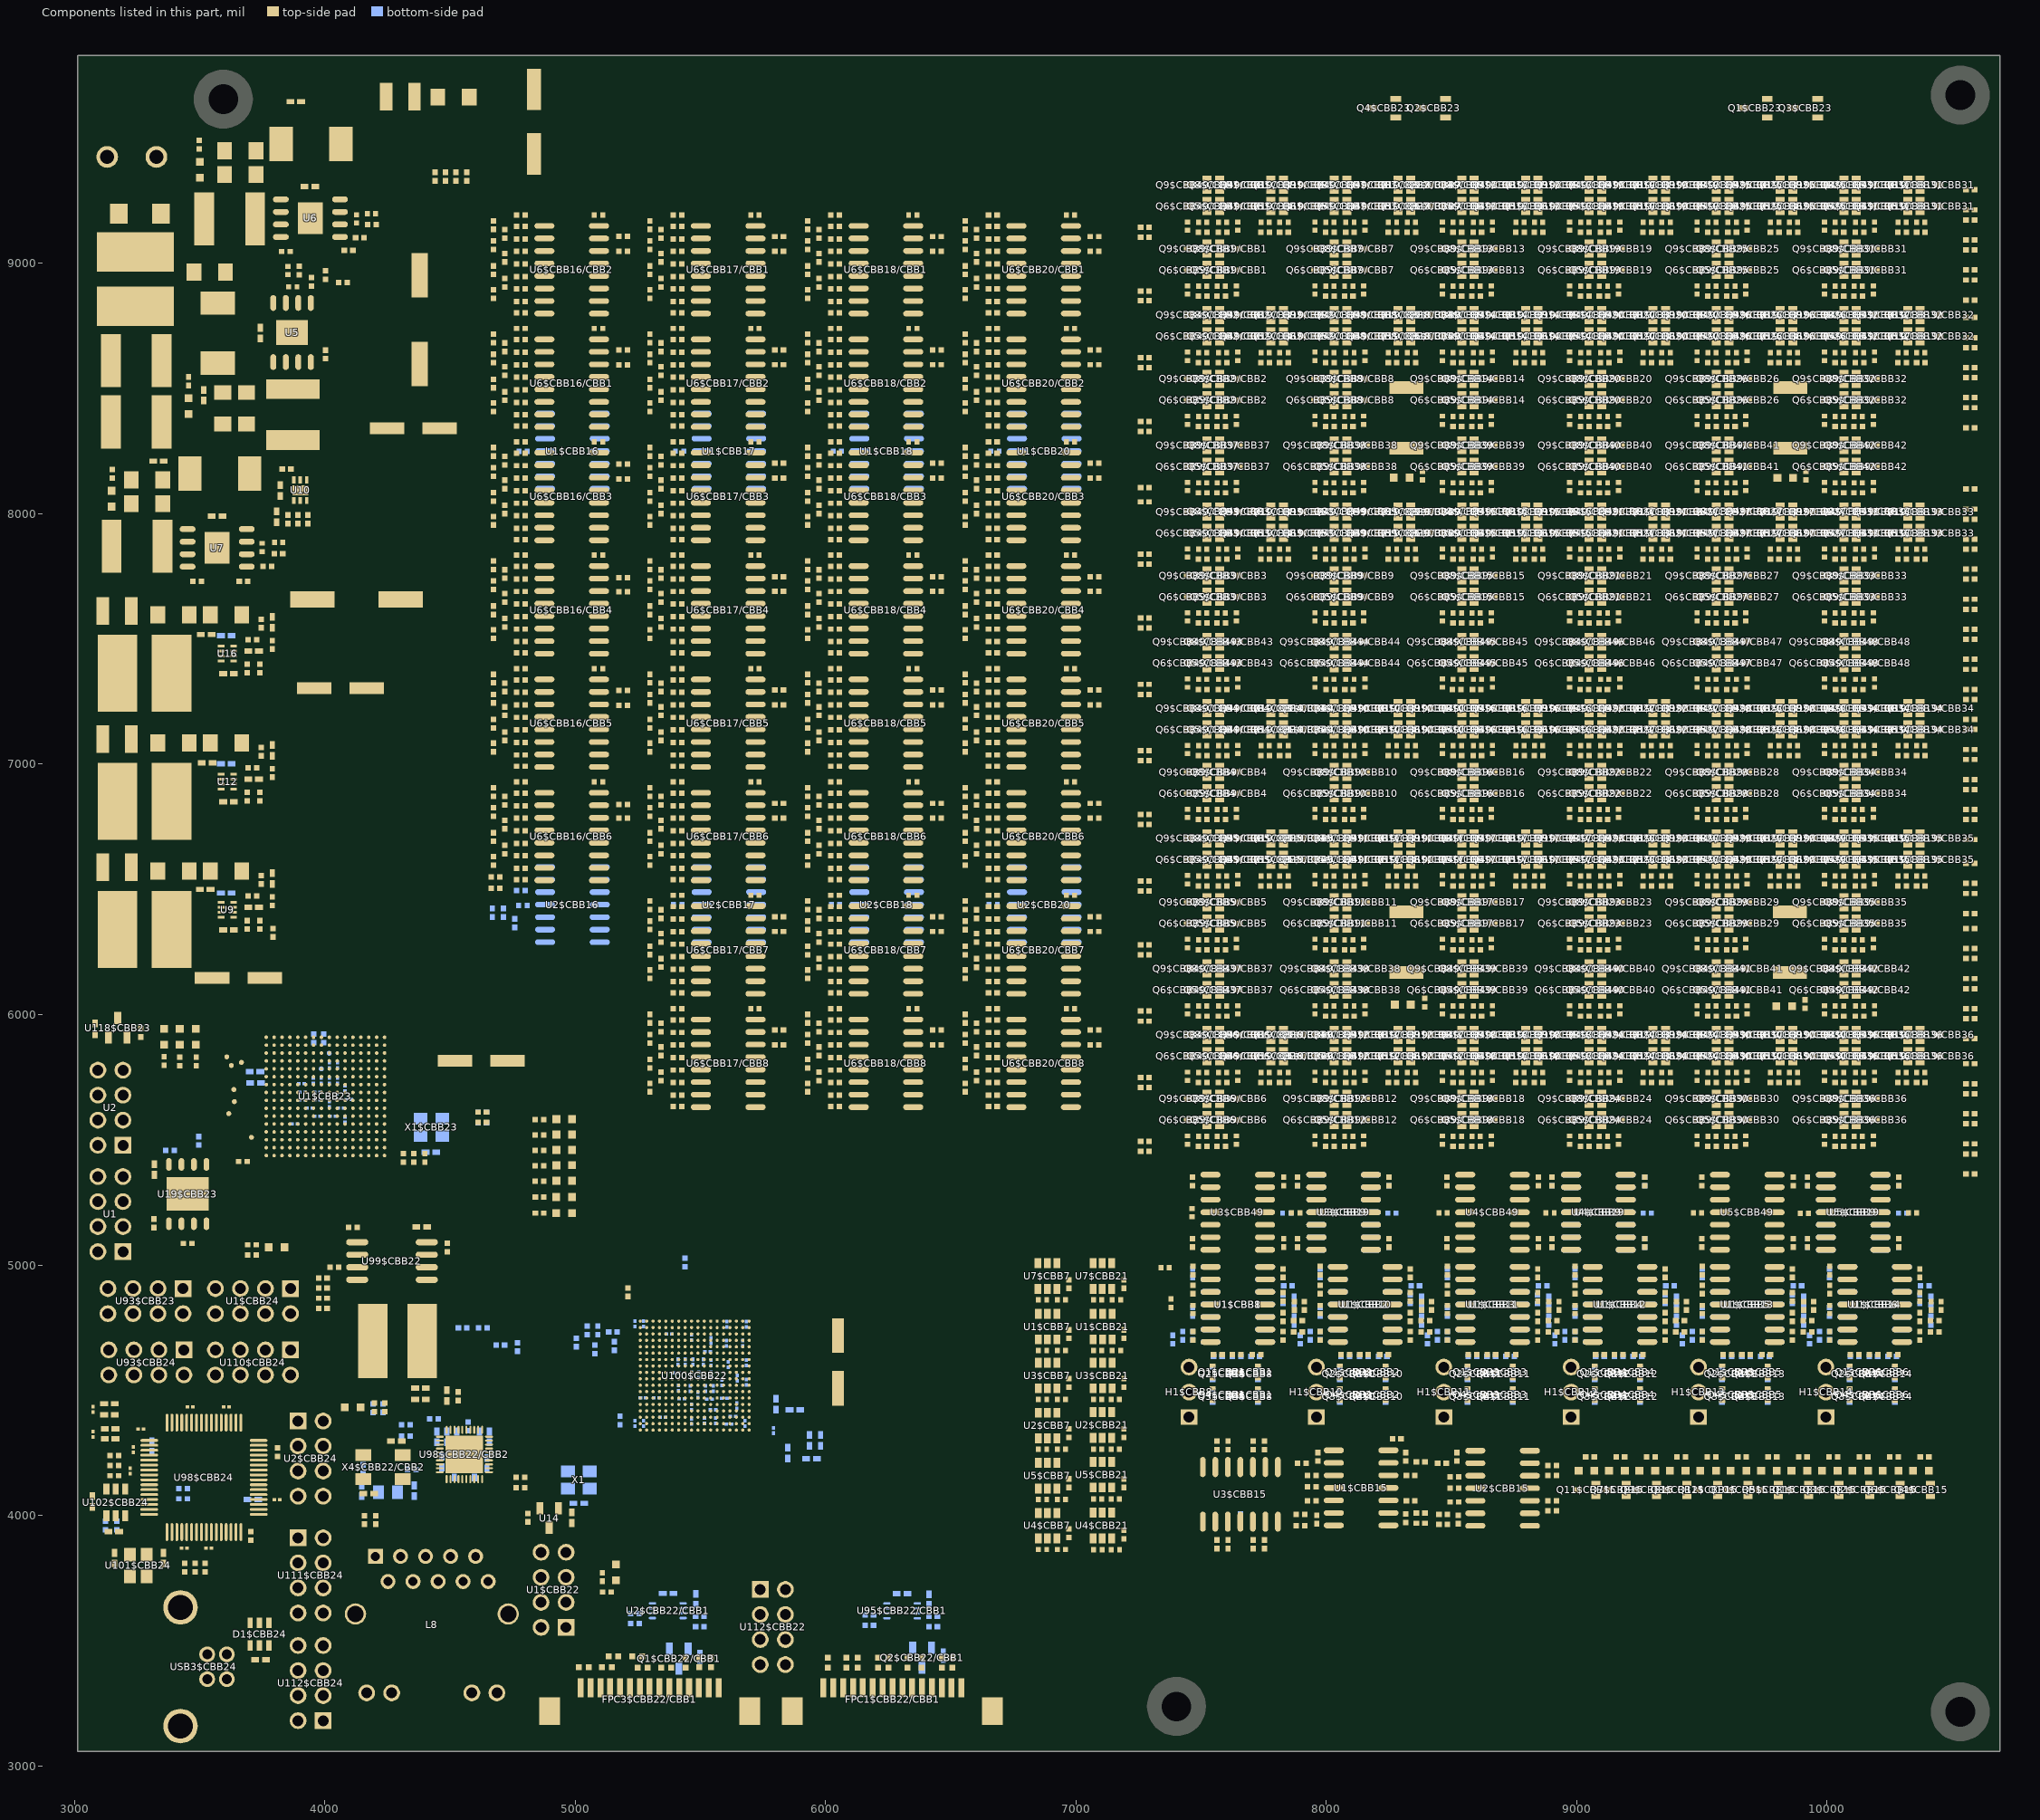
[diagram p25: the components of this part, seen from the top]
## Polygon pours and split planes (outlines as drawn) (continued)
3.3V on Inner2 (solid, remove dead copper): 7645.6,4087.6 7219,4087.6 7109.9,4196.7 7060.7,4196.7 7022.6,4234.8 7022.6,4281 7035.8,4294.2 7166,4294.2 7235.4,4224.8 7653.1,4224.8 7663.1,4214.7 7663.1,4105.1
3.3VD on Top Layer (solid, remove dead copper, pour order 58): 4687.4,5726.7 4685.4,5728.7 4685.4,5800.9 4687.4,5803 4763.7,5803 4765.7,5800.9 4765.7,5742.7 4749.7,5726.7
GND on Inner2 (solid, remove dead copper): 3012.9,9829.8 3012.9,3058.2 10690,3058.2 10690,9829.8
GND on Inner4 (solid, remove dead copper): 3012.9,9829.8 3012.9,3058.2 10690,3058.2 10690,9829.8

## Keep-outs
Top Layer:
  region: 9897.9,3321.2 9897.9,3139.8 10278.4,3139.8 10278.4,3321.2
  region: 5038.8,3357.4 5052.9,3371.4 5052.9,3569.2 5362.6,3878.9 5362.6,3919.9 5399.9,3957.2 5435.7,3957.2 5506.3,4027.7 5506.3,4322 5672.5,4322 5677.3,4317.1 5677.3,3919.6 5343.5,3585.7 5343.5,3392.4 5344.4,3391.5 5344.4,3379.1 5360.1,3363.4 5360.1,3263 5354.1,3257 5273.7,3257 5269.6,3261.1 5269.6,3350.5 5287.8,3368.7 5287.8,3522 5283.8,3526 5227.6,3526 5227.6,3403.3 5224.8,3400.6 5224.8,3377.9 5244.9,3357.8 5244.9,3265 5234.9,3255 5167.3,3255 5161.3,3261 5161.3,3349.3 5175.4,3363.4 5175.4,3377.4 5173.3,3379.4 5173.3,3526 5109.1,3526 5107.1,3524 5107.1,3373.4 5109.1,3373.4 5126.8,3355.7 5126.8,3265 5116.8,3255 5046.9,3255 5038.8,3263
  region: 4205.6,3682.4 4205.6,3932.9 4409.6,4136.9 4660.9,4136.9 4693.5,4104.3 4693.5,3847.3 4603.1,3756.9 4603.1,3678.6 4209.3,3678.6
Inner1:
  region: 9897.1,3321.2 9897.1,3138.7 10278.3,3138.7 10278.3,3321.2
Inner2:
  region: 9897.2,3321.2 9897.2,3139.7 10278.3,3139.7 10278.3,3321.2
Inner3:
  region: 9897.7,3321.2 9897.7,3139.7 10279.3,3139.7 10279.3,3321.2
Inner4:
  region: 9897.7,3321.2 9897.7,3138.7 10278.3,3138.7 10278.3,3321.2
Bottom Layer:
  region: 9897.9,3321.2 9897.9,3139.8 10278.4,3139.8 10278.4,3321.2
Board Outline Layer:
  the board outline again, w10

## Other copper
Top Layer:
  pour cut-out: 5242,4796.2 5242,4322.1 5716,4322.1 5716,4796.2
  pour cut-out: 3748.3,5928.7 3748.3,5418.4 4258.5,5418.4 4258.5,5928.7
  region net GND: 9954.3,3235.7 9889.9,3235.7 9889.9,3134.8 9954.3,3134.8
  text "1" at 9920.3,3243.7 h59.1
Inner1:
  pour cut-out: 5242,4796.2 5242,4322.1 5716,4322.1 5716,4796.2
  pour cut-out: 3748.3,5928.7 3748.3,5418.4 4258.5,5418.4 4258.5,5928.7
  region net GND: 10014.3,3215.7 9890.3,3215.7 9890.3,3127.7 10014.3,3127.7
  text "2" at 9976.3,3243.7 h59.1
Inner2:
  pour cut-out: 5242,4796.2 5242,4322.1 5716,4322.1 5716,4796.2
  pour cut-out: 3748.3,5928.7 3748.3,5418.4 4258.5,5418.4 4258.5,5928.7
  region net GND: 10075.3,3197.7 9890.3,3197.7 9890.3,3133.1 10075.3,3133.1
  text "3" at 10035.3,3242.7 h59.1
Inner3:
  pour cut-out: 5242,4796.2 5242,4322.1 5716,4322.1 5716,4796.2
  pour cut-out: 3748.3,5928.7 3748.3,5418.4 4258.5,5418.4 4258.5,5928.7
  region net GND: 10143.3,3178.7 9890.3,3178.7 9890.3,3133.6 10143.3,3133.6
  text "4" at 10096.3,3241.7 h59.1
Inner4:
  pour cut-out: 5242,4796.2 5242,4322.1 5716,4322.1 5716,4796.2
  pour cut-out: 3748.3,5928.7 3748.3,5418.4 4258.5,5418.4 4258.5,5928.7
  region net GND: 10209.3,3158.7 9890.3,3158.7 9890.3,3133.1 10209.3,3133.1
  text "5" at 10162.3,3241.7 h59.1
Bottom Layer:
  pour cut-out: 5242,4796.2 5242,4322.1 5716,4322.1 5716,4796.2
  pour cut-out: 3748.3,5928.7 3748.3,5418.4 4258.5,5418.4 4258.5,5928.7
  text "6" at 10229.3,3242.7 h59.1

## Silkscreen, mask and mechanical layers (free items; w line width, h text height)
Top Silkscreen Layer:
  lines w5.9: 3370.3,6110.2 3392.4,6110.2 3421.3,6081.3 3421.3,5987
  lines w11.8: 4057,4275 4101.1,4275 4109.2,4283
  text "GND" at 3059.1,9575.7 h59.1
  text "+12V" at 3267.9,9575.7 h59.1
  text "Inverted MAML Analog 2T1C Matrix (6x6) / Matrix Multiplication with Proprioception / Proof-of-Concept PCB for Future ASIC | Patent Pending: SE 2630397-4" at 5066.9,9190.2 h120
  text "DONE T20" at 3605.2,5108.2 h51.2
  text "T20 / JTAG" at 3994.7,4977.7 h51.2 r90
  text "T120 / JTAG" at 4030.9,4546 h51.2 r90
  text "JTAG PROG" at 3183.5,4451.7 h51.2
  text "T20 / RES" at 4085.1,4285 h51.2
  text "T120 / RES" at 3715.6,3756.9 h51.2
  text "Source code and documentation link: / https://github.com/ollewelin/analog_matrix_computation_Inverted_MAML_PAT_PEND_2630397-4" at 6855.9,3481.9 h78.7
  text "Layer Order" at 9909.3,3329.7 h59.1
  text "Inventor and designer : Olle Welin / Inverted_MAML_IMC version 1.2 / Date: 2026-09-04 21:49" at 7815.7,3084.3 h120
